VERSION 5.8 ;
BUSBITCHARS "[]" ;
DIVIDERCHAR "/" ;
UNITS
    DATABASE MICRONS 1000 ;
END UNITS

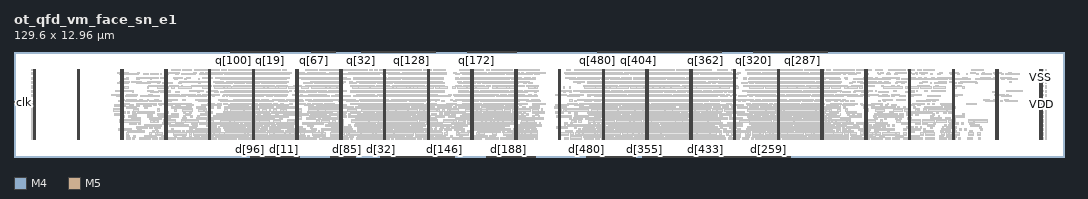
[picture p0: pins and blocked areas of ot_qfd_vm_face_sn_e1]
MACRO ot_qfd_vm_face_sn_e1
  FOREIGN ot_qfd_vm_face_sn_e1 0 0 ;
  CLASS BLOCK ;
  SIZE 129.6 BY 12.96 ;
  PIN clk
    DIRECTION INPUT ;
    USE SIGNAL ;
    PORT
      LAYER M4 ;
        RECT  0 6.672 0.084 6.696 ;
    END
  END clk
  PIN d[0]
    DIRECTION INPUT ;
    USE SIGNAL ;
    PORT
      LAYER M5 ;
        RECT  32.208 0 32.232 0.084 ;
    END
  END d[0]
  PIN d[100]
    DIRECTION INPUT ;
    USE SIGNAL ;
    PORT
      LAYER M5 ;
        RECT  29.52 0 29.544 0.084 ;
    END
  END d[100]
  PIN d[101]
    DIRECTION INPUT ;
    USE SIGNAL ;
    PORT
      LAYER M5 ;
        RECT  29.616 0 29.64 0.084 ;
    END
  END d[101]
  PIN d[102]
    DIRECTION INPUT ;
    USE SIGNAL ;
    PORT
      LAYER M5 ;
        RECT  29.712 0 29.736 0.084 ;
    END
  END d[102]
  PIN d[103]
    DIRECTION INPUT ;
    USE SIGNAL ;
    PORT
      LAYER M5 ;
        RECT  29.808 0 29.832 0.084 ;
    END
  END d[103]
  PIN d[104]
    DIRECTION INPUT ;
    USE SIGNAL ;
    PORT
      LAYER M5 ;
        RECT  29.904 0 29.928 0.084 ;
    END
  END d[104]
  PIN d[105]
    DIRECTION INPUT ;
    USE SIGNAL ;
    PORT
      LAYER M5 ;
        RECT  30 0 30.024 0.084 ;
    END
  END d[105]
  PIN d[106]
    DIRECTION INPUT ;
    USE SIGNAL ;
    PORT
      LAYER M5 ;
        RECT  30.096 0 30.12 0.084 ;
    END
  END d[106]
  PIN d[107]
    DIRECTION INPUT ;
    USE SIGNAL ;
    PORT
      LAYER M5 ;
        RECT  30.192 0 30.216 0.084 ;
    END
  END d[107]
  PIN d[108]
    DIRECTION INPUT ;
    USE SIGNAL ;
    PORT
      LAYER M5 ;
        RECT  30.288 0 30.312 0.084 ;
    END
  END d[108]
  PIN d[109]
    DIRECTION INPUT ;
    USE SIGNAL ;
    PORT
      LAYER M5 ;
        RECT  30.384 0 30.408 0.084 ;
    END
  END d[109]
  PIN d[10]
    DIRECTION INPUT ;
    USE SIGNAL ;
    PORT
      LAYER M5 ;
        RECT  33.168 0 33.192 0.084 ;
    END
  END d[10]
  PIN d[110]
    DIRECTION INPUT ;
    USE SIGNAL ;
    PORT
      LAYER M5 ;
        RECT  30.48 0 30.504 0.084 ;
    END
  END d[110]
  PIN d[111]
    DIRECTION INPUT ;
    USE SIGNAL ;
    PORT
      LAYER M5 ;
        RECT  30.576 0 30.6 0.084 ;
    END
  END d[111]
  PIN d[112]
    DIRECTION INPUT ;
    USE SIGNAL ;
    PORT
      LAYER M5 ;
        RECT  30.672 0 30.696 0.084 ;
    END
  END d[112]
  PIN d[113]
    DIRECTION INPUT ;
    USE SIGNAL ;
    PORT
      LAYER M5 ;
        RECT  30.768 0 30.792 0.084 ;
    END
  END d[113]
  PIN d[114]
    DIRECTION INPUT ;
    USE SIGNAL ;
    PORT
      LAYER M5 ;
        RECT  30.864 0 30.888 0.084 ;
    END
  END d[114]
  PIN d[115]
    DIRECTION INPUT ;
    USE SIGNAL ;
    PORT
      LAYER M5 ;
        RECT  30.96 0 30.984 0.084 ;
    END
  END d[115]
  PIN d[116]
    DIRECTION INPUT ;
    USE SIGNAL ;
    PORT
      LAYER M5 ;
        RECT  31.056 0 31.08 0.084 ;
    END
  END d[116]
  PIN d[117]
    DIRECTION INPUT ;
    USE SIGNAL ;
    PORT
      LAYER M5 ;
        RECT  31.152 0 31.176 0.084 ;
    END
  END d[117]
  PIN d[118]
    DIRECTION INPUT ;
    USE SIGNAL ;
    PORT
      LAYER M5 ;
        RECT  31.248 0 31.272 0.084 ;
    END
  END d[118]
  PIN d[119]
    DIRECTION INPUT ;
    USE SIGNAL ;
    PORT
      LAYER M5 ;
        RECT  31.344 0 31.368 0.084 ;
    END
  END d[119]
  PIN d[11]
    DIRECTION INPUT ;
    USE SIGNAL ;
    PORT
      LAYER M5 ;
        RECT  33.264 0 33.288 0.084 ;
    END
  END d[11]
  PIN d[120]
    DIRECTION INPUT ;
    USE SIGNAL ;
    PORT
      LAYER M5 ;
        RECT  31.44 0 31.464 0.084 ;
    END
  END d[120]
  PIN d[121]
    DIRECTION INPUT ;
    USE SIGNAL ;
    PORT
      LAYER M5 ;
        RECT  31.536 0 31.56 0.084 ;
    END
  END d[121]
  PIN d[122]
    DIRECTION INPUT ;
    USE SIGNAL ;
    PORT
      LAYER M5 ;
        RECT  31.632 0 31.656 0.084 ;
    END
  END d[122]
  PIN d[123]
    DIRECTION INPUT ;
    USE SIGNAL ;
    PORT
      LAYER M5 ;
        RECT  31.728 0 31.752 0.084 ;
    END
  END d[123]
  PIN d[124]
    DIRECTION INPUT ;
    USE SIGNAL ;
    PORT
      LAYER M5 ;
        RECT  31.824 0 31.848 0.084 ;
    END
  END d[124]
  PIN d[125]
    DIRECTION INPUT ;
    USE SIGNAL ;
    PORT
      LAYER M5 ;
        RECT  31.92 0 31.944 0.084 ;
    END
  END d[125]
  PIN d[126]
    DIRECTION INPUT ;
    USE SIGNAL ;
    PORT
      LAYER M5 ;
        RECT  32.016 0 32.04 0.084 ;
    END
  END d[126]
  PIN d[127]
    DIRECTION INPUT ;
    USE SIGNAL ;
    PORT
      LAYER M5 ;
        RECT  32.112 0 32.136 0.084 ;
    END
  END d[127]
  PIN d[128]
    DIRECTION INPUT ;
    USE SIGNAL ;
    PORT
      LAYER M5 ;
        RECT  51.408 0 51.432 0.084 ;
    END
  END d[128]
  PIN d[129]
    DIRECTION INPUT ;
    USE SIGNAL ;
    PORT
      LAYER M5 ;
        RECT  51.504 0 51.528 0.084 ;
    END
  END d[129]
  PIN d[12]
    DIRECTION INPUT ;
    USE SIGNAL ;
    PORT
      LAYER M5 ;
        RECT  33.36 0 33.384 0.084 ;
    END
  END d[12]
  PIN d[130]
    DIRECTION INPUT ;
    USE SIGNAL ;
    PORT
      LAYER M5 ;
        RECT  51.6 0 51.624 0.084 ;
    END
  END d[130]
  PIN d[131]
    DIRECTION INPUT ;
    USE SIGNAL ;
    PORT
      LAYER M5 ;
        RECT  51.696 0 51.72 0.084 ;
    END
  END d[131]
  PIN d[132]
    DIRECTION INPUT ;
    USE SIGNAL ;
    PORT
      LAYER M5 ;
        RECT  51.792 0 51.816 0.084 ;
    END
  END d[132]
  PIN d[133]
    DIRECTION INPUT ;
    USE SIGNAL ;
    PORT
      LAYER M5 ;
        RECT  51.888 0 51.912 0.084 ;
    END
  END d[133]
  PIN d[134]
    DIRECTION INPUT ;
    USE SIGNAL ;
    PORT
      LAYER M5 ;
        RECT  51.984 0 52.008 0.084 ;
    END
  END d[134]
  PIN d[135]
    DIRECTION INPUT ;
    USE SIGNAL ;
    PORT
      LAYER M5 ;
        RECT  52.08 0 52.104 0.084 ;
    END
  END d[135]
  PIN d[136]
    DIRECTION INPUT ;
    USE SIGNAL ;
    PORT
      LAYER M5 ;
        RECT  52.176 0 52.2 0.084 ;
    END
  END d[136]
  PIN d[137]
    DIRECTION INPUT ;
    USE SIGNAL ;
    PORT
      LAYER M5 ;
        RECT  52.272 0 52.296 0.084 ;
    END
  END d[137]
  PIN d[138]
    DIRECTION INPUT ;
    USE SIGNAL ;
    PORT
      LAYER M5 ;
        RECT  52.368 0 52.392 0.084 ;
    END
  END d[138]
  PIN d[139]
    DIRECTION INPUT ;
    USE SIGNAL ;
    PORT
      LAYER M5 ;
        RECT  52.464 0 52.488 0.084 ;
    END
  END d[139]
  PIN d[13]
    DIRECTION INPUT ;
    USE SIGNAL ;
    PORT
      LAYER M5 ;
        RECT  33.456 0 33.48 0.084 ;
    END
  END d[13]
  PIN d[140]
    DIRECTION INPUT ;
    USE SIGNAL ;
    PORT
      LAYER M5 ;
        RECT  52.56 0 52.584 0.084 ;
    END
  END d[140]
  PIN d[141]
    DIRECTION INPUT ;
    USE SIGNAL ;
    PORT
      LAYER M5 ;
        RECT  52.656 0 52.68 0.084 ;
    END
  END d[141]
  PIN d[142]
    DIRECTION INPUT ;
    USE SIGNAL ;
    PORT
      LAYER M5 ;
        RECT  52.752 0 52.776 0.084 ;
    END
  END d[142]
  PIN d[143]
    DIRECTION INPUT ;
    USE SIGNAL ;
    PORT
      LAYER M5 ;
        RECT  52.848 0 52.872 0.084 ;
    END
  END d[143]
  PIN d[144]
    DIRECTION INPUT ;
    USE SIGNAL ;
    PORT
      LAYER M5 ;
        RECT  52.944 0 52.968 0.084 ;
    END
  END d[144]
  PIN d[145]
    DIRECTION INPUT ;
    USE SIGNAL ;
    PORT
      LAYER M5 ;
        RECT  53.04 0 53.064 0.084 ;
    END
  END d[145]
  PIN d[146]
    DIRECTION INPUT ;
    USE SIGNAL ;
    PORT
      LAYER M5 ;
        RECT  53.136 0 53.16 0.084 ;
    END
  END d[146]
  PIN d[147]
    DIRECTION INPUT ;
    USE SIGNAL ;
    PORT
      LAYER M5 ;
        RECT  53.232 0 53.256 0.084 ;
    END
  END d[147]
  PIN d[148]
    DIRECTION INPUT ;
    USE SIGNAL ;
    PORT
      LAYER M5 ;
        RECT  53.328 0 53.352 0.084 ;
    END
  END d[148]
  PIN d[149]
    DIRECTION INPUT ;
    USE SIGNAL ;
    PORT
      LAYER M5 ;
        RECT  53.424 0 53.448 0.084 ;
    END
  END d[149]
  PIN d[14]
    DIRECTION INPUT ;
    USE SIGNAL ;
    PORT
      LAYER M5 ;
        RECT  33.552 0 33.576 0.084 ;
    END
  END d[14]
  PIN d[150]
    DIRECTION INPUT ;
    USE SIGNAL ;
    PORT
      LAYER M5 ;
        RECT  53.52 0 53.544 0.084 ;
    END
  END d[150]
  PIN d[151]
    DIRECTION INPUT ;
    USE SIGNAL ;
    PORT
      LAYER M5 ;
        RECT  53.616 0 53.64 0.084 ;
    END
  END d[151]
  PIN d[152]
    DIRECTION INPUT ;
    USE SIGNAL ;
    PORT
      LAYER M5 ;
        RECT  53.712 0 53.736 0.084 ;
    END
  END d[152]
  PIN d[153]
    DIRECTION INPUT ;
    USE SIGNAL ;
    PORT
      LAYER M5 ;
        RECT  53.808 0 53.832 0.084 ;
    END
  END d[153]
  PIN d[154]
    DIRECTION INPUT ;
    USE SIGNAL ;
    PORT
      LAYER M5 ;
        RECT  53.904 0 53.928 0.084 ;
    END
  END d[154]
  PIN d[155]
    DIRECTION INPUT ;
    USE SIGNAL ;
    PORT
      LAYER M5 ;
        RECT  54 0 54.024 0.084 ;
    END
  END d[155]
  PIN d[156]
    DIRECTION INPUT ;
    USE SIGNAL ;
    PORT
      LAYER M5 ;
        RECT  54.096 0 54.12 0.084 ;
    END
  END d[156]
  PIN d[157]
    DIRECTION INPUT ;
    USE SIGNAL ;
    PORT
      LAYER M5 ;
        RECT  54.192 0 54.216 0.084 ;
    END
  END d[157]
  PIN d[158]
    DIRECTION INPUT ;
    USE SIGNAL ;
    PORT
      LAYER M5 ;
        RECT  54.288 0 54.312 0.084 ;
    END
  END d[158]
  PIN d[159]
    DIRECTION INPUT ;
    USE SIGNAL ;
    PORT
      LAYER M5 ;
        RECT  54.384 0 54.408 0.084 ;
    END
  END d[159]
  PIN d[15]
    DIRECTION INPUT ;
    USE SIGNAL ;
    PORT
      LAYER M5 ;
        RECT  33.648 0 33.672 0.084 ;
    END
  END d[15]
  PIN d[160]
    DIRECTION INPUT ;
    USE SIGNAL ;
    PORT
      LAYER M5 ;
        RECT  58.32 0 58.344 0.084 ;
    END
  END d[160]
  PIN d[161]
    DIRECTION INPUT ;
    USE SIGNAL ;
    PORT
      LAYER M5 ;
        RECT  58.416 0 58.44 0.084 ;
    END
  END d[161]
  PIN d[162]
    DIRECTION INPUT ;
    USE SIGNAL ;
    PORT
      LAYER M5 ;
        RECT  58.512 0 58.536 0.084 ;
    END
  END d[162]
  PIN d[163]
    DIRECTION INPUT ;
    USE SIGNAL ;
    PORT
      LAYER M5 ;
        RECT  58.608 0 58.632 0.084 ;
    END
  END d[163]
  PIN d[164]
    DIRECTION INPUT ;
    USE SIGNAL ;
    PORT
      LAYER M5 ;
        RECT  58.704 0 58.728 0.084 ;
    END
  END d[164]
  PIN d[165]
    DIRECTION INPUT ;
    USE SIGNAL ;
    PORT
      LAYER M5 ;
        RECT  58.8 0 58.824 0.084 ;
    END
  END d[165]
  PIN d[166]
    DIRECTION INPUT ;
    USE SIGNAL ;
    PORT
      LAYER M5 ;
        RECT  58.896 0 58.92 0.084 ;
    END
  END d[166]
  PIN d[167]
    DIRECTION INPUT ;
    USE SIGNAL ;
    PORT
      LAYER M5 ;
        RECT  58.992 0 59.016 0.084 ;
    END
  END d[167]
  PIN d[168]
    DIRECTION INPUT ;
    USE SIGNAL ;
    PORT
      LAYER M5 ;
        RECT  59.088 0 59.112 0.084 ;
    END
  END d[168]
  PIN d[169]
    DIRECTION INPUT ;
    USE SIGNAL ;
    PORT
      LAYER M5 ;
        RECT  59.184 0 59.208 0.084 ;
    END
  END d[169]
  PIN d[16]
    DIRECTION INPUT ;
    USE SIGNAL ;
    PORT
      LAYER M5 ;
        RECT  33.744 0 33.768 0.084 ;
    END
  END d[16]
  PIN d[170]
    DIRECTION INPUT ;
    USE SIGNAL ;
    PORT
      LAYER M5 ;
        RECT  59.28 0 59.304 0.084 ;
    END
  END d[170]
  PIN d[171]
    DIRECTION INPUT ;
    USE SIGNAL ;
    PORT
      LAYER M5 ;
        RECT  59.376 0 59.4 0.084 ;
    END
  END d[171]
  PIN d[172]
    DIRECTION INPUT ;
    USE SIGNAL ;
    PORT
      LAYER M5 ;
        RECT  59.472 0 59.496 0.084 ;
    END
  END d[172]
  PIN d[173]
    DIRECTION INPUT ;
    USE SIGNAL ;
    PORT
      LAYER M5 ;
        RECT  59.568 0 59.592 0.084 ;
    END
  END d[173]
  PIN d[174]
    DIRECTION INPUT ;
    USE SIGNAL ;
    PORT
      LAYER M5 ;
        RECT  59.664 0 59.688 0.084 ;
    END
  END d[174]
  PIN d[175]
    DIRECTION INPUT ;
    USE SIGNAL ;
    PORT
      LAYER M5 ;
        RECT  59.76 0 59.784 0.084 ;
    END
  END d[175]
  PIN d[176]
    DIRECTION INPUT ;
    USE SIGNAL ;
    PORT
      LAYER M5 ;
        RECT  59.856 0 59.88 0.084 ;
    END
  END d[176]
  PIN d[177]
    DIRECTION INPUT ;
    USE SIGNAL ;
    PORT
      LAYER M5 ;
        RECT  59.952 0 59.976 0.084 ;
    END
  END d[177]
  PIN d[178]
    DIRECTION INPUT ;
    USE SIGNAL ;
    PORT
      LAYER M5 ;
        RECT  60.048 0 60.072 0.084 ;
    END
  END d[178]
  PIN d[179]
    DIRECTION INPUT ;
    USE SIGNAL ;
    PORT
      LAYER M5 ;
        RECT  60.144 0 60.168 0.084 ;
    END
  END d[179]
  PIN d[17]
    DIRECTION INPUT ;
    USE SIGNAL ;
    PORT
      LAYER M5 ;
        RECT  33.84 0 33.864 0.084 ;
    END
  END d[17]
  PIN d[180]
    DIRECTION INPUT ;
    USE SIGNAL ;
    PORT
      LAYER M5 ;
        RECT  60.24 0 60.264 0.084 ;
    END
  END d[180]
  PIN d[181]
    DIRECTION INPUT ;
    USE SIGNAL ;
    PORT
      LAYER M5 ;
        RECT  60.336 0 60.36 0.084 ;
    END
  END d[181]
  PIN d[182]
    DIRECTION INPUT ;
    USE SIGNAL ;
    PORT
      LAYER M5 ;
        RECT  60.432 0 60.456 0.084 ;
    END
  END d[182]
  PIN d[183]
    DIRECTION INPUT ;
    USE SIGNAL ;
    PORT
      LAYER M5 ;
        RECT  60.528 0 60.552 0.084 ;
    END
  END d[183]
  PIN d[184]
    DIRECTION INPUT ;
    USE SIGNAL ;
    PORT
      LAYER M5 ;
        RECT  60.624 0 60.648 0.084 ;
    END
  END d[184]
  PIN d[185]
    DIRECTION INPUT ;
    USE SIGNAL ;
    PORT
      LAYER M5 ;
        RECT  60.72 0 60.744 0.084 ;
    END
  END d[185]
  PIN d[186]
    DIRECTION INPUT ;
    USE SIGNAL ;
    PORT
      LAYER M5 ;
        RECT  60.816 0 60.84 0.084 ;
    END
  END d[186]
  PIN d[187]
    DIRECTION INPUT ;
    USE SIGNAL ;
    PORT
      LAYER M5 ;
        RECT  60.912 0 60.936 0.084 ;
    END
  END d[187]
  PIN d[188]
    DIRECTION INPUT ;
    USE SIGNAL ;
    PORT
      LAYER M5 ;
        RECT  61.008 0 61.032 0.084 ;
    END
  END d[188]
  PIN d[189]
    DIRECTION INPUT ;
    USE SIGNAL ;
    PORT
      LAYER M5 ;
        RECT  61.104 0 61.128 0.084 ;
    END
  END d[189]
  PIN d[18]
    DIRECTION INPUT ;
    USE SIGNAL ;
    PORT
      LAYER M5 ;
        RECT  33.936 0 33.96 0.084 ;
    END
  END d[18]
  PIN d[190]
    DIRECTION INPUT ;
    USE SIGNAL ;
    PORT
      LAYER M5 ;
        RECT  61.2 0 61.224 0.084 ;
    END
  END d[190]
  PIN d[191]
    DIRECTION INPUT ;
    USE SIGNAL ;
    PORT
      LAYER M5 ;
        RECT  61.296 0 61.32 0.084 ;
    END
  END d[191]
  PIN d[192]
    DIRECTION INPUT ;
    USE SIGNAL ;
    PORT
      LAYER M5 ;
        RECT  61.392 0 61.416 0.084 ;
    END
  END d[192]
  PIN d[193]
    DIRECTION INPUT ;
    USE SIGNAL ;
    PORT
      LAYER M5 ;
        RECT  61.488 0 61.512 0.084 ;
    END
  END d[193]
  PIN d[194]
    DIRECTION INPUT ;
    USE SIGNAL ;
    PORT
      LAYER M5 ;
        RECT  61.584 0 61.608 0.084 ;
    END
  END d[194]
  PIN d[195]
    DIRECTION INPUT ;
    USE SIGNAL ;
    PORT
      LAYER M5 ;
        RECT  61.68 0 61.704 0.084 ;
    END
  END d[195]
  PIN d[196]
    DIRECTION INPUT ;
    USE SIGNAL ;
    PORT
      LAYER M5 ;
        RECT  61.776 0 61.8 0.084 ;
    END
  END d[196]
  PIN d[197]
    DIRECTION INPUT ;
    USE SIGNAL ;
    PORT
      LAYER M5 ;
        RECT  61.872 0 61.896 0.084 ;
    END
  END d[197]
  PIN d[198]
    DIRECTION INPUT ;
    USE SIGNAL ;
    PORT
      LAYER M5 ;
        RECT  61.968 0 61.992 0.084 ;
    END
  END d[198]
  PIN d[199]
    DIRECTION INPUT ;
    USE SIGNAL ;
    PORT
      LAYER M5 ;
        RECT  62.064 0 62.088 0.084 ;
    END
  END d[199]
  PIN d[19]
    DIRECTION INPUT ;
    USE SIGNAL ;
    PORT
      LAYER M5 ;
        RECT  34.032 0 34.056 0.084 ;
    END
  END d[19]
  PIN d[1]
    DIRECTION INPUT ;
    USE SIGNAL ;
    PORT
      LAYER M5 ;
        RECT  32.304 0 32.328 0.084 ;
    END
  END d[1]
  PIN d[200]
    DIRECTION INPUT ;
    USE SIGNAL ;
    PORT
      LAYER M5 ;
        RECT  62.16 0 62.184 0.084 ;
    END
  END d[200]
  PIN d[201]
    DIRECTION INPUT ;
    USE SIGNAL ;
    PORT
      LAYER M5 ;
        RECT  62.256 0 62.28 0.084 ;
    END
  END d[201]
  PIN d[202]
    DIRECTION INPUT ;
    USE SIGNAL ;
    PORT
      LAYER M5 ;
        RECT  62.352 0 62.376 0.084 ;
    END
  END d[202]
  PIN d[203]
    DIRECTION INPUT ;
    USE SIGNAL ;
    PORT
      LAYER M5 ;
        RECT  62.448 0 62.472 0.084 ;
    END
  END d[203]
  PIN d[204]
    DIRECTION INPUT ;
    USE SIGNAL ;
    PORT
      LAYER M5 ;
        RECT  62.544 0 62.568 0.084 ;
    END
  END d[204]
  PIN d[205]
    DIRECTION INPUT ;
    USE SIGNAL ;
    PORT
      LAYER M5 ;
        RECT  62.64 0 62.664 0.084 ;
    END
  END d[205]
  PIN d[206]
    DIRECTION INPUT ;
    USE SIGNAL ;
    PORT
      LAYER M5 ;
        RECT  62.736 0 62.76 0.084 ;
    END
  END d[206]
  PIN d[207]
    DIRECTION INPUT ;
    USE SIGNAL ;
    PORT
      LAYER M5 ;
        RECT  62.832 0 62.856 0.084 ;
    END
  END d[207]
  PIN d[208]
    DIRECTION INPUT ;
    USE SIGNAL ;
    PORT
      LAYER M5 ;
        RECT  62.928 0 62.952 0.084 ;
    END
  END d[208]
  PIN d[209]
    DIRECTION INPUT ;
    USE SIGNAL ;
    PORT
      LAYER M5 ;
        RECT  63.024 0 63.048 0.084 ;
    END
  END d[209]
  PIN d[20]
    DIRECTION INPUT ;
    USE SIGNAL ;
    PORT
      LAYER M5 ;
        RECT  34.128 0 34.152 0.084 ;
    END
  END d[20]
  PIN d[210]
    DIRECTION INPUT ;
    USE SIGNAL ;
    PORT
      LAYER M5 ;
        RECT  63.12 0 63.144 0.084 ;
    END
  END d[210]
  PIN d[211]
    DIRECTION INPUT ;
    USE SIGNAL ;
    PORT
      LAYER M5 ;
        RECT  63.216 0 63.24 0.084 ;
    END
  END d[211]
  PIN d[212]
    DIRECTION INPUT ;
    USE SIGNAL ;
    PORT
      LAYER M5 ;
        RECT  63.312 0 63.336 0.084 ;
    END
  END d[212]
  PIN d[213]
    DIRECTION INPUT ;
    USE SIGNAL ;
    PORT
      LAYER M5 ;
        RECT  63.408 0 63.432 0.084 ;
    END
  END d[213]
  PIN d[214]
    DIRECTION INPUT ;
    USE SIGNAL ;
    PORT
      LAYER M5 ;
        RECT  63.504 0 63.528 0.084 ;
    END
  END d[214]
  PIN d[215]
    DIRECTION INPUT ;
    USE SIGNAL ;
    PORT
      LAYER M5 ;
        RECT  63.6 0 63.624 0.084 ;
    END
  END d[215]
  PIN d[216]
    DIRECTION INPUT ;
    USE SIGNAL ;
    PORT
      LAYER M5 ;
        RECT  63.696 0 63.72 0.084 ;
    END
  END d[216]
  PIN d[217]
    DIRECTION INPUT ;
    USE SIGNAL ;
    PORT
      LAYER M5 ;
        RECT  63.792 0 63.816 0.084 ;
    END
  END d[217]
  PIN d[218]
    DIRECTION INPUT ;
    USE SIGNAL ;
    PORT
      LAYER M5 ;
        RECT  63.888 0 63.912 0.084 ;
    END
  END d[218]
  PIN d[219]
    DIRECTION INPUT ;
    USE SIGNAL ;
    PORT
      LAYER M5 ;
        RECT  63.984 0 64.008 0.084 ;
    END
  END d[219]
  PIN d[21]
    DIRECTION INPUT ;
    USE SIGNAL ;
    PORT
      LAYER M5 ;
        RECT  34.224 0 34.248 0.084 ;
    END
  END d[21]
  PIN d[220]
    DIRECTION INPUT ;
    USE SIGNAL ;
    PORT
      LAYER M5 ;
        RECT  64.08 0 64.104 0.084 ;
    END
  END d[220]
  PIN d[221]
    DIRECTION INPUT ;
    USE SIGNAL ;
    PORT
      LAYER M5 ;
        RECT  64.176 0 64.2 0.084 ;
    END
  END d[221]
  PIN d[222]
    DIRECTION INPUT ;
    USE SIGNAL ;
    PORT
      LAYER M5 ;
        RECT  64.272 0 64.296 0.084 ;
    END
  END d[222]
  PIN d[223]
    DIRECTION INPUT ;
    USE SIGNAL ;
    PORT
      LAYER M5 ;
        RECT  64.368 0 64.392 0.084 ;
    END
  END d[223]
  PIN d[224]
    DIRECTION INPUT ;
    USE SIGNAL ;
    PORT
      LAYER M5 ;
        RECT  48.336 0 48.36 0.084 ;
    END
  END d[224]
  PIN d[225]
    DIRECTION INPUT ;
    USE SIGNAL ;
    PORT
      LAYER M5 ;
        RECT  48.432 0 48.456 0.084 ;
    END
  END d[225]
  PIN d[226]
    DIRECTION INPUT ;
    USE SIGNAL ;
    PORT
      LAYER M5 ;
        RECT  48.528 0 48.552 0.084 ;
    END
  END d[226]
  PIN d[227]
    DIRECTION INPUT ;
    USE SIGNAL ;
    PORT
      LAYER M5 ;
        RECT  48.624 0 48.648 0.084 ;
    END
  END d[227]
  PIN d[228]
    DIRECTION INPUT ;
    USE SIGNAL ;
    PORT
      LAYER M5 ;
        RECT  48.72 0 48.744 0.084 ;
    END
  END d[228]
  PIN d[229]
    DIRECTION INPUT ;
    USE SIGNAL ;
    PORT
      LAYER M5 ;
        RECT  48.816 0 48.84 0.084 ;
    END
  END d[229]
  PIN d[22]
    DIRECTION INPUT ;
    USE SIGNAL ;
    PORT
      LAYER M5 ;
        RECT  34.32 0 34.344 0.084 ;
    END
  END d[22]
  PIN d[230]
    DIRECTION INPUT ;
    USE SIGNAL ;
    PORT
      LAYER M5 ;
        RECT  48.912 0 48.936 0.084 ;
    END
  END d[230]
  PIN d[231]
    DIRECTION INPUT ;
    USE SIGNAL ;
    PORT
      LAYER M5 ;
        RECT  49.008 0 49.032 0.084 ;
    END
  END d[231]
  PIN d[232]
    DIRECTION INPUT ;
    USE SIGNAL ;
    PORT
      LAYER M5 ;
        RECT  49.104 0 49.128 0.084 ;
    END
  END d[232]
  PIN d[233]
    DIRECTION INPUT ;
    USE SIGNAL ;
    PORT
      LAYER M5 ;
        RECT  49.2 0 49.224 0.084 ;
    END
  END d[233]
  PIN d[234]
    DIRECTION INPUT ;
    USE SIGNAL ;
    PORT
      LAYER M5 ;
        RECT  49.296 0 49.32 0.084 ;
    END
  END d[234]
  PIN d[235]
    DIRECTION INPUT ;
    USE SIGNAL ;
    PORT
      LAYER M5 ;
        RECT  49.392 0 49.416 0.084 ;
    END
  END d[235]
  PIN d[236]
    DIRECTION INPUT ;
    USE SIGNAL ;
    PORT
      LAYER M5 ;
        RECT  49.488 0 49.512 0.084 ;
    END
  END d[236]
  PIN d[237]
    DIRECTION INPUT ;
    USE SIGNAL ;
    PORT
      LAYER M5 ;
        RECT  49.584 0 49.608 0.084 ;
    END
  END d[237]
  PIN d[238]
    DIRECTION INPUT ;
    USE SIGNAL ;
    PORT
      LAYER M5 ;
        RECT  49.68 0 49.704 0.084 ;
    END
  END d[238]
  PIN d[239]
    DIRECTION INPUT ;
    USE SIGNAL ;
    PORT
      LAYER M5 ;
        RECT  49.776 0 49.8 0.084 ;
    END
  END d[239]
  PIN d[23]
    DIRECTION INPUT ;
    USE SIGNAL ;
    PORT
      LAYER M5 ;
        RECT  34.416 0 34.44 0.084 ;
    END
  END d[23]
  PIN d[240]
    DIRECTION INPUT ;
    USE SIGNAL ;
    PORT
      LAYER M5 ;
        RECT  49.872 0 49.896 0.084 ;
    END
  END d[240]
  PIN d[241]
    DIRECTION INPUT ;
    USE SIGNAL ;
    PORT
      LAYER M5 ;
        RECT  49.968 0 49.992 0.084 ;
    END
  END d[241]
  PIN d[242]
    DIRECTION INPUT ;
    USE SIGNAL ;
    PORT
      LAYER M5 ;
        RECT  50.064 0 50.088 0.084 ;
    END
  END d[242]
  PIN d[243]
    DIRECTION INPUT ;
    USE SIGNAL ;
    PORT
      LAYER M5 ;
        RECT  50.16 0 50.184 0.084 ;
    END
  END d[243]
  PIN d[244]
    DIRECTION INPUT ;
    USE SIGNAL ;
    PORT
      LAYER M5 ;
        RECT  50.256 0 50.28 0.084 ;
    END
  END d[244]
  PIN d[245]
    DIRECTION INPUT ;
    USE SIGNAL ;
    PORT
      LAYER M5 ;
        RECT  50.352 0 50.376 0.084 ;
    END
  END d[245]
  PIN d[246]
    DIRECTION INPUT ;
    USE SIGNAL ;
    PORT
      LAYER M5 ;
        RECT  50.448 0 50.472 0.084 ;
    END
  END d[246]
  PIN d[247]
    DIRECTION INPUT ;
    USE SIGNAL ;
    PORT
      LAYER M5 ;
        RECT  50.544 0 50.568 0.084 ;
    END
  END d[247]
  PIN d[248]
    DIRECTION INPUT ;
    USE SIGNAL ;
    PORT
      LAYER M5 ;
        RECT  50.64 0 50.664 0.084 ;
    END
  END d[248]
  PIN d[249]
    DIRECTION INPUT ;
    USE SIGNAL ;
    PORT
      LAYER M5 ;
        RECT  50.736 0 50.76 0.084 ;
    END
  END d[249]
  PIN d[24]
    DIRECTION INPUT ;
    USE SIGNAL ;
    PORT
      LAYER M5 ;
        RECT  34.512 0 34.536 0.084 ;
    END
  END d[24]
  PIN d[250]
    DIRECTION INPUT ;
    USE SIGNAL ;
    PORT
      LAYER M5 ;
        RECT  50.832 0 50.856 0.084 ;
    END
  END d[250]
  PIN d[251]
    DIRECTION INPUT ;
    USE SIGNAL ;
    PORT
      LAYER M5 ;
        RECT  50.928 0 50.952 0.084 ;
    END
  END d[251]
  PIN d[252]
    DIRECTION INPUT ;
    USE SIGNAL ;
    PORT
      LAYER M5 ;
        RECT  51.024 0 51.048 0.084 ;
    END
  END d[252]
  PIN d[253]
    DIRECTION INPUT ;
    USE SIGNAL ;
    PORT
      LAYER M5 ;
        RECT  51.12 0 51.144 0.084 ;
    END
  END d[253]
  PIN d[254]
    DIRECTION INPUT ;
    USE SIGNAL ;
    PORT
      LAYER M5 ;
        RECT  51.216 0 51.24 0.084 ;
    END
  END d[254]
  PIN d[255]
    DIRECTION INPUT ;
    USE SIGNAL ;
    PORT
      LAYER M5 ;
        RECT  51.312 0 51.336 0.084 ;
    END
  END d[255]
  PIN d[256]
    DIRECTION INPUT ;
    USE SIGNAL ;
    PORT
      LAYER M5 ;
        RECT  92.88 0 92.904 0.084 ;
    END
  END d[256]
  PIN d[257]
    DIRECTION INPUT ;
    USE SIGNAL ;
    PORT
      LAYER M5 ;
        RECT  92.976 0 93 0.084 ;
    END
  END d[257]
  PIN d[258]
    DIRECTION INPUT ;
    USE SIGNAL ;
    PORT
      LAYER M5 ;
        RECT  93.072 0 93.096 0.084 ;
    END
  END d[258]
  PIN d[259]
    DIRECTION INPUT ;
    USE SIGNAL ;
    PORT
      LAYER M5 ;
        RECT  93.168 0 93.192 0.084 ;
    END
  END d[259]
  PIN d[25]
    DIRECTION INPUT ;
    USE SIGNAL ;
    PORT
      LAYER M5 ;
        RECT  34.608 0 34.632 0.084 ;
    END
  END d[25]
  PIN d[260]
    DIRECTION INPUT ;
    USE SIGNAL ;
    PORT
      LAYER M5 ;
        RECT  93.264 0 93.288 0.084 ;
    END
  END d[260]
  PIN d[261]
    DIRECTION INPUT ;
    USE SIGNAL ;
    PORT
      LAYER M5 ;
        RECT  93.36 0 93.384 0.084 ;
    END
  END d[261]
  PIN d[262]
    DIRECTION INPUT ;
    USE SIGNAL ;
    PORT
      LAYER M5 ;
        RECT  93.456 0 93.48 0.084 ;
    END
  END d[262]
  PIN d[263]
    DIRECTION INPUT ;
    USE SIGNAL ;
    PORT
      LAYER M5 ;
        RECT  93.552 0 93.576 0.084 ;
    END
  END d[263]
  PIN d[264]
    DIRECTION INPUT ;
    USE SIGNAL ;
    PORT
      LAYER M5 ;
        RECT  93.648 0 93.672 0.084 ;
    END
  END d[264]
  PIN d[265]
    DIRECTION INPUT ;
    USE SIGNAL ;
    PORT
      LAYER M5 ;
        RECT  93.744 0 93.768 0.084 ;
    END
  END d[265]
  PIN d[266]
    DIRECTION INPUT ;
    USE SIGNAL ;
    PORT
      LAYER M5 ;
        RECT  93.84 0 93.864 0.084 ;
    END
  END d[266]
  PIN d[267]
    DIRECTION INPUT ;
    USE SIGNAL ;
    PORT
      LAYER M5 ;
        RECT  93.936 0 93.96 0.084 ;
    END
  END d[267]
  PIN d[268]
    DIRECTION INPUT ;
    USE SIGNAL ;
    PORT
      LAYER M5 ;
        RECT  94.032 0 94.056 0.084 ;
    END
  END d[268]
  PIN d[269]
    DIRECTION INPUT ;
    USE SIGNAL ;
    PORT
      LAYER M5 ;
        RECT  94.128 0 94.152 0.084 ;
    END
  END d[269]
  PIN d[26]
    DIRECTION INPUT ;
    USE SIGNAL ;
    PORT
      LAYER M5 ;
        RECT  34.704 0 34.728 0.084 ;
    END
  END d[26]
  PIN d[270]
    DIRECTION INPUT ;
    USE SIGNAL ;
    PORT
      LAYER M5 ;
        RECT  94.224 0 94.248 0.084 ;
    END
  END d[270]
  PIN d[271]
    DIRECTION INPUT ;
    USE SIGNAL ;
    PORT
      LAYER M5 ;
        RECT  94.32 0 94.344 0.084 ;
    END
  END d[271]
  PIN d[272]
    DIRECTION INPUT ;
    USE SIGNAL ;
    PORT
      LAYER M5 ;
        RECT  94.416 0 94.44 0.084 ;
    END
  END d[272]
  PIN d[273]
    DIRECTION INPUT ;
    USE SIGNAL ;
    PORT
      LAYER M5 ;
        RECT  94.512 0 94.536 0.084 ;
    END
  END d[273]
  PIN d[274]
    DIRECTION INPUT ;
    USE SIGNAL ;
    PORT
      LAYER M5 ;
        RECT  94.608 0 94.632 0.084 ;
    END
  END d[274]
  PIN d[275]
    DIRECTION INPUT ;
    USE SIGNAL ;
    PORT
      LAYER M5 ;
        RECT  94.704 0 94.728 0.084 ;
    END
  END d[275]
  PIN d[276]
    DIRECTION INPUT ;
    USE SIGNAL ;
    PORT
      LAYER M5 ;
        RECT  94.8 0 94.824 0.084 ;
    END
  END d[276]
  PIN d[277]
    DIRECTION INPUT ;
    USE SIGNAL ;
    PORT
      LAYER M5 ;
        RECT  94.896 0 94.92 0.084 ;
    END
  END d[277]
  PIN d[278]
    DIRECTION INPUT ;
    USE SIGNAL ;
    PORT
      LAYER M5 ;
        RECT  94.992 0 95.016 0.084 ;
    END
  END d[278]
  PIN d[279]
    DIRECTION INPUT ;
    USE SIGNAL ;
    PORT
      LAYER M5 ;
        RECT  95.088 0 95.112 0.084 ;
    END
  END d[279]
  PIN d[27]
    DIRECTION INPUT ;
    USE SIGNAL ;
    PORT
      LAYER M5 ;
        RECT  34.8 0 34.824 0.084 ;
    END
  END d[27]
  PIN d[280]
    DIRECTION INPUT ;
    USE SIGNAL ;
    PORT
      LAYER M5 ;
        RECT  95.184 0 95.208 0.084 ;
    END
  END d[280]
  PIN d[281]
    DIRECTION INPUT ;
    USE SIGNAL ;
    PORT
      LAYER M5 ;
        RECT  95.28 0 95.304 0.084 ;
    END
  END d[281]
  PIN d[282]
    DIRECTION INPUT ;
    USE SIGNAL ;
    PORT
      LAYER M5 ;
        RECT  95.376 0 95.4 0.084 ;
    END
  END d[282]
  PIN d[283]
    DIRECTION INPUT ;
    USE SIGNAL ;
    PORT
      LAYER M5 ;
        RECT  95.472 0 95.496 0.084 ;
    END
  END d[283]
  PIN d[284]
    DIRECTION INPUT ;
    USE SIGNAL ;
    PORT
      LAYER M5 ;
        RECT  95.568 0 95.592 0.084 ;
    END
  END d[284]
  PIN d[285]
    DIRECTION INPUT ;
    USE SIGNAL ;
    PORT
      LAYER M5 ;
        RECT  95.664 0 95.688 0.084 ;
    END
  END d[285]
  PIN d[286]
    DIRECTION INPUT ;
    USE SIGNAL ;
    PORT
      LAYER M5 ;
        RECT  95.76 0 95.784 0.084 ;
    END
  END d[286]
  PIN d[287]
    DIRECTION INPUT ;
    USE SIGNAL ;
    PORT
      LAYER M5 ;
        RECT  95.856 0 95.88 0.084 ;
    END
  END d[287]
  PIN d[288]
    DIRECTION INPUT ;
    USE SIGNAL ;
    PORT
      LAYER M5 ;
        RECT  89.808 0 89.832 0.084 ;
    END
  END d[288]
  PIN d[289]
    DIRECTION INPUT ;
    USE SIGNAL ;
    PORT
      LAYER M5 ;
        RECT  89.904 0 89.928 0.084 ;
    END
  END d[289]
  PIN d[28]
    DIRECTION INPUT ;
    USE SIGNAL ;
    PORT
      LAYER M5 ;
        RECT  34.896 0 34.92 0.084 ;
    END
  END d[28]
  PIN d[290]
    DIRECTION INPUT ;
    USE SIGNAL ;
    PORT
      LAYER M5 ;
        RECT  90 0 90.024 0.084 ;
    END
  END d[290]
  PIN d[291]
    DIRECTION INPUT ;
    USE SIGNAL ;
    PORT
      LAYER M5 ;
        RECT  90.096 0 90.12 0.084 ;
    END
  END d[291]
  PIN d[292]
    DIRECTION INPUT ;
    USE SIGNAL ;
    PORT
      LAYER M5 ;
        RECT  90.192 0 90.216 0.084 ;
    END
  END d[292]
  PIN d[293]
    DIRECTION INPUT ;
    USE SIGNAL ;
    PORT
      LAYER M5 ;
        RECT  90.288 0 90.312 0.084 ;
    END
  END d[293]
  PIN d[294]
    DIRECTION INPUT ;
    USE SIGNAL ;
    PORT
      LAYER M5 ;
        RECT  90.384 0 90.408 0.084 ;
    END
  END d[294]
  PIN d[295]
    DIRECTION INPUT ;
    USE SIGNAL ;
    PORT
      LAYER M5 ;
        RECT  90.48 0 90.504 0.084 ;
    END
  END d[295]
  PIN d[296]
    DIRECTION INPUT ;
    USE SIGNAL ;
    PORT
      LAYER M5 ;
        RECT  90.576 0 90.6 0.084 ;
    END
  END d[296]
  PIN d[297]
    DIRECTION INPUT ;
    USE SIGNAL ;
    PORT
      LAYER M5 ;
        RECT  90.672 0 90.696 0.084 ;
    END
  END d[297]
  PIN d[298]
    DIRECTION INPUT ;
    USE SIGNAL ;
    PORT
      LAYER M5 ;
        RECT  90.768 0 90.792 0.084 ;
    END
  END d[298]
  PIN d[299]
    DIRECTION INPUT ;
    USE SIGNAL ;
    PORT
      LAYER M5 ;
        RECT  90.864 0 90.888 0.084 ;
    END
  END d[299]
  PIN d[29]
    DIRECTION INPUT ;
    USE SIGNAL ;
    PORT
      LAYER M5 ;
        RECT  34.992 0 35.016 0.084 ;
    END
  END d[29]
  PIN d[2]
    DIRECTION INPUT ;
    USE SIGNAL ;
    PORT
      LAYER M5 ;
        RECT  32.4 0 32.424 0.084 ;
    END
  END d[2]
  PIN d[300]
    DIRECTION INPUT ;
    USE SIGNAL ;
    PORT
      LAYER M5 ;
        RECT  90.96 0 90.984 0.084 ;
    END
  END d[300]
  PIN d[301]
    DIRECTION INPUT ;
    USE SIGNAL ;
    PORT
      LAYER M5 ;
        RECT  91.056 0 91.08 0.084 ;
    END
  END d[301]
  PIN d[302]
    DIRECTION INPUT ;
    USE SIGNAL ;
    PORT
      LAYER M5 ;
        RECT  91.152 0 91.176 0.084 ;
    END
  END d[302]
  PIN d[303]
    DIRECTION INPUT ;
    USE SIGNAL ;
    PORT
      LAYER M5 ;
        RECT  91.248 0 91.272 0.084 ;
    END
  END d[303]
  PIN d[304]
    DIRECTION INPUT ;
    USE SIGNAL ;
    PORT
      LAYER M5 ;
        RECT  91.344 0 91.368 0.084 ;
    END
  END d[304]
  PIN d[305]
    DIRECTION INPUT ;
    USE SIGNAL ;
    PORT
      LAYER M5 ;
        RECT  91.44 0 91.464 0.084 ;
    END
  END d[305]
  PIN d[306]
    DIRECTION INPUT ;
    USE SIGNAL ;
    PORT
      LAYER M5 ;
        RECT  91.536 0 91.56 0.084 ;
    END
  END d[306]
  PIN d[307]
    DIRECTION INPUT ;
    USE SIGNAL ;
    PORT
      LAYER M5 ;
        RECT  91.632 0 91.656 0.084 ;
    END
  END d[307]
  PIN d[308]
    DIRECTION INPUT ;
    USE SIGNAL ;
    PORT
      LAYER M5 ;
        RECT  91.728 0 91.752 0.084 ;
    END
  END d[308]
  PIN d[309]
    DIRECTION INPUT ;
    USE SIGNAL ;
    PORT
      LAYER M5 ;
        RECT  91.824 0 91.848 0.084 ;
    END
  END d[309]
  PIN d[30]
    DIRECTION INPUT ;
    USE SIGNAL ;
    PORT
      LAYER M5 ;
        RECT  35.088 0 35.112 0.084 ;
    END
  END d[30]
  PIN d[310]
    DIRECTION INPUT ;
    USE SIGNAL ;
    PORT
      LAYER M5 ;
        RECT  91.92 0 91.944 0.084 ;
    END
  END d[310]
  PIN d[311]
    DIRECTION INPUT ;
    USE SIGNAL ;
    PORT
      LAYER M5 ;
        RECT  92.016 0 92.04 0.084 ;
    END
  END d[311]
  PIN d[312]
    DIRECTION INPUT ;
    USE SIGNAL ;
    PORT
      LAYER M5 ;
        RECT  92.112 0 92.136 0.084 ;
    END
  END d[312]
  PIN d[313]
    DIRECTION INPUT ;
    USE SIGNAL ;
    PORT
      LAYER M5 ;
        RECT  92.208 0 92.232 0.084 ;
    END
  END d[313]
  PIN d[314]
    DIRECTION INPUT ;
    USE SIGNAL ;
    PORT
      LAYER M5 ;
        RECT  92.304 0 92.328 0.084 ;
    END
  END d[314]
  PIN d[315]
    DIRECTION INPUT ;
    USE SIGNAL ;
    PORT
      LAYER M5 ;
        RECT  92.4 0 92.424 0.084 ;
    END
  END d[315]
  PIN d[316]
    DIRECTION INPUT ;
    USE SIGNAL ;
    PORT
      LAYER M5 ;
        RECT  92.496 0 92.52 0.084 ;
    END
  END d[316]
  PIN d[317]
    DIRECTION INPUT ;
    USE SIGNAL ;
    PORT
      LAYER M5 ;
        RECT  92.592 0 92.616 0.084 ;
    END
  END d[317]
  PIN d[318]
    DIRECTION INPUT ;
    USE SIGNAL ;
    PORT
      LAYER M5 ;
        RECT  92.688 0 92.712 0.084 ;
    END
  END d[318]
  PIN d[319]
    DIRECTION INPUT ;
    USE SIGNAL ;
    PORT
      LAYER M5 ;
        RECT  92.784 0 92.808 0.084 ;
    END
  END d[319]
  PIN d[31]
    DIRECTION INPUT ;
    USE SIGNAL ;
    PORT
      LAYER M5 ;
        RECT  35.184 0 35.208 0.084 ;
    END
  END d[31]
  PIN d[320]
    DIRECTION INPUT ;
    USE SIGNAL ;
    PORT
      LAYER M5 ;
        RECT  86.736 0 86.76 0.084 ;
    END
  END d[320]
  PIN d[321]
    DIRECTION INPUT ;
    USE SIGNAL ;
    PORT
      LAYER M5 ;
        RECT  86.832 0 86.856 0.084 ;
    END
  END d[321]
  PIN d[322]
    DIRECTION INPUT ;
    USE SIGNAL ;
    PORT
      LAYER M5 ;
        RECT  86.928 0 86.952 0.084 ;
    END
  END d[322]
  PIN d[323]
    DIRECTION INPUT ;
    USE SIGNAL ;
    PORT
      LAYER M5 ;
        RECT  87.024 0 87.048 0.084 ;
    END
  END d[323]
  PIN d[324]
    DIRECTION INPUT ;
    USE SIGNAL ;
    PORT
      LAYER M5 ;
        RECT  87.12 0 87.144 0.084 ;
    END
  END d[324]
  PIN d[325]
    DIRECTION INPUT ;
    USE SIGNAL ;
    PORT
      LAYER M5 ;
        RECT  87.216 0 87.24 0.084 ;
    END
  END d[325]
  PIN d[326]
    DIRECTION INPUT ;
    USE SIGNAL ;
    PORT
      LAYER M5 ;
        RECT  87.312 0 87.336 0.084 ;
    END
  END d[326]
  PIN d[327]
    DIRECTION INPUT ;
    USE SIGNAL ;
    PORT
      LAYER M5 ;
        RECT  87.408 0 87.432 0.084 ;
    END
  END d[327]
  PIN d[328]
    DIRECTION INPUT ;
    USE SIGNAL ;
    PORT
      LAYER M5 ;
        RECT  87.504 0 87.528 0.084 ;
    END
  END d[328]
  PIN d[329]
    DIRECTION INPUT ;
    USE SIGNAL ;
    PORT
      LAYER M5 ;
        RECT  87.6 0 87.624 0.084 ;
    END
  END d[329]
  PIN d[32]
    DIRECTION INPUT ;
    USE SIGNAL ;
    PORT
      LAYER M5 ;
        RECT  45.264 0 45.288 0.084 ;
    END
  END d[32]
  PIN d[330]
    DIRECTION INPUT ;
    USE SIGNAL ;
    PORT
      LAYER M5 ;
        RECT  87.696 0 87.72 0.084 ;
    END
  END d[330]
  PIN d[331]
    DIRECTION INPUT ;
    USE SIGNAL ;
    PORT
      LAYER M5 ;
        RECT  87.792 0 87.816 0.084 ;
    END
  END d[331]
  PIN d[332]
    DIRECTION INPUT ;
    USE SIGNAL ;
    PORT
      LAYER M5 ;
        RECT  87.888 0 87.912 0.084 ;
    END
  END d[332]
  PIN d[333]
    DIRECTION INPUT ;
    USE SIGNAL ;
    PORT
      LAYER M5 ;
        RECT  87.984 0 88.008 0.084 ;
    END
  END d[333]
  PIN d[334]
    DIRECTION INPUT ;
    USE SIGNAL ;
    PORT
      LAYER M5 ;
        RECT  88.08 0 88.104 0.084 ;
    END
  END d[334]
  PIN d[335]
    DIRECTION INPUT ;
    USE SIGNAL ;
    PORT
      LAYER M5 ;
        RECT  88.176 0 88.2 0.084 ;
    END
  END d[335]
  PIN d[336]
    DIRECTION INPUT ;
    USE SIGNAL ;
    PORT
      LAYER M5 ;
        RECT  88.272 0 88.296 0.084 ;
    END
  END d[336]
  PIN d[337]
    DIRECTION INPUT ;
    USE SIGNAL ;
    PORT
      LAYER M5 ;
        RECT  88.368 0 88.392 0.084 ;
    END
  END d[337]
  PIN d[338]
    DIRECTION INPUT ;
    USE SIGNAL ;
    PORT
      LAYER M5 ;
        RECT  88.464 0 88.488 0.084 ;
    END
  END d[338]
  PIN d[339]
    DIRECTION INPUT ;
    USE SIGNAL ;
    PORT
      LAYER M5 ;
        RECT  88.56 0 88.584 0.084 ;
    END
  END d[339]
  PIN d[33]
    DIRECTION INPUT ;
    USE SIGNAL ;
    PORT
      LAYER M5 ;
        RECT  45.36 0 45.384 0.084 ;
    END
  END d[33]
  PIN d[340]
    DIRECTION INPUT ;
    USE SIGNAL ;
    PORT
      LAYER M5 ;
        RECT  88.656 0 88.68 0.084 ;
    END
  END d[340]
  PIN d[341]
    DIRECTION INPUT ;
    USE SIGNAL ;
    PORT
      LAYER M5 ;
        RECT  88.752 0 88.776 0.084 ;
    END
  END d[341]
  PIN d[342]
    DIRECTION INPUT ;
    USE SIGNAL ;
    PORT
      LAYER M5 ;
        RECT  88.848 0 88.872 0.084 ;
    END
  END d[342]
  PIN d[343]
    DIRECTION INPUT ;
    USE SIGNAL ;
    PORT
      LAYER M5 ;
        RECT  88.944 0 88.968 0.084 ;
    END
  END d[343]
  PIN d[344]
    DIRECTION INPUT ;
    USE SIGNAL ;
    PORT
      LAYER M5 ;
        RECT  89.04 0 89.064 0.084 ;
    END
  END d[344]
  PIN d[345]
    DIRECTION INPUT ;
    USE SIGNAL ;
    PORT
      LAYER M5 ;
        RECT  89.136 0 89.16 0.084 ;
    END
  END d[345]
  PIN d[346]
    DIRECTION INPUT ;
    USE SIGNAL ;
    PORT
      LAYER M5 ;
        RECT  89.232 0 89.256 0.084 ;
    END
  END d[346]
  PIN d[347]
    DIRECTION INPUT ;
    USE SIGNAL ;
    PORT
      LAYER M5 ;
        RECT  89.328 0 89.352 0.084 ;
    END
  END d[347]
  PIN d[348]
    DIRECTION INPUT ;
    USE SIGNAL ;
    PORT
      LAYER M5 ;
        RECT  89.424 0 89.448 0.084 ;
    END
  END d[348]
  PIN d[349]
    DIRECTION INPUT ;
    USE SIGNAL ;
    PORT
      LAYER M5 ;
        RECT  89.52 0 89.544 0.084 ;
    END
  END d[349]
  PIN d[34]
    DIRECTION INPUT ;
    USE SIGNAL ;
    PORT
      LAYER M5 ;
        RECT  45.456 0 45.48 0.084 ;
    END
  END d[34]
  PIN d[350]
    DIRECTION INPUT ;
    USE SIGNAL ;
    PORT
      LAYER M5 ;
        RECT  89.616 0 89.64 0.084 ;
    END
  END d[350]
  PIN d[351]
    DIRECTION INPUT ;
    USE SIGNAL ;
    PORT
      LAYER M5 ;
        RECT  89.712 0 89.736 0.084 ;
    END
  END d[351]
  PIN d[352]
    DIRECTION INPUT ;
    USE SIGNAL ;
    PORT
      LAYER M5 ;
        RECT  77.52 0 77.544 0.084 ;
    END
  END d[352]
  PIN d[353]
    DIRECTION INPUT ;
    USE SIGNAL ;
    PORT
      LAYER M5 ;
        RECT  77.616 0 77.64 0.084 ;
    END
  END d[353]
  PIN d[354]
    DIRECTION INPUT ;
    USE SIGNAL ;
    PORT
      LAYER M5 ;
        RECT  77.712 0 77.736 0.084 ;
    END
  END d[354]
  PIN d[355]
    DIRECTION INPUT ;
    USE SIGNAL ;
    PORT
      LAYER M5 ;
        RECT  77.808 0 77.832 0.084 ;
    END
  END d[355]
  PIN d[356]
    DIRECTION INPUT ;
    USE SIGNAL ;
    PORT
      LAYER M5 ;
        RECT  77.904 0 77.928 0.084 ;
    END
  END d[356]
  PIN d[357]
    DIRECTION INPUT ;
    USE SIGNAL ;
    PORT
      LAYER M5 ;
        RECT  78 0 78.024 0.084 ;
    END
  END d[357]
  PIN d[358]
    DIRECTION INPUT ;
    USE SIGNAL ;
    PORT
      LAYER M5 ;
        RECT  78.096 0 78.12 0.084 ;
    END
  END d[358]
  PIN d[359]
    DIRECTION INPUT ;
    USE SIGNAL ;
    PORT
      LAYER M5 ;
        RECT  78.192 0 78.216 0.084 ;
    END
  END d[359]
  PIN d[35]
    DIRECTION INPUT ;
    USE SIGNAL ;
    PORT
      LAYER M5 ;
        RECT  45.552 0 45.576 0.084 ;
    END
  END d[35]
  PIN d[360]
    DIRECTION INPUT ;
    USE SIGNAL ;
    PORT
      LAYER M5 ;
        RECT  78.288 0 78.312 0.084 ;
    END
  END d[360]
  PIN d[361]
    DIRECTION INPUT ;
    USE SIGNAL ;
    PORT
      LAYER M5 ;
        RECT  78.384 0 78.408 0.084 ;
    END
  END d[361]
  PIN d[362]
    DIRECTION INPUT ;
    USE SIGNAL ;
    PORT
      LAYER M5 ;
        RECT  78.48 0 78.504 0.084 ;
    END
  END d[362]
  PIN d[363]
    DIRECTION INPUT ;
    USE SIGNAL ;
    PORT
      LAYER M5 ;
        RECT  78.576 0 78.6 0.084 ;
    END
  END d[363]
  PIN d[364]
    DIRECTION INPUT ;
    USE SIGNAL ;
    PORT
      LAYER M5 ;
        RECT  78.672 0 78.696 0.084 ;
    END
  END d[364]
  PIN d[365]
    DIRECTION INPUT ;
    USE SIGNAL ;
    PORT
      LAYER M5 ;
        RECT  78.768 0 78.792 0.084 ;
    END
  END d[365]
  PIN d[366]
    DIRECTION INPUT ;
    USE SIGNAL ;
    PORT
      LAYER M5 ;
        RECT  78.864 0 78.888 0.084 ;
    END
  END d[366]
  PIN d[367]
    DIRECTION INPUT ;
    USE SIGNAL ;
    PORT
      LAYER M5 ;
        RECT  78.96 0 78.984 0.084 ;
    END
  END d[367]
  PIN d[368]
    DIRECTION INPUT ;
    USE SIGNAL ;
    PORT
      LAYER M5 ;
        RECT  79.056 0 79.08 0.084 ;
    END
  END d[368]
  PIN d[369]
    DIRECTION INPUT ;
    USE SIGNAL ;
    PORT
      LAYER M5 ;
        RECT  79.152 0 79.176 0.084 ;
    END
  END d[369]
  PIN d[36]
    DIRECTION INPUT ;
    USE SIGNAL ;
    PORT
      LAYER M5 ;
        RECT  45.648 0 45.672 0.084 ;
    END
  END d[36]
  PIN d[370]
    DIRECTION INPUT ;
    USE SIGNAL ;
    PORT
      LAYER M5 ;
        RECT  79.248 0 79.272 0.084 ;
    END
  END d[370]
  PIN d[371]
    DIRECTION INPUT ;
    USE SIGNAL ;
    PORT
      LAYER M5 ;
        RECT  79.344 0 79.368 0.084 ;
    END
  END d[371]
  PIN d[372]
    DIRECTION INPUT ;
    USE SIGNAL ;
    PORT
      LAYER M5 ;
        RECT  79.44 0 79.464 0.084 ;
    END
  END d[372]
  PIN d[373]
    DIRECTION INPUT ;
    USE SIGNAL ;
    PORT
      LAYER M5 ;
        RECT  79.536 0 79.56 0.084 ;
    END
  END d[373]
  PIN d[374]
    DIRECTION INPUT ;
    USE SIGNAL ;
    PORT
      LAYER M5 ;
        RECT  79.632 0 79.656 0.084 ;
    END
  END d[374]
  PIN d[375]
    DIRECTION INPUT ;
    USE SIGNAL ;
    PORT
      LAYER M5 ;
        RECT  79.728 0 79.752 0.084 ;
    END
  END d[375]
  PIN d[376]
    DIRECTION INPUT ;
    USE SIGNAL ;
    PORT
      LAYER M5 ;
        RECT  79.824 0 79.848 0.084 ;
    END
  END d[376]
  PIN d[377]
    DIRECTION INPUT ;
    USE SIGNAL ;
    PORT
      LAYER M5 ;
        RECT  79.92 0 79.944 0.084 ;
    END
  END d[377]
  PIN d[378]
    DIRECTION INPUT ;
    USE SIGNAL ;
    PORT
      LAYER M5 ;
        RECT  80.016 0 80.04 0.084 ;
    END
  END d[378]
  PIN d[379]
    DIRECTION INPUT ;
    USE SIGNAL ;
    PORT
      LAYER M5 ;
        RECT  80.112 0 80.136 0.084 ;
    END
  END d[379]
  PIN d[37]
    DIRECTION INPUT ;
    USE SIGNAL ;
    PORT
      LAYER M5 ;
        RECT  45.744 0 45.768 0.084 ;
    END
  END d[37]
  PIN d[380]
    DIRECTION INPUT ;
    USE SIGNAL ;
    PORT
      LAYER M5 ;
        RECT  80.208 0 80.232 0.084 ;
    END
  END d[380]
  PIN d[381]
    DIRECTION INPUT ;
    USE SIGNAL ;
    PORT
      LAYER M5 ;
        RECT  80.304 0 80.328 0.084 ;
    END
  END d[381]
  PIN d[382]
    DIRECTION INPUT ;
    USE SIGNAL ;
    PORT
      LAYER M5 ;
        RECT  80.4 0 80.424 0.084 ;
    END
  END d[382]
  PIN d[383]
    DIRECTION INPUT ;
    USE SIGNAL ;
    PORT
      LAYER M5 ;
        RECT  80.496 0 80.52 0.084 ;
    END
  END d[383]
  PIN d[384]
    DIRECTION INPUT ;
    USE SIGNAL ;
    PORT
      LAYER M5 ;
        RECT  73.68 0 73.704 0.084 ;
    END
  END d[384]
  PIN d[385]
    DIRECTION INPUT ;
    USE SIGNAL ;
    PORT
      LAYER M5 ;
        RECT  73.776 0 73.8 0.084 ;
    END
  END d[385]
  PIN d[386]
    DIRECTION INPUT ;
    USE SIGNAL ;
    PORT
      LAYER M5 ;
        RECT  73.872 0 73.896 0.084 ;
    END
  END d[386]
  PIN d[387]
    DIRECTION INPUT ;
    USE SIGNAL ;
    PORT
      LAYER M5 ;
        RECT  73.968 0 73.992 0.084 ;
    END
  END d[387]
  PIN d[388]
    DIRECTION INPUT ;
    USE SIGNAL ;
    PORT
      LAYER M5 ;
        RECT  74.064 0 74.088 0.084 ;
    END
  END d[388]
  PIN d[389]
    DIRECTION INPUT ;
    USE SIGNAL ;
    PORT
      LAYER M5 ;
        RECT  74.16 0 74.184 0.084 ;
    END
  END d[389]
  PIN d[38]
    DIRECTION INPUT ;
    USE SIGNAL ;
    PORT
      LAYER M5 ;
        RECT  45.84 0 45.864 0.084 ;
    END
  END d[38]
  PIN d[390]
    DIRECTION INPUT ;
    USE SIGNAL ;
    PORT
      LAYER M5 ;
        RECT  74.256 0 74.28 0.084 ;
    END
  END d[390]
  PIN d[391]
    DIRECTION INPUT ;
    USE SIGNAL ;
    PORT
      LAYER M5 ;
        RECT  74.352 0 74.376 0.084 ;
    END
  END d[391]
  PIN d[392]
    DIRECTION INPUT ;
    USE SIGNAL ;
    PORT
      LAYER M5 ;
        RECT  74.448 0 74.472 0.084 ;
    END
  END d[392]
  PIN d[393]
    DIRECTION INPUT ;
    USE SIGNAL ;
    PORT
      LAYER M5 ;
        RECT  74.544 0 74.568 0.084 ;
    END
  END d[393]
  PIN d[394]
    DIRECTION INPUT ;
    USE SIGNAL ;
    PORT
      LAYER M5 ;
        RECT  74.64 0 74.664 0.084 ;
    END
  END d[394]
  PIN d[395]
    DIRECTION INPUT ;
    USE SIGNAL ;
    PORT
      LAYER M5 ;
        RECT  74.736 0 74.76 0.084 ;
    END
  END d[395]
  PIN d[396]
    DIRECTION INPUT ;
    USE SIGNAL ;
    PORT
      LAYER M5 ;
        RECT  74.832 0 74.856 0.084 ;
    END
  END d[396]
  PIN d[397]
    DIRECTION INPUT ;
    USE SIGNAL ;
    PORT
      LAYER M5 ;
        RECT  74.928 0 74.952 0.084 ;
    END
  END d[397]
  PIN d[398]
    DIRECTION INPUT ;
    USE SIGNAL ;
    PORT
      LAYER M5 ;
        RECT  75.024 0 75.048 0.084 ;
    END
  END d[398]
  PIN d[399]
    DIRECTION INPUT ;
    USE SIGNAL ;
    PORT
      LAYER M5 ;
        RECT  75.12 0 75.144 0.084 ;
    END
  END d[399]
  PIN d[39]
    DIRECTION INPUT ;
    USE SIGNAL ;
    PORT
      LAYER M5 ;
        RECT  45.936 0 45.96 0.084 ;
    END
  END d[39]
  PIN d[3]
    DIRECTION INPUT ;
    USE SIGNAL ;
    PORT
      LAYER M5 ;
        RECT  32.496 0 32.52 0.084 ;
    END
  END d[3]
  PIN d[400]
    DIRECTION INPUT ;
    USE SIGNAL ;
    PORT
      LAYER M5 ;
        RECT  75.216 0 75.24 0.084 ;
    END
  END d[400]
  PIN d[401]
    DIRECTION INPUT ;
    USE SIGNAL ;
    PORT
      LAYER M5 ;
        RECT  75.312 0 75.336 0.084 ;
    END
  END d[401]
  PIN d[402]
    DIRECTION INPUT ;
    USE SIGNAL ;
    PORT
      LAYER M5 ;
        RECT  75.408 0 75.432 0.084 ;
    END
  END d[402]
  PIN d[403]
    DIRECTION INPUT ;
    USE SIGNAL ;
    PORT
      LAYER M5 ;
        RECT  75.504 0 75.528 0.084 ;
    END
  END d[403]
  PIN d[404]
    DIRECTION INPUT ;
    USE SIGNAL ;
    PORT
      LAYER M5 ;
        RECT  75.6 0 75.624 0.084 ;
    END
  END d[404]
  PIN d[405]
    DIRECTION INPUT ;
    USE SIGNAL ;
    PORT
      LAYER M5 ;
        RECT  75.696 0 75.72 0.084 ;
    END
  END d[405]
  PIN d[406]
    DIRECTION INPUT ;
    USE SIGNAL ;
    PORT
      LAYER M5 ;
        RECT  75.792 0 75.816 0.084 ;
    END
  END d[406]
  PIN d[407]
    DIRECTION INPUT ;
    USE SIGNAL ;
    PORT
      LAYER M5 ;
        RECT  75.888 0 75.912 0.084 ;
    END
  END d[407]
  PIN d[408]
    DIRECTION INPUT ;
    USE SIGNAL ;
    PORT
      LAYER M5 ;
        RECT  75.984 0 76.008 0.084 ;
    END
  END d[408]
  PIN d[409]
    DIRECTION INPUT ;
    USE SIGNAL ;
    PORT
      LAYER M5 ;
        RECT  76.08 0 76.104 0.084 ;
    END
  END d[409]
  PIN d[40]
    DIRECTION INPUT ;
    USE SIGNAL ;
    PORT
      LAYER M5 ;
        RECT  46.032 0 46.056 0.084 ;
    END
  END d[40]
  PIN d[410]
    DIRECTION INPUT ;
    USE SIGNAL ;
    PORT
      LAYER M5 ;
        RECT  76.176 0 76.2 0.084 ;
    END
  END d[410]
  PIN d[411]
    DIRECTION INPUT ;
    USE SIGNAL ;
    PORT
      LAYER M5 ;
        RECT  76.272 0 76.296 0.084 ;
    END
  END d[411]
  PIN d[412]
    DIRECTION INPUT ;
    USE SIGNAL ;
    PORT
      LAYER M5 ;
        RECT  76.368 0 76.392 0.084 ;
    END
  END d[412]
  PIN d[413]
    DIRECTION INPUT ;
    USE SIGNAL ;
    PORT
      LAYER M5 ;
        RECT  76.464 0 76.488 0.084 ;
    END
  END d[413]
  PIN d[414]
    DIRECTION INPUT ;
    USE SIGNAL ;
    PORT
      LAYER M5 ;
        RECT  76.56 0 76.584 0.084 ;
    END
  END d[414]
  PIN d[415]
    DIRECTION INPUT ;
    USE SIGNAL ;
    PORT
      LAYER M5 ;
        RECT  76.656 0 76.68 0.084 ;
    END
  END d[415]
  PIN d[416]
    DIRECTION INPUT ;
    USE SIGNAL ;
    PORT
      LAYER M5 ;
        RECT  83.664 0 83.688 0.084 ;
    END
  END d[416]
  PIN d[417]
    DIRECTION INPUT ;
    USE SIGNAL ;
    PORT
      LAYER M5 ;
        RECT  83.76 0 83.784 0.084 ;
    END
  END d[417]
  PIN d[418]
    DIRECTION INPUT ;
    USE SIGNAL ;
    PORT
      LAYER M5 ;
        RECT  83.856 0 83.88 0.084 ;
    END
  END d[418]
  PIN d[419]
    DIRECTION INPUT ;
    USE SIGNAL ;
    PORT
      LAYER M5 ;
        RECT  83.952 0 83.976 0.084 ;
    END
  END d[419]
  PIN d[41]
    DIRECTION INPUT ;
    USE SIGNAL ;
    PORT
      LAYER M5 ;
        RECT  46.128 0 46.152 0.084 ;
    END
  END d[41]
  PIN d[420]
    DIRECTION INPUT ;
    USE SIGNAL ;
    PORT
      LAYER M5 ;
        RECT  84.048 0 84.072 0.084 ;
    END
  END d[420]
  PIN d[421]
    DIRECTION INPUT ;
    USE SIGNAL ;
    PORT
      LAYER M5 ;
        RECT  84.144 0 84.168 0.084 ;
    END
  END d[421]
  PIN d[422]
    DIRECTION INPUT ;
    USE SIGNAL ;
    PORT
      LAYER M5 ;
        RECT  84.24 0 84.264 0.084 ;
    END
  END d[422]
  PIN d[423]
    DIRECTION INPUT ;
    USE SIGNAL ;
    PORT
      LAYER M5 ;
        RECT  84.336 0 84.36 0.084 ;
    END
  END d[423]
  PIN d[424]
    DIRECTION INPUT ;
    USE SIGNAL ;
    PORT
      LAYER M5 ;
        RECT  84.432 0 84.456 0.084 ;
    END
  END d[424]
  PIN d[425]
    DIRECTION INPUT ;
    USE SIGNAL ;
    PORT
      LAYER M5 ;
        RECT  84.528 0 84.552 0.084 ;
    END
  END d[425]
  PIN d[426]
    DIRECTION INPUT ;
    USE SIGNAL ;
    PORT
      LAYER M5 ;
        RECT  84.624 0 84.648 0.084 ;
    END
  END d[426]
  PIN d[427]
    DIRECTION INPUT ;
    USE SIGNAL ;
    PORT
      LAYER M5 ;
        RECT  84.72 0 84.744 0.084 ;
    END
  END d[427]
  PIN d[428]
    DIRECTION INPUT ;
    USE SIGNAL ;
    PORT
      LAYER M5 ;
        RECT  84.816 0 84.84 0.084 ;
    END
  END d[428]
  PIN d[429]
    DIRECTION INPUT ;
    USE SIGNAL ;
    PORT
      LAYER M5 ;
        RECT  84.912 0 84.936 0.084 ;
    END
  END d[429]
  PIN d[42]
    DIRECTION INPUT ;
    USE SIGNAL ;
    PORT
      LAYER M5 ;
        RECT  46.224 0 46.248 0.084 ;
    END
  END d[42]
  PIN d[430]
    DIRECTION INPUT ;
    USE SIGNAL ;
    PORT
      LAYER M5 ;
        RECT  85.008 0 85.032 0.084 ;
    END
  END d[430]
  PIN d[431]
    DIRECTION INPUT ;
    USE SIGNAL ;
    PORT
      LAYER M5 ;
        RECT  85.104 0 85.128 0.084 ;
    END
  END d[431]
  PIN d[432]
    DIRECTION INPUT ;
    USE SIGNAL ;
    PORT
      LAYER M5 ;
        RECT  85.2 0 85.224 0.084 ;
    END
  END d[432]
  PIN d[433]
    DIRECTION INPUT ;
    USE SIGNAL ;
    PORT
      LAYER M5 ;
        RECT  85.296 0 85.32 0.084 ;
    END
  END d[433]
  PIN d[434]
    DIRECTION INPUT ;
    USE SIGNAL ;
    PORT
      LAYER M5 ;
        RECT  85.392 0 85.416 0.084 ;
    END
  END d[434]
  PIN d[435]
    DIRECTION INPUT ;
    USE SIGNAL ;
    PORT
      LAYER M5 ;
        RECT  85.488 0 85.512 0.084 ;
    END
  END d[435]
  PIN d[436]
    DIRECTION INPUT ;
    USE SIGNAL ;
    PORT
      LAYER M5 ;
        RECT  85.584 0 85.608 0.084 ;
    END
  END d[436]
  PIN d[437]
    DIRECTION INPUT ;
    USE SIGNAL ;
    PORT
      LAYER M5 ;
        RECT  85.68 0 85.704 0.084 ;
    END
  END d[437]
  PIN d[438]
    DIRECTION INPUT ;
    USE SIGNAL ;
    PORT
      LAYER M5 ;
        RECT  85.776 0 85.8 0.084 ;
    END
  END d[438]
  PIN d[439]
    DIRECTION INPUT ;
    USE SIGNAL ;
    PORT
      LAYER M5 ;
        RECT  85.872 0 85.896 0.084 ;
    END
  END d[439]
  PIN d[43]
    DIRECTION INPUT ;
    USE SIGNAL ;
    PORT
      LAYER M5 ;
        RECT  46.32 0 46.344 0.084 ;
    END
  END d[43]
  PIN d[440]
    DIRECTION INPUT ;
    USE SIGNAL ;
    PORT
      LAYER M5 ;
        RECT  85.968 0 85.992 0.084 ;
    END
  END d[440]
  PIN d[441]
    DIRECTION INPUT ;
    USE SIGNAL ;
    PORT
      LAYER M5 ;
        RECT  86.064 0 86.088 0.084 ;
    END
  END d[441]
  PIN d[442]
    DIRECTION INPUT ;
    USE SIGNAL ;
    PORT
      LAYER M5 ;
        RECT  86.16 0 86.184 0.084 ;
    END
  END d[442]
  PIN d[443]
    DIRECTION INPUT ;
    USE SIGNAL ;
    PORT
      LAYER M5 ;
        RECT  86.256 0 86.28 0.084 ;
    END
  END d[443]
  PIN d[444]
    DIRECTION INPUT ;
    USE SIGNAL ;
    PORT
      LAYER M5 ;
        RECT  86.352 0 86.376 0.084 ;
    END
  END d[444]
  PIN d[445]
    DIRECTION INPUT ;
    USE SIGNAL ;
    PORT
      LAYER M5 ;
        RECT  86.448 0 86.472 0.084 ;
    END
  END d[445]
  PIN d[446]
    DIRECTION INPUT ;
    USE SIGNAL ;
    PORT
      LAYER M5 ;
        RECT  86.544 0 86.568 0.084 ;
    END
  END d[446]
  PIN d[447]
    DIRECTION INPUT ;
    USE SIGNAL ;
    PORT
      LAYER M5 ;
        RECT  86.64 0 86.664 0.084 ;
    END
  END d[447]
  PIN d[448]
    DIRECTION INPUT ;
    USE SIGNAL ;
    PORT
      LAYER M5 ;
        RECT  80.592 0 80.616 0.084 ;
    END
  END d[448]
  PIN d[449]
    DIRECTION INPUT ;
    USE SIGNAL ;
    PORT
      LAYER M5 ;
        RECT  80.688 0 80.712 0.084 ;
    END
  END d[449]
  PIN d[44]
    DIRECTION INPUT ;
    USE SIGNAL ;
    PORT
      LAYER M5 ;
        RECT  46.416 0 46.44 0.084 ;
    END
  END d[44]
  PIN d[450]
    DIRECTION INPUT ;
    USE SIGNAL ;
    PORT
      LAYER M5 ;
        RECT  80.784 0 80.808 0.084 ;
    END
  END d[450]
  PIN d[451]
    DIRECTION INPUT ;
    USE SIGNAL ;
    PORT
      LAYER M5 ;
        RECT  80.88 0 80.904 0.084 ;
    END
  END d[451]
  PIN d[452]
    DIRECTION INPUT ;
    USE SIGNAL ;
    PORT
      LAYER M5 ;
        RECT  80.976 0 81 0.084 ;
    END
  END d[452]
  PIN d[453]
    DIRECTION INPUT ;
    USE SIGNAL ;
    PORT
      LAYER M5 ;
        RECT  81.072 0 81.096 0.084 ;
    END
  END d[453]
  PIN d[454]
    DIRECTION INPUT ;
    USE SIGNAL ;
    PORT
      LAYER M5 ;
        RECT  81.168 0 81.192 0.084 ;
    END
  END d[454]
  PIN d[455]
    DIRECTION INPUT ;
    USE SIGNAL ;
    PORT
      LAYER M5 ;
        RECT  81.264 0 81.288 0.084 ;
    END
  END d[455]
  PIN d[456]
    DIRECTION INPUT ;
    USE SIGNAL ;
    PORT
      LAYER M5 ;
        RECT  81.36 0 81.384 0.084 ;
    END
  END d[456]
  PIN d[457]
    DIRECTION INPUT ;
    USE SIGNAL ;
    PORT
      LAYER M5 ;
        RECT  81.456 0 81.48 0.084 ;
    END
  END d[457]
  PIN d[458]
    DIRECTION INPUT ;
    USE SIGNAL ;
    PORT
      LAYER M5 ;
        RECT  81.552 0 81.576 0.084 ;
    END
  END d[458]
  PIN d[459]
    DIRECTION INPUT ;
    USE SIGNAL ;
    PORT
      LAYER M5 ;
        RECT  81.648 0 81.672 0.084 ;
    END
  END d[459]
  PIN d[45]
    DIRECTION INPUT ;
    USE SIGNAL ;
    PORT
      LAYER M5 ;
        RECT  46.512 0 46.536 0.084 ;
    END
  END d[45]
  PIN d[460]
    DIRECTION INPUT ;
    USE SIGNAL ;
    PORT
      LAYER M5 ;
        RECT  81.744 0 81.768 0.084 ;
    END
  END d[460]
  PIN d[461]
    DIRECTION INPUT ;
    USE SIGNAL ;
    PORT
      LAYER M5 ;
        RECT  81.84 0 81.864 0.084 ;
    END
  END d[461]
  PIN d[462]
    DIRECTION INPUT ;
    USE SIGNAL ;
    PORT
      LAYER M5 ;
        RECT  81.936 0 81.96 0.084 ;
    END
  END d[462]
  PIN d[463]
    DIRECTION INPUT ;
    USE SIGNAL ;
    PORT
      LAYER M5 ;
        RECT  82.032 0 82.056 0.084 ;
    END
  END d[463]
  PIN d[464]
    DIRECTION INPUT ;
    USE SIGNAL ;
    PORT
      LAYER M5 ;
        RECT  82.128 0 82.152 0.084 ;
    END
  END d[464]
  PIN d[465]
    DIRECTION INPUT ;
    USE SIGNAL ;
    PORT
      LAYER M5 ;
        RECT  82.224 0 82.248 0.084 ;
    END
  END d[465]
  PIN d[466]
    DIRECTION INPUT ;
    USE SIGNAL ;
    PORT
      LAYER M5 ;
        RECT  82.32 0 82.344 0.084 ;
    END
  END d[466]
  PIN d[467]
    DIRECTION INPUT ;
    USE SIGNAL ;
    PORT
      LAYER M5 ;
        RECT  82.416 0 82.44 0.084 ;
    END
  END d[467]
  PIN d[468]
    DIRECTION INPUT ;
    USE SIGNAL ;
    PORT
      LAYER M5 ;
        RECT  82.512 0 82.536 0.084 ;
    END
  END d[468]
  PIN d[469]
    DIRECTION INPUT ;
    USE SIGNAL ;
    PORT
      LAYER M5 ;
        RECT  82.608 0 82.632 0.084 ;
    END
  END d[469]
  PIN d[46]
    DIRECTION INPUT ;
    USE SIGNAL ;
    PORT
      LAYER M5 ;
        RECT  46.608 0 46.632 0.084 ;
    END
  END d[46]
  PIN d[470]
    DIRECTION INPUT ;
    USE SIGNAL ;
    PORT
      LAYER M5 ;
        RECT  82.704 0 82.728 0.084 ;
    END
  END d[470]
  PIN d[471]
    DIRECTION INPUT ;
    USE SIGNAL ;
    PORT
      LAYER M5 ;
        RECT  82.8 0 82.824 0.084 ;
    END
  END d[471]
  PIN d[472]
    DIRECTION INPUT ;
    USE SIGNAL ;
    PORT
      LAYER M5 ;
        RECT  82.896 0 82.92 0.084 ;
    END
  END d[472]
  PIN d[473]
    DIRECTION INPUT ;
    USE SIGNAL ;
    PORT
      LAYER M5 ;
        RECT  82.992 0 83.016 0.084 ;
    END
  END d[473]
  PIN d[474]
    DIRECTION INPUT ;
    USE SIGNAL ;
    PORT
      LAYER M5 ;
        RECT  83.088 0 83.112 0.084 ;
    END
  END d[474]
  PIN d[475]
    DIRECTION INPUT ;
    USE SIGNAL ;
    PORT
      LAYER M5 ;
        RECT  83.184 0 83.208 0.084 ;
    END
  END d[475]
  PIN d[476]
    DIRECTION INPUT ;
    USE SIGNAL ;
    PORT
      LAYER M5 ;
        RECT  83.28 0 83.304 0.084 ;
    END
  END d[476]
  PIN d[477]
    DIRECTION INPUT ;
    USE SIGNAL ;
    PORT
      LAYER M5 ;
        RECT  83.376 0 83.4 0.084 ;
    END
  END d[477]
  PIN d[478]
    DIRECTION INPUT ;
    USE SIGNAL ;
    PORT
      LAYER M5 ;
        RECT  83.472 0 83.496 0.084 ;
    END
  END d[478]
  PIN d[479]
    DIRECTION INPUT ;
    USE SIGNAL ;
    PORT
      LAYER M5 ;
        RECT  83.568 0 83.592 0.084 ;
    END
  END d[479]
  PIN d[47]
    DIRECTION INPUT ;
    USE SIGNAL ;
    PORT
      LAYER M5 ;
        RECT  46.704 0 46.728 0.084 ;
    END
  END d[47]
  PIN d[480]
    DIRECTION INPUT ;
    USE SIGNAL ;
    PORT
      LAYER M5 ;
        RECT  70.608 0 70.632 0.084 ;
    END
  END d[480]
  PIN d[481]
    DIRECTION INPUT ;
    USE SIGNAL ;
    PORT
      LAYER M5 ;
        RECT  70.704 0 70.728 0.084 ;
    END
  END d[481]
  PIN d[482]
    DIRECTION INPUT ;
    USE SIGNAL ;
    PORT
      LAYER M5 ;
        RECT  70.8 0 70.824 0.084 ;
    END
  END d[482]
  PIN d[483]
    DIRECTION INPUT ;
    USE SIGNAL ;
    PORT
      LAYER M5 ;
        RECT  70.896 0 70.92 0.084 ;
    END
  END d[483]
  PIN d[484]
    DIRECTION INPUT ;
    USE SIGNAL ;
    PORT
      LAYER M5 ;
        RECT  70.992 0 71.016 0.084 ;
    END
  END d[484]
  PIN d[485]
    DIRECTION INPUT ;
    USE SIGNAL ;
    PORT
      LAYER M5 ;
        RECT  71.088 0 71.112 0.084 ;
    END
  END d[485]
  PIN d[486]
    DIRECTION INPUT ;
    USE SIGNAL ;
    PORT
      LAYER M5 ;
        RECT  71.184 0 71.208 0.084 ;
    END
  END d[486]
  PIN d[487]
    DIRECTION INPUT ;
    USE SIGNAL ;
    PORT
      LAYER M5 ;
        RECT  71.28 0 71.304 0.084 ;
    END
  END d[487]
  PIN d[488]
    DIRECTION INPUT ;
    USE SIGNAL ;
    PORT
      LAYER M5 ;
        RECT  71.376 0 71.4 0.084 ;
    END
  END d[488]
  PIN d[489]
    DIRECTION INPUT ;
    USE SIGNAL ;
    PORT
      LAYER M5 ;
        RECT  71.472 0 71.496 0.084 ;
    END
  END d[489]
  PIN d[48]
    DIRECTION INPUT ;
    USE SIGNAL ;
    PORT
      LAYER M5 ;
        RECT  46.8 0 46.824 0.084 ;
    END
  END d[48]
  PIN d[490]
    DIRECTION INPUT ;
    USE SIGNAL ;
    PORT
      LAYER M5 ;
        RECT  71.568 0 71.592 0.084 ;
    END
  END d[490]
  PIN d[491]
    DIRECTION INPUT ;
    USE SIGNAL ;
    PORT
      LAYER M5 ;
        RECT  71.664 0 71.688 0.084 ;
    END
  END d[491]
  PIN d[492]
    DIRECTION INPUT ;
    USE SIGNAL ;
    PORT
      LAYER M5 ;
        RECT  71.76 0 71.784 0.084 ;
    END
  END d[492]
  PIN d[493]
    DIRECTION INPUT ;
    USE SIGNAL ;
    PORT
      LAYER M5 ;
        RECT  71.856 0 71.88 0.084 ;
    END
  END d[493]
  PIN d[494]
    DIRECTION INPUT ;
    USE SIGNAL ;
    PORT
      LAYER M5 ;
        RECT  71.952 0 71.976 0.084 ;
    END
  END d[494]
  PIN d[495]
    DIRECTION INPUT ;
    USE SIGNAL ;
    PORT
      LAYER M5 ;
        RECT  72.048 0 72.072 0.084 ;
    END
  END d[495]
  PIN d[496]
    DIRECTION INPUT ;
    USE SIGNAL ;
    PORT
      LAYER M5 ;
        RECT  72.144 0 72.168 0.084 ;
    END
  END d[496]
  PIN d[497]
    DIRECTION INPUT ;
    USE SIGNAL ;
    PORT
      LAYER M5 ;
        RECT  72.24 0 72.264 0.084 ;
    END
  END d[497]
  PIN d[498]
    DIRECTION INPUT ;
    USE SIGNAL ;
    PORT
      LAYER M5 ;
        RECT  72.336 0 72.36 0.084 ;
    END
  END d[498]
  PIN d[499]
    DIRECTION INPUT ;
    USE SIGNAL ;
    PORT
      LAYER M5 ;
        RECT  72.432 0 72.456 0.084 ;
    END
  END d[499]
  PIN d[49]
    DIRECTION INPUT ;
    USE SIGNAL ;
    PORT
      LAYER M5 ;
        RECT  46.896 0 46.92 0.084 ;
    END
  END d[49]
  PIN d[4]
    DIRECTION INPUT ;
    USE SIGNAL ;
    PORT
      LAYER M5 ;
        RECT  32.592 0 32.616 0.084 ;
    END
  END d[4]
  PIN d[500]
    DIRECTION INPUT ;
    USE SIGNAL ;
    PORT
      LAYER M5 ;
        RECT  72.528 0 72.552 0.084 ;
    END
  END d[500]
  PIN d[501]
    DIRECTION INPUT ;
    USE SIGNAL ;
    PORT
      LAYER M5 ;
        RECT  72.624 0 72.648 0.084 ;
    END
  END d[501]
  PIN d[502]
    DIRECTION INPUT ;
    USE SIGNAL ;
    PORT
      LAYER M5 ;
        RECT  72.72 0 72.744 0.084 ;
    END
  END d[502]
  PIN d[503]
    DIRECTION INPUT ;
    USE SIGNAL ;
    PORT
      LAYER M5 ;
        RECT  72.816 0 72.84 0.084 ;
    END
  END d[503]
  PIN d[504]
    DIRECTION INPUT ;
    USE SIGNAL ;
    PORT
      LAYER M5 ;
        RECT  72.912 0 72.936 0.084 ;
    END
  END d[504]
  PIN d[505]
    DIRECTION INPUT ;
    USE SIGNAL ;
    PORT
      LAYER M5 ;
        RECT  73.008 0 73.032 0.084 ;
    END
  END d[505]
  PIN d[506]
    DIRECTION INPUT ;
    USE SIGNAL ;
    PORT
      LAYER M5 ;
        RECT  73.104 0 73.128 0.084 ;
    END
  END d[506]
  PIN d[507]
    DIRECTION INPUT ;
    USE SIGNAL ;
    PORT
      LAYER M5 ;
        RECT  73.2 0 73.224 0.084 ;
    END
  END d[507]
  PIN d[508]
    DIRECTION INPUT ;
    USE SIGNAL ;
    PORT
      LAYER M5 ;
        RECT  73.296 0 73.32 0.084 ;
    END
  END d[508]
  PIN d[509]
    DIRECTION INPUT ;
    USE SIGNAL ;
    PORT
      LAYER M5 ;
        RECT  73.392 0 73.416 0.084 ;
    END
  END d[509]
  PIN d[50]
    DIRECTION INPUT ;
    USE SIGNAL ;
    PORT
      LAYER M5 ;
        RECT  46.992 0 47.016 0.084 ;
    END
  END d[50]
  PIN d[510]
    DIRECTION INPUT ;
    USE SIGNAL ;
    PORT
      LAYER M5 ;
        RECT  73.488 0 73.512 0.084 ;
    END
  END d[510]
  PIN d[511]
    DIRECTION INPUT ;
    USE SIGNAL ;
    PORT
      LAYER M5 ;
        RECT  73.584 0 73.608 0.084 ;
    END
  END d[511]
  PIN d[51]
    DIRECTION INPUT ;
    USE SIGNAL ;
    PORT
      LAYER M5 ;
        RECT  47.088 0 47.112 0.084 ;
    END
  END d[51]
  PIN d[52]
    DIRECTION INPUT ;
    USE SIGNAL ;
    PORT
      LAYER M5 ;
        RECT  47.184 0 47.208 0.084 ;
    END
  END d[52]
  PIN d[53]
    DIRECTION INPUT ;
    USE SIGNAL ;
    PORT
      LAYER M5 ;
        RECT  47.28 0 47.304 0.084 ;
    END
  END d[53]
  PIN d[54]
    DIRECTION INPUT ;
    USE SIGNAL ;
    PORT
      LAYER M5 ;
        RECT  47.376 0 47.4 0.084 ;
    END
  END d[54]
  PIN d[55]
    DIRECTION INPUT ;
    USE SIGNAL ;
    PORT
      LAYER M5 ;
        RECT  47.472 0 47.496 0.084 ;
    END
  END d[55]
  PIN d[56]
    DIRECTION INPUT ;
    USE SIGNAL ;
    PORT
      LAYER M5 ;
        RECT  47.568 0 47.592 0.084 ;
    END
  END d[56]
  PIN d[57]
    DIRECTION INPUT ;
    USE SIGNAL ;
    PORT
      LAYER M5 ;
        RECT  47.664 0 47.688 0.084 ;
    END
  END d[57]
  PIN d[58]
    DIRECTION INPUT ;
    USE SIGNAL ;
    PORT
      LAYER M5 ;
        RECT  47.76 0 47.784 0.084 ;
    END
  END d[58]
  PIN d[59]
    DIRECTION INPUT ;
    USE SIGNAL ;
    PORT
      LAYER M5 ;
        RECT  47.856 0 47.88 0.084 ;
    END
  END d[59]
  PIN d[5]
    DIRECTION INPUT ;
    USE SIGNAL ;
    PORT
      LAYER M5 ;
        RECT  32.688 0 32.712 0.084 ;
    END
  END d[5]
  PIN d[60]
    DIRECTION INPUT ;
    USE SIGNAL ;
    PORT
      LAYER M5 ;
        RECT  47.952 0 47.976 0.084 ;
    END
  END d[60]
  PIN d[61]
    DIRECTION INPUT ;
    USE SIGNAL ;
    PORT
      LAYER M5 ;
        RECT  48.048 0 48.072 0.084 ;
    END
  END d[61]
  PIN d[62]
    DIRECTION INPUT ;
    USE SIGNAL ;
    PORT
      LAYER M5 ;
        RECT  48.144 0 48.168 0.084 ;
    END
  END d[62]
  PIN d[63]
    DIRECTION INPUT ;
    USE SIGNAL ;
    PORT
      LAYER M5 ;
        RECT  48.24 0 48.264 0.084 ;
    END
  END d[63]
  PIN d[64]
    DIRECTION INPUT ;
    USE SIGNAL ;
    PORT
      LAYER M5 ;
        RECT  39.12 0 39.144 0.084 ;
    END
  END d[64]
  PIN d[65]
    DIRECTION INPUT ;
    USE SIGNAL ;
    PORT
      LAYER M5 ;
        RECT  39.216 0 39.24 0.084 ;
    END
  END d[65]
  PIN d[66]
    DIRECTION INPUT ;
    USE SIGNAL ;
    PORT
      LAYER M5 ;
        RECT  39.312 0 39.336 0.084 ;
    END
  END d[66]
  PIN d[67]
    DIRECTION INPUT ;
    USE SIGNAL ;
    PORT
      LAYER M5 ;
        RECT  39.408 0 39.432 0.084 ;
    END
  END d[67]
  PIN d[68]
    DIRECTION INPUT ;
    USE SIGNAL ;
    PORT
      LAYER M5 ;
        RECT  39.504 0 39.528 0.084 ;
    END
  END d[68]
  PIN d[69]
    DIRECTION INPUT ;
    USE SIGNAL ;
    PORT
      LAYER M5 ;
        RECT  39.6 0 39.624 0.084 ;
    END
  END d[69]
  PIN d[6]
    DIRECTION INPUT ;
    USE SIGNAL ;
    PORT
      LAYER M5 ;
        RECT  32.784 0 32.808 0.084 ;
    END
  END d[6]
  PIN d[70]
    DIRECTION INPUT ;
    USE SIGNAL ;
    PORT
      LAYER M5 ;
        RECT  39.696 0 39.72 0.084 ;
    END
  END d[70]
  PIN d[71]
    DIRECTION INPUT ;
    USE SIGNAL ;
    PORT
      LAYER M5 ;
        RECT  39.792 0 39.816 0.084 ;
    END
  END d[71]
  PIN d[72]
    DIRECTION INPUT ;
    USE SIGNAL ;
    PORT
      LAYER M5 ;
        RECT  39.888 0 39.912 0.084 ;
    END
  END d[72]
  PIN d[73]
    DIRECTION INPUT ;
    USE SIGNAL ;
    PORT
      LAYER M5 ;
        RECT  39.984 0 40.008 0.084 ;
    END
  END d[73]
  PIN d[74]
    DIRECTION INPUT ;
    USE SIGNAL ;
    PORT
      LAYER M5 ;
        RECT  40.08 0 40.104 0.084 ;
    END
  END d[74]
  PIN d[75]
    DIRECTION INPUT ;
    USE SIGNAL ;
    PORT
      LAYER M5 ;
        RECT  40.176 0 40.2 0.084 ;
    END
  END d[75]
  PIN d[76]
    DIRECTION INPUT ;
    USE SIGNAL ;
    PORT
      LAYER M5 ;
        RECT  40.272 0 40.296 0.084 ;
    END
  END d[76]
  PIN d[77]
    DIRECTION INPUT ;
    USE SIGNAL ;
    PORT
      LAYER M5 ;
        RECT  40.368 0 40.392 0.084 ;
    END
  END d[77]
  PIN d[78]
    DIRECTION INPUT ;
    USE SIGNAL ;
    PORT
      LAYER M5 ;
        RECT  40.464 0 40.488 0.084 ;
    END
  END d[78]
  PIN d[79]
    DIRECTION INPUT ;
    USE SIGNAL ;
    PORT
      LAYER M5 ;
        RECT  40.56 0 40.584 0.084 ;
    END
  END d[79]
  PIN d[7]
    DIRECTION INPUT ;
    USE SIGNAL ;
    PORT
      LAYER M5 ;
        RECT  32.88 0 32.904 0.084 ;
    END
  END d[7]
  PIN d[80]
    DIRECTION INPUT ;
    USE SIGNAL ;
    PORT
      LAYER M5 ;
        RECT  40.656 0 40.68 0.084 ;
    END
  END d[80]
  PIN d[81]
    DIRECTION INPUT ;
    USE SIGNAL ;
    PORT
      LAYER M5 ;
        RECT  40.752 0 40.776 0.084 ;
    END
  END d[81]
  PIN d[82]
    DIRECTION INPUT ;
    USE SIGNAL ;
    PORT
      LAYER M5 ;
        RECT  40.848 0 40.872 0.084 ;
    END
  END d[82]
  PIN d[83]
    DIRECTION INPUT ;
    USE SIGNAL ;
    PORT
      LAYER M5 ;
        RECT  40.944 0 40.968 0.084 ;
    END
  END d[83]
  PIN d[84]
    DIRECTION INPUT ;
    USE SIGNAL ;
    PORT
      LAYER M5 ;
        RECT  41.04 0 41.064 0.084 ;
    END
  END d[84]
  PIN d[85]
    DIRECTION INPUT ;
    USE SIGNAL ;
    PORT
      LAYER M5 ;
        RECT  41.136 0 41.16 0.084 ;
    END
  END d[85]
  PIN d[86]
    DIRECTION INPUT ;
    USE SIGNAL ;
    PORT
      LAYER M5 ;
        RECT  41.232 0 41.256 0.084 ;
    END
  END d[86]
  PIN d[87]
    DIRECTION INPUT ;
    USE SIGNAL ;
    PORT
      LAYER M5 ;
        RECT  41.328 0 41.352 0.084 ;
    END
  END d[87]
  PIN d[88]
    DIRECTION INPUT ;
    USE SIGNAL ;
    PORT
      LAYER M5 ;
        RECT  41.424 0 41.448 0.084 ;
    END
  END d[88]
  PIN d[89]
    DIRECTION INPUT ;
    USE SIGNAL ;
    PORT
      LAYER M5 ;
        RECT  41.52 0 41.544 0.084 ;
    END
  END d[89]
  PIN d[8]
    DIRECTION INPUT ;
    USE SIGNAL ;
    PORT
      LAYER M5 ;
        RECT  32.976 0 33 0.084 ;
    END
  END d[8]
  PIN d[90]
    DIRECTION INPUT ;
    USE SIGNAL ;
    PORT
      LAYER M5 ;
        RECT  41.616 0 41.64 0.084 ;
    END
  END d[90]
  PIN d[91]
    DIRECTION INPUT ;
    USE SIGNAL ;
    PORT
      LAYER M5 ;
        RECT  41.712 0 41.736 0.084 ;
    END
  END d[91]
  PIN d[92]
    DIRECTION INPUT ;
    USE SIGNAL ;
    PORT
      LAYER M5 ;
        RECT  41.808 0 41.832 0.084 ;
    END
  END d[92]
  PIN d[93]
    DIRECTION INPUT ;
    USE SIGNAL ;
    PORT
      LAYER M5 ;
        RECT  41.904 0 41.928 0.084 ;
    END
  END d[93]
  PIN d[94]
    DIRECTION INPUT ;
    USE SIGNAL ;
    PORT
      LAYER M5 ;
        RECT  42 0 42.024 0.084 ;
    END
  END d[94]
  PIN d[95]
    DIRECTION INPUT ;
    USE SIGNAL ;
    PORT
      LAYER M5 ;
        RECT  42.096 0 42.12 0.084 ;
    END
  END d[95]
  PIN d[96]
    DIRECTION INPUT ;
    USE SIGNAL ;
    PORT
      LAYER M5 ;
        RECT  29.136 0 29.16 0.084 ;
    END
  END d[96]
  PIN d[97]
    DIRECTION INPUT ;
    USE SIGNAL ;
    PORT
      LAYER M5 ;
        RECT  29.232 0 29.256 0.084 ;
    END
  END d[97]
  PIN d[98]
    DIRECTION INPUT ;
    USE SIGNAL ;
    PORT
      LAYER M5 ;
        RECT  29.328 0 29.352 0.084 ;
    END
  END d[98]
  PIN d[99]
    DIRECTION INPUT ;
    USE SIGNAL ;
    PORT
      LAYER M5 ;
        RECT  29.424 0 29.448 0.084 ;
    END
  END d[99]
  PIN d[9]
    DIRECTION INPUT ;
    USE SIGNAL ;
    PORT
      LAYER M5 ;
        RECT  33.072 0 33.096 0.084 ;
    END
  END d[9]
  PIN me_e
    DIRECTION INPUT ;
    USE SIGNAL ;
    PORT
      LAYER M4 ;
        RECT  0 6.768 0.084 6.792 ;
    END
  END me_e
  PIN q[0]
    DIRECTION OUTPUT ;
    USE SIGNAL ;
    PORT
      LAYER M5 ;
        RECT  29.808 12.876 29.832 12.96 ;
    END
  END q[0]
  PIN q[100]
    DIRECTION OUTPUT ;
    USE SIGNAL ;
    PORT
      LAYER M5 ;
        RECT  27.12 12.876 27.144 12.96 ;
    END
  END q[100]
  PIN q[101]
    DIRECTION OUTPUT ;
    USE SIGNAL ;
    PORT
      LAYER M5 ;
        RECT  27.216 12.876 27.24 12.96 ;
    END
  END q[101]
  PIN q[102]
    DIRECTION OUTPUT ;
    USE SIGNAL ;
    PORT
      LAYER M5 ;
        RECT  27.312 12.876 27.336 12.96 ;
    END
  END q[102]
  PIN q[103]
    DIRECTION OUTPUT ;
    USE SIGNAL ;
    PORT
      LAYER M5 ;
        RECT  27.408 12.876 27.432 12.96 ;
    END
  END q[103]
  PIN q[104]
    DIRECTION OUTPUT ;
    USE SIGNAL ;
    PORT
      LAYER M5 ;
        RECT  27.504 12.876 27.528 12.96 ;
    END
  END q[104]
  PIN q[105]
    DIRECTION OUTPUT ;
    USE SIGNAL ;
    PORT
      LAYER M5 ;
        RECT  27.6 12.876 27.624 12.96 ;
    END
  END q[105]
  PIN q[106]
    DIRECTION OUTPUT ;
    USE SIGNAL ;
    PORT
      LAYER M5 ;
        RECT  27.696 12.876 27.72 12.96 ;
    END
  END q[106]
  PIN q[107]
    DIRECTION OUTPUT ;
    USE SIGNAL ;
    PORT
      LAYER M5 ;
        RECT  27.792 12.876 27.816 12.96 ;
    END
  END q[107]
  PIN q[108]
    DIRECTION OUTPUT ;
    USE SIGNAL ;
    PORT
      LAYER M5 ;
        RECT  27.888 12.876 27.912 12.96 ;
    END
  END q[108]
  PIN q[109]
    DIRECTION OUTPUT ;
    USE SIGNAL ;
    PORT
      LAYER M5 ;
        RECT  27.984 12.876 28.008 12.96 ;
    END
  END q[109]
  PIN q[10]
    DIRECTION OUTPUT ;
    USE SIGNAL ;
    PORT
      LAYER M5 ;
        RECT  30.768 12.876 30.792 12.96 ;
    END
  END q[10]
  PIN q[110]
    DIRECTION OUTPUT ;
    USE SIGNAL ;
    PORT
      LAYER M5 ;
        RECT  28.08 12.876 28.104 12.96 ;
    END
  END q[110]
  PIN q[111]
    DIRECTION OUTPUT ;
    USE SIGNAL ;
    PORT
      LAYER M5 ;
        RECT  28.176 12.876 28.2 12.96 ;
    END
  END q[111]
  PIN q[112]
    DIRECTION OUTPUT ;
    USE SIGNAL ;
    PORT
      LAYER M5 ;
        RECT  28.272 12.876 28.296 12.96 ;
    END
  END q[112]
  PIN q[113]
    DIRECTION OUTPUT ;
    USE SIGNAL ;
    PORT
      LAYER M5 ;
        RECT  28.368 12.876 28.392 12.96 ;
    END
  END q[113]
  PIN q[114]
    DIRECTION OUTPUT ;
    USE SIGNAL ;
    PORT
      LAYER M5 ;
        RECT  28.464 12.876 28.488 12.96 ;
    END
  END q[114]
  PIN q[115]
    DIRECTION OUTPUT ;
    USE SIGNAL ;
    PORT
      LAYER M5 ;
        RECT  28.56 12.876 28.584 12.96 ;
    END
  END q[115]
  PIN q[116]
    DIRECTION OUTPUT ;
    USE SIGNAL ;
    PORT
      LAYER M5 ;
        RECT  28.656 12.876 28.68 12.96 ;
    END
  END q[116]
  PIN q[117]
    DIRECTION OUTPUT ;
    USE SIGNAL ;
    PORT
      LAYER M5 ;
        RECT  28.752 12.876 28.776 12.96 ;
    END
  END q[117]
  PIN q[118]
    DIRECTION OUTPUT ;
    USE SIGNAL ;
    PORT
      LAYER M5 ;
        RECT  28.848 12.876 28.872 12.96 ;
    END
  END q[118]
  PIN q[119]
    DIRECTION OUTPUT ;
    USE SIGNAL ;
    PORT
      LAYER M5 ;
        RECT  28.944 12.876 28.968 12.96 ;
    END
  END q[119]
  PIN q[11]
    DIRECTION OUTPUT ;
    USE SIGNAL ;
    PORT
      LAYER M5 ;
        RECT  30.864 12.876 30.888 12.96 ;
    END
  END q[11]
  PIN q[120]
    DIRECTION OUTPUT ;
    USE SIGNAL ;
    PORT
      LAYER M5 ;
        RECT  29.04 12.876 29.064 12.96 ;
    END
  END q[120]
  PIN q[121]
    DIRECTION OUTPUT ;
    USE SIGNAL ;
    PORT
      LAYER M5 ;
        RECT  29.136 12.876 29.16 12.96 ;
    END
  END q[121]
  PIN q[122]
    DIRECTION OUTPUT ;
    USE SIGNAL ;
    PORT
      LAYER M5 ;
        RECT  29.232 12.876 29.256 12.96 ;
    END
  END q[122]
  PIN q[123]
    DIRECTION OUTPUT ;
    USE SIGNAL ;
    PORT
      LAYER M5 ;
        RECT  29.328 12.876 29.352 12.96 ;
    END
  END q[123]
  PIN q[124]
    DIRECTION OUTPUT ;
    USE SIGNAL ;
    PORT
      LAYER M5 ;
        RECT  29.424 12.876 29.448 12.96 ;
    END
  END q[124]
  PIN q[125]
    DIRECTION OUTPUT ;
    USE SIGNAL ;
    PORT
      LAYER M5 ;
        RECT  29.52 12.876 29.544 12.96 ;
    END
  END q[125]
  PIN q[126]
    DIRECTION OUTPUT ;
    USE SIGNAL ;
    PORT
      LAYER M5 ;
        RECT  29.616 12.876 29.64 12.96 ;
    END
  END q[126]
  PIN q[127]
    DIRECTION OUTPUT ;
    USE SIGNAL ;
    PORT
      LAYER M5 ;
        RECT  29.712 12.876 29.736 12.96 ;
    END
  END q[127]
  PIN q[128]
    DIRECTION OUTPUT ;
    USE SIGNAL ;
    PORT
      LAYER M5 ;
        RECT  49.008 12.876 49.032 12.96 ;
    END
  END q[128]
  PIN q[129]
    DIRECTION OUTPUT ;
    USE SIGNAL ;
    PORT
      LAYER M5 ;
        RECT  49.104 12.876 49.128 12.96 ;
    END
  END q[129]
  PIN q[12]
    DIRECTION OUTPUT ;
    USE SIGNAL ;
    PORT
      LAYER M5 ;
        RECT  30.96 12.876 30.984 12.96 ;
    END
  END q[12]
  PIN q[130]
    DIRECTION OUTPUT ;
    USE SIGNAL ;
    PORT
      LAYER M5 ;
        RECT  49.2 12.876 49.224 12.96 ;
    END
  END q[130]
  PIN q[131]
    DIRECTION OUTPUT ;
    USE SIGNAL ;
    PORT
      LAYER M5 ;
        RECT  49.296 12.876 49.32 12.96 ;
    END
  END q[131]
  PIN q[132]
    DIRECTION OUTPUT ;
    USE SIGNAL ;
    PORT
      LAYER M5 ;
        RECT  49.392 12.876 49.416 12.96 ;
    END
  END q[132]
  PIN q[133]
    DIRECTION OUTPUT ;
    USE SIGNAL ;
    PORT
      LAYER M5 ;
        RECT  49.488 12.876 49.512 12.96 ;
    END
  END q[133]
  PIN q[134]
    DIRECTION OUTPUT ;
    USE SIGNAL ;
    PORT
      LAYER M5 ;
        RECT  49.584 12.876 49.608 12.96 ;
    END
  END q[134]
  PIN q[135]
    DIRECTION OUTPUT ;
    USE SIGNAL ;
    PORT
      LAYER M5 ;
        RECT  49.68 12.876 49.704 12.96 ;
    END
  END q[135]
  PIN q[136]
    DIRECTION OUTPUT ;
    USE SIGNAL ;
    PORT
      LAYER M5 ;
        RECT  49.776 12.876 49.8 12.96 ;
    END
  END q[136]
  PIN q[137]
    DIRECTION OUTPUT ;
    USE SIGNAL ;
    PORT
      LAYER M5 ;
        RECT  49.872 12.876 49.896 12.96 ;
    END
  END q[137]
  PIN q[138]
    DIRECTION OUTPUT ;
    USE SIGNAL ;
    PORT
      LAYER M5 ;
        RECT  49.968 12.876 49.992 12.96 ;
    END
  END q[138]
  PIN q[139]
    DIRECTION OUTPUT ;
    USE SIGNAL ;
    PORT
      LAYER M5 ;
        RECT  50.064 12.876 50.088 12.96 ;
    END
  END q[139]
  PIN q[13]
    DIRECTION OUTPUT ;
    USE SIGNAL ;
    PORT
      LAYER M5 ;
        RECT  31.056 12.876 31.08 12.96 ;
    END
  END q[13]
  PIN q[140]
    DIRECTION OUTPUT ;
    USE SIGNAL ;
    PORT
      LAYER M5 ;
        RECT  50.16 12.876 50.184 12.96 ;
    END
  END q[140]
  PIN q[141]
    DIRECTION OUTPUT ;
    USE SIGNAL ;
    PORT
      LAYER M5 ;
        RECT  50.256 12.876 50.28 12.96 ;
    END
  END q[141]
  PIN q[142]
    DIRECTION OUTPUT ;
    USE SIGNAL ;
    PORT
      LAYER M5 ;
        RECT  50.352 12.876 50.376 12.96 ;
    END
  END q[142]
  PIN q[143]
    DIRECTION OUTPUT ;
    USE SIGNAL ;
    PORT
      LAYER M5 ;
        RECT  50.448 12.876 50.472 12.96 ;
    END
  END q[143]
  PIN q[144]
    DIRECTION OUTPUT ;
    USE SIGNAL ;
    PORT
      LAYER M5 ;
        RECT  50.544 12.876 50.568 12.96 ;
    END
  END q[144]
  PIN q[145]
    DIRECTION OUTPUT ;
    USE SIGNAL ;
    PORT
      LAYER M5 ;
        RECT  50.64 12.876 50.664 12.96 ;
    END
  END q[145]
  PIN q[146]
    DIRECTION OUTPUT ;
    USE SIGNAL ;
    PORT
      LAYER M5 ;
        RECT  50.736 12.876 50.76 12.96 ;
    END
  END q[146]
  PIN q[147]
    DIRECTION OUTPUT ;
    USE SIGNAL ;
    PORT
      LAYER M5 ;
        RECT  50.832 12.876 50.856 12.96 ;
    END
  END q[147]
  PIN q[148]
    DIRECTION OUTPUT ;
    USE SIGNAL ;
    PORT
      LAYER M5 ;
        RECT  50.928 12.876 50.952 12.96 ;
    END
  END q[148]
  PIN q[149]
    DIRECTION OUTPUT ;
    USE SIGNAL ;
    PORT
      LAYER M5 ;
        RECT  51.024 12.876 51.048 12.96 ;
    END
  END q[149]
  PIN q[14]
    DIRECTION OUTPUT ;
    USE SIGNAL ;
    PORT
      LAYER M5 ;
        RECT  31.152 12.876 31.176 12.96 ;
    END
  END q[14]
  PIN q[150]
    DIRECTION OUTPUT ;
    USE SIGNAL ;
    PORT
      LAYER M5 ;
        RECT  51.12 12.876 51.144 12.96 ;
    END
  END q[150]
  PIN q[151]
    DIRECTION OUTPUT ;
    USE SIGNAL ;
    PORT
      LAYER M5 ;
        RECT  51.216 12.876 51.24 12.96 ;
    END
  END q[151]
  PIN q[152]
    DIRECTION OUTPUT ;
    USE SIGNAL ;
    PORT
      LAYER M5 ;
        RECT  51.312 12.876 51.336 12.96 ;
    END
  END q[152]
  PIN q[153]
    DIRECTION OUTPUT ;
    USE SIGNAL ;
    PORT
      LAYER M5 ;
        RECT  51.408 12.876 51.432 12.96 ;
    END
  END q[153]
  PIN q[154]
    DIRECTION OUTPUT ;
    USE SIGNAL ;
    PORT
      LAYER M5 ;
        RECT  51.504 12.876 51.528 12.96 ;
    END
  END q[154]
  PIN q[155]
    DIRECTION OUTPUT ;
    USE SIGNAL ;
    PORT
      LAYER M5 ;
        RECT  51.6 12.876 51.624 12.96 ;
    END
  END q[155]
  PIN q[156]
    DIRECTION OUTPUT ;
    USE SIGNAL ;
    PORT
      LAYER M5 ;
        RECT  51.696 12.876 51.72 12.96 ;
    END
  END q[156]
  PIN q[157]
    DIRECTION OUTPUT ;
    USE SIGNAL ;
    PORT
      LAYER M5 ;
        RECT  51.792 12.876 51.816 12.96 ;
    END
  END q[157]
  PIN q[158]
    DIRECTION OUTPUT ;
    USE SIGNAL ;
    PORT
      LAYER M5 ;
        RECT  51.888 12.876 51.912 12.96 ;
    END
  END q[158]
  PIN q[159]
    DIRECTION OUTPUT ;
    USE SIGNAL ;
    PORT
      LAYER M5 ;
        RECT  51.984 12.876 52.008 12.96 ;
    END
  END q[159]
  PIN q[15]
    DIRECTION OUTPUT ;
    USE SIGNAL ;
    PORT
      LAYER M5 ;
        RECT  31.248 12.876 31.272 12.96 ;
    END
  END q[15]
  PIN q[160]
    DIRECTION OUTPUT ;
    USE SIGNAL ;
    PORT
      LAYER M5 ;
        RECT  55.92 12.876 55.944 12.96 ;
    END
  END q[160]
  PIN q[161]
    DIRECTION OUTPUT ;
    USE SIGNAL ;
    PORT
      LAYER M5 ;
        RECT  56.016 12.876 56.04 12.96 ;
    END
  END q[161]
  PIN q[162]
    DIRECTION OUTPUT ;
    USE SIGNAL ;
    PORT
      LAYER M5 ;
        RECT  56.112 12.876 56.136 12.96 ;
    END
  END q[162]
  PIN q[163]
    DIRECTION OUTPUT ;
    USE SIGNAL ;
    PORT
      LAYER M5 ;
        RECT  56.208 12.876 56.232 12.96 ;
    END
  END q[163]
  PIN q[164]
    DIRECTION OUTPUT ;
    USE SIGNAL ;
    PORT
      LAYER M5 ;
        RECT  56.304 12.876 56.328 12.96 ;
    END
  END q[164]
  PIN q[165]
    DIRECTION OUTPUT ;
    USE SIGNAL ;
    PORT
      LAYER M5 ;
        RECT  56.4 12.876 56.424 12.96 ;
    END
  END q[165]
  PIN q[166]
    DIRECTION OUTPUT ;
    USE SIGNAL ;
    PORT
      LAYER M5 ;
        RECT  56.496 12.876 56.52 12.96 ;
    END
  END q[166]
  PIN q[167]
    DIRECTION OUTPUT ;
    USE SIGNAL ;
    PORT
      LAYER M5 ;
        RECT  56.592 12.876 56.616 12.96 ;
    END
  END q[167]
  PIN q[168]
    DIRECTION OUTPUT ;
    USE SIGNAL ;
    PORT
      LAYER M5 ;
        RECT  56.688 12.876 56.712 12.96 ;
    END
  END q[168]
  PIN q[169]
    DIRECTION OUTPUT ;
    USE SIGNAL ;
    PORT
      LAYER M5 ;
        RECT  56.784 12.876 56.808 12.96 ;
    END
  END q[169]
  PIN q[16]
    DIRECTION OUTPUT ;
    USE SIGNAL ;
    PORT
      LAYER M5 ;
        RECT  31.344 12.876 31.368 12.96 ;
    END
  END q[16]
  PIN q[170]
    DIRECTION OUTPUT ;
    USE SIGNAL ;
    PORT
      LAYER M5 ;
        RECT  56.88 12.876 56.904 12.96 ;
    END
  END q[170]
  PIN q[171]
    DIRECTION OUTPUT ;
    USE SIGNAL ;
    PORT
      LAYER M5 ;
        RECT  56.976 12.876 57 12.96 ;
    END
  END q[171]
  PIN q[172]
    DIRECTION OUTPUT ;
    USE SIGNAL ;
    PORT
      LAYER M5 ;
        RECT  57.072 12.876 57.096 12.96 ;
    END
  END q[172]
  PIN q[173]
    DIRECTION OUTPUT ;
    USE SIGNAL ;
    PORT
      LAYER M5 ;
        RECT  57.168 12.876 57.192 12.96 ;
    END
  END q[173]
  PIN q[174]
    DIRECTION OUTPUT ;
    USE SIGNAL ;
    PORT
      LAYER M5 ;
        RECT  57.264 12.876 57.288 12.96 ;
    END
  END q[174]
  PIN q[175]
    DIRECTION OUTPUT ;
    USE SIGNAL ;
    PORT
      LAYER M5 ;
        RECT  57.36 12.876 57.384 12.96 ;
    END
  END q[175]
  PIN q[176]
    DIRECTION OUTPUT ;
    USE SIGNAL ;
    PORT
      LAYER M5 ;
        RECT  57.456 12.876 57.48 12.96 ;
    END
  END q[176]
  PIN q[177]
    DIRECTION OUTPUT ;
    USE SIGNAL ;
    PORT
      LAYER M5 ;
        RECT  57.552 12.876 57.576 12.96 ;
    END
  END q[177]
  PIN q[178]
    DIRECTION OUTPUT ;
    USE SIGNAL ;
    PORT
      LAYER M5 ;
        RECT  57.648 12.876 57.672 12.96 ;
    END
  END q[178]
  PIN q[179]
    DIRECTION OUTPUT ;
    USE SIGNAL ;
    PORT
      LAYER M5 ;
        RECT  57.744 12.876 57.768 12.96 ;
    END
  END q[179]
  PIN q[17]
    DIRECTION OUTPUT ;
    USE SIGNAL ;
    PORT
      LAYER M5 ;
        RECT  31.44 12.876 31.464 12.96 ;
    END
  END q[17]
  PIN q[180]
    DIRECTION OUTPUT ;
    USE SIGNAL ;
    PORT
      LAYER M5 ;
        RECT  57.84 12.876 57.864 12.96 ;
    END
  END q[180]
  PIN q[181]
    DIRECTION OUTPUT ;
    USE SIGNAL ;
    PORT
      LAYER M5 ;
        RECT  57.936 12.876 57.96 12.96 ;
    END
  END q[181]
  PIN q[182]
    DIRECTION OUTPUT ;
    USE SIGNAL ;
    PORT
      LAYER M5 ;
        RECT  58.032 12.876 58.056 12.96 ;
    END
  END q[182]
  PIN q[183]
    DIRECTION OUTPUT ;
    USE SIGNAL ;
    PORT
      LAYER M5 ;
        RECT  58.128 12.876 58.152 12.96 ;
    END
  END q[183]
  PIN q[184]
    DIRECTION OUTPUT ;
    USE SIGNAL ;
    PORT
      LAYER M5 ;
        RECT  58.224 12.876 58.248 12.96 ;
    END
  END q[184]
  PIN q[185]
    DIRECTION OUTPUT ;
    USE SIGNAL ;
    PORT
      LAYER M5 ;
        RECT  58.32 12.876 58.344 12.96 ;
    END
  END q[185]
  PIN q[186]
    DIRECTION OUTPUT ;
    USE SIGNAL ;
    PORT
      LAYER M5 ;
        RECT  58.416 12.876 58.44 12.96 ;
    END
  END q[186]
  PIN q[187]
    DIRECTION OUTPUT ;
    USE SIGNAL ;
    PORT
      LAYER M5 ;
        RECT  58.512 12.876 58.536 12.96 ;
    END
  END q[187]
  PIN q[188]
    DIRECTION OUTPUT ;
    USE SIGNAL ;
    PORT
      LAYER M5 ;
        RECT  58.608 12.876 58.632 12.96 ;
    END
  END q[188]
  PIN q[189]
    DIRECTION OUTPUT ;
    USE SIGNAL ;
    PORT
      LAYER M5 ;
        RECT  58.704 12.876 58.728 12.96 ;
    END
  END q[189]
  PIN q[18]
    DIRECTION OUTPUT ;
    USE SIGNAL ;
    PORT
      LAYER M5 ;
        RECT  31.536 12.876 31.56 12.96 ;
    END
  END q[18]
  PIN q[190]
    DIRECTION OUTPUT ;
    USE SIGNAL ;
    PORT
      LAYER M5 ;
        RECT  58.8 12.876 58.824 12.96 ;
    END
  END q[190]
  PIN q[191]
    DIRECTION OUTPUT ;
    USE SIGNAL ;
    PORT
      LAYER M5 ;
        RECT  58.896 12.876 58.92 12.96 ;
    END
  END q[191]
  PIN q[192]
    DIRECTION OUTPUT ;
    USE SIGNAL ;
    PORT
      LAYER M5 ;
        RECT  58.992 12.876 59.016 12.96 ;
    END
  END q[192]
  PIN q[193]
    DIRECTION OUTPUT ;
    USE SIGNAL ;
    PORT
      LAYER M5 ;
        RECT  59.088 12.876 59.112 12.96 ;
    END
  END q[193]
  PIN q[194]
    DIRECTION OUTPUT ;
    USE SIGNAL ;
    PORT
      LAYER M5 ;
        RECT  59.184 12.876 59.208 12.96 ;
    END
  END q[194]
  PIN q[195]
    DIRECTION OUTPUT ;
    USE SIGNAL ;
    PORT
      LAYER M5 ;
        RECT  59.28 12.876 59.304 12.96 ;
    END
  END q[195]
  PIN q[196]
    DIRECTION OUTPUT ;
    USE SIGNAL ;
    PORT
      LAYER M5 ;
        RECT  59.376 12.876 59.4 12.96 ;
    END
  END q[196]
  PIN q[197]
    DIRECTION OUTPUT ;
    USE SIGNAL ;
    PORT
      LAYER M5 ;
        RECT  59.472 12.876 59.496 12.96 ;
    END
  END q[197]
  PIN q[198]
    DIRECTION OUTPUT ;
    USE SIGNAL ;
    PORT
      LAYER M5 ;
        RECT  59.568 12.876 59.592 12.96 ;
    END
  END q[198]
  PIN q[199]
    DIRECTION OUTPUT ;
    USE SIGNAL ;
    PORT
      LAYER M5 ;
        RECT  59.664 12.876 59.688 12.96 ;
    END
  END q[199]
  PIN q[19]
    DIRECTION OUTPUT ;
    USE SIGNAL ;
    PORT
      LAYER M5 ;
        RECT  31.632 12.876 31.656 12.96 ;
    END
  END q[19]
  PIN q[1]
    DIRECTION OUTPUT ;
    USE SIGNAL ;
    PORT
      LAYER M5 ;
        RECT  29.904 12.876 29.928 12.96 ;
    END
  END q[1]
  PIN q[200]
    DIRECTION OUTPUT ;
    USE SIGNAL ;
    PORT
      LAYER M5 ;
        RECT  59.76 12.876 59.784 12.96 ;
    END
  END q[200]
  PIN q[201]
    DIRECTION OUTPUT ;
    USE SIGNAL ;
    PORT
      LAYER M5 ;
        RECT  59.856 12.876 59.88 12.96 ;
    END
  END q[201]
  PIN q[202]
    DIRECTION OUTPUT ;
    USE SIGNAL ;
    PORT
      LAYER M5 ;
        RECT  59.952 12.876 59.976 12.96 ;
    END
  END q[202]
  PIN q[203]
    DIRECTION OUTPUT ;
    USE SIGNAL ;
    PORT
      LAYER M5 ;
        RECT  60.048 12.876 60.072 12.96 ;
    END
  END q[203]
  PIN q[204]
    DIRECTION OUTPUT ;
    USE SIGNAL ;
    PORT
      LAYER M5 ;
        RECT  60.144 12.876 60.168 12.96 ;
    END
  END q[204]
  PIN q[205]
    DIRECTION OUTPUT ;
    USE SIGNAL ;
    PORT
      LAYER M5 ;
        RECT  60.24 12.876 60.264 12.96 ;
    END
  END q[205]
  PIN q[206]
    DIRECTION OUTPUT ;
    USE SIGNAL ;
    PORT
      LAYER M5 ;
        RECT  60.336 12.876 60.36 12.96 ;
    END
  END q[206]
  PIN q[207]
    DIRECTION OUTPUT ;
    USE SIGNAL ;
    PORT
      LAYER M5 ;
        RECT  60.432 12.876 60.456 12.96 ;
    END
  END q[207]
  PIN q[208]
    DIRECTION OUTPUT ;
    USE SIGNAL ;
    PORT
      LAYER M5 ;
        RECT  60.528 12.876 60.552 12.96 ;
    END
  END q[208]
  PIN q[209]
    DIRECTION OUTPUT ;
    USE SIGNAL ;
    PORT
      LAYER M5 ;
        RECT  60.624 12.876 60.648 12.96 ;
    END
  END q[209]
  PIN q[20]
    DIRECTION OUTPUT ;
    USE SIGNAL ;
    PORT
      LAYER M5 ;
        RECT  31.728 12.876 31.752 12.96 ;
    END
  END q[20]
  PIN q[210]
    DIRECTION OUTPUT ;
    USE SIGNAL ;
    PORT
      LAYER M5 ;
        RECT  60.72 12.876 60.744 12.96 ;
    END
  END q[210]
  PIN q[211]
    DIRECTION OUTPUT ;
    USE SIGNAL ;
    PORT
      LAYER M5 ;
        RECT  60.816 12.876 60.84 12.96 ;
    END
  END q[211]
  PIN q[212]
    DIRECTION OUTPUT ;
    USE SIGNAL ;
    PORT
      LAYER M5 ;
        RECT  60.912 12.876 60.936 12.96 ;
    END
  END q[212]
  PIN q[213]
    DIRECTION OUTPUT ;
    USE SIGNAL ;
    PORT
      LAYER M5 ;
        RECT  61.008 12.876 61.032 12.96 ;
    END
  END q[213]
  PIN q[214]
    DIRECTION OUTPUT ;
    USE SIGNAL ;
    PORT
      LAYER M5 ;
        RECT  61.104 12.876 61.128 12.96 ;
    END
  END q[214]
  PIN q[215]
    DIRECTION OUTPUT ;
    USE SIGNAL ;
    PORT
      LAYER M5 ;
        RECT  61.2 12.876 61.224 12.96 ;
    END
  END q[215]
  PIN q[216]
    DIRECTION OUTPUT ;
    USE SIGNAL ;
    PORT
      LAYER M5 ;
        RECT  61.296 12.876 61.32 12.96 ;
    END
  END q[216]
  PIN q[217]
    DIRECTION OUTPUT ;
    USE SIGNAL ;
    PORT
      LAYER M5 ;
        RECT  61.392 12.876 61.416 12.96 ;
    END
  END q[217]
  PIN q[218]
    DIRECTION OUTPUT ;
    USE SIGNAL ;
    PORT
      LAYER M5 ;
        RECT  61.488 12.876 61.512 12.96 ;
    END
  END q[218]
  PIN q[219]
    DIRECTION OUTPUT ;
    USE SIGNAL ;
    PORT
      LAYER M5 ;
        RECT  61.584 12.876 61.608 12.96 ;
    END
  END q[219]
  PIN q[21]
    DIRECTION OUTPUT ;
    USE SIGNAL ;
    PORT
      LAYER M5 ;
        RECT  31.824 12.876 31.848 12.96 ;
    END
  END q[21]
  PIN q[220]
    DIRECTION OUTPUT ;
    USE SIGNAL ;
    PORT
      LAYER M5 ;
        RECT  61.68 12.876 61.704 12.96 ;
    END
  END q[220]
  PIN q[221]
    DIRECTION OUTPUT ;
    USE SIGNAL ;
    PORT
      LAYER M5 ;
        RECT  61.776 12.876 61.8 12.96 ;
    END
  END q[221]
  PIN q[222]
    DIRECTION OUTPUT ;
    USE SIGNAL ;
    PORT
      LAYER M5 ;
        RECT  61.872 12.876 61.896 12.96 ;
    END
  END q[222]
  PIN q[223]
    DIRECTION OUTPUT ;
    USE SIGNAL ;
    PORT
      LAYER M5 ;
        RECT  61.968 12.876 61.992 12.96 ;
    END
  END q[223]
  PIN q[224]
    DIRECTION OUTPUT ;
    USE SIGNAL ;
    PORT
      LAYER M5 ;
        RECT  45.936 12.876 45.96 12.96 ;
    END
  END q[224]
  PIN q[225]
    DIRECTION OUTPUT ;
    USE SIGNAL ;
    PORT
      LAYER M5 ;
        RECT  46.032 12.876 46.056 12.96 ;
    END
  END q[225]
  PIN q[226]
    DIRECTION OUTPUT ;
    USE SIGNAL ;
    PORT
      LAYER M5 ;
        RECT  46.128 12.876 46.152 12.96 ;
    END
  END q[226]
  PIN q[227]
    DIRECTION OUTPUT ;
    USE SIGNAL ;
    PORT
      LAYER M5 ;
        RECT  46.224 12.876 46.248 12.96 ;
    END
  END q[227]
  PIN q[228]
    DIRECTION OUTPUT ;
    USE SIGNAL ;
    PORT
      LAYER M5 ;
        RECT  46.32 12.876 46.344 12.96 ;
    END
  END q[228]
  PIN q[229]
    DIRECTION OUTPUT ;
    USE SIGNAL ;
    PORT
      LAYER M5 ;
        RECT  46.416 12.876 46.44 12.96 ;
    END
  END q[229]
  PIN q[22]
    DIRECTION OUTPUT ;
    USE SIGNAL ;
    PORT
      LAYER M5 ;
        RECT  31.92 12.876 31.944 12.96 ;
    END
  END q[22]
  PIN q[230]
    DIRECTION OUTPUT ;
    USE SIGNAL ;
    PORT
      LAYER M5 ;
        RECT  46.512 12.876 46.536 12.96 ;
    END
  END q[230]
  PIN q[231]
    DIRECTION OUTPUT ;
    USE SIGNAL ;
    PORT
      LAYER M5 ;
        RECT  46.608 12.876 46.632 12.96 ;
    END
  END q[231]
  PIN q[232]
    DIRECTION OUTPUT ;
    USE SIGNAL ;
    PORT
      LAYER M5 ;
        RECT  46.704 12.876 46.728 12.96 ;
    END
  END q[232]
  PIN q[233]
    DIRECTION OUTPUT ;
    USE SIGNAL ;
    PORT
      LAYER M5 ;
        RECT  46.8 12.876 46.824 12.96 ;
    END
  END q[233]
  PIN q[234]
    DIRECTION OUTPUT ;
    USE SIGNAL ;
    PORT
      LAYER M5 ;
        RECT  46.896 12.876 46.92 12.96 ;
    END
  END q[234]
  PIN q[235]
    DIRECTION OUTPUT ;
    USE SIGNAL ;
    PORT
      LAYER M5 ;
        RECT  46.992 12.876 47.016 12.96 ;
    END
  END q[235]
  PIN q[236]
    DIRECTION OUTPUT ;
    USE SIGNAL ;
    PORT
      LAYER M5 ;
        RECT  47.088 12.876 47.112 12.96 ;
    END
  END q[236]
  PIN q[237]
    DIRECTION OUTPUT ;
    USE SIGNAL ;
    PORT
      LAYER M5 ;
        RECT  47.184 12.876 47.208 12.96 ;
    END
  END q[237]
  PIN q[238]
    DIRECTION OUTPUT ;
    USE SIGNAL ;
    PORT
      LAYER M5 ;
        RECT  47.28 12.876 47.304 12.96 ;
    END
  END q[238]
  PIN q[239]
    DIRECTION OUTPUT ;
    USE SIGNAL ;
    PORT
      LAYER M5 ;
        RECT  47.376 12.876 47.4 12.96 ;
    END
  END q[239]
  PIN q[23]
    DIRECTION OUTPUT ;
    USE SIGNAL ;
    PORT
      LAYER M5 ;
        RECT  32.016 12.876 32.04 12.96 ;
    END
  END q[23]
  PIN q[240]
    DIRECTION OUTPUT ;
    USE SIGNAL ;
    PORT
      LAYER M5 ;
        RECT  47.472 12.876 47.496 12.96 ;
    END
  END q[240]
  PIN q[241]
    DIRECTION OUTPUT ;
    USE SIGNAL ;
    PORT
      LAYER M5 ;
        RECT  47.568 12.876 47.592 12.96 ;
    END
  END q[241]
  PIN q[242]
    DIRECTION OUTPUT ;
    USE SIGNAL ;
    PORT
      LAYER M5 ;
        RECT  47.664 12.876 47.688 12.96 ;
    END
  END q[242]
  PIN q[243]
    DIRECTION OUTPUT ;
    USE SIGNAL ;
    PORT
      LAYER M5 ;
        RECT  47.76 12.876 47.784 12.96 ;
    END
  END q[243]
  PIN q[244]
    DIRECTION OUTPUT ;
    USE SIGNAL ;
    PORT
      LAYER M5 ;
        RECT  47.856 12.876 47.88 12.96 ;
    END
  END q[244]
  PIN q[245]
    DIRECTION OUTPUT ;
    USE SIGNAL ;
    PORT
      LAYER M5 ;
        RECT  47.952 12.876 47.976 12.96 ;
    END
  END q[245]
  PIN q[246]
    DIRECTION OUTPUT ;
    USE SIGNAL ;
    PORT
      LAYER M5 ;
        RECT  48.048 12.876 48.072 12.96 ;
    END
  END q[246]
  PIN q[247]
    DIRECTION OUTPUT ;
    USE SIGNAL ;
    PORT
      LAYER M5 ;
        RECT  48.144 12.876 48.168 12.96 ;
    END
  END q[247]
  PIN q[248]
    DIRECTION OUTPUT ;
    USE SIGNAL ;
    PORT
      LAYER M5 ;
        RECT  48.24 12.876 48.264 12.96 ;
    END
  END q[248]
  PIN q[249]
    DIRECTION OUTPUT ;
    USE SIGNAL ;
    PORT
      LAYER M5 ;
        RECT  48.336 12.876 48.36 12.96 ;
    END
  END q[249]
  PIN q[24]
    DIRECTION OUTPUT ;
    USE SIGNAL ;
    PORT
      LAYER M5 ;
        RECT  32.112 12.876 32.136 12.96 ;
    END
  END q[24]
  PIN q[250]
    DIRECTION OUTPUT ;
    USE SIGNAL ;
    PORT
      LAYER M5 ;
        RECT  48.432 12.876 48.456 12.96 ;
    END
  END q[250]
  PIN q[251]
    DIRECTION OUTPUT ;
    USE SIGNAL ;
    PORT
      LAYER M5 ;
        RECT  48.528 12.876 48.552 12.96 ;
    END
  END q[251]
  PIN q[252]
    DIRECTION OUTPUT ;
    USE SIGNAL ;
    PORT
      LAYER M5 ;
        RECT  48.624 12.876 48.648 12.96 ;
    END
  END q[252]
  PIN q[253]
    DIRECTION OUTPUT ;
    USE SIGNAL ;
    PORT
      LAYER M5 ;
        RECT  48.72 12.876 48.744 12.96 ;
    END
  END q[253]
  PIN q[254]
    DIRECTION OUTPUT ;
    USE SIGNAL ;
    PORT
      LAYER M5 ;
        RECT  48.816 12.876 48.84 12.96 ;
    END
  END q[254]
  PIN q[255]
    DIRECTION OUTPUT ;
    USE SIGNAL ;
    PORT
      LAYER M5 ;
        RECT  48.912 12.876 48.936 12.96 ;
    END
  END q[255]
  PIN q[256]
    DIRECTION OUTPUT ;
    USE SIGNAL ;
    PORT
      LAYER M5 ;
        RECT  94.32 12.876 94.344 12.96 ;
    END
  END q[256]
  PIN q[257]
    DIRECTION OUTPUT ;
    USE SIGNAL ;
    PORT
      LAYER M5 ;
        RECT  94.416 12.876 94.44 12.96 ;
    END
  END q[257]
  PIN q[258]
    DIRECTION OUTPUT ;
    USE SIGNAL ;
    PORT
      LAYER M5 ;
        RECT  94.512 12.876 94.536 12.96 ;
    END
  END q[258]
  PIN q[259]
    DIRECTION OUTPUT ;
    USE SIGNAL ;
    PORT
      LAYER M5 ;
        RECT  94.608 12.876 94.632 12.96 ;
    END
  END q[259]
  PIN q[25]
    DIRECTION OUTPUT ;
    USE SIGNAL ;
    PORT
      LAYER M5 ;
        RECT  32.208 12.876 32.232 12.96 ;
    END
  END q[25]
  PIN q[260]
    DIRECTION OUTPUT ;
    USE SIGNAL ;
    PORT
      LAYER M5 ;
        RECT  94.704 12.876 94.728 12.96 ;
    END
  END q[260]
  PIN q[261]
    DIRECTION OUTPUT ;
    USE SIGNAL ;
    PORT
      LAYER M5 ;
        RECT  94.8 12.876 94.824 12.96 ;
    END
  END q[261]
  PIN q[262]
    DIRECTION OUTPUT ;
    USE SIGNAL ;
    PORT
      LAYER M5 ;
        RECT  94.896 12.876 94.92 12.96 ;
    END
  END q[262]
  PIN q[263]
    DIRECTION OUTPUT ;
    USE SIGNAL ;
    PORT
      LAYER M5 ;
        RECT  94.992 12.876 95.016 12.96 ;
    END
  END q[263]
  PIN q[264]
    DIRECTION OUTPUT ;
    USE SIGNAL ;
    PORT
      LAYER M5 ;
        RECT  95.088 12.876 95.112 12.96 ;
    END
  END q[264]
  PIN q[265]
    DIRECTION OUTPUT ;
    USE SIGNAL ;
    PORT
      LAYER M5 ;
        RECT  95.184 12.876 95.208 12.96 ;
    END
  END q[265]
  PIN q[266]
    DIRECTION OUTPUT ;
    USE SIGNAL ;
    PORT
      LAYER M5 ;
        RECT  95.28 12.876 95.304 12.96 ;
    END
  END q[266]
  PIN q[267]
    DIRECTION OUTPUT ;
    USE SIGNAL ;
    PORT
      LAYER M5 ;
        RECT  95.376 12.876 95.4 12.96 ;
    END
  END q[267]
  PIN q[268]
    DIRECTION OUTPUT ;
    USE SIGNAL ;
    PORT
      LAYER M5 ;
        RECT  95.472 12.876 95.496 12.96 ;
    END
  END q[268]
  PIN q[269]
    DIRECTION OUTPUT ;
    USE SIGNAL ;
    PORT
      LAYER M5 ;
        RECT  95.568 12.876 95.592 12.96 ;
    END
  END q[269]
  PIN q[26]
    DIRECTION OUTPUT ;
    USE SIGNAL ;
    PORT
      LAYER M5 ;
        RECT  32.304 12.876 32.328 12.96 ;
    END
  END q[26]
  PIN q[270]
    DIRECTION OUTPUT ;
    USE SIGNAL ;
    PORT
      LAYER M5 ;
        RECT  95.664 12.876 95.688 12.96 ;
    END
  END q[270]
  PIN q[271]
    DIRECTION OUTPUT ;
    USE SIGNAL ;
    PORT
      LAYER M5 ;
        RECT  95.76 12.876 95.784 12.96 ;
    END
  END q[271]
  PIN q[272]
    DIRECTION OUTPUT ;
    USE SIGNAL ;
    PORT
      LAYER M5 ;
        RECT  95.856 12.876 95.88 12.96 ;
    END
  END q[272]
  PIN q[273]
    DIRECTION OUTPUT ;
    USE SIGNAL ;
    PORT
      LAYER M5 ;
        RECT  95.952 12.876 95.976 12.96 ;
    END
  END q[273]
  PIN q[274]
    DIRECTION OUTPUT ;
    USE SIGNAL ;
    PORT
      LAYER M5 ;
        RECT  96.048 12.876 96.072 12.96 ;
    END
  END q[274]
  PIN q[275]
    DIRECTION OUTPUT ;
    USE SIGNAL ;
    PORT
      LAYER M5 ;
        RECT  96.144 12.876 96.168 12.96 ;
    END
  END q[275]
  PIN q[276]
    DIRECTION OUTPUT ;
    USE SIGNAL ;
    PORT
      LAYER M5 ;
        RECT  96.24 12.876 96.264 12.96 ;
    END
  END q[276]
  PIN q[277]
    DIRECTION OUTPUT ;
    USE SIGNAL ;
    PORT
      LAYER M5 ;
        RECT  96.336 12.876 96.36 12.96 ;
    END
  END q[277]
  PIN q[278]
    DIRECTION OUTPUT ;
    USE SIGNAL ;
    PORT
      LAYER M5 ;
        RECT  96.432 12.876 96.456 12.96 ;
    END
  END q[278]
  PIN q[279]
    DIRECTION OUTPUT ;
    USE SIGNAL ;
    PORT
      LAYER M5 ;
        RECT  96.528 12.876 96.552 12.96 ;
    END
  END q[279]
  PIN q[27]
    DIRECTION OUTPUT ;
    USE SIGNAL ;
    PORT
      LAYER M5 ;
        RECT  32.4 12.876 32.424 12.96 ;
    END
  END q[27]
  PIN q[280]
    DIRECTION OUTPUT ;
    USE SIGNAL ;
    PORT
      LAYER M5 ;
        RECT  96.624 12.876 96.648 12.96 ;
    END
  END q[280]
  PIN q[281]
    DIRECTION OUTPUT ;
    USE SIGNAL ;
    PORT
      LAYER M5 ;
        RECT  96.72 12.876 96.744 12.96 ;
    END
  END q[281]
  PIN q[282]
    DIRECTION OUTPUT ;
    USE SIGNAL ;
    PORT
      LAYER M5 ;
        RECT  96.816 12.876 96.84 12.96 ;
    END
  END q[282]
  PIN q[283]
    DIRECTION OUTPUT ;
    USE SIGNAL ;
    PORT
      LAYER M5 ;
        RECT  96.912 12.876 96.936 12.96 ;
    END
  END q[283]
  PIN q[284]
    DIRECTION OUTPUT ;
    USE SIGNAL ;
    PORT
      LAYER M5 ;
        RECT  97.008 12.876 97.032 12.96 ;
    END
  END q[284]
  PIN q[285]
    DIRECTION OUTPUT ;
    USE SIGNAL ;
    PORT
      LAYER M5 ;
        RECT  97.104 12.876 97.128 12.96 ;
    END
  END q[285]
  PIN q[286]
    DIRECTION OUTPUT ;
    USE SIGNAL ;
    PORT
      LAYER M5 ;
        RECT  97.2 12.876 97.224 12.96 ;
    END
  END q[286]
  PIN q[287]
    DIRECTION OUTPUT ;
    USE SIGNAL ;
    PORT
      LAYER M5 ;
        RECT  97.296 12.876 97.32 12.96 ;
    END
  END q[287]
  PIN q[288]
    DIRECTION OUTPUT ;
    USE SIGNAL ;
    PORT
      LAYER M5 ;
        RECT  97.392 12.876 97.416 12.96 ;
    END
  END q[288]
  PIN q[289]
    DIRECTION OUTPUT ;
    USE SIGNAL ;
    PORT
      LAYER M5 ;
        RECT  97.488 12.876 97.512 12.96 ;
    END
  END q[289]
  PIN q[28]
    DIRECTION OUTPUT ;
    USE SIGNAL ;
    PORT
      LAYER M5 ;
        RECT  32.496 12.876 32.52 12.96 ;
    END
  END q[28]
  PIN q[290]
    DIRECTION OUTPUT ;
    USE SIGNAL ;
    PORT
      LAYER M5 ;
        RECT  97.584 12.876 97.608 12.96 ;
    END
  END q[290]
  PIN q[291]
    DIRECTION OUTPUT ;
    USE SIGNAL ;
    PORT
      LAYER M5 ;
        RECT  97.68 12.876 97.704 12.96 ;
    END
  END q[291]
  PIN q[292]
    DIRECTION OUTPUT ;
    USE SIGNAL ;
    PORT
      LAYER M5 ;
        RECT  97.776 12.876 97.8 12.96 ;
    END
  END q[292]
  PIN q[293]
    DIRECTION OUTPUT ;
    USE SIGNAL ;
    PORT
      LAYER M5 ;
        RECT  97.872 12.876 97.896 12.96 ;
    END
  END q[293]
  PIN q[294]
    DIRECTION OUTPUT ;
    USE SIGNAL ;
    PORT
      LAYER M5 ;
        RECT  97.968 12.876 97.992 12.96 ;
    END
  END q[294]
  PIN q[295]
    DIRECTION OUTPUT ;
    USE SIGNAL ;
    PORT
      LAYER M5 ;
        RECT  98.064 12.876 98.088 12.96 ;
    END
  END q[295]
  PIN q[296]
    DIRECTION OUTPUT ;
    USE SIGNAL ;
    PORT
      LAYER M5 ;
        RECT  98.16 12.876 98.184 12.96 ;
    END
  END q[296]
  PIN q[297]
    DIRECTION OUTPUT ;
    USE SIGNAL ;
    PORT
      LAYER M5 ;
        RECT  98.256 12.876 98.28 12.96 ;
    END
  END q[297]
  PIN q[298]
    DIRECTION OUTPUT ;
    USE SIGNAL ;
    PORT
      LAYER M5 ;
        RECT  98.352 12.876 98.376 12.96 ;
    END
  END q[298]
  PIN q[299]
    DIRECTION OUTPUT ;
    USE SIGNAL ;
    PORT
      LAYER M5 ;
        RECT  98.448 12.876 98.472 12.96 ;
    END
  END q[299]
  PIN q[29]
    DIRECTION OUTPUT ;
    USE SIGNAL ;
    PORT
      LAYER M5 ;
        RECT  32.592 12.876 32.616 12.96 ;
    END
  END q[29]
  PIN q[2]
    DIRECTION OUTPUT ;
    USE SIGNAL ;
    PORT
      LAYER M5 ;
        RECT  30 12.876 30.024 12.96 ;
    END
  END q[2]
  PIN q[300]
    DIRECTION OUTPUT ;
    USE SIGNAL ;
    PORT
      LAYER M5 ;
        RECT  98.544 12.876 98.568 12.96 ;
    END
  END q[300]
  PIN q[301]
    DIRECTION OUTPUT ;
    USE SIGNAL ;
    PORT
      LAYER M5 ;
        RECT  98.64 12.876 98.664 12.96 ;
    END
  END q[301]
  PIN q[302]
    DIRECTION OUTPUT ;
    USE SIGNAL ;
    PORT
      LAYER M5 ;
        RECT  98.736 12.876 98.76 12.96 ;
    END
  END q[302]
  PIN q[303]
    DIRECTION OUTPUT ;
    USE SIGNAL ;
    PORT
      LAYER M5 ;
        RECT  98.832 12.876 98.856 12.96 ;
    END
  END q[303]
  PIN q[304]
    DIRECTION OUTPUT ;
    USE SIGNAL ;
    PORT
      LAYER M5 ;
        RECT  98.928 12.876 98.952 12.96 ;
    END
  END q[304]
  PIN q[305]
    DIRECTION OUTPUT ;
    USE SIGNAL ;
    PORT
      LAYER M5 ;
        RECT  99.024 12.876 99.048 12.96 ;
    END
  END q[305]
  PIN q[306]
    DIRECTION OUTPUT ;
    USE SIGNAL ;
    PORT
      LAYER M5 ;
        RECT  99.12 12.876 99.144 12.96 ;
    END
  END q[306]
  PIN q[307]
    DIRECTION OUTPUT ;
    USE SIGNAL ;
    PORT
      LAYER M5 ;
        RECT  99.216 12.876 99.24 12.96 ;
    END
  END q[307]
  PIN q[308]
    DIRECTION OUTPUT ;
    USE SIGNAL ;
    PORT
      LAYER M5 ;
        RECT  99.312 12.876 99.336 12.96 ;
    END
  END q[308]
  PIN q[309]
    DIRECTION OUTPUT ;
    USE SIGNAL ;
    PORT
      LAYER M5 ;
        RECT  99.408 12.876 99.432 12.96 ;
    END
  END q[309]
  PIN q[30]
    DIRECTION OUTPUT ;
    USE SIGNAL ;
    PORT
      LAYER M5 ;
        RECT  32.688 12.876 32.712 12.96 ;
    END
  END q[30]
  PIN q[310]
    DIRECTION OUTPUT ;
    USE SIGNAL ;
    PORT
      LAYER M5 ;
        RECT  99.504 12.876 99.528 12.96 ;
    END
  END q[310]
  PIN q[311]
    DIRECTION OUTPUT ;
    USE SIGNAL ;
    PORT
      LAYER M5 ;
        RECT  99.6 12.876 99.624 12.96 ;
    END
  END q[311]
  PIN q[312]
    DIRECTION OUTPUT ;
    USE SIGNAL ;
    PORT
      LAYER M5 ;
        RECT  99.696 12.876 99.72 12.96 ;
    END
  END q[312]
  PIN q[313]
    DIRECTION OUTPUT ;
    USE SIGNAL ;
    PORT
      LAYER M5 ;
        RECT  99.792 12.876 99.816 12.96 ;
    END
  END q[313]
  PIN q[314]
    DIRECTION OUTPUT ;
    USE SIGNAL ;
    PORT
      LAYER M5 ;
        RECT  99.888 12.876 99.912 12.96 ;
    END
  END q[314]
  PIN q[315]
    DIRECTION OUTPUT ;
    USE SIGNAL ;
    PORT
      LAYER M5 ;
        RECT  99.984 12.876 100.008 12.96 ;
    END
  END q[315]
  PIN q[316]
    DIRECTION OUTPUT ;
    USE SIGNAL ;
    PORT
      LAYER M5 ;
        RECT  100.08 12.876 100.104 12.96 ;
    END
  END q[316]
  PIN q[317]
    DIRECTION OUTPUT ;
    USE SIGNAL ;
    PORT
      LAYER M5 ;
        RECT  100.176 12.876 100.2 12.96 ;
    END
  END q[317]
  PIN q[318]
    DIRECTION OUTPUT ;
    USE SIGNAL ;
    PORT
      LAYER M5 ;
        RECT  100.272 12.876 100.296 12.96 ;
    END
  END q[318]
  PIN q[319]
    DIRECTION OUTPUT ;
    USE SIGNAL ;
    PORT
      LAYER M5 ;
        RECT  100.368 12.876 100.392 12.96 ;
    END
  END q[319]
  PIN q[31]
    DIRECTION OUTPUT ;
    USE SIGNAL ;
    PORT
      LAYER M5 ;
        RECT  32.784 12.876 32.808 12.96 ;
    END
  END q[31]
  PIN q[320]
    DIRECTION OUTPUT ;
    USE SIGNAL ;
    PORT
      LAYER M5 ;
        RECT  91.248 12.876 91.272 12.96 ;
    END
  END q[320]
  PIN q[321]
    DIRECTION OUTPUT ;
    USE SIGNAL ;
    PORT
      LAYER M5 ;
        RECT  91.344 12.876 91.368 12.96 ;
    END
  END q[321]
  PIN q[322]
    DIRECTION OUTPUT ;
    USE SIGNAL ;
    PORT
      LAYER M5 ;
        RECT  91.44 12.876 91.464 12.96 ;
    END
  END q[322]
  PIN q[323]
    DIRECTION OUTPUT ;
    USE SIGNAL ;
    PORT
      LAYER M5 ;
        RECT  91.536 12.876 91.56 12.96 ;
    END
  END q[323]
  PIN q[324]
    DIRECTION OUTPUT ;
    USE SIGNAL ;
    PORT
      LAYER M5 ;
        RECT  91.632 12.876 91.656 12.96 ;
    END
  END q[324]
  PIN q[325]
    DIRECTION OUTPUT ;
    USE SIGNAL ;
    PORT
      LAYER M5 ;
        RECT  91.728 12.876 91.752 12.96 ;
    END
  END q[325]
  PIN q[326]
    DIRECTION OUTPUT ;
    USE SIGNAL ;
    PORT
      LAYER M5 ;
        RECT  91.824 12.876 91.848 12.96 ;
    END
  END q[326]
  PIN q[327]
    DIRECTION OUTPUT ;
    USE SIGNAL ;
    PORT
      LAYER M5 ;
        RECT  91.92 12.876 91.944 12.96 ;
    END
  END q[327]
  PIN q[328]
    DIRECTION OUTPUT ;
    USE SIGNAL ;
    PORT
      LAYER M5 ;
        RECT  92.016 12.876 92.04 12.96 ;
    END
  END q[328]
  PIN q[329]
    DIRECTION OUTPUT ;
    USE SIGNAL ;
    PORT
      LAYER M5 ;
        RECT  92.112 12.876 92.136 12.96 ;
    END
  END q[329]
  PIN q[32]
    DIRECTION OUTPUT ;
    USE SIGNAL ;
    PORT
      LAYER M5 ;
        RECT  42.864 12.876 42.888 12.96 ;
    END
  END q[32]
  PIN q[330]
    DIRECTION OUTPUT ;
    USE SIGNAL ;
    PORT
      LAYER M5 ;
        RECT  92.208 12.876 92.232 12.96 ;
    END
  END q[330]
  PIN q[331]
    DIRECTION OUTPUT ;
    USE SIGNAL ;
    PORT
      LAYER M5 ;
        RECT  92.304 12.876 92.328 12.96 ;
    END
  END q[331]
  PIN q[332]
    DIRECTION OUTPUT ;
    USE SIGNAL ;
    PORT
      LAYER M5 ;
        RECT  92.4 12.876 92.424 12.96 ;
    END
  END q[332]
  PIN q[333]
    DIRECTION OUTPUT ;
    USE SIGNAL ;
    PORT
      LAYER M5 ;
        RECT  92.496 12.876 92.52 12.96 ;
    END
  END q[333]
  PIN q[334]
    DIRECTION OUTPUT ;
    USE SIGNAL ;
    PORT
      LAYER M5 ;
        RECT  92.592 12.876 92.616 12.96 ;
    END
  END q[334]
  PIN q[335]
    DIRECTION OUTPUT ;
    USE SIGNAL ;
    PORT
      LAYER M5 ;
        RECT  92.688 12.876 92.712 12.96 ;
    END
  END q[335]
  PIN q[336]
    DIRECTION OUTPUT ;
    USE SIGNAL ;
    PORT
      LAYER M5 ;
        RECT  92.784 12.876 92.808 12.96 ;
    END
  END q[336]
  PIN q[337]
    DIRECTION OUTPUT ;
    USE SIGNAL ;
    PORT
      LAYER M5 ;
        RECT  92.88 12.876 92.904 12.96 ;
    END
  END q[337]
  PIN q[338]
    DIRECTION OUTPUT ;
    USE SIGNAL ;
    PORT
      LAYER M5 ;
        RECT  92.976 12.876 93 12.96 ;
    END
  END q[338]
  PIN q[339]
    DIRECTION OUTPUT ;
    USE SIGNAL ;
    PORT
      LAYER M5 ;
        RECT  93.072 12.876 93.096 12.96 ;
    END
  END q[339]
  PIN q[33]
    DIRECTION OUTPUT ;
    USE SIGNAL ;
    PORT
      LAYER M5 ;
        RECT  42.96 12.876 42.984 12.96 ;
    END
  END q[33]
  PIN q[340]
    DIRECTION OUTPUT ;
    USE SIGNAL ;
    PORT
      LAYER M5 ;
        RECT  93.168 12.876 93.192 12.96 ;
    END
  END q[340]
  PIN q[341]
    DIRECTION OUTPUT ;
    USE SIGNAL ;
    PORT
      LAYER M5 ;
        RECT  93.264 12.876 93.288 12.96 ;
    END
  END q[341]
  PIN q[342]
    DIRECTION OUTPUT ;
    USE SIGNAL ;
    PORT
      LAYER M5 ;
        RECT  93.36 12.876 93.384 12.96 ;
    END
  END q[342]
  PIN q[343]
    DIRECTION OUTPUT ;
    USE SIGNAL ;
    PORT
      LAYER M5 ;
        RECT  93.456 12.876 93.48 12.96 ;
    END
  END q[343]
  PIN q[344]
    DIRECTION OUTPUT ;
    USE SIGNAL ;
    PORT
      LAYER M5 ;
        RECT  93.552 12.876 93.576 12.96 ;
    END
  END q[344]
  PIN q[345]
    DIRECTION OUTPUT ;
    USE SIGNAL ;
    PORT
      LAYER M5 ;
        RECT  93.648 12.876 93.672 12.96 ;
    END
  END q[345]
  PIN q[346]
    DIRECTION OUTPUT ;
    USE SIGNAL ;
    PORT
      LAYER M5 ;
        RECT  93.744 12.876 93.768 12.96 ;
    END
  END q[346]
  PIN q[347]
    DIRECTION OUTPUT ;
    USE SIGNAL ;
    PORT
      LAYER M5 ;
        RECT  93.84 12.876 93.864 12.96 ;
    END
  END q[347]
  PIN q[348]
    DIRECTION OUTPUT ;
    USE SIGNAL ;
    PORT
      LAYER M5 ;
        RECT  93.936 12.876 93.96 12.96 ;
    END
  END q[348]
  PIN q[349]
    DIRECTION OUTPUT ;
    USE SIGNAL ;
    PORT
      LAYER M5 ;
        RECT  94.032 12.876 94.056 12.96 ;
    END
  END q[349]
  PIN q[34]
    DIRECTION OUTPUT ;
    USE SIGNAL ;
    PORT
      LAYER M5 ;
        RECT  43.056 12.876 43.08 12.96 ;
    END
  END q[34]
  PIN q[350]
    DIRECTION OUTPUT ;
    USE SIGNAL ;
    PORT
      LAYER M5 ;
        RECT  94.128 12.876 94.152 12.96 ;
    END
  END q[350]
  PIN q[351]
    DIRECTION OUTPUT ;
    USE SIGNAL ;
    PORT
      LAYER M5 ;
        RECT  94.224 12.876 94.248 12.96 ;
    END
  END q[351]
  PIN q[352]
    DIRECTION OUTPUT ;
    USE SIGNAL ;
    PORT
      LAYER M5 ;
        RECT  84.336 12.876 84.36 12.96 ;
    END
  END q[352]
  PIN q[353]
    DIRECTION OUTPUT ;
    USE SIGNAL ;
    PORT
      LAYER M5 ;
        RECT  84.432 12.876 84.456 12.96 ;
    END
  END q[353]
  PIN q[354]
    DIRECTION OUTPUT ;
    USE SIGNAL ;
    PORT
      LAYER M5 ;
        RECT  84.528 12.876 84.552 12.96 ;
    END
  END q[354]
  PIN q[355]
    DIRECTION OUTPUT ;
    USE SIGNAL ;
    PORT
      LAYER M5 ;
        RECT  84.624 12.876 84.648 12.96 ;
    END
  END q[355]
  PIN q[356]
    DIRECTION OUTPUT ;
    USE SIGNAL ;
    PORT
      LAYER M5 ;
        RECT  84.72 12.876 84.744 12.96 ;
    END
  END q[356]
  PIN q[357]
    DIRECTION OUTPUT ;
    USE SIGNAL ;
    PORT
      LAYER M5 ;
        RECT  84.816 12.876 84.84 12.96 ;
    END
  END q[357]
  PIN q[358]
    DIRECTION OUTPUT ;
    USE SIGNAL ;
    PORT
      LAYER M5 ;
        RECT  84.912 12.876 84.936 12.96 ;
    END
  END q[358]
  PIN q[359]
    DIRECTION OUTPUT ;
    USE SIGNAL ;
    PORT
      LAYER M5 ;
        RECT  85.008 12.876 85.032 12.96 ;
    END
  END q[359]
  PIN q[35]
    DIRECTION OUTPUT ;
    USE SIGNAL ;
    PORT
      LAYER M5 ;
        RECT  43.152 12.876 43.176 12.96 ;
    END
  END q[35]
  PIN q[360]
    DIRECTION OUTPUT ;
    USE SIGNAL ;
    PORT
      LAYER M5 ;
        RECT  85.104 12.876 85.128 12.96 ;
    END
  END q[360]
  PIN q[361]
    DIRECTION OUTPUT ;
    USE SIGNAL ;
    PORT
      LAYER M5 ;
        RECT  85.2 12.876 85.224 12.96 ;
    END
  END q[361]
  PIN q[362]
    DIRECTION OUTPUT ;
    USE SIGNAL ;
    PORT
      LAYER M5 ;
        RECT  85.296 12.876 85.32 12.96 ;
    END
  END q[362]
  PIN q[363]
    DIRECTION OUTPUT ;
    USE SIGNAL ;
    PORT
      LAYER M5 ;
        RECT  85.392 12.876 85.416 12.96 ;
    END
  END q[363]
  PIN q[364]
    DIRECTION OUTPUT ;
    USE SIGNAL ;
    PORT
      LAYER M5 ;
        RECT  85.488 12.876 85.512 12.96 ;
    END
  END q[364]
  PIN q[365]
    DIRECTION OUTPUT ;
    USE SIGNAL ;
    PORT
      LAYER M5 ;
        RECT  85.584 12.876 85.608 12.96 ;
    END
  END q[365]
  PIN q[366]
    DIRECTION OUTPUT ;
    USE SIGNAL ;
    PORT
      LAYER M5 ;
        RECT  85.68 12.876 85.704 12.96 ;
    END
  END q[366]
  PIN q[367]
    DIRECTION OUTPUT ;
    USE SIGNAL ;
    PORT
      LAYER M5 ;
        RECT  85.776 12.876 85.8 12.96 ;
    END
  END q[367]
  PIN q[368]
    DIRECTION OUTPUT ;
    USE SIGNAL ;
    PORT
      LAYER M5 ;
        RECT  85.872 12.876 85.896 12.96 ;
    END
  END q[368]
  PIN q[369]
    DIRECTION OUTPUT ;
    USE SIGNAL ;
    PORT
      LAYER M5 ;
        RECT  85.968 12.876 85.992 12.96 ;
    END
  END q[369]
  PIN q[36]
    DIRECTION OUTPUT ;
    USE SIGNAL ;
    PORT
      LAYER M5 ;
        RECT  43.248 12.876 43.272 12.96 ;
    END
  END q[36]
  PIN q[370]
    DIRECTION OUTPUT ;
    USE SIGNAL ;
    PORT
      LAYER M5 ;
        RECT  86.064 12.876 86.088 12.96 ;
    END
  END q[370]
  PIN q[371]
    DIRECTION OUTPUT ;
    USE SIGNAL ;
    PORT
      LAYER M5 ;
        RECT  86.16 12.876 86.184 12.96 ;
    END
  END q[371]
  PIN q[372]
    DIRECTION OUTPUT ;
    USE SIGNAL ;
    PORT
      LAYER M5 ;
        RECT  86.256 12.876 86.28 12.96 ;
    END
  END q[372]
  PIN q[373]
    DIRECTION OUTPUT ;
    USE SIGNAL ;
    PORT
      LAYER M5 ;
        RECT  86.352 12.876 86.376 12.96 ;
    END
  END q[373]
  PIN q[374]
    DIRECTION OUTPUT ;
    USE SIGNAL ;
    PORT
      LAYER M5 ;
        RECT  86.448 12.876 86.472 12.96 ;
    END
  END q[374]
  PIN q[375]
    DIRECTION OUTPUT ;
    USE SIGNAL ;
    PORT
      LAYER M5 ;
        RECT  86.544 12.876 86.568 12.96 ;
    END
  END q[375]
  PIN q[376]
    DIRECTION OUTPUT ;
    USE SIGNAL ;
    PORT
      LAYER M5 ;
        RECT  86.64 12.876 86.664 12.96 ;
    END
  END q[376]
  PIN q[377]
    DIRECTION OUTPUT ;
    USE SIGNAL ;
    PORT
      LAYER M5 ;
        RECT  86.736 12.876 86.76 12.96 ;
    END
  END q[377]
  PIN q[378]
    DIRECTION OUTPUT ;
    USE SIGNAL ;
    PORT
      LAYER M5 ;
        RECT  86.832 12.876 86.856 12.96 ;
    END
  END q[378]
  PIN q[379]
    DIRECTION OUTPUT ;
    USE SIGNAL ;
    PORT
      LAYER M5 ;
        RECT  86.928 12.876 86.952 12.96 ;
    END
  END q[379]
  PIN q[37]
    DIRECTION OUTPUT ;
    USE SIGNAL ;
    PORT
      LAYER M5 ;
        RECT  43.344 12.876 43.368 12.96 ;
    END
  END q[37]
  PIN q[380]
    DIRECTION OUTPUT ;
    USE SIGNAL ;
    PORT
      LAYER M5 ;
        RECT  87.024 12.876 87.048 12.96 ;
    END
  END q[380]
  PIN q[381]
    DIRECTION OUTPUT ;
    USE SIGNAL ;
    PORT
      LAYER M5 ;
        RECT  87.12 12.876 87.144 12.96 ;
    END
  END q[381]
  PIN q[382]
    DIRECTION OUTPUT ;
    USE SIGNAL ;
    PORT
      LAYER M5 ;
        RECT  87.216 12.876 87.24 12.96 ;
    END
  END q[382]
  PIN q[383]
    DIRECTION OUTPUT ;
    USE SIGNAL ;
    PORT
      LAYER M5 ;
        RECT  87.312 12.876 87.336 12.96 ;
    END
  END q[383]
  PIN q[384]
    DIRECTION OUTPUT ;
    USE SIGNAL ;
    PORT
      LAYER M5 ;
        RECT  75.12 12.876 75.144 12.96 ;
    END
  END q[384]
  PIN q[385]
    DIRECTION OUTPUT ;
    USE SIGNAL ;
    PORT
      LAYER M5 ;
        RECT  75.216 12.876 75.24 12.96 ;
    END
  END q[385]
  PIN q[386]
    DIRECTION OUTPUT ;
    USE SIGNAL ;
    PORT
      LAYER M5 ;
        RECT  75.312 12.876 75.336 12.96 ;
    END
  END q[386]
  PIN q[387]
    DIRECTION OUTPUT ;
    USE SIGNAL ;
    PORT
      LAYER M5 ;
        RECT  75.408 12.876 75.432 12.96 ;
    END
  END q[387]
  PIN q[388]
    DIRECTION OUTPUT ;
    USE SIGNAL ;
    PORT
      LAYER M5 ;
        RECT  75.504 12.876 75.528 12.96 ;
    END
  END q[388]
  PIN q[389]
    DIRECTION OUTPUT ;
    USE SIGNAL ;
    PORT
      LAYER M5 ;
        RECT  75.6 12.876 75.624 12.96 ;
    END
  END q[389]
  PIN q[38]
    DIRECTION OUTPUT ;
    USE SIGNAL ;
    PORT
      LAYER M5 ;
        RECT  43.44 12.876 43.464 12.96 ;
    END
  END q[38]
  PIN q[390]
    DIRECTION OUTPUT ;
    USE SIGNAL ;
    PORT
      LAYER M5 ;
        RECT  75.696 12.876 75.72 12.96 ;
    END
  END q[390]
  PIN q[391]
    DIRECTION OUTPUT ;
    USE SIGNAL ;
    PORT
      LAYER M5 ;
        RECT  75.792 12.876 75.816 12.96 ;
    END
  END q[391]
  PIN q[392]
    DIRECTION OUTPUT ;
    USE SIGNAL ;
    PORT
      LAYER M5 ;
        RECT  75.888 12.876 75.912 12.96 ;
    END
  END q[392]
  PIN q[393]
    DIRECTION OUTPUT ;
    USE SIGNAL ;
    PORT
      LAYER M5 ;
        RECT  75.984 12.876 76.008 12.96 ;
    END
  END q[393]
  PIN q[394]
    DIRECTION OUTPUT ;
    USE SIGNAL ;
    PORT
      LAYER M5 ;
        RECT  76.08 12.876 76.104 12.96 ;
    END
  END q[394]
  PIN q[395]
    DIRECTION OUTPUT ;
    USE SIGNAL ;
    PORT
      LAYER M5 ;
        RECT  76.176 12.876 76.2 12.96 ;
    END
  END q[395]
  PIN q[396]
    DIRECTION OUTPUT ;
    USE SIGNAL ;
    PORT
      LAYER M5 ;
        RECT  76.272 12.876 76.296 12.96 ;
    END
  END q[396]
  PIN q[397]
    DIRECTION OUTPUT ;
    USE SIGNAL ;
    PORT
      LAYER M5 ;
        RECT  76.368 12.876 76.392 12.96 ;
    END
  END q[397]
  PIN q[398]
    DIRECTION OUTPUT ;
    USE SIGNAL ;
    PORT
      LAYER M5 ;
        RECT  76.464 12.876 76.488 12.96 ;
    END
  END q[398]
  PIN q[399]
    DIRECTION OUTPUT ;
    USE SIGNAL ;
    PORT
      LAYER M5 ;
        RECT  76.56 12.876 76.584 12.96 ;
    END
  END q[399]
  PIN q[39]
    DIRECTION OUTPUT ;
    USE SIGNAL ;
    PORT
      LAYER M5 ;
        RECT  43.536 12.876 43.56 12.96 ;
    END
  END q[39]
  PIN q[3]
    DIRECTION OUTPUT ;
    USE SIGNAL ;
    PORT
      LAYER M5 ;
        RECT  30.096 12.876 30.12 12.96 ;
    END
  END q[3]
  PIN q[400]
    DIRECTION OUTPUT ;
    USE SIGNAL ;
    PORT
      LAYER M5 ;
        RECT  76.656 12.876 76.68 12.96 ;
    END
  END q[400]
  PIN q[401]
    DIRECTION OUTPUT ;
    USE SIGNAL ;
    PORT
      LAYER M5 ;
        RECT  76.752 12.876 76.776 12.96 ;
    END
  END q[401]
  PIN q[402]
    DIRECTION OUTPUT ;
    USE SIGNAL ;
    PORT
      LAYER M5 ;
        RECT  76.848 12.876 76.872 12.96 ;
    END
  END q[402]
  PIN q[403]
    DIRECTION OUTPUT ;
    USE SIGNAL ;
    PORT
      LAYER M5 ;
        RECT  76.944 12.876 76.968 12.96 ;
    END
  END q[403]
  PIN q[404]
    DIRECTION OUTPUT ;
    USE SIGNAL ;
    PORT
      LAYER M5 ;
        RECT  77.04 12.876 77.064 12.96 ;
    END
  END q[404]
  PIN q[405]
    DIRECTION OUTPUT ;
    USE SIGNAL ;
    PORT
      LAYER M5 ;
        RECT  77.136 12.876 77.16 12.96 ;
    END
  END q[405]
  PIN q[406]
    DIRECTION OUTPUT ;
    USE SIGNAL ;
    PORT
      LAYER M5 ;
        RECT  77.232 12.876 77.256 12.96 ;
    END
  END q[406]
  PIN q[407]
    DIRECTION OUTPUT ;
    USE SIGNAL ;
    PORT
      LAYER M5 ;
        RECT  77.328 12.876 77.352 12.96 ;
    END
  END q[407]
  PIN q[408]
    DIRECTION OUTPUT ;
    USE SIGNAL ;
    PORT
      LAYER M5 ;
        RECT  77.424 12.876 77.448 12.96 ;
    END
  END q[408]
  PIN q[409]
    DIRECTION OUTPUT ;
    USE SIGNAL ;
    PORT
      LAYER M5 ;
        RECT  77.52 12.876 77.544 12.96 ;
    END
  END q[409]
  PIN q[40]
    DIRECTION OUTPUT ;
    USE SIGNAL ;
    PORT
      LAYER M5 ;
        RECT  43.632 12.876 43.656 12.96 ;
    END
  END q[40]
  PIN q[410]
    DIRECTION OUTPUT ;
    USE SIGNAL ;
    PORT
      LAYER M5 ;
        RECT  77.616 12.876 77.64 12.96 ;
    END
  END q[410]
  PIN q[411]
    DIRECTION OUTPUT ;
    USE SIGNAL ;
    PORT
      LAYER M5 ;
        RECT  77.712 12.876 77.736 12.96 ;
    END
  END q[411]
  PIN q[412]
    DIRECTION OUTPUT ;
    USE SIGNAL ;
    PORT
      LAYER M5 ;
        RECT  77.808 12.876 77.832 12.96 ;
    END
  END q[412]
  PIN q[413]
    DIRECTION OUTPUT ;
    USE SIGNAL ;
    PORT
      LAYER M5 ;
        RECT  77.904 12.876 77.928 12.96 ;
    END
  END q[413]
  PIN q[414]
    DIRECTION OUTPUT ;
    USE SIGNAL ;
    PORT
      LAYER M5 ;
        RECT  78 12.876 78.024 12.96 ;
    END
  END q[414]
  PIN q[415]
    DIRECTION OUTPUT ;
    USE SIGNAL ;
    PORT
      LAYER M5 ;
        RECT  78.096 12.876 78.12 12.96 ;
    END
  END q[415]
  PIN q[416]
    DIRECTION OUTPUT ;
    USE SIGNAL ;
    PORT
      LAYER M5 ;
        RECT  81.264 12.876 81.288 12.96 ;
    END
  END q[416]
  PIN q[417]
    DIRECTION OUTPUT ;
    USE SIGNAL ;
    PORT
      LAYER M5 ;
        RECT  81.36 12.876 81.384 12.96 ;
    END
  END q[417]
  PIN q[418]
    DIRECTION OUTPUT ;
    USE SIGNAL ;
    PORT
      LAYER M5 ;
        RECT  81.456 12.876 81.48 12.96 ;
    END
  END q[418]
  PIN q[419]
    DIRECTION OUTPUT ;
    USE SIGNAL ;
    PORT
      LAYER M5 ;
        RECT  81.552 12.876 81.576 12.96 ;
    END
  END q[419]
  PIN q[41]
    DIRECTION OUTPUT ;
    USE SIGNAL ;
    PORT
      LAYER M5 ;
        RECT  43.728 12.876 43.752 12.96 ;
    END
  END q[41]
  PIN q[420]
    DIRECTION OUTPUT ;
    USE SIGNAL ;
    PORT
      LAYER M5 ;
        RECT  81.648 12.876 81.672 12.96 ;
    END
  END q[420]
  PIN q[421]
    DIRECTION OUTPUT ;
    USE SIGNAL ;
    PORT
      LAYER M5 ;
        RECT  81.744 12.876 81.768 12.96 ;
    END
  END q[421]
  PIN q[422]
    DIRECTION OUTPUT ;
    USE SIGNAL ;
    PORT
      LAYER M5 ;
        RECT  81.84 12.876 81.864 12.96 ;
    END
  END q[422]
  PIN q[423]
    DIRECTION OUTPUT ;
    USE SIGNAL ;
    PORT
      LAYER M5 ;
        RECT  81.936 12.876 81.96 12.96 ;
    END
  END q[423]
  PIN q[424]
    DIRECTION OUTPUT ;
    USE SIGNAL ;
    PORT
      LAYER M5 ;
        RECT  82.032 12.876 82.056 12.96 ;
    END
  END q[424]
  PIN q[425]
    DIRECTION OUTPUT ;
    USE SIGNAL ;
    PORT
      LAYER M5 ;
        RECT  82.128 12.876 82.152 12.96 ;
    END
  END q[425]
  PIN q[426]
    DIRECTION OUTPUT ;
    USE SIGNAL ;
    PORT
      LAYER M5 ;
        RECT  82.224 12.876 82.248 12.96 ;
    END
  END q[426]
  PIN q[427]
    DIRECTION OUTPUT ;
    USE SIGNAL ;
    PORT
      LAYER M5 ;
        RECT  82.32 12.876 82.344 12.96 ;
    END
  END q[427]
  PIN q[428]
    DIRECTION OUTPUT ;
    USE SIGNAL ;
    PORT
      LAYER M5 ;
        RECT  82.416 12.876 82.44 12.96 ;
    END
  END q[428]
  PIN q[429]
    DIRECTION OUTPUT ;
    USE SIGNAL ;
    PORT
      LAYER M5 ;
        RECT  82.512 12.876 82.536 12.96 ;
    END
  END q[429]
  PIN q[42]
    DIRECTION OUTPUT ;
    USE SIGNAL ;
    PORT
      LAYER M5 ;
        RECT  43.824 12.876 43.848 12.96 ;
    END
  END q[42]
  PIN q[430]
    DIRECTION OUTPUT ;
    USE SIGNAL ;
    PORT
      LAYER M5 ;
        RECT  82.608 12.876 82.632 12.96 ;
    END
  END q[430]
  PIN q[431]
    DIRECTION OUTPUT ;
    USE SIGNAL ;
    PORT
      LAYER M5 ;
        RECT  82.704 12.876 82.728 12.96 ;
    END
  END q[431]
  PIN q[432]
    DIRECTION OUTPUT ;
    USE SIGNAL ;
    PORT
      LAYER M5 ;
        RECT  82.8 12.876 82.824 12.96 ;
    END
  END q[432]
  PIN q[433]
    DIRECTION OUTPUT ;
    USE SIGNAL ;
    PORT
      LAYER M5 ;
        RECT  82.896 12.876 82.92 12.96 ;
    END
  END q[433]
  PIN q[434]
    DIRECTION OUTPUT ;
    USE SIGNAL ;
    PORT
      LAYER M5 ;
        RECT  82.992 12.876 83.016 12.96 ;
    END
  END q[434]
  PIN q[435]
    DIRECTION OUTPUT ;
    USE SIGNAL ;
    PORT
      LAYER M5 ;
        RECT  83.088 12.876 83.112 12.96 ;
    END
  END q[435]
  PIN q[436]
    DIRECTION OUTPUT ;
    USE SIGNAL ;
    PORT
      LAYER M5 ;
        RECT  83.184 12.876 83.208 12.96 ;
    END
  END q[436]
  PIN q[437]
    DIRECTION OUTPUT ;
    USE SIGNAL ;
    PORT
      LAYER M5 ;
        RECT  83.28 12.876 83.304 12.96 ;
    END
  END q[437]
  PIN q[438]
    DIRECTION OUTPUT ;
    USE SIGNAL ;
    PORT
      LAYER M5 ;
        RECT  83.376 12.876 83.4 12.96 ;
    END
  END q[438]
  PIN q[439]
    DIRECTION OUTPUT ;
    USE SIGNAL ;
    PORT
      LAYER M5 ;
        RECT  83.472 12.876 83.496 12.96 ;
    END
  END q[439]
  PIN q[43]
    DIRECTION OUTPUT ;
    USE SIGNAL ;
    PORT
      LAYER M5 ;
        RECT  43.92 12.876 43.944 12.96 ;
    END
  END q[43]
  PIN q[440]
    DIRECTION OUTPUT ;
    USE SIGNAL ;
    PORT
      LAYER M5 ;
        RECT  83.568 12.876 83.592 12.96 ;
    END
  END q[440]
  PIN q[441]
    DIRECTION OUTPUT ;
    USE SIGNAL ;
    PORT
      LAYER M5 ;
        RECT  83.664 12.876 83.688 12.96 ;
    END
  END q[441]
  PIN q[442]
    DIRECTION OUTPUT ;
    USE SIGNAL ;
    PORT
      LAYER M5 ;
        RECT  83.76 12.876 83.784 12.96 ;
    END
  END q[442]
  PIN q[443]
    DIRECTION OUTPUT ;
    USE SIGNAL ;
    PORT
      LAYER M5 ;
        RECT  83.856 12.876 83.88 12.96 ;
    END
  END q[443]
  PIN q[444]
    DIRECTION OUTPUT ;
    USE SIGNAL ;
    PORT
      LAYER M5 ;
        RECT  83.952 12.876 83.976 12.96 ;
    END
  END q[444]
  PIN q[445]
    DIRECTION OUTPUT ;
    USE SIGNAL ;
    PORT
      LAYER M5 ;
        RECT  84.048 12.876 84.072 12.96 ;
    END
  END q[445]
  PIN q[446]
    DIRECTION OUTPUT ;
    USE SIGNAL ;
    PORT
      LAYER M5 ;
        RECT  84.144 12.876 84.168 12.96 ;
    END
  END q[446]
  PIN q[447]
    DIRECTION OUTPUT ;
    USE SIGNAL ;
    PORT
      LAYER M5 ;
        RECT  84.24 12.876 84.264 12.96 ;
    END
  END q[447]
  PIN q[448]
    DIRECTION OUTPUT ;
    USE SIGNAL ;
    PORT
      LAYER M5 ;
        RECT  78.192 12.876 78.216 12.96 ;
    END
  END q[448]
  PIN q[449]
    DIRECTION OUTPUT ;
    USE SIGNAL ;
    PORT
      LAYER M5 ;
        RECT  78.288 12.876 78.312 12.96 ;
    END
  END q[449]
  PIN q[44]
    DIRECTION OUTPUT ;
    USE SIGNAL ;
    PORT
      LAYER M5 ;
        RECT  44.016 12.876 44.04 12.96 ;
    END
  END q[44]
  PIN q[450]
    DIRECTION OUTPUT ;
    USE SIGNAL ;
    PORT
      LAYER M5 ;
        RECT  78.384 12.876 78.408 12.96 ;
    END
  END q[450]
  PIN q[451]
    DIRECTION OUTPUT ;
    USE SIGNAL ;
    PORT
      LAYER M5 ;
        RECT  78.48 12.876 78.504 12.96 ;
    END
  END q[451]
  PIN q[452]
    DIRECTION OUTPUT ;
    USE SIGNAL ;
    PORT
      LAYER M5 ;
        RECT  78.576 12.876 78.6 12.96 ;
    END
  END q[452]
  PIN q[453]
    DIRECTION OUTPUT ;
    USE SIGNAL ;
    PORT
      LAYER M5 ;
        RECT  78.672 12.876 78.696 12.96 ;
    END
  END q[453]
  PIN q[454]
    DIRECTION OUTPUT ;
    USE SIGNAL ;
    PORT
      LAYER M5 ;
        RECT  78.768 12.876 78.792 12.96 ;
    END
  END q[454]
  PIN q[455]
    DIRECTION OUTPUT ;
    USE SIGNAL ;
    PORT
      LAYER M5 ;
        RECT  78.864 12.876 78.888 12.96 ;
    END
  END q[455]
  PIN q[456]
    DIRECTION OUTPUT ;
    USE SIGNAL ;
    PORT
      LAYER M5 ;
        RECT  78.96 12.876 78.984 12.96 ;
    END
  END q[456]
  PIN q[457]
    DIRECTION OUTPUT ;
    USE SIGNAL ;
    PORT
      LAYER M5 ;
        RECT  79.056 12.876 79.08 12.96 ;
    END
  END q[457]
  PIN q[458]
    DIRECTION OUTPUT ;
    USE SIGNAL ;
    PORT
      LAYER M5 ;
        RECT  79.152 12.876 79.176 12.96 ;
    END
  END q[458]
  PIN q[459]
    DIRECTION OUTPUT ;
    USE SIGNAL ;
    PORT
      LAYER M5 ;
        RECT  79.248 12.876 79.272 12.96 ;
    END
  END q[459]
  PIN q[45]
    DIRECTION OUTPUT ;
    USE SIGNAL ;
    PORT
      LAYER M5 ;
        RECT  44.112 12.876 44.136 12.96 ;
    END
  END q[45]
  PIN q[460]
    DIRECTION OUTPUT ;
    USE SIGNAL ;
    PORT
      LAYER M5 ;
        RECT  79.344 12.876 79.368 12.96 ;
    END
  END q[460]
  PIN q[461]
    DIRECTION OUTPUT ;
    USE SIGNAL ;
    PORT
      LAYER M5 ;
        RECT  79.44 12.876 79.464 12.96 ;
    END
  END q[461]
  PIN q[462]
    DIRECTION OUTPUT ;
    USE SIGNAL ;
    PORT
      LAYER M5 ;
        RECT  79.536 12.876 79.56 12.96 ;
    END
  END q[462]
  PIN q[463]
    DIRECTION OUTPUT ;
    USE SIGNAL ;
    PORT
      LAYER M5 ;
        RECT  79.632 12.876 79.656 12.96 ;
    END
  END q[463]
  PIN q[464]
    DIRECTION OUTPUT ;
    USE SIGNAL ;
    PORT
      LAYER M5 ;
        RECT  79.728 12.876 79.752 12.96 ;
    END
  END q[464]
  PIN q[465]
    DIRECTION OUTPUT ;
    USE SIGNAL ;
    PORT
      LAYER M5 ;
        RECT  79.824 12.876 79.848 12.96 ;
    END
  END q[465]
  PIN q[466]
    DIRECTION OUTPUT ;
    USE SIGNAL ;
    PORT
      LAYER M5 ;
        RECT  79.92 12.876 79.944 12.96 ;
    END
  END q[466]
  PIN q[467]
    DIRECTION OUTPUT ;
    USE SIGNAL ;
    PORT
      LAYER M5 ;
        RECT  80.016 12.876 80.04 12.96 ;
    END
  END q[467]
  PIN q[468]
    DIRECTION OUTPUT ;
    USE SIGNAL ;
    PORT
      LAYER M5 ;
        RECT  80.112 12.876 80.136 12.96 ;
    END
  END q[468]
  PIN q[469]
    DIRECTION OUTPUT ;
    USE SIGNAL ;
    PORT
      LAYER M5 ;
        RECT  80.208 12.876 80.232 12.96 ;
    END
  END q[469]
  PIN q[46]
    DIRECTION OUTPUT ;
    USE SIGNAL ;
    PORT
      LAYER M5 ;
        RECT  44.208 12.876 44.232 12.96 ;
    END
  END q[46]
  PIN q[470]
    DIRECTION OUTPUT ;
    USE SIGNAL ;
    PORT
      LAYER M5 ;
        RECT  80.304 12.876 80.328 12.96 ;
    END
  END q[470]
  PIN q[471]
    DIRECTION OUTPUT ;
    USE SIGNAL ;
    PORT
      LAYER M5 ;
        RECT  80.4 12.876 80.424 12.96 ;
    END
  END q[471]
  PIN q[472]
    DIRECTION OUTPUT ;
    USE SIGNAL ;
    PORT
      LAYER M5 ;
        RECT  80.496 12.876 80.52 12.96 ;
    END
  END q[472]
  PIN q[473]
    DIRECTION OUTPUT ;
    USE SIGNAL ;
    PORT
      LAYER M5 ;
        RECT  80.592 12.876 80.616 12.96 ;
    END
  END q[473]
  PIN q[474]
    DIRECTION OUTPUT ;
    USE SIGNAL ;
    PORT
      LAYER M5 ;
        RECT  80.688 12.876 80.712 12.96 ;
    END
  END q[474]
  PIN q[475]
    DIRECTION OUTPUT ;
    USE SIGNAL ;
    PORT
      LAYER M5 ;
        RECT  80.784 12.876 80.808 12.96 ;
    END
  END q[475]
  PIN q[476]
    DIRECTION OUTPUT ;
    USE SIGNAL ;
    PORT
      LAYER M5 ;
        RECT  80.88 12.876 80.904 12.96 ;
    END
  END q[476]
  PIN q[477]
    DIRECTION OUTPUT ;
    USE SIGNAL ;
    PORT
      LAYER M5 ;
        RECT  80.976 12.876 81 12.96 ;
    END
  END q[477]
  PIN q[478]
    DIRECTION OUTPUT ;
    USE SIGNAL ;
    PORT
      LAYER M5 ;
        RECT  81.072 12.876 81.096 12.96 ;
    END
  END q[478]
  PIN q[479]
    DIRECTION OUTPUT ;
    USE SIGNAL ;
    PORT
      LAYER M5 ;
        RECT  81.168 12.876 81.192 12.96 ;
    END
  END q[479]
  PIN q[47]
    DIRECTION OUTPUT ;
    USE SIGNAL ;
    PORT
      LAYER M5 ;
        RECT  44.304 12.876 44.328 12.96 ;
    END
  END q[47]
  PIN q[480]
    DIRECTION OUTPUT ;
    USE SIGNAL ;
    PORT
      LAYER M5 ;
        RECT  72.048 12.876 72.072 12.96 ;
    END
  END q[480]
  PIN q[481]
    DIRECTION OUTPUT ;
    USE SIGNAL ;
    PORT
      LAYER M5 ;
        RECT  72.144 12.876 72.168 12.96 ;
    END
  END q[481]
  PIN q[482]
    DIRECTION OUTPUT ;
    USE SIGNAL ;
    PORT
      LAYER M5 ;
        RECT  72.24 12.876 72.264 12.96 ;
    END
  END q[482]
  PIN q[483]
    DIRECTION OUTPUT ;
    USE SIGNAL ;
    PORT
      LAYER M5 ;
        RECT  72.336 12.876 72.36 12.96 ;
    END
  END q[483]
  PIN q[484]
    DIRECTION OUTPUT ;
    USE SIGNAL ;
    PORT
      LAYER M5 ;
        RECT  72.432 12.876 72.456 12.96 ;
    END
  END q[484]
  PIN q[485]
    DIRECTION OUTPUT ;
    USE SIGNAL ;
    PORT
      LAYER M5 ;
        RECT  72.528 12.876 72.552 12.96 ;
    END
  END q[485]
  PIN q[486]
    DIRECTION OUTPUT ;
    USE SIGNAL ;
    PORT
      LAYER M5 ;
        RECT  72.624 12.876 72.648 12.96 ;
    END
  END q[486]
  PIN q[487]
    DIRECTION OUTPUT ;
    USE SIGNAL ;
    PORT
      LAYER M5 ;
        RECT  72.72 12.876 72.744 12.96 ;
    END
  END q[487]
  PIN q[488]
    DIRECTION OUTPUT ;
    USE SIGNAL ;
    PORT
      LAYER M5 ;
        RECT  72.816 12.876 72.84 12.96 ;
    END
  END q[488]
  PIN q[489]
    DIRECTION OUTPUT ;
    USE SIGNAL ;
    PORT
      LAYER M5 ;
        RECT  72.912 12.876 72.936 12.96 ;
    END
  END q[489]
  PIN q[48]
    DIRECTION OUTPUT ;
    USE SIGNAL ;
    PORT
      LAYER M5 ;
        RECT  44.4 12.876 44.424 12.96 ;
    END
  END q[48]
  PIN q[490]
    DIRECTION OUTPUT ;
    USE SIGNAL ;
    PORT
      LAYER M5 ;
        RECT  73.008 12.876 73.032 12.96 ;
    END
  END q[490]
  PIN q[491]
    DIRECTION OUTPUT ;
    USE SIGNAL ;
    PORT
      LAYER M5 ;
        RECT  73.104 12.876 73.128 12.96 ;
    END
  END q[491]
  PIN q[492]
    DIRECTION OUTPUT ;
    USE SIGNAL ;
    PORT
      LAYER M5 ;
        RECT  73.2 12.876 73.224 12.96 ;
    END
  END q[492]
  PIN q[493]
    DIRECTION OUTPUT ;
    USE SIGNAL ;
    PORT
      LAYER M5 ;
        RECT  73.296 12.876 73.32 12.96 ;
    END
  END q[493]
  PIN q[494]
    DIRECTION OUTPUT ;
    USE SIGNAL ;
    PORT
      LAYER M5 ;
        RECT  73.392 12.876 73.416 12.96 ;
    END
  END q[494]
  PIN q[495]
    DIRECTION OUTPUT ;
    USE SIGNAL ;
    PORT
      LAYER M5 ;
        RECT  73.488 12.876 73.512 12.96 ;
    END
  END q[495]
  PIN q[496]
    DIRECTION OUTPUT ;
    USE SIGNAL ;
    PORT
      LAYER M5 ;
        RECT  73.584 12.876 73.608 12.96 ;
    END
  END q[496]
  PIN q[497]
    DIRECTION OUTPUT ;
    USE SIGNAL ;
    PORT
      LAYER M5 ;
        RECT  73.68 12.876 73.704 12.96 ;
    END
  END q[497]
  PIN q[498]
    DIRECTION OUTPUT ;
    USE SIGNAL ;
    PORT
      LAYER M5 ;
        RECT  73.776 12.876 73.8 12.96 ;
    END
  END q[498]
  PIN q[499]
    DIRECTION OUTPUT ;
    USE SIGNAL ;
    PORT
      LAYER M5 ;
        RECT  73.872 12.876 73.896 12.96 ;
    END
  END q[499]
  PIN q[49]
    DIRECTION OUTPUT ;
    USE SIGNAL ;
    PORT
      LAYER M5 ;
        RECT  44.496 12.876 44.52 12.96 ;
    END
  END q[49]
  PIN q[4]
    DIRECTION OUTPUT ;
    USE SIGNAL ;
    PORT
      LAYER M5 ;
        RECT  30.192 12.876 30.216 12.96 ;
    END
  END q[4]
  PIN q[500]
    DIRECTION OUTPUT ;
    USE SIGNAL ;
    PORT
      LAYER M5 ;
        RECT  73.968 12.876 73.992 12.96 ;
    END
  END q[500]
  PIN q[501]
    DIRECTION OUTPUT ;
    USE SIGNAL ;
    PORT
      LAYER M5 ;
        RECT  74.064 12.876 74.088 12.96 ;
    END
  END q[501]
  PIN q[502]
    DIRECTION OUTPUT ;
    USE SIGNAL ;
    PORT
      LAYER M5 ;
        RECT  74.16 12.876 74.184 12.96 ;
    END
  END q[502]
  PIN q[503]
    DIRECTION OUTPUT ;
    USE SIGNAL ;
    PORT
      LAYER M5 ;
        RECT  74.256 12.876 74.28 12.96 ;
    END
  END q[503]
  PIN q[504]
    DIRECTION OUTPUT ;
    USE SIGNAL ;
    PORT
      LAYER M5 ;
        RECT  74.352 12.876 74.376 12.96 ;
    END
  END q[504]
  PIN q[505]
    DIRECTION OUTPUT ;
    USE SIGNAL ;
    PORT
      LAYER M5 ;
        RECT  74.448 12.876 74.472 12.96 ;
    END
  END q[505]
  PIN q[506]
    DIRECTION OUTPUT ;
    USE SIGNAL ;
    PORT
      LAYER M5 ;
        RECT  74.544 12.876 74.568 12.96 ;
    END
  END q[506]
  PIN q[507]
    DIRECTION OUTPUT ;
    USE SIGNAL ;
    PORT
      LAYER M5 ;
        RECT  74.64 12.876 74.664 12.96 ;
    END
  END q[507]
  PIN q[508]
    DIRECTION OUTPUT ;
    USE SIGNAL ;
    PORT
      LAYER M5 ;
        RECT  74.736 12.876 74.76 12.96 ;
    END
  END q[508]
  PIN q[509]
    DIRECTION OUTPUT ;
    USE SIGNAL ;
    PORT
      LAYER M5 ;
        RECT  74.832 12.876 74.856 12.96 ;
    END
  END q[509]
  PIN q[50]
    DIRECTION OUTPUT ;
    USE SIGNAL ;
    PORT
      LAYER M5 ;
        RECT  44.592 12.876 44.616 12.96 ;
    END
  END q[50]
  PIN q[510]
    DIRECTION OUTPUT ;
    USE SIGNAL ;
    PORT
      LAYER M5 ;
        RECT  74.928 12.876 74.952 12.96 ;
    END
  END q[510]
  PIN q[511]
    DIRECTION OUTPUT ;
    USE SIGNAL ;
    PORT
      LAYER M5 ;
        RECT  75.024 12.876 75.048 12.96 ;
    END
  END q[511]
  PIN q[51]
    DIRECTION OUTPUT ;
    USE SIGNAL ;
    PORT
      LAYER M5 ;
        RECT  44.688 12.876 44.712 12.96 ;
    END
  END q[51]
  PIN q[52]
    DIRECTION OUTPUT ;
    USE SIGNAL ;
    PORT
      LAYER M5 ;
        RECT  44.784 12.876 44.808 12.96 ;
    END
  END q[52]
  PIN q[53]
    DIRECTION OUTPUT ;
    USE SIGNAL ;
    PORT
      LAYER M5 ;
        RECT  44.88 12.876 44.904 12.96 ;
    END
  END q[53]
  PIN q[54]
    DIRECTION OUTPUT ;
    USE SIGNAL ;
    PORT
      LAYER M5 ;
        RECT  44.976 12.876 45 12.96 ;
    END
  END q[54]
  PIN q[55]
    DIRECTION OUTPUT ;
    USE SIGNAL ;
    PORT
      LAYER M5 ;
        RECT  45.072 12.876 45.096 12.96 ;
    END
  END q[55]
  PIN q[56]
    DIRECTION OUTPUT ;
    USE SIGNAL ;
    PORT
      LAYER M5 ;
        RECT  45.168 12.876 45.192 12.96 ;
    END
  END q[56]
  PIN q[57]
    DIRECTION OUTPUT ;
    USE SIGNAL ;
    PORT
      LAYER M5 ;
        RECT  45.264 12.876 45.288 12.96 ;
    END
  END q[57]
  PIN q[58]
    DIRECTION OUTPUT ;
    USE SIGNAL ;
    PORT
      LAYER M5 ;
        RECT  45.36 12.876 45.384 12.96 ;
    END
  END q[58]
  PIN q[59]
    DIRECTION OUTPUT ;
    USE SIGNAL ;
    PORT
      LAYER M5 ;
        RECT  45.456 12.876 45.48 12.96 ;
    END
  END q[59]
  PIN q[5]
    DIRECTION OUTPUT ;
    USE SIGNAL ;
    PORT
      LAYER M5 ;
        RECT  30.288 12.876 30.312 12.96 ;
    END
  END q[5]
  PIN q[60]
    DIRECTION OUTPUT ;
    USE SIGNAL ;
    PORT
      LAYER M5 ;
        RECT  45.552 12.876 45.576 12.96 ;
    END
  END q[60]
  PIN q[61]
    DIRECTION OUTPUT ;
    USE SIGNAL ;
    PORT
      LAYER M5 ;
        RECT  45.648 12.876 45.672 12.96 ;
    END
  END q[61]
  PIN q[62]
    DIRECTION OUTPUT ;
    USE SIGNAL ;
    PORT
      LAYER M5 ;
        RECT  45.744 12.876 45.768 12.96 ;
    END
  END q[62]
  PIN q[63]
    DIRECTION OUTPUT ;
    USE SIGNAL ;
    PORT
      LAYER M5 ;
        RECT  45.84 12.876 45.864 12.96 ;
    END
  END q[63]
  PIN q[64]
    DIRECTION OUTPUT ;
    USE SIGNAL ;
    PORT
      LAYER M5 ;
        RECT  36.72 12.876 36.744 12.96 ;
    END
  END q[64]
  PIN q[65]
    DIRECTION OUTPUT ;
    USE SIGNAL ;
    PORT
      LAYER M5 ;
        RECT  36.816 12.876 36.84 12.96 ;
    END
  END q[65]
  PIN q[66]
    DIRECTION OUTPUT ;
    USE SIGNAL ;
    PORT
      LAYER M5 ;
        RECT  36.912 12.876 36.936 12.96 ;
    END
  END q[66]
  PIN q[67]
    DIRECTION OUTPUT ;
    USE SIGNAL ;
    PORT
      LAYER M5 ;
        RECT  37.008 12.876 37.032 12.96 ;
    END
  END q[67]
  PIN q[68]
    DIRECTION OUTPUT ;
    USE SIGNAL ;
    PORT
      LAYER M5 ;
        RECT  37.104 12.876 37.128 12.96 ;
    END
  END q[68]
  PIN q[69]
    DIRECTION OUTPUT ;
    USE SIGNAL ;
    PORT
      LAYER M5 ;
        RECT  37.2 12.876 37.224 12.96 ;
    END
  END q[69]
  PIN q[6]
    DIRECTION OUTPUT ;
    USE SIGNAL ;
    PORT
      LAYER M5 ;
        RECT  30.384 12.876 30.408 12.96 ;
    END
  END q[6]
  PIN q[70]
    DIRECTION OUTPUT ;
    USE SIGNAL ;
    PORT
      LAYER M5 ;
        RECT  37.296 12.876 37.32 12.96 ;
    END
  END q[70]
  PIN q[71]
    DIRECTION OUTPUT ;
    USE SIGNAL ;
    PORT
      LAYER M5 ;
        RECT  37.392 12.876 37.416 12.96 ;
    END
  END q[71]
  PIN q[72]
    DIRECTION OUTPUT ;
    USE SIGNAL ;
    PORT
      LAYER M5 ;
        RECT  37.488 12.876 37.512 12.96 ;
    END
  END q[72]
  PIN q[73]
    DIRECTION OUTPUT ;
    USE SIGNAL ;
    PORT
      LAYER M5 ;
        RECT  37.584 12.876 37.608 12.96 ;
    END
  END q[73]
  PIN q[74]
    DIRECTION OUTPUT ;
    USE SIGNAL ;
    PORT
      LAYER M5 ;
        RECT  37.68 12.876 37.704 12.96 ;
    END
  END q[74]
  PIN q[75]
    DIRECTION OUTPUT ;
    USE SIGNAL ;
    PORT
      LAYER M5 ;
        RECT  37.776 12.876 37.8 12.96 ;
    END
  END q[75]
  PIN q[76]
    DIRECTION OUTPUT ;
    USE SIGNAL ;
    PORT
      LAYER M5 ;
        RECT  37.872 12.876 37.896 12.96 ;
    END
  END q[76]
  PIN q[77]
    DIRECTION OUTPUT ;
    USE SIGNAL ;
    PORT
      LAYER M5 ;
        RECT  37.968 12.876 37.992 12.96 ;
    END
  END q[77]
  PIN q[78]
    DIRECTION OUTPUT ;
    USE SIGNAL ;
    PORT
      LAYER M5 ;
        RECT  38.064 12.876 38.088 12.96 ;
    END
  END q[78]
  PIN q[79]
    DIRECTION OUTPUT ;
    USE SIGNAL ;
    PORT
      LAYER M5 ;
        RECT  38.16 12.876 38.184 12.96 ;
    END
  END q[79]
  PIN q[7]
    DIRECTION OUTPUT ;
    USE SIGNAL ;
    PORT
      LAYER M5 ;
        RECT  30.48 12.876 30.504 12.96 ;
    END
  END q[7]
  PIN q[80]
    DIRECTION OUTPUT ;
    USE SIGNAL ;
    PORT
      LAYER M5 ;
        RECT  38.256 12.876 38.28 12.96 ;
    END
  END q[80]
  PIN q[81]
    DIRECTION OUTPUT ;
    USE SIGNAL ;
    PORT
      LAYER M5 ;
        RECT  38.352 12.876 38.376 12.96 ;
    END
  END q[81]
  PIN q[82]
    DIRECTION OUTPUT ;
    USE SIGNAL ;
    PORT
      LAYER M5 ;
        RECT  38.448 12.876 38.472 12.96 ;
    END
  END q[82]
  PIN q[83]
    DIRECTION OUTPUT ;
    USE SIGNAL ;
    PORT
      LAYER M5 ;
        RECT  38.544 12.876 38.568 12.96 ;
    END
  END q[83]
  PIN q[84]
    DIRECTION OUTPUT ;
    USE SIGNAL ;
    PORT
      LAYER M5 ;
        RECT  38.64 12.876 38.664 12.96 ;
    END
  END q[84]
  PIN q[85]
    DIRECTION OUTPUT ;
    USE SIGNAL ;
    PORT
      LAYER M5 ;
        RECT  38.736 12.876 38.76 12.96 ;
    END
  END q[85]
  PIN q[86]
    DIRECTION OUTPUT ;
    USE SIGNAL ;
    PORT
      LAYER M5 ;
        RECT  38.832 12.876 38.856 12.96 ;
    END
  END q[86]
  PIN q[87]
    DIRECTION OUTPUT ;
    USE SIGNAL ;
    PORT
      LAYER M5 ;
        RECT  38.928 12.876 38.952 12.96 ;
    END
  END q[87]
  PIN q[88]
    DIRECTION OUTPUT ;
    USE SIGNAL ;
    PORT
      LAYER M5 ;
        RECT  39.024 12.876 39.048 12.96 ;
    END
  END q[88]
  PIN q[89]
    DIRECTION OUTPUT ;
    USE SIGNAL ;
    PORT
      LAYER M5 ;
        RECT  39.12 12.876 39.144 12.96 ;
    END
  END q[89]
  PIN q[8]
    DIRECTION OUTPUT ;
    USE SIGNAL ;
    PORT
      LAYER M5 ;
        RECT  30.576 12.876 30.6 12.96 ;
    END
  END q[8]
  PIN q[90]
    DIRECTION OUTPUT ;
    USE SIGNAL ;
    PORT
      LAYER M5 ;
        RECT  39.216 12.876 39.24 12.96 ;
    END
  END q[90]
  PIN q[91]
    DIRECTION OUTPUT ;
    USE SIGNAL ;
    PORT
      LAYER M5 ;
        RECT  39.312 12.876 39.336 12.96 ;
    END
  END q[91]
  PIN q[92]
    DIRECTION OUTPUT ;
    USE SIGNAL ;
    PORT
      LAYER M5 ;
        RECT  39.408 12.876 39.432 12.96 ;
    END
  END q[92]
  PIN q[93]
    DIRECTION OUTPUT ;
    USE SIGNAL ;
    PORT
      LAYER M5 ;
        RECT  39.504 12.876 39.528 12.96 ;
    END
  END q[93]
  PIN q[94]
    DIRECTION OUTPUT ;
    USE SIGNAL ;
    PORT
      LAYER M5 ;
        RECT  39.6 12.876 39.624 12.96 ;
    END
  END q[94]
  PIN q[95]
    DIRECTION OUTPUT ;
    USE SIGNAL ;
    PORT
      LAYER M5 ;
        RECT  39.696 12.876 39.72 12.96 ;
    END
  END q[95]
  PIN q[96]
    DIRECTION OUTPUT ;
    USE SIGNAL ;
    PORT
      LAYER M5 ;
        RECT  26.736 12.876 26.76 12.96 ;
    END
  END q[96]
  PIN q[97]
    DIRECTION OUTPUT ;
    USE SIGNAL ;
    PORT
      LAYER M5 ;
        RECT  26.832 12.876 26.856 12.96 ;
    END
  END q[97]
  PIN q[98]
    DIRECTION OUTPUT ;
    USE SIGNAL ;
    PORT
      LAYER M5 ;
        RECT  26.928 12.876 26.952 12.96 ;
    END
  END q[98]
  PIN q[99]
    DIRECTION OUTPUT ;
    USE SIGNAL ;
    PORT
      LAYER M5 ;
        RECT  27.024 12.876 27.048 12.96 ;
    END
  END q[99]
  PIN q[9]
    DIRECTION OUTPUT ;
    USE SIGNAL ;
    PORT
      LAYER M5 ;
        RECT  30.672 12.876 30.696 12.96 ;
    END
  END q[9]
  PIN VDD
    DIRECTION INOUT ;
    USE POWER ;
    PORT
      LAYER M5 ;
        RECT  126.792 2.151 126.912 10.809 ;
        RECT  121.392 2.151 121.512 10.809 ;
        RECT  115.992 2.151 116.112 10.809 ;
        RECT  110.592 2.151 110.712 10.809 ;
        RECT  105.192 2.151 105.312 10.809 ;
        RECT  99.792 2.151 99.912 10.809 ;
        RECT  94.392 2.151 94.512 10.809 ;
        RECT  88.992 2.151 89.112 10.809 ;
        RECT  83.592 2.151 83.712 10.809 ;
        RECT  78.192 2.151 78.312 10.809 ;
        RECT  72.792 2.151 72.912 10.809 ;
        RECT  67.392 2.151 67.512 10.809 ;
        RECT  61.992 2.151 62.112 10.809 ;
        RECT  56.592 2.151 56.712 10.809 ;
        RECT  51.192 2.151 51.312 10.809 ;
        RECT  45.792 2.151 45.912 10.809 ;
        RECT  40.392 2.151 40.512 10.809 ;
        RECT  34.992 2.151 35.112 10.809 ;
        RECT  29.592 2.151 29.712 10.809 ;
        RECT  24.192 2.151 24.312 10.809 ;
        RECT  18.792 2.151 18.912 10.809 ;
        RECT  13.392 2.151 13.512 10.809 ;
        RECT  7.992 2.151 8.112 10.809 ;
        RECT  2.592 2.151 2.712 10.809 ;
    END
  END VDD
  PIN VSS
    DIRECTION INOUT ;
    USE GROUND ;
    PORT
      LAYER M5 ;
        RECT  126.6 2.137 126.72 10.823 ;
        RECT  121.2 2.137 121.32 10.823 ;
        RECT  115.8 2.137 115.92 10.823 ;
        RECT  110.4 2.137 110.52 10.823 ;
        RECT  105 2.137 105.12 10.823 ;
        RECT  99.6 2.137 99.72 10.823 ;
        RECT  94.2 2.137 94.32 10.823 ;
        RECT  88.8 2.137 88.92 10.823 ;
        RECT  83.4 2.137 83.52 10.823 ;
        RECT  78 2.137 78.12 10.823 ;
        RECT  72.6 2.137 72.72 10.823 ;
        RECT  67.2 2.137 67.32 10.823 ;
        RECT  61.8 2.137 61.92 10.823 ;
        RECT  56.4 2.137 56.52 10.823 ;
        RECT  51 2.137 51.12 10.823 ;
        RECT  45.6 2.137 45.72 10.823 ;
        RECT  40.2 2.137 40.32 10.823 ;
        RECT  34.8 2.137 34.92 10.823 ;
        RECT  29.4 2.137 29.52 10.823 ;
        RECT  24 2.137 24.12 10.823 ;
        RECT  18.6 2.137 18.72 10.823 ;
        RECT  13.2 2.137 13.32 10.823 ;
        RECT  7.8 2.137 7.92 10.823 ;
        RECT  2.4 2.137 2.52 10.823 ;
    END
  END VSS
  OBS
    LAYER RVTN ;
     RECT  2.16 2.16 2.268 2.295 ;
     RECT  13.824 2.16 14.364 2.295 ;
     RECT  14.634 2.16 14.904 2.295 ;
     RECT  15.444 2.16 15.714 2.295 ;
     RECT  15.768 2.16 16.848 2.295 ;
     RECT  17.118 2.16 17.658 2.295 ;
     RECT  17.982 2.16 18.252 2.295 ;
     RECT  18.36 2.16 18.63 2.295 ;
     RECT  18.846 2.16 19.926 2.295 ;
     RECT  20.196 2.16 20.736 2.295 ;
     RECT  20.79 2.16 21.6 2.295 ;
     RECT  21.654 2.16 21.924 2.295 ;
     RECT  21.978 2.16 22.248 2.295 ;
     RECT  22.356 2.16 22.626 2.295 ;
     RECT  22.68 2.16 23.49 2.295 ;
     RECT  23.598 2.16 24.408 2.295 ;
     RECT  24.462 2.16 25.002 2.295 ;
     RECT  25.218 2.16 25.488 2.295 ;
     RECT  25.65 2.16 26.46 2.295 ;
     RECT  26.514 2.16 26.784 2.295 ;
     RECT  26.838 2.16 27.486 2.295 ;
     RECT  27.648 2.16 28.458 2.295 ;
     RECT  28.512 2.16 29.052 2.295 ;
     RECT  29.16 2.16 29.808 2.295 ;
     RECT  29.97 2.16 30.78 2.295 ;
     RECT  30.834 2.16 31.104 2.295 ;
     RECT  31.212 2.16 32.562 2.295 ;
     RECT  32.616 2.16 32.886 2.295 ;
     RECT  33.048 2.16 33.318 2.295 ;
     RECT  33.372 2.16 35.802 2.295 ;
     RECT  36.018 2.16 37.368 2.295 ;
     RECT  37.746 2.16 38.016 2.295 ;
     RECT  38.124 2.16 38.664 2.295 ;
     RECT  38.826 2.16 40.446 2.295 ;
     RECT  40.5 2.16 41.31 2.295 ;
     RECT  41.526 2.16 41.796 2.295 ;
     RECT  42.228 2.16 42.498 2.295 ;
     RECT  42.606 2.16 42.876 2.295 ;
     RECT  43.038 2.16 43.848 2.295 ;
     RECT  43.902 2.16 44.172 2.295 ;
     RECT  44.28 2.16 45.63 2.295 ;
     RECT  45.684 2.16 45.954 2.295 ;
     RECT  46.062 2.16 46.332 2.295 ;
     RECT  46.548 2.16 46.818 2.295 ;
     RECT  47.034 2.16 48.384 2.295 ;
     RECT  48.438 2.16 49.248 2.295 ;
     RECT  49.302 2.16 49.572 2.295 ;
     RECT  49.788 2.16 50.328 2.295 ;
     RECT  50.544 2.16 51.084 2.295 ;
     RECT  51.192 2.16 51.732 2.295 ;
     RECT  51.786 2.16 52.434 2.295 ;
     RECT  52.488 2.16 52.758 2.295 ;
     RECT  52.92 2.16 53.73 2.295 ;
     RECT  54.162 2.16 54.972 2.295 ;
     RECT  55.026 2.16 57.726 2.295 ;
     RECT  58.158 2.16 59.778 2.295 ;
     RECT  60.048 2.16 61.398 2.295 ;
     RECT  61.56 2.16 61.83 2.295 ;
     RECT  61.938 2.16 62.748 2.295 ;
     RECT  62.802 2.16 63.072 2.295 ;
     RECT  63.126 2.16 63.396 2.295 ;
     RECT  63.45 2.16 63.72 2.295 ;
     RECT  63.882 2.16 64.152 2.295 ;
     RECT  64.314 2.16 64.584 2.295 ;
     RECT  67.932 2.16 68.472 2.295 ;
     RECT  68.742 2.16 70.092 2.295 ;
     RECT  70.362 2.16 70.902 2.295 ;
     RECT  71.01 2.16 71.55 2.295 ;
     RECT  71.766 2.16 72.306 2.295 ;
     RECT  72.522 2.16 72.792 2.295 ;
     RECT  73.008 2.16 74.898 2.295 ;
     RECT  74.952 2.16 75.762 2.295 ;
     RECT  75.816 2.16 76.086 2.295 ;
     RECT  76.194 2.16 78.624 2.295 ;
     RECT  78.732 2.16 80.352 2.295 ;
     RECT  80.46 2.16 82.08 2.295 ;
     RECT  82.296 2.16 82.836 2.295 ;
     RECT  82.89 2.16 83.43 2.295 ;
     RECT  83.484 2.16 84.294 2.295 ;
     RECT  84.348 2.16 85.158 2.295 ;
     RECT  85.266 2.16 86.616 2.295 ;
     RECT  86.67 2.16 86.94 2.295 ;
     RECT  86.994 2.16 87.534 2.295 ;
     RECT  87.588 2.16 87.858 2.295 ;
     RECT  88.236 2.16 89.586 2.295 ;
     RECT  89.856 2.16 90.666 2.295 ;
     RECT  91.044 2.16 91.314 2.295 ;
     RECT  91.476 2.16 92.34 2.295 ;
     RECT  92.556 2.16 93.366 2.295 ;
     RECT  93.42 2.16 93.69 2.295 ;
     RECT  93.798 2.16 94.068 2.295 ;
     RECT  94.122 2.16 94.662 2.295 ;
     RECT  94.824 2.16 95.364 2.295 ;
     RECT  95.418 2.16 95.958 2.295 ;
     RECT  96.066 2.16 96.876 2.295 ;
     RECT  96.93 2.16 99.36 2.295 ;
     RECT  99.468 2.16 99.738 2.295 ;
     RECT  99.846 2.16 100.116 2.295 ;
     RECT  100.17 2.16 100.98 2.295 ;
     RECT  101.034 2.16 101.304 2.295 ;
     RECT  101.358 2.16 101.898 2.295 ;
     RECT  101.952 2.16 102.33 2.295 ;
     RECT  102.438 2.16 102.708 2.295 ;
     RECT  102.762 2.16 103.032 2.295 ;
     RECT  103.248 2.16 103.518 2.295 ;
     RECT  103.626 2.16 104.976 2.295 ;
     RECT  105.084 2.16 105.624 2.295 ;
     RECT  105.786 2.16 106.056 2.295 ;
     RECT  106.164 2.16 106.704 2.295 ;
     RECT  106.866 2.16 107.136 2.295 ;
     RECT  107.622 2.16 108.162 2.295 ;
     RECT  108.486 2.16 109.35 2.295 ;
     RECT  109.836 2.16 110.106 2.295 ;
     RECT  110.214 2.16 110.484 2.295 ;
     RECT  110.646 2.16 111.24 2.295 ;
     RECT  111.348 2.16 112.158 2.295 ;
     RECT  112.482 2.16 113.562 2.295 ;
     RECT  114.264 2.16 115.074 2.295 ;
     RECT  115.398 2.16 116.208 2.295 ;
     RECT  116.586 2.16 116.856 2.295 ;
     RECT  117.72 2.16 118.26 2.295 ;
     RECT  119.07 2.16 119.34 2.295 ;
     RECT  126.9 2.16 127.008 2.295 ;
     RECT  127.332 2.16 127.44 2.295 ;
     RECT  13.932 2.565 14.202 2.7 ;
     RECT  14.688 2.565 14.958 2.7 ;
     RECT  16.146 2.565 17.604 2.7 ;
     RECT  18.198 2.565 18.468 2.7 ;
     RECT  19.818 2.565 20.088 2.7 ;
     RECT  20.79 2.565 21.168 2.7 ;
     RECT  22.302 2.565 22.842 2.7 ;
     RECT  23.112 2.565 23.652 2.7 ;
     RECT  23.814 2.565 24.624 2.7 ;
     RECT  24.84 2.565 26.19 2.7 ;
     RECT  26.298 2.565 27.918 2.7 ;
     RECT  28.134 2.565 28.404 2.7 ;
     RECT  28.458 2.565 28.998 2.7 ;
     RECT  29.214 2.565 30.888 2.7 ;
     RECT  30.942 2.565 32.4 2.7 ;
     RECT  32.562 2.565 33.102 2.7 ;
     RECT  33.21 2.565 34.83 2.7 ;
     RECT  35.154 2.565 35.964 2.7 ;
     RECT  36.18 2.565 36.45 2.7 ;
     RECT  36.99 2.565 37.53 2.7 ;
     RECT  37.746 2.565 38.016 2.7 ;
     RECT  38.178 2.565 38.448 2.7 ;
     RECT  39.042 2.565 39.312 2.7 ;
     RECT  39.42 2.565 39.69 2.7 ;
     RECT  39.798 2.565 40.392 2.7 ;
     RECT  40.932 2.565 41.202 2.7 ;
     RECT  41.418 2.565 41.958 2.7 ;
     RECT  42.444 2.565 44.496 2.7 ;
     RECT  44.604 2.565 47.52 2.7 ;
     RECT  47.574 2.565 48.168 2.7 ;
     RECT  48.384 2.565 49.194 2.7 ;
     RECT  49.572 2.565 49.896 2.7 ;
     RECT  50.058 2.565 51.732 2.7 ;
     RECT  52.056 2.565 52.164 2.7 ;
     RECT  52.218 2.565 53.298 2.7 ;
     RECT  53.892 2.565 54.162 2.7 ;
     RECT  55.026 2.565 55.404 2.7 ;
     RECT  56.538 2.565 58.428 2.7 ;
     RECT  58.644 2.565 59.4 2.7 ;
     RECT  60.75 2.565 61.02 2.7 ;
     RECT  61.128 2.565 61.398 2.7 ;
     RECT  61.56 2.565 62.37 2.7 ;
     RECT  62.532 2.565 62.802 2.7 ;
     RECT  62.856 2.565 63.126 2.7 ;
     RECT  63.234 2.565 64.584 2.7 ;
     RECT  68.742 2.565 70.092 2.7 ;
     RECT  70.254 2.565 71.334 2.7 ;
     RECT  71.388 2.565 71.928 2.7 ;
     RECT  71.982 2.565 72.522 2.7 ;
     RECT  72.576 2.565 72.846 2.7 ;
     RECT  72.954 2.565 74.034 2.7 ;
     RECT  74.196 2.565 76.356 2.7 ;
     RECT  76.572 2.565 77.922 2.7 ;
     RECT  77.976 2.565 78.786 2.7 ;
     RECT  78.84 2.565 79.272 2.7 ;
     RECT  79.38 2.565 80.19 2.7 ;
     RECT  80.352 2.565 80.946 2.7 ;
     RECT  81 2.565 81.594 2.7 ;
     RECT  81.648 2.565 83.268 2.7 ;
     RECT  83.322 2.565 83.592 2.7 ;
     RECT  83.7 2.565 86.886 2.7 ;
     RECT  86.994 2.565 87.264 2.7 ;
     RECT  87.426 2.565 87.696 2.7 ;
     RECT  88.344 2.565 88.614 2.7 ;
     RECT  88.776 2.565 89.64 2.7 ;
     RECT  90.288 2.565 90.828 2.7 ;
     RECT  91.098 2.565 93.96 2.7 ;
     RECT  94.122 2.565 94.662 2.7 ;
     RECT  94.716 2.565 96.336 2.7 ;
     RECT  96.39 2.565 96.93 2.7 ;
     RECT  96.984 2.565 97.848 2.7 ;
     RECT  98.01 2.565 98.28 2.7 ;
     RECT  98.388 2.565 98.658 2.7 ;
     RECT  98.766 2.565 100.17 2.7 ;
     RECT  100.278 2.565 101.358 2.7 ;
     RECT  101.412 2.565 102.654 2.7 ;
     RECT  102.708 2.565 102.978 2.7 ;
     RECT  103.41 2.565 103.95 2.7 ;
     RECT  104.058 2.565 104.598 2.7 ;
     RECT  105.3 2.565 105.84 2.7 ;
     RECT  106.812 2.565 107.082 2.7 ;
     RECT  107.136 2.565 107.46 2.7 ;
     RECT  108.756 2.565 109.836 2.7 ;
     RECT  110.484 2.565 111.726 2.7 ;
     RECT  114.21 2.565 114.75 2.7 ;
     RECT  115.128 2.565 115.776 2.7 ;
     RECT  115.83 2.565 116.37 2.7 ;
     RECT  2.16 2.565 2.268 2.835 ;
     RECT  13.824 2.7 14.094 2.835 ;
     RECT  16.74 2.7 17.01 2.835 ;
     RECT  17.442 2.7 17.712 2.835 ;
     RECT  17.766 2.7 18.306 2.835 ;
     RECT  19.656 2.7 21.276 2.835 ;
     RECT  21.6 2.565 21.87 2.835 ;
     RECT  22.14 2.7 23.76 2.835 ;
     RECT  23.814 2.7 24.354 2.835 ;
     RECT  24.408 2.7 24.678 2.835 ;
     RECT  24.786 2.7 25.326 2.835 ;
     RECT  25.38 2.7 25.92 2.835 ;
     RECT  26.028 2.7 28.404 2.835 ;
     RECT  28.512 2.7 28.782 2.835 ;
     RECT  28.89 2.7 31.32 2.835 ;
     RECT  31.59 2.7 32.022 2.835 ;
     RECT  32.13 2.7 33.372 2.835 ;
     RECT  33.48 2.7 34.02 2.835 ;
     RECT  34.074 2.7 34.614 2.835 ;
     RECT  34.776 2.7 35.046 2.835 ;
     RECT  35.37 2.7 35.91 2.835 ;
     RECT  36.882 2.7 37.962 2.835 ;
     RECT  38.016 2.7 38.394 2.835 ;
     RECT  39.096 2.7 40.338 2.835 ;
     RECT  40.554 2.565 40.824 2.835 ;
     RECT  41.04 2.7 41.31 2.835 ;
     RECT  41.364 2.7 42.768 2.835 ;
     RECT  42.93 2.7 44.28 2.835 ;
     RECT  44.334 2.7 44.604 2.835 ;
     RECT  44.712 2.7 46.872 2.835 ;
     RECT  46.98 2.7 49.302 2.835 ;
     RECT  49.518 2.7 52.866 2.835 ;
     RECT  53.19 2.7 53.46 2.835 ;
     RECT  54.648 2.7 54.918 2.835 ;
     RECT  55.026 2.7 56.106 2.835 ;
     RECT  57.024 2.7 57.294 2.835 ;
     RECT  57.51 2.7 58.05 2.835 ;
     RECT  59.022 2.7 59.562 2.835 ;
     RECT  60.426 2.7 61.506 2.835 ;
     RECT  61.668 2.7 61.938 2.835 ;
     RECT  61.992 2.7 62.316 2.835 ;
     RECT  62.424 2.7 62.694 2.835 ;
     RECT  62.748 2.7 63.018 2.835 ;
     RECT  63.072 2.7 63.774 2.835 ;
     RECT  63.828 2.7 64.638 2.835 ;
     RECT  67.392 2.7 68.472 2.835 ;
     RECT  68.742 2.7 69.066 2.835 ;
     RECT  69.336 2.7 69.66 2.835 ;
     RECT  69.768 2.7 70.2 2.835 ;
     RECT  70.254 2.7 71.604 2.835 ;
     RECT  71.712 2.7 71.982 2.835 ;
     RECT  72.036 2.7 72.36 2.835 ;
     RECT  72.522 2.7 74.844 2.835 ;
     RECT  75.114 2.7 75.708 2.835 ;
     RECT  75.762 2.7 76.356 2.835 ;
     RECT  76.464 2.7 77.112 2.835 ;
     RECT  77.166 2.7 77.49 2.835 ;
     RECT  77.544 2.7 78.192 2.835 ;
     RECT  78.354 2.7 79.758 2.835 ;
     RECT  79.866 2.7 83.268 2.835 ;
     RECT  83.376 2.7 84.24 2.835 ;
     RECT  84.348 2.7 85.86 2.835 ;
     RECT  85.914 2.7 86.724 2.835 ;
     RECT  87.102 2.7 87.372 2.835 ;
     RECT  87.966 2.7 88.236 2.835 ;
     RECT  88.56 2.7 89.64 2.835 ;
     RECT  90.288 2.7 90.558 2.835 ;
     RECT  90.612 2.7 90.936 2.835 ;
     RECT  91.206 2.7 92.07 2.835 ;
     RECT  92.178 2.7 92.502 2.835 ;
     RECT  92.718 2.7 93.258 2.835 ;
     RECT  93.366 2.7 93.636 2.835 ;
     RECT  93.69 2.7 94.554 2.835 ;
     RECT  94.608 2.7 95.472 2.835 ;
     RECT  95.526 2.7 97.416 2.835 ;
     RECT  97.686 2.7 98.388 2.835 ;
     RECT  98.442 2.7 98.712 2.835 ;
     RECT  98.766 2.7 99.576 2.835 ;
     RECT  99.63 2.7 99.954 2.835 ;
     RECT  100.062 2.7 101.142 2.835 ;
     RECT  101.196 2.7 102.276 2.835 ;
     RECT  102.492 2.7 103.032 2.835 ;
     RECT  103.248 2.7 103.95 2.835 ;
     RECT  104.49 2.7 104.814 2.835 ;
     RECT  105.408 2.7 105.948 2.835 ;
     RECT  106.002 2.565 106.272 2.835 ;
     RECT  106.434 2.7 106.974 2.835 ;
     RECT  107.244 2.7 108.81 2.835 ;
     RECT  108.864 2.7 109.35 2.835 ;
     RECT  109.836 2.7 110.106 2.835 ;
     RECT  111.942 2.7 112.212 2.835 ;
     RECT  112.482 2.7 113.562 2.835 ;
     RECT  114.534 2.7 114.858 2.835 ;
     RECT  115.074 2.7 115.398 2.835 ;
     RECT  115.506 2.7 116.748 2.835 ;
     RECT  117.828 2.7 118.368 2.835 ;
     RECT  118.962 2.7 119.232 2.835 ;
     RECT  126.9 2.7 127.008 2.835 ;
     RECT  127.332 2.565 127.44 2.835 ;
     RECT  13.986 3.105 16.092 3.24 ;
     RECT  17.118 3.105 17.28 3.24 ;
     RECT  17.55 3.105 17.874 3.24 ;
     RECT  18.63 3.105 19.872 3.24 ;
     RECT  19.926 3.105 20.52 3.24 ;
     RECT  20.736 3.105 21.06 3.24 ;
     RECT  21.33 3.105 22.788 3.24 ;
     RECT  22.95 3.105 23.22 3.24 ;
     RECT  23.328 3.105 24.786 3.24 ;
     RECT  24.894 3.105 25.434 3.24 ;
     RECT  26.136 3.105 28.296 3.24 ;
     RECT  28.404 3.105 28.944 3.24 ;
     RECT  29.052 3.105 29.646 3.24 ;
     RECT  29.808 3.105 31.05 3.24 ;
     RECT  31.266 3.105 31.536 3.24 ;
     RECT  31.59 3.105 32.184 3.24 ;
     RECT  32.292 3.105 33.264 3.24 ;
     RECT  33.534 3.105 34.236 3.24 ;
     RECT  34.398 3.105 34.83 3.24 ;
     RECT  35.208 3.105 36.828 3.24 ;
     RECT  36.882 3.105 37.26 3.24 ;
     RECT  37.584 3.105 37.746 3.24 ;
     RECT  37.908 3.105 38.232 3.24 ;
     RECT  39.204 3.105 39.852 3.24 ;
     RECT  39.906 3.105 40.5 3.24 ;
     RECT  40.662 3.105 40.932 3.24 ;
     RECT  40.986 3.105 41.256 3.24 ;
     RECT  41.364 3.105 42.174 3.24 ;
     RECT  42.336 3.105 42.66 3.24 ;
     RECT  42.714 3.105 43.254 3.24 ;
     RECT  43.308 3.105 43.902 3.24 ;
     RECT  44.01 3.105 44.28 3.24 ;
     RECT  44.388 3.105 45.792 3.24 ;
     RECT  45.846 3.105 46.926 3.24 ;
     RECT  46.98 3.105 47.304 3.24 ;
     RECT  47.358 3.105 49.41 3.24 ;
     RECT  49.518 3.105 49.68 3.24 ;
     RECT  49.842 3.105 50.274 3.24 ;
     RECT  50.328 3.105 50.598 3.24 ;
     RECT  50.814 3.105 50.976 3.24 ;
     RECT  51.03 3.105 51.84 3.24 ;
     RECT  52.056 3.105 52.164 3.24 ;
     RECT  52.272 3.105 52.812 3.24 ;
     RECT  53.352 3.105 53.514 3.24 ;
     RECT  54.594 3.105 54.864 3.24 ;
     RECT  55.242 3.105 55.566 3.24 ;
     RECT  55.998 3.105 56.16 3.24 ;
     RECT  57.186 3.105 58.05 3.24 ;
     RECT  58.212 3.105 58.86 3.24 ;
     RECT  58.968 3.105 60.102 3.24 ;
     RECT  60.264 3.105 60.534 3.24 ;
     RECT  60.966 3.105 61.29 3.24 ;
     RECT  61.344 3.105 62.208 3.24 ;
     RECT  62.316 3.105 63.666 3.24 ;
     RECT  63.774 3.105 64.584 3.24 ;
     RECT  68.04 3.105 68.31 3.24 ;
     RECT  68.418 3.105 68.58 3.24 ;
     RECT  68.634 3.105 68.958 3.24 ;
     RECT  69.444 3.105 70.038 3.24 ;
     RECT  70.2 3.105 71.712 3.24 ;
     RECT  71.766 3.105 72.09 3.24 ;
     RECT  72.198 3.105 73.44 3.24 ;
     RECT  73.494 3.105 74.196 3.24 ;
     RECT  74.304 3.105 78.192 3.24 ;
     RECT  78.354 3.105 81.378 3.24 ;
     RECT  81.432 3.105 82.512 3.24 ;
     RECT  82.62 3.105 85.374 3.24 ;
     RECT  85.482 3.105 86.076 3.24 ;
     RECT  86.184 3.105 87.264 3.24 ;
     RECT  87.534 3.105 89.424 3.24 ;
     RECT  89.532 3.105 90.936 3.24 ;
     RECT  91.098 3.105 91.368 3.24 ;
     RECT  91.422 3.105 92.07 3.24 ;
     RECT  92.178 3.105 92.772 3.24 ;
     RECT  92.988 3.105 95.904 3.24 ;
     RECT  95.958 3.105 96.228 3.24 ;
     RECT  96.444 3.105 96.714 3.24 ;
     RECT  96.822 3.105 97.092 3.24 ;
     RECT  97.146 3.105 97.686 3.24 ;
     RECT  97.794 3.105 98.874 3.24 ;
     RECT  99.036 3.105 99.306 3.24 ;
     RECT  99.414 3.105 100.062 3.24 ;
     RECT  100.116 3.105 101.25 3.24 ;
     RECT  101.466 3.105 101.736 3.24 ;
     RECT  101.952 3.105 102.06 3.24 ;
     RECT  102.276 3.105 103.626 3.24 ;
     RECT  104.49 3.105 104.814 3.24 ;
     RECT  105.354 3.105 105.624 3.24 ;
     RECT  106.164 3.105 106.758 3.24 ;
     RECT  107.838 3.105 108.108 3.24 ;
     RECT  110.808 3.105 111.132 3.24 ;
     RECT  112.212 3.105 112.86 3.24 ;
     RECT  113.022 3.105 113.454 3.24 ;
     RECT  114.372 3.105 114.696 3.24 ;
     RECT  114.912 3.105 115.236 3.24 ;
     RECT  115.344 3.105 115.614 3.24 ;
     RECT  116.046 3.105 116.316 3.24 ;
     RECT  117.99 3.105 118.26 3.24 ;
     RECT  2.16 3.105 2.268 3.375 ;
     RECT  12.906 3.24 14.472 3.375 ;
     RECT  15.228 3.24 15.714 3.375 ;
     RECT  17.442 3.24 17.712 3.375 ;
     RECT  19.386 3.24 19.656 3.375 ;
     RECT  21.708 3.24 21.978 3.375 ;
     RECT  22.356 3.24 22.518 3.375 ;
     RECT  22.572 3.24 22.842 3.375 ;
     RECT  22.896 3.24 23.166 3.375 ;
     RECT  23.274 3.24 23.544 3.375 ;
     RECT  23.652 3.24 24.57 3.375 ;
     RECT  24.624 3.24 25.434 3.375 ;
     RECT  25.92 3.24 26.568 3.375 ;
     RECT  26.73 3.24 27.216 3.375 ;
     RECT  27.324 3.24 28.296 3.375 ;
     RECT  28.35 3.24 30.132 3.375 ;
     RECT  30.402 3.24 30.726 3.375 ;
     RECT  30.78 3.24 31.266 3.375 ;
     RECT  31.482 3.24 32.886 3.375 ;
     RECT  33.75 3.24 34.02 3.375 ;
     RECT  34.182 3.24 35.64 3.375 ;
     RECT  35.748 3.24 36.018 3.375 ;
     RECT  36.774 3.24 36.936 3.375 ;
     RECT  36.99 3.24 37.314 3.375 ;
     RECT  37.962 3.24 39.798 3.375 ;
     RECT  39.906 3.24 40.176 3.375 ;
     RECT  40.284 3.24 41.796 3.375 ;
     RECT  42.39 3.24 43.632 3.375 ;
     RECT  43.686 3.24 44.118 3.375 ;
     RECT  44.226 3.24 45.252 3.375 ;
     RECT  45.522 3.24 46.008 3.375 ;
     RECT  46.116 3.24 46.71 3.375 ;
     RECT  46.926 3.24 47.358 3.375 ;
     RECT  47.412 3.24 47.736 3.375 ;
     RECT  47.79 3.24 48.114 3.375 ;
     RECT  48.168 3.24 48.492 3.375 ;
     RECT  48.546 3.24 49.896 3.375 ;
     RECT  49.95 3.24 50.274 3.375 ;
     RECT  50.328 3.24 51.678 3.375 ;
     RECT  51.894 3.24 52.164 3.375 ;
     RECT  52.488 3.24 52.866 3.375 ;
     RECT  53.136 3.24 53.298 3.375 ;
     RECT  53.352 3.24 53.676 3.375 ;
     RECT  53.73 3.24 54 3.375 ;
     RECT  54.378 3.24 55.08 3.375 ;
     RECT  55.242 3.24 55.62 3.375 ;
     RECT  56.322 3.24 57.294 3.375 ;
     RECT  57.456 3.24 57.618 3.375 ;
     RECT  57.726 3.24 58.968 3.375 ;
     RECT  59.022 3.24 60.426 3.375 ;
     RECT  60.48 3.24 61.236 3.375 ;
     RECT  61.614 3.24 62.856 3.375 ;
     RECT  63.072 3.24 63.666 3.375 ;
     RECT  63.828 3.24 64.098 3.375 ;
     RECT  64.206 3.24 64.476 3.375 ;
     RECT  69.66 3.24 69.93 3.375 ;
     RECT  70.146 3.24 70.416 3.375 ;
     RECT  70.47 3.24 71.82 3.375 ;
     RECT  72.036 3.24 74.034 3.375 ;
     RECT  74.196 3.24 74.79 3.375 ;
     RECT  74.844 3.24 80.622 3.375 ;
     RECT  80.676 3.24 81 3.375 ;
     RECT  81.108 3.24 81.378 3.375 ;
     RECT  81.432 3.24 82.296 3.375 ;
     RECT  82.404 3.24 83.538 3.375 ;
     RECT  83.7 3.24 87.048 3.375 ;
     RECT  87.588 3.24 87.912 3.375 ;
     RECT  88.56 3.24 88.722 3.375 ;
     RECT  89.316 3.24 89.64 3.375 ;
     RECT  90.45 3.24 90.612 3.375 ;
     RECT  90.72 3.24 91.044 3.375 ;
     RECT  91.152 3.24 93.528 3.375 ;
     RECT  93.582 3.24 94.284 3.375 ;
     RECT  94.392 3.24 95.256 3.375 ;
     RECT  95.31 3.24 95.904 3.375 ;
     RECT  96.066 3.24 96.39 3.375 ;
     RECT  96.498 3.24 97.902 3.375 ;
     RECT  97.956 3.24 100.116 3.375 ;
     RECT  100.17 3.24 101.034 3.375 ;
     RECT  101.52 3.24 102.06 3.375 ;
     RECT  102.222 3.24 102.762 3.375 ;
     RECT  102.978 3.24 103.302 3.375 ;
     RECT  104.22 3.24 105.732 3.375 ;
     RECT  106.218 3.24 108.648 3.375 ;
     RECT  109.836 3.24 110.106 3.375 ;
     RECT  110.538 3.24 111.942 3.375 ;
     RECT  112.212 3.24 112.482 3.375 ;
     RECT  114.534 3.24 115.614 3.375 ;
     RECT  115.884 3.24 116.154 3.375 ;
     RECT  116.64 3.24 116.91 3.375 ;
     RECT  117.288 3.24 117.558 3.375 ;
     RECT  119.232 3.24 119.502 3.375 ;
     RECT  126.9 3.24 127.008 3.375 ;
     RECT  127.332 3.105 127.44 3.375 ;
     RECT  15.12 3.645 16.524 3.78 ;
     RECT  16.686 3.645 17.064 3.78 ;
     RECT  17.28 3.645 17.55 3.78 ;
     RECT  17.604 3.645 18.09 3.78 ;
     RECT  21.6 3.645 22.194 3.78 ;
     RECT  22.248 3.645 22.572 3.78 ;
     RECT  24.084 3.645 24.408 3.78 ;
     RECT  24.516 3.645 25.002 3.78 ;
     RECT  25.218 3.645 25.38 3.78 ;
     RECT  25.812 3.645 28.62 3.78 ;
     RECT  28.782 3.645 30.24 3.78 ;
     RECT  30.51 3.645 30.834 3.78 ;
     RECT  30.942 3.645 31.32 3.78 ;
     RECT  31.482 3.645 32.562 3.78 ;
     RECT  32.616 3.645 32.778 3.78 ;
     RECT  32.94 3.645 33.318 3.78 ;
     RECT  33.426 3.645 34.506 3.78 ;
     RECT  35.154 3.645 35.64 3.78 ;
     RECT  36.558 3.645 36.828 3.78 ;
     RECT  39.204 3.645 40.608 3.78 ;
     RECT  40.662 3.645 40.932 3.78 ;
     RECT  40.986 3.645 41.256 3.78 ;
     RECT  41.364 3.645 41.634 3.78 ;
     RECT  42.444 3.645 43.038 3.78 ;
     RECT  43.146 3.645 45.09 3.78 ;
     RECT  45.252 3.645 45.576 3.78 ;
     RECT  45.63 3.645 45.792 3.78 ;
     RECT  45.954 3.645 47.196 3.78 ;
     RECT  47.25 3.645 48.816 3.78 ;
     RECT  48.87 3.645 50.382 3.78 ;
     RECT  51.246 3.645 51.57 3.78 ;
     RECT  52.056 3.645 52.164 3.78 ;
     RECT  52.65 3.645 52.974 3.78 ;
     RECT  53.352 3.645 53.73 3.78 ;
     RECT  54.054 3.645 55.134 3.78 ;
     RECT  55.188 3.645 55.35 3.78 ;
     RECT  56.538 3.645 57.78 3.78 ;
     RECT  57.834 3.645 60.48 3.78 ;
     RECT  62.1 3.645 62.37 3.78 ;
     RECT  62.478 3.645 63.072 3.78 ;
     RECT  63.234 3.645 63.666 3.78 ;
     RECT  63.72 3.645 64.368 3.78 ;
     RECT  66.96 3.645 68.364 3.78 ;
     RECT  69.12 3.645 69.39 3.78 ;
     RECT  70.254 3.645 71.118 3.78 ;
     RECT  71.28 3.645 71.604 3.78 ;
     RECT  71.874 3.645 72.144 3.78 ;
     RECT  72.252 3.645 72.522 3.78 ;
     RECT  72.576 3.645 73.44 3.78 ;
     RECT  73.494 3.645 75.654 3.78 ;
     RECT  75.708 3.645 79.056 3.78 ;
     RECT  79.11 3.645 81.432 3.78 ;
     RECT  81.486 3.645 81.81 3.78 ;
     RECT  81.864 3.645 84.672 3.78 ;
     RECT  84.726 3.645 86.022 3.78 ;
     RECT  86.13 3.645 86.832 3.78 ;
     RECT  87.156 3.645 87.48 3.78 ;
     RECT  88.344 3.645 88.668 3.78 ;
     RECT  88.884 3.645 89.154 3.78 ;
     RECT  90.558 3.645 99.792 3.78 ;
     RECT  99.846 3.645 100.116 3.78 ;
     RECT  100.224 3.645 101.844 3.78 ;
     RECT  101.952 3.645 102.06 3.78 ;
     RECT  102.222 3.645 102.546 3.78 ;
     RECT  102.762 3.645 104.328 3.78 ;
     RECT  105.354 3.645 106.974 3.78 ;
     RECT  107.19 3.645 107.514 3.78 ;
     RECT  110.106 3.645 110.376 3.78 ;
     RECT  110.646 3.645 110.97 3.78 ;
     RECT  111.294 3.645 111.564 3.78 ;
     RECT  111.888 3.645 112.05 3.78 ;
     RECT  113.076 3.645 113.346 3.78 ;
     RECT  114.588 3.645 114.75 3.78 ;
     RECT  115.074 3.645 116.316 3.78 ;
     RECT  119.178 3.645 119.448 3.78 ;
     RECT  2.16 3.645 2.268 3.915 ;
     RECT  16.146 3.78 16.308 3.915 ;
     RECT  16.362 3.78 17.712 3.915 ;
     RECT  17.766 3.78 18.144 3.915 ;
     RECT  19.17 3.78 19.818 3.915 ;
     RECT  19.98 3.78 21.06 3.915 ;
     RECT  21.222 3.78 21.492 3.915 ;
     RECT  21.978 3.78 22.68 3.915 ;
     RECT  23.814 3.78 24.138 3.915 ;
     RECT  24.192 3.78 25.002 3.915 ;
     RECT  25.488 3.78 27.54 3.915 ;
     RECT  27.756 3.78 28.08 3.915 ;
     RECT  28.188 3.78 29.592 3.915 ;
     RECT  29.646 3.78 30.726 3.915 ;
     RECT  30.942 3.78 31.482 3.915 ;
     RECT  31.752 3.78 31.914 3.915 ;
     RECT  32.022 3.78 32.292 3.915 ;
     RECT  32.508 3.78 34.452 3.915 ;
     RECT  36.234 3.78 36.936 3.915 ;
     RECT  38.502 3.78 39.15 3.915 ;
     RECT  39.204 3.78 39.744 3.915 ;
     RECT  39.906 3.78 40.176 3.915 ;
     RECT  40.284 3.78 40.608 3.915 ;
     RECT  41.31 3.78 41.58 3.915 ;
     RECT  42.066 3.78 42.336 3.915 ;
     RECT  42.39 3.78 45.684 3.915 ;
     RECT  45.792 3.78 46.602 3.915 ;
     RECT  46.764 3.78 47.844 3.915 ;
     RECT  47.952 3.78 48.276 3.915 ;
     RECT  48.33 3.78 48.816 3.915 ;
     RECT  49.032 3.78 50.76 3.915 ;
     RECT  51.084 3.78 53.568 3.915 ;
     RECT  53.676 3.78 53.946 3.915 ;
     RECT  54.324 3.78 55.944 3.915 ;
     RECT  56.322 3.78 56.916 3.915 ;
     RECT  56.97 3.78 58.05 3.915 ;
     RECT  58.104 3.78 58.266 3.915 ;
     RECT  58.32 3.78 58.698 3.915 ;
     RECT  58.752 3.78 59.184 3.915 ;
     RECT  59.238 3.78 60.318 3.915 ;
     RECT  60.372 3.78 61.182 3.915 ;
     RECT  62.154 3.78 63.288 3.915 ;
     RECT  63.342 3.78 65.124 3.915 ;
     RECT  67.932 3.78 68.094 3.915 ;
     RECT  68.31 3.78 69.39 3.915 ;
     RECT  69.444 3.78 70.686 3.915 ;
     RECT  70.74 3.78 71.064 3.915 ;
     RECT  71.118 3.78 72.684 3.915 ;
     RECT  72.738 3.78 73.008 3.915 ;
     RECT  73.332 3.78 75.06 3.915 ;
     RECT  75.222 3.78 75.546 3.915 ;
     RECT  75.654 3.78 77.652 3.915 ;
     RECT  77.814 3.78 79.002 3.915 ;
     RECT  79.056 3.78 79.704 3.915 ;
     RECT  79.866 3.78 82.674 3.915 ;
     RECT  82.728 3.78 85.266 3.915 ;
     RECT  85.374 3.78 86.454 3.915 ;
     RECT  87.102 3.78 88.506 3.915 ;
     RECT  88.668 3.78 88.938 3.915 ;
     RECT  89.208 3.78 89.532 3.915 ;
     RECT  89.64 3.78 89.91 3.915 ;
     RECT  91.044 3.78 93.096 3.915 ;
     RECT  93.15 3.78 96.066 3.915 ;
     RECT  96.282 3.78 98.604 3.915 ;
     RECT  98.658 3.78 99.252 3.915 ;
     RECT  99.468 3.78 100.71 3.915 ;
     RECT  100.818 3.78 101.304 3.915 ;
     RECT  101.466 3.78 101.736 3.915 ;
     RECT  101.79 3.78 102.762 3.915 ;
     RECT  103.626 3.78 104.274 3.915 ;
     RECT  104.868 3.645 105.192 3.915 ;
     RECT  105.462 3.78 105.786 3.915 ;
     RECT  106.056 3.78 106.488 3.915 ;
     RECT  106.542 3.78 106.866 3.915 ;
     RECT  106.92 3.78 107.568 3.915 ;
     RECT  107.838 3.78 108.108 3.915 ;
     RECT  108.378 3.78 108.648 3.915 ;
     RECT  112.752 3.78 113.67 3.915 ;
     RECT  114.804 3.78 115.074 3.915 ;
     RECT  115.344 3.78 115.668 3.915 ;
     RECT  118.098 3.78 119.178 3.915 ;
     RECT  126.9 3.78 127.008 3.915 ;
     RECT  127.332 3.645 127.44 3.915 ;
     RECT  14.31 4.185 14.688 4.32 ;
     RECT  14.796 4.185 15.066 4.32 ;
     RECT  15.336 4.185 15.606 4.32 ;
     RECT  18.36 4.185 18.738 4.32 ;
     RECT  18.846 4.185 19.332 4.32 ;
     RECT  19.872 4.185 20.952 4.32 ;
     RECT  21.924 4.185 22.194 4.32 ;
     RECT  22.302 4.185 22.626 4.32 ;
     RECT  22.842 4.185 25.38 4.32 ;
     RECT  25.488 4.185 25.866 4.32 ;
     RECT  26.028 4.185 26.352 4.32 ;
     RECT  26.406 4.185 27.756 4.32 ;
     RECT  27.918 4.185 28.242 4.32 ;
     RECT  28.458 4.185 30.672 4.32 ;
     RECT  30.78 4.185 32.184 4.32 ;
     RECT  32.454 4.185 33.372 4.32 ;
     RECT  33.534 4.185 33.696 4.32 ;
     RECT  33.858 4.185 34.938 4.32 ;
     RECT  35.586 4.185 36.828 4.32 ;
     RECT  36.882 4.185 38.232 4.32 ;
     RECT  38.772 4.185 39.636 4.32 ;
     RECT  39.744 4.185 40.716 4.32 ;
     RECT  42.12 4.185 42.768 4.32 ;
     RECT  42.93 4.185 43.362 4.32 ;
     RECT  43.416 4.185 44.226 4.32 ;
     RECT  44.28 4.185 44.658 4.32 ;
     RECT  44.82 4.185 47.25 4.32 ;
     RECT  47.304 4.185 49.95 4.32 ;
     RECT  50.058 4.185 50.706 4.32 ;
     RECT  50.922 4.185 51.894 4.32 ;
     RECT  52.056 4.185 52.164 4.32 ;
     RECT  52.218 4.185 52.488 4.32 ;
     RECT  52.542 4.185 52.866 4.32 ;
     RECT  54 4.185 54.594 4.32 ;
     RECT  54.648 4.185 55.728 4.32 ;
     RECT  55.944 4.185 57.51 4.32 ;
     RECT  57.564 4.185 60.75 4.32 ;
     RECT  60.858 4.185 61.722 4.32 ;
     RECT  62.478 4.185 63.018 4.32 ;
     RECT  63.072 4.185 64.152 4.32 ;
     RECT  64.206 4.185 64.53 4.32 ;
     RECT  64.8 4.185 64.962 4.32 ;
     RECT  67.986 4.185 68.31 4.32 ;
     RECT  68.634 4.185 68.958 4.32 ;
     RECT  70.848 4.185 71.118 4.32 ;
     RECT  71.496 4.185 71.766 4.32 ;
     RECT  71.982 4.185 72.306 4.32 ;
     RECT  72.522 4.185 74.574 4.32 ;
     RECT  74.682 4.185 77.382 4.32 ;
     RECT  77.49 4.185 78.57 4.32 ;
     RECT  78.678 4.185 79.596 4.32 ;
     RECT  79.758 4.185 80.568 4.32 ;
     RECT  80.622 4.185 81.81 4.32 ;
     RECT  81.864 4.185 82.404 4.32 ;
     RECT  82.512 4.185 83.916 4.32 ;
     RECT  83.97 4.185 85.374 4.32 ;
     RECT  85.482 4.185 87.102 4.32 ;
     RECT  87.156 4.185 87.48 4.32 ;
     RECT  88.074 4.185 89.478 4.32 ;
     RECT  89.586 4.185 89.91 4.32 ;
     RECT  90.828 4.185 91.152 4.32 ;
     RECT  91.26 4.185 91.584 4.32 ;
     RECT  91.692 4.185 92.286 4.32 ;
     RECT  92.394 4.185 92.88 4.32 ;
     RECT  92.988 4.185 94.338 4.32 ;
     RECT  94.392 4.185 96.39 4.32 ;
     RECT  96.444 4.185 97.632 4.32 ;
     RECT  97.686 4.185 98.334 4.32 ;
     RECT  98.442 4.185 99.09 4.32 ;
     RECT  99.198 4.185 99.738 4.32 ;
     RECT  99.9 4.185 100.818 4.32 ;
     RECT  101.142 4.185 101.466 4.32 ;
     RECT  101.574 4.185 101.898 4.32 ;
     RECT  101.952 4.185 102.06 4.32 ;
     RECT  102.276 4.185 103.626 4.32 ;
     RECT  103.95 4.185 105.192 4.32 ;
     RECT  105.246 4.185 105.516 4.32 ;
     RECT  106.38 4.185 107.622 4.32 ;
     RECT  107.676 4.185 107.838 4.32 ;
     RECT  109.566 4.185 110.646 4.32 ;
     RECT  111.24 4.185 111.51 4.32 ;
     RECT  111.564 4.185 111.834 4.32 ;
     RECT  112.104 4.185 112.752 4.32 ;
     RECT  113.454 4.185 113.724 4.32 ;
     RECT  115.506 4.185 116.586 4.32 ;
     RECT  116.91 4.185 117.18 4.32 ;
     RECT  117.936 4.185 118.26 4.32 ;
     RECT  118.422 4.185 118.584 4.32 ;
     RECT  2.16 4.185 2.268 4.455 ;
     RECT  13.014 4.32 15.606 4.455 ;
     RECT  16.902 4.32 17.172 4.455 ;
     RECT  17.28 4.32 17.658 4.455 ;
     RECT  17.712 4.32 17.874 4.455 ;
     RECT  18.414 4.32 18.738 4.455 ;
     RECT  18.792 4.32 19.872 4.455 ;
     RECT  20.628 4.32 21.114 4.455 ;
     RECT  21.168 4.32 22.788 4.455 ;
     RECT  23.814 4.32 23.976 4.455 ;
     RECT  24.3 4.32 24.57 4.455 ;
     RECT  25.542 4.32 26.622 4.455 ;
     RECT  26.676 4.32 27.216 4.455 ;
     RECT  27.27 4.32 29.268 4.455 ;
     RECT  29.376 4.32 29.7 4.455 ;
     RECT  29.808 4.32 30.294 4.455 ;
     RECT  30.348 4.32 31.59 4.455 ;
     RECT  31.968 4.32 32.886 4.455 ;
     RECT  33.696 4.32 34.668 4.455 ;
     RECT  34.776 4.32 34.938 4.455 ;
     RECT  37.368 4.32 37.746 4.455 ;
     RECT  37.908 4.32 38.988 4.455 ;
     RECT  39.312 4.32 39.636 4.455 ;
     RECT  40.068 4.32 40.608 4.455 ;
     RECT  41.634 4.32 43.794 4.455 ;
     RECT  43.902 4.32 44.982 4.455 ;
     RECT  45.036 4.32 49.788 4.455 ;
     RECT  50.058 4.32 50.922 4.455 ;
     RECT  51.084 4.32 52.326 4.455 ;
     RECT  52.974 4.32 54.216 4.455 ;
     RECT  54.27 4.32 54.594 4.455 ;
     RECT  54.864 4.32 55.512 4.455 ;
     RECT  55.62 4.32 55.782 4.455 ;
     RECT  55.998 4.32 56.376 4.455 ;
     RECT  56.592 4.32 57.672 4.455 ;
     RECT  57.834 4.32 58.158 4.455 ;
     RECT  58.32 4.32 58.86 4.455 ;
     RECT  58.914 4.32 59.238 4.455 ;
     RECT  59.292 4.32 59.724 4.455 ;
     RECT  59.832 4.32 60.318 4.455 ;
     RECT  60.372 4.32 61.452 4.455 ;
     RECT  61.506 4.32 61.83 4.455 ;
     RECT  62.64 4.32 63.234 4.455 ;
     RECT  63.342 4.32 64.26 4.455 ;
     RECT  68.796 4.32 69.12 4.455 ;
     RECT  69.282 4.32 69.444 4.455 ;
     RECT  69.714 4.32 69.984 4.455 ;
     RECT  70.848 4.32 71.496 4.455 ;
     RECT  71.604 4.32 72.684 4.455 ;
     RECT  72.738 4.32 74.088 4.455 ;
     RECT  74.304 4.32 75.978 4.455 ;
     RECT  76.032 4.32 76.518 4.455 ;
     RECT  76.572 4.32 77.436 4.455 ;
     RECT  77.652 4.32 78.624 4.455 ;
     RECT  78.678 4.32 81.594 4.455 ;
     RECT  81.648 4.32 82.458 4.455 ;
     RECT  82.512 4.32 83.376 4.455 ;
     RECT  83.43 4.32 83.592 4.455 ;
     RECT  83.7 4.32 85.644 4.455 ;
     RECT  85.698 4.32 87.21 4.455 ;
     RECT  89.532 4.32 90.774 4.455 ;
     RECT  90.828 4.32 93.528 4.455 ;
     RECT  93.69 4.32 96.228 4.455 ;
     RECT  96.282 4.32 100.17 4.455 ;
     RECT  100.224 4.32 100.548 4.455 ;
     RECT  100.602 4.32 100.926 4.455 ;
     RECT  101.034 4.32 101.358 4.455 ;
     RECT  101.466 4.32 102.708 4.455 ;
     RECT  102.924 4.32 103.086 4.455 ;
     RECT  103.14 4.32 103.302 4.455 ;
     RECT  105.192 4.32 106.272 4.455 ;
     RECT  106.974 4.32 107.244 4.455 ;
     RECT  108.864 4.32 109.404 4.455 ;
     RECT  110.484 4.32 111.888 4.455 ;
     RECT  112.158 4.32 113.67 4.455 ;
     RECT  113.832 4.32 115.074 4.455 ;
     RECT  115.344 4.32 115.668 4.455 ;
     RECT  116.1 4.32 116.262 4.455 ;
     RECT  117.828 4.32 118.476 4.455 ;
     RECT  118.584 4.32 120.15 4.455 ;
     RECT  126.9 4.32 127.008 4.455 ;
     RECT  127.332 4.185 127.44 4.455 ;
     RECT  14.472 4.725 15.66 4.86 ;
     RECT  16.74 4.725 17.82 4.86 ;
     RECT  17.874 4.725 18.198 4.86 ;
     RECT  18.792 4.725 19.332 4.86 ;
     RECT  20.844 4.725 21.33 4.86 ;
     RECT  22.572 4.725 23.814 4.86 ;
     RECT  23.922 4.725 24.57 4.86 ;
     RECT  24.732 4.725 26.082 4.86 ;
     RECT  26.136 4.725 26.514 4.86 ;
     RECT  26.568 4.725 26.946 4.86 ;
     RECT  27.054 4.725 27.324 4.86 ;
     RECT  27.378 4.725 29.754 4.86 ;
     RECT  29.808 4.725 30.186 4.86 ;
     RECT  30.24 4.725 32.184 4.86 ;
     RECT  32.778 4.725 33.156 4.86 ;
     RECT  36.072 4.725 37.152 4.86 ;
     RECT  37.53 4.725 37.854 4.86 ;
     RECT  38.07 4.725 38.556 4.86 ;
     RECT  38.718 4.725 40.284 4.86 ;
     RECT  42.12 4.725 44.388 4.86 ;
     RECT  44.496 4.725 47.736 4.86 ;
     RECT  47.79 4.725 48.654 4.86 ;
     RECT  48.87 4.725 50.976 4.86 ;
     RECT  51.03 4.725 51.354 4.86 ;
     RECT  51.408 4.725 51.732 4.86 ;
     RECT  51.84 4.725 52.002 4.86 ;
     RECT  52.056 4.725 52.164 4.86 ;
     RECT  54.54 4.725 55.782 4.86 ;
     RECT  55.89 4.725 56.97 4.86 ;
     RECT  57.024 4.725 58.644 4.86 ;
     RECT  58.698 4.725 59.022 4.86 ;
     RECT  59.346 4.725 61.776 4.86 ;
     RECT  61.938 4.725 63.666 4.86 ;
     RECT  63.72 4.725 65.394 4.86 ;
     RECT  68.526 4.725 68.796 4.86 ;
     RECT  69.066 4.725 70.146 4.86 ;
     RECT  70.524 4.725 72.414 4.86 ;
     RECT  72.576 4.725 72.738 4.86 ;
     RECT  73.008 4.725 74.412 4.86 ;
     RECT  74.52 4.725 78.678 4.86 ;
     RECT  78.786 4.725 80.406 4.86 ;
     RECT  80.514 4.725 83.16 4.86 ;
     RECT  83.376 4.725 85.428 4.86 ;
     RECT  85.536 4.725 86.4 4.86 ;
     RECT  86.508 4.725 88.02 4.86 ;
     RECT  88.29 4.725 89.856 4.86 ;
     RECT  90.666 4.725 96.228 4.86 ;
     RECT  96.282 4.725 96.714 4.86 ;
     RECT  96.768 4.725 97.2 4.86 ;
     RECT  97.416 4.725 98.064 4.86 ;
     RECT  98.118 4.725 98.442 4.86 ;
     RECT  98.496 4.725 98.982 4.86 ;
     RECT  99.036 4.725 100.116 4.86 ;
     RECT  100.224 4.725 100.548 4.86 ;
     RECT  100.71 4.725 100.872 4.86 ;
     RECT  101.952 4.725 102.06 4.86 ;
     RECT  102.168 4.725 103.248 4.86 ;
     RECT  106.218 4.725 106.542 4.86 ;
     RECT  107.406 4.725 107.676 4.86 ;
     RECT  108.756 4.725 109.08 4.86 ;
     RECT  109.242 4.725 109.566 4.86 ;
     RECT  110.268 4.725 110.754 4.86 ;
     RECT  113.13 4.725 114.534 4.86 ;
     RECT  114.912 4.725 115.56 4.86 ;
     RECT  115.83 4.725 116.154 4.86 ;
     RECT  2.16 4.725 2.268 4.995 ;
     RECT  13.23 4.86 13.608 4.995 ;
     RECT  14.094 4.86 15.174 4.995 ;
     RECT  16.416 4.86 17.064 4.995 ;
     RECT  17.874 4.86 20.358 4.995 ;
     RECT  20.898 4.86 21.222 4.995 ;
     RECT  21.762 4.86 22.086 4.995 ;
     RECT  22.626 4.86 22.896 4.995 ;
     RECT  23.868 4.86 24.192 4.995 ;
     RECT  24.678 4.86 26.838 4.995 ;
     RECT  26.946 4.86 27.216 4.995 ;
     RECT  27.378 4.86 28.458 4.995 ;
     RECT  28.566 4.86 30.132 4.995 ;
     RECT  30.294 4.86 31.752 4.995 ;
     RECT  31.914 4.86 33.858 4.995 ;
     RECT  35.154 4.725 35.478 4.995 ;
     RECT  36.45 4.86 36.828 4.995 ;
     RECT  36.936 4.86 39.042 4.995 ;
     RECT  39.906 4.86 40.986 4.995 ;
     RECT  41.256 4.86 42.606 4.995 ;
     RECT  42.714 4.86 43.362 4.995 ;
     RECT  43.416 4.86 45.036 4.995 ;
     RECT  45.09 4.86 45.954 4.995 ;
     RECT  46.062 4.86 46.818 4.995 ;
     RECT  46.926 4.86 48.978 4.995 ;
     RECT  49.14 4.86 51.408 4.995 ;
     RECT  52.056 4.86 53.136 4.995 ;
     RECT  53.622 4.86 54 4.995 ;
     RECT  54.108 4.86 54.432 4.995 ;
     RECT  55.08 4.86 55.458 4.995 ;
     RECT  55.566 4.86 56.646 4.995 ;
     RECT  56.7 4.86 57.51 4.995 ;
     RECT  57.618 4.86 57.996 4.995 ;
     RECT  58.05 4.86 59.13 4.995 ;
     RECT  59.346 4.86 61.128 4.995 ;
     RECT  61.182 4.86 61.506 4.995 ;
     RECT  61.668 4.86 62.91 4.995 ;
     RECT  63.018 4.86 63.18 4.995 ;
     RECT  63.936 4.86 64.26 4.995 ;
     RECT  64.746 4.86 64.908 4.995 ;
     RECT  66.96 4.86 68.85 4.995 ;
     RECT  69.228 4.86 70.848 4.995 ;
     RECT  71.604 4.86 71.874 4.995 ;
     RECT  71.928 4.86 72.522 4.995 ;
     RECT  72.576 4.86 73.224 4.995 ;
     RECT  73.278 4.86 73.602 4.995 ;
     RECT  73.656 4.86 73.98 4.995 ;
     RECT  74.034 4.86 75.276 4.995 ;
     RECT  75.384 4.86 77.112 4.995 ;
     RECT  77.166 4.86 78.894 4.995 ;
     RECT  78.948 4.86 79.272 4.995 ;
     RECT  79.326 4.86 86.886 4.995 ;
     RECT  87.102 4.86 87.426 4.995 ;
     RECT  88.29 4.86 88.614 4.995 ;
     RECT  88.776 4.86 89.1 4.995 ;
     RECT  90.558 4.86 92.178 4.995 ;
     RECT  92.34 4.86 96.012 4.995 ;
     RECT  96.174 4.86 99.414 4.995 ;
     RECT  99.522 4.86 99.846 4.995 ;
     RECT  100.008 4.86 100.332 4.995 ;
     RECT  100.494 4.86 101.574 4.995 ;
     RECT  101.682 4.86 101.844 4.995 ;
     RECT  103.14 4.86 104.544 4.995 ;
     RECT  106.11 4.86 106.434 4.995 ;
     RECT  106.704 4.86 106.866 4.995 ;
     RECT  106.92 4.86 108.594 4.995 ;
     RECT  108.648 4.86 109.728 4.995 ;
     RECT  113.13 4.86 113.454 4.995 ;
     RECT  114.048 4.86 114.21 4.995 ;
     RECT  115.776 4.86 117.342 4.995 ;
     RECT  126.9 4.86 127.008 4.995 ;
     RECT  127.332 4.725 127.44 4.995 ;
     RECT  12.42 5.265 13.5 5.4 ;
     RECT  14.58 5.265 15.066 5.4 ;
     RECT  16.524 5.265 17.064 5.4 ;
     RECT  17.766 5.265 18.846 5.4 ;
     RECT  19.494 5.265 20.358 5.4 ;
     RECT  21.114 5.265 21.816 5.4 ;
     RECT  23.004 5.265 24.084 5.4 ;
     RECT  24.948 5.265 29.808 5.4 ;
     RECT  30.024 5.265 30.456 5.4 ;
     RECT  30.834 5.265 31.374 5.4 ;
     RECT  31.536 5.265 31.698 5.4 ;
     RECT  32.292 5.265 32.616 5.4 ;
     RECT  33.318 5.265 34.344 5.4 ;
     RECT  34.506 5.265 34.668 5.4 ;
     RECT  35.046 5.265 36.288 5.4 ;
     RECT  36.612 5.265 36.936 5.4 ;
     RECT  36.99 5.265 37.152 5.4 ;
     RECT  37.26 5.265 38.61 5.4 ;
     RECT  38.934 5.265 40.338 5.4 ;
     RECT  40.608 5.265 40.932 5.4 ;
     RECT  41.256 5.265 41.58 5.4 ;
     RECT  42.444 5.265 45.036 5.4 ;
     RECT  45.09 5.265 49.572 5.4 ;
     RECT  49.842 5.265 51.084 5.4 ;
     RECT  51.516 5.265 52.164 5.4 ;
     RECT  52.542 5.265 52.866 5.4 ;
     RECT  53.136 5.265 53.784 5.4 ;
     RECT  53.946 5.265 54.108 5.4 ;
     RECT  54.27 5.265 54.432 5.4 ;
     RECT  55.296 5.265 56.268 5.4 ;
     RECT  56.322 5.265 57.834 5.4 ;
     RECT  57.888 5.265 59.94 5.4 ;
     RECT  60.102 5.265 62.262 5.4 ;
     RECT  62.586 5.265 62.91 5.4 ;
     RECT  63.234 5.265 63.504 5.4 ;
     RECT  64.368 5.265 64.692 5.4 ;
     RECT  69.174 5.265 69.498 5.4 ;
     RECT  70.902 5.265 71.226 5.4 ;
     RECT  71.442 5.265 72.522 5.4 ;
     RECT  72.576 5.265 73.656 5.4 ;
     RECT  73.71 5.265 73.872 5.4 ;
     RECT  73.926 5.265 74.25 5.4 ;
     RECT  74.304 5.265 74.844 5.4 ;
     RECT  75.114 5.265 75.978 5.4 ;
     RECT  76.194 5.265 78.192 5.4 ;
     RECT  78.246 5.265 79.65 5.4 ;
     RECT  79.758 5.265 82.026 5.4 ;
     RECT  82.188 5.265 83.16 5.4 ;
     RECT  83.214 5.265 84.456 5.4 ;
     RECT  84.564 5.265 86.886 5.4 ;
     RECT  87.102 5.265 88.506 5.4 ;
     RECT  89.316 5.265 91.206 5.4 ;
     RECT  91.422 5.265 92.502 5.4 ;
     RECT  92.61 5.265 93.15 5.4 ;
     RECT  93.312 5.265 93.906 5.4 ;
     RECT  94.122 5.265 96.282 5.4 ;
     RECT  96.444 5.265 97.524 5.4 ;
     RECT  97.632 5.265 99.36 5.4 ;
     RECT  99.468 5.265 100.008 5.4 ;
     RECT  100.278 5.265 101.52 5.4 ;
     RECT  101.952 5.265 102.06 5.4 ;
     RECT  102.816 5.265 103.14 5.4 ;
     RECT  103.464 5.265 103.788 5.4 ;
     RECT  104.058 5.265 104.544 5.4 ;
     RECT  106.218 5.265 108.648 5.4 ;
     RECT  108.702 5.265 109.026 5.4 ;
     RECT  109.296 5.265 109.782 5.4 ;
     RECT  110.106 5.265 110.538 5.4 ;
     RECT  110.7 5.265 110.862 5.4 ;
     RECT  111.294 5.265 111.618 5.4 ;
     RECT  113.346 5.265 113.67 5.4 ;
     RECT  117.018 5.265 117.288 5.4 ;
     RECT  2.16 5.265 2.268 5.535 ;
     RECT  13.284 5.4 13.77 5.535 ;
     RECT  14.04 5.4 14.31 5.535 ;
     RECT  14.634 5.4 14.958 5.535 ;
     RECT  15.282 5.4 15.552 5.535 ;
     RECT  15.714 5.4 16.956 5.535 ;
     RECT  17.01 5.4 17.334 5.535 ;
     RECT  18.954 5.4 19.116 5.535 ;
     RECT  20.898 5.4 21.168 5.535 ;
     RECT  21.6 5.4 21.924 5.535 ;
     RECT  23.598 5.4 24.462 5.535 ;
     RECT  25.866 5.4 27.216 5.535 ;
     RECT  27.27 5.4 28.08 5.535 ;
     RECT  28.134 5.4 28.566 5.535 ;
     RECT  28.62 5.4 29.484 5.535 ;
     RECT  29.538 5.4 31.59 5.535 ;
     RECT  31.752 5.4 35.532 5.535 ;
     RECT  36.234 5.4 37.746 5.535 ;
     RECT  37.854 5.4 38.556 5.535 ;
     RECT  38.718 5.4 39.258 5.535 ;
     RECT  39.96 5.4 40.122 5.535 ;
     RECT  40.23 5.4 41.04 5.535 ;
     RECT  41.526 5.4 42.768 5.535 ;
     RECT  43.092 5.4 43.902 5.535 ;
     RECT  44.01 5.4 44.442 5.535 ;
     RECT  44.712 5.4 45.63 5.535 ;
     RECT  45.792 5.4 46.116 5.535 ;
     RECT  46.17 5.4 49.896 5.535 ;
     RECT  49.95 5.4 50.976 5.535 ;
     RECT  52.542 5.4 52.92 5.535 ;
     RECT  53.082 5.4 54.324 5.535 ;
     RECT  54.54 5.4 55.782 5.535 ;
     RECT  56.484 5.4 57.726 5.535 ;
     RECT  57.888 5.4 59.076 5.535 ;
     RECT  59.13 5.4 60.426 5.535 ;
     RECT  60.48 5.4 61.236 5.535 ;
     RECT  61.506 5.4 61.992 5.535 ;
     RECT  62.316 5.4 62.64 5.535 ;
     RECT  62.856 5.4 63.18 5.535 ;
     RECT  64.044 5.4 64.314 5.535 ;
     RECT  64.368 5.4 65.448 5.535 ;
     RECT  66.798 5.4 67.878 5.535 ;
     RECT  68.418 5.4 68.742 5.535 ;
     RECT  69.228 5.4 69.498 5.535 ;
     RECT  70.74 5.4 71.226 5.535 ;
     RECT  71.28 5.4 73.98 5.535 ;
     RECT  74.034 5.4 75.654 5.535 ;
     RECT  75.708 5.4 76.572 5.535 ;
     RECT  76.626 5.4 79.65 5.535 ;
     RECT  79.704 5.4 80.622 5.535 ;
     RECT  80.676 5.4 81.162 5.535 ;
     RECT  81.324 5.4 82.188 5.535 ;
     RECT  82.404 5.4 83.16 5.535 ;
     RECT  83.376 5.4 84.618 5.535 ;
     RECT  84.834 5.4 87.264 5.535 ;
     RECT  87.966 5.4 89.694 5.535 ;
     RECT  89.802 5.4 90.126 5.535 ;
     RECT  90.774 5.4 91.098 5.535 ;
     RECT  91.314 5.4 93.582 5.535 ;
     RECT  93.636 5.4 97.578 5.535 ;
     RECT  97.632 5.4 99.792 5.535 ;
     RECT  99.954 5.4 100.116 5.535 ;
     RECT  100.71 5.4 101.79 5.535 ;
     RECT  102.762 5.4 104.004 5.535 ;
     RECT  106.542 5.4 107.19 5.535 ;
     RECT  108.054 5.4 108.54 5.535 ;
     RECT  110.106 5.4 112.266 5.535 ;
     RECT  112.32 5.4 112.644 5.535 ;
     RECT  112.752 5.4 113.4 5.535 ;
     RECT  113.886 5.4 114.048 5.535 ;
     RECT  114.75 5.4 115.074 5.535 ;
     RECT  115.344 5.4 115.668 5.535 ;
     RECT  126.9 5.4 127.008 5.535 ;
     RECT  127.332 5.265 127.44 5.535 ;
     RECT  12.312 5.805 13.5 5.94 ;
     RECT  14.688 5.805 15.39 5.94 ;
     RECT  17.712 5.805 17.982 5.94 ;
     RECT  19.818 5.805 20.088 5.94 ;
     RECT  20.736 5.805 21.978 5.94 ;
     RECT  22.734 5.805 23.436 5.94 ;
     RECT  23.544 5.805 23.706 5.94 ;
     RECT  26.028 5.805 26.352 5.94 ;
     RECT  26.676 5.805 28.296 5.94 ;
     RECT  28.404 5.805 30.348 5.94 ;
     RECT  30.672 5.805 31.212 5.94 ;
     RECT  31.536 5.805 31.698 5.94 ;
     RECT  31.968 5.805 32.4 5.94 ;
     RECT  32.886 5.805 33.21 5.94 ;
     RECT  33.264 5.805 33.588 5.94 ;
     RECT  35.046 5.805 35.532 5.94 ;
     RECT  36.396 5.805 37.476 5.94 ;
     RECT  37.53 5.805 38.448 5.94 ;
     RECT  38.502 5.805 40.122 5.94 ;
     RECT  41.148 5.805 42.228 5.94 ;
     RECT  42.876 5.805 46.116 5.94 ;
     RECT  46.224 5.805 47.034 5.94 ;
     RECT  47.196 5.805 48.6 5.94 ;
     RECT  48.708 5.805 49.842 5.94 ;
     RECT  50.004 5.805 50.544 5.94 ;
     RECT  50.652 5.805 52.164 5.94 ;
     RECT  52.218 5.805 52.542 5.94 ;
     RECT  52.866 5.805 53.19 5.94 ;
     RECT  53.46 5.805 53.784 5.94 ;
     RECT  53.838 5.805 54.918 5.94 ;
     RECT  55.728 5.805 56.538 5.94 ;
     RECT  56.646 5.805 57.078 5.94 ;
     RECT  57.24 5.805 57.564 5.94 ;
     RECT  58.428 5.805 59.292 5.94 ;
     RECT  59.4 5.805 60.264 5.94 ;
     RECT  60.534 5.805 61.29 5.94 ;
     RECT  61.56 5.805 63.72 5.94 ;
     RECT  64.044 5.805 64.692 5.94 ;
     RECT  65.07 5.805 65.232 5.94 ;
     RECT  67.446 5.805 67.608 5.94 ;
     RECT  67.77 5.805 68.094 5.94 ;
     RECT  68.202 5.805 70.848 5.94 ;
     RECT  71.334 5.805 71.982 5.94 ;
     RECT  72.036 5.805 74.52 5.94 ;
     RECT  74.574 5.805 76.572 5.94 ;
     RECT  76.68 5.805 77.598 5.94 ;
     RECT  77.652 5.805 80.244 5.94 ;
     RECT  80.352 5.805 81.216 5.94 ;
     RECT  81.324 5.805 83.322 5.94 ;
     RECT  83.484 5.805 84.024 5.94 ;
     RECT  84.078 5.805 85.482 5.94 ;
     RECT  85.536 5.805 85.968 5.94 ;
     RECT  86.184 5.805 86.724 5.94 ;
     RECT  86.778 5.805 87.426 5.94 ;
     RECT  87.642 5.805 89.046 5.94 ;
     RECT  90.504 5.805 92.772 5.94 ;
     RECT  92.934 5.805 94.014 5.94 ;
     RECT  94.122 5.805 94.662 5.94 ;
     RECT  94.716 5.805 94.986 5.94 ;
     RECT  95.04 5.805 98.928 5.94 ;
     RECT  99.036 5.805 99.36 5.94 ;
     RECT  99.414 5.805 100.17 5.94 ;
     RECT  100.278 5.805 100.602 5.94 ;
     RECT  100.71 5.805 100.872 5.94 ;
     RECT  101.682 5.805 102.06 5.94 ;
     RECT  102.654 5.805 102.924 5.94 ;
     RECT  105.192 5.805 105.462 5.94 ;
     RECT  106.326 5.805 107.406 5.94 ;
     RECT  108.54 5.805 109.62 5.94 ;
     RECT  109.944 5.805 110.592 5.94 ;
     RECT  111.24 5.805 111.564 5.94 ;
     RECT  111.618 5.805 111.78 5.94 ;
     RECT  112.266 5.805 112.59 5.94 ;
     RECT  112.86 5.805 115.074 5.94 ;
     RECT  115.236 5.805 115.83 5.94 ;
     RECT  2.16 5.805 2.268 6.075 ;
     RECT  13.932 5.94 15.174 6.075 ;
     RECT  16.146 5.94 16.416 6.075 ;
     RECT  19.494 5.94 21.924 6.075 ;
     RECT  22.572 5.94 23.652 6.075 ;
     RECT  23.976 5.94 24.624 6.075 ;
     RECT  25.11 5.94 25.434 6.075 ;
     RECT  26.028 5.94 29.106 6.075 ;
     RECT  29.16 5.94 29.484 6.075 ;
     RECT  29.592 5.94 30.024 6.075 ;
     RECT  30.24 5.94 31.428 6.075 ;
     RECT  31.59 5.94 32.022 6.075 ;
     RECT  32.4 5.94 33.102 6.075 ;
     RECT  33.264 5.94 33.426 6.075 ;
     RECT  33.534 5.94 34.614 6.075 ;
     RECT  36.342 5.94 36.72 6.075 ;
     RECT  36.774 5.94 37.206 6.075 ;
     RECT  37.26 5.94 38.07 6.075 ;
     RECT  38.232 5.94 39.852 6.075 ;
     RECT  39.96 5.94 41.04 6.075 ;
     RECT  41.202 5.94 41.58 6.075 ;
     RECT  41.634 5.94 41.958 6.075 ;
     RECT  42.12 5.94 42.282 6.075 ;
     RECT  42.444 5.94 42.768 6.075 ;
     RECT  42.822 5.94 43.686 6.075 ;
     RECT  43.74 5.94 43.902 6.075 ;
     RECT  43.956 5.94 44.28 6.075 ;
     RECT  44.334 5.94 44.874 6.075 ;
     RECT  44.928 5.94 46.008 6.075 ;
     RECT  46.062 5.94 46.926 6.075 ;
     RECT  46.98 5.94 47.304 6.075 ;
     RECT  47.412 5.94 47.952 6.075 ;
     RECT  48.006 5.94 48.87 6.075 ;
     RECT  49.032 5.94 50.004 6.075 ;
     RECT  50.112 5.94 51.408 6.075 ;
     RECT  51.516 5.94 51.948 6.075 ;
     RECT  52.272 5.94 52.596 6.075 ;
     RECT  52.65 5.94 54.054 6.075 ;
     RECT  54.27 5.94 54.648 6.075 ;
     RECT  54.918 5.94 57.51 6.075 ;
     RECT  57.726 5.805 58.266 6.075 ;
     RECT  58.32 5.94 61.992 6.075 ;
     RECT  62.1 5.94 62.262 6.075 ;
     RECT  62.748 5.94 63.072 6.075 ;
     RECT  63.612 5.94 63.774 6.075 ;
     RECT  63.828 5.94 64.908 6.075 ;
     RECT  66.744 5.94 68.148 6.075 ;
     RECT  69.822 5.94 70.146 6.075 ;
     RECT  70.254 5.94 71.874 6.075 ;
     RECT  71.982 5.94 72.306 6.075 ;
     RECT  72.36 5.94 72.522 6.075 ;
     RECT  72.576 5.94 74.034 6.075 ;
     RECT  74.088 5.94 74.52 6.075 ;
     RECT  74.682 5.94 75.222 6.075 ;
     RECT  75.384 5.94 75.924 6.075 ;
     RECT  75.978 5.94 76.95 6.075 ;
     RECT  77.004 5.94 80.406 6.075 ;
     RECT  80.514 5.94 81.702 6.075 ;
     RECT  82.08 5.94 83.484 6.075 ;
     RECT  83.538 5.94 84.402 6.075 ;
     RECT  84.456 5.94 84.834 6.075 ;
     RECT  84.996 5.94 85.32 6.075 ;
     RECT  85.374 5.94 86.13 6.075 ;
     RECT  86.292 5.94 87.156 6.075 ;
     RECT  87.48 5.94 87.642 6.075 ;
     RECT  87.858 5.94 88.182 6.075 ;
     RECT  88.614 5.94 89.1 6.075 ;
     RECT  89.262 5.94 90.504 6.075 ;
     RECT  90.72 5.94 91.044 6.075 ;
     RECT  91.098 5.94 91.854 6.075 ;
     RECT  92.124 5.94 93.582 6.075 ;
     RECT  93.636 5.94 95.796 6.075 ;
     RECT  95.904 5.94 97.47 6.075 ;
     RECT  97.524 5.94 99.576 6.075 ;
     RECT  99.63 5.94 99.792 6.075 ;
     RECT  99.846 5.94 100.602 6.075 ;
     RECT  100.71 5.94 101.358 6.075 ;
     RECT  101.52 5.94 101.952 6.075 ;
     RECT  102.33 5.94 102.654 6.075 ;
     RECT  104.814 5.94 105.138 6.075 ;
     RECT  105.894 5.94 106.218 6.075 ;
     RECT  106.38 5.94 108.81 6.075 ;
     RECT  109.08 5.94 109.242 6.075 ;
     RECT  109.782 5.94 110.052 6.075 ;
     RECT  110.97 5.94 111.294 6.075 ;
     RECT  112.32 5.94 114.642 6.075 ;
     RECT  114.804 5.94 116.208 6.075 ;
     RECT  126.9 5.94 127.008 6.075 ;
     RECT  127.332 5.805 127.44 6.075 ;
     RECT  12.366 6.345 13.77 6.48 ;
     RECT  14.202 6.345 14.796 6.48 ;
     RECT  15.12 6.345 15.498 6.48 ;
     RECT  15.93 6.345 17.01 6.48 ;
     RECT  17.226 6.345 17.604 6.48 ;
     RECT  17.928 6.345 18.198 6.48 ;
     RECT  19.116 6.345 19.602 6.48 ;
     RECT  19.926 6.345 20.25 6.48 ;
     RECT  20.358 6.345 20.52 6.48 ;
     RECT  21.276 6.345 22.14 6.48 ;
     RECT  23.166 6.345 24.408 6.48 ;
     RECT  24.516 6.345 25.596 6.48 ;
     RECT  26.46 6.345 27.54 6.48 ;
     RECT  27.594 6.345 28.998 6.48 ;
     RECT  29.268 6.345 29.646 6.48 ;
     RECT  29.754 6.345 30.078 6.48 ;
     RECT  30.186 6.345 30.51 6.48 ;
     RECT  30.618 6.345 31.428 6.48 ;
     RECT  31.536 6.345 32.076 6.48 ;
     RECT  32.184 6.345 33.858 6.48 ;
     RECT  35.91 6.345 36.99 6.48 ;
     RECT  37.314 6.345 38.718 6.48 ;
     RECT  38.826 6.345 39.582 6.48 ;
     RECT  39.636 6.345 40.824 6.48 ;
     RECT  40.932 6.345 41.094 6.48 ;
     RECT  42.498 6.345 42.822 6.48 ;
     RECT  42.876 6.345 45.576 6.48 ;
     RECT  45.738 6.345 46.602 6.48 ;
     RECT  46.71 6.345 47.25 6.48 ;
     RECT  47.304 6.345 49.464 6.48 ;
     RECT  49.518 6.345 50.382 6.48 ;
     RECT  50.436 6.345 50.868 6.48 ;
     RECT  50.922 6.345 51.354 6.48 ;
     RECT  51.408 6.345 51.84 6.48 ;
     RECT  52.056 6.345 52.164 6.48 ;
     RECT  52.272 6.345 54.162 6.48 ;
     RECT  54.432 6.345 54.756 6.48 ;
     RECT  54.81 6.345 55.35 6.48 ;
     RECT  55.404 6.345 55.728 6.48 ;
     RECT  55.782 6.345 55.944 6.48 ;
     RECT  55.998 6.345 56.862 6.48 ;
     RECT  56.916 6.345 57.348 6.48 ;
     RECT  57.402 6.345 58.158 6.48 ;
     RECT  58.212 6.345 59.292 6.48 ;
     RECT  59.346 6.345 60.426 6.48 ;
     RECT  60.696 6.345 61.884 6.48 ;
     RECT  62.37 6.345 62.694 6.48 ;
     RECT  64.044 6.345 64.368 6.48 ;
     RECT  64.422 6.345 64.908 6.48 ;
     RECT  66.798 6.345 68.418 6.48 ;
     RECT  69.174 6.345 70.308 6.48 ;
     RECT  71.01 6.345 74.898 6.48 ;
     RECT  75.114 6.345 75.546 6.48 ;
     RECT  75.6 6.345 77.598 6.48 ;
     RECT  77.706 6.345 79.326 6.48 ;
     RECT  79.434 6.345 80.298 6.48 ;
     RECT  80.352 6.345 81.27 6.48 ;
     RECT  81.432 6.345 84.672 6.48 ;
     RECT  84.726 6.345 85.482 6.48 ;
     RECT  85.536 6.345 85.86 6.48 ;
     RECT  85.968 6.345 86.508 6.48 ;
     RECT  86.562 6.345 88.182 6.48 ;
     RECT  88.452 6.345 90.018 6.48 ;
     RECT  90.504 6.345 90.828 6.48 ;
     RECT  90.936 6.345 91.098 6.48 ;
     RECT  91.206 6.345 93.474 6.48 ;
     RECT  93.744 6.345 94.284 6.48 ;
     RECT  94.338 6.345 94.662 6.48 ;
     RECT  94.716 6.345 95.904 6.48 ;
     RECT  95.958 6.345 96.822 6.48 ;
     RECT  96.93 6.345 97.794 6.48 ;
     RECT  97.848 6.345 98.712 6.48 ;
     RECT  98.766 6.345 99.954 6.48 ;
     RECT  100.224 6.345 101.466 6.48 ;
     RECT  101.52 6.345 101.79 6.48 ;
     RECT  101.952 6.345 102.06 6.48 ;
     RECT  102.222 6.345 102.546 6.48 ;
     RECT  102.6 6.345 103.68 6.48 ;
     RECT  104.652 6.345 106.218 6.48 ;
     RECT  106.92 6.345 107.244 6.48 ;
     RECT  107.514 6.345 107.784 6.48 ;
     RECT  108.324 6.345 108.972 6.48 ;
     RECT  110.808 6.345 111.132 6.48 ;
     RECT  111.51 6.345 111.834 6.48 ;
     RECT  114.534 6.345 114.858 6.48 ;
     RECT  115.02 6.345 116.1 6.48 ;
     RECT  2.16 6.345 2.268 6.615 ;
     RECT  2.376 6.48 2.646 6.615 ;
     RECT  13.284 6.48 13.446 6.615 ;
     RECT  13.5 6.48 14.202 6.615 ;
     RECT  15.12 6.48 15.822 6.615 ;
     RECT  15.984 6.48 17.55 6.615 ;
     RECT  17.82 6.48 18.144 6.615 ;
     RECT  18.306 6.48 19.386 6.615 ;
     RECT  19.44 6.48 20.52 6.615 ;
     RECT  20.628 6.48 21.87 6.615 ;
     RECT  23.868 6.48 24.192 6.615 ;
     RECT  24.408 6.48 24.732 6.615 ;
     RECT  25.164 6.48 25.65 6.615 ;
     RECT  25.866 6.48 26.298 6.615 ;
     RECT  26.676 6.48 27 6.615 ;
     RECT  27.108 6.48 27.216 6.615 ;
     RECT  27.324 6.48 28.026 6.615 ;
     RECT  28.08 6.48 28.674 6.615 ;
     RECT  28.728 6.48 30.024 6.615 ;
     RECT  30.24 6.48 31.752 6.615 ;
     RECT  31.968 6.48 32.508 6.615 ;
     RECT  32.94 6.48 33.264 6.615 ;
     RECT  34.02 6.48 34.398 6.615 ;
     RECT  35.262 6.48 35.964 6.615 ;
     RECT  36.234 6.48 36.612 6.615 ;
     RECT  36.828 6.48 38.016 6.615 ;
     RECT  38.286 6.48 39.582 6.615 ;
     RECT  41.58 6.48 44.928 6.615 ;
     RECT  45.09 6.48 46.656 6.615 ;
     RECT  46.818 6.48 47.358 6.615 ;
     RECT  47.466 6.48 49.302 6.615 ;
     RECT  49.464 6.48 50.004 6.615 ;
     RECT  50.112 6.48 50.544 6.615 ;
     RECT  50.868 6.48 51.948 6.615 ;
     RECT  52.002 6.48 52.164 6.615 ;
     RECT  53.352 6.48 54.594 6.615 ;
     RECT  55.296 6.48 55.674 6.615 ;
     RECT  55.836 6.48 56.268 6.615 ;
     RECT  56.484 6.48 57.024 6.615 ;
     RECT  57.24 6.48 57.672 6.615 ;
     RECT  57.888 6.48 58.698 6.615 ;
     RECT  58.752 6.48 59.616 6.615 ;
     RECT  59.724 6.48 63.396 6.615 ;
     RECT  63.936 6.48 65.556 6.615 ;
     RECT  68.31 6.48 69.552 6.615 ;
     RECT  69.768 6.48 71.388 6.615 ;
     RECT  71.442 6.48 71.766 6.615 ;
     RECT  71.82 6.48 72.252 6.615 ;
     RECT  72.306 6.48 72.63 6.615 ;
     RECT  72.684 6.48 73.116 6.615 ;
     RECT  73.17 6.48 74.034 6.615 ;
     RECT  74.142 6.48 74.304 6.615 ;
     RECT  74.412 6.48 76.896 6.615 ;
     RECT  77.004 6.48 77.652 6.615 ;
     RECT  77.76 6.48 78.462 6.615 ;
     RECT  78.732 6.48 82.458 6.615 ;
     RECT  82.512 6.48 84.51 6.615 ;
     RECT  84.618 6.48 84.996 6.615 ;
     RECT  85.212 6.48 85.644 6.615 ;
     RECT  85.698 6.48 86.13 6.615 ;
     RECT  86.184 6.48 87.048 6.615 ;
     RECT  87.912 6.48 88.56 6.615 ;
     RECT  90.45 6.48 90.882 6.615 ;
     RECT  91.098 6.48 93.042 6.615 ;
     RECT  93.204 6.48 93.636 6.615 ;
     RECT  93.852 6.48 96.336 6.615 ;
     RECT  96.39 6.48 96.984 6.615 ;
     RECT  97.2 6.48 98.928 6.615 ;
     RECT  98.982 6.48 100.062 6.615 ;
     RECT  100.764 6.48 102.114 6.615 ;
     RECT  102.33 6.48 104.058 6.615 ;
     RECT  104.436 6.48 104.76 6.615 ;
     RECT  105.894 6.48 107.136 6.615 ;
     RECT  107.784 6.48 107.946 6.615 ;
     RECT  110.916 6.48 112.158 6.615 ;
     RECT  112.266 6.48 112.428 6.615 ;
     RECT  112.698 6.48 113.022 6.615 ;
     RECT  113.4 6.48 113.67 6.615 ;
     RECT  114.372 6.48 115.938 6.615 ;
     RECT  117.558 6.48 118.746 6.615 ;
     RECT  126.9 6.48 127.008 6.615 ;
     RECT  127.332 6.345 127.44 6.615 ;
     RECT  12.852 6.885 13.122 7.02 ;
     RECT  13.77 6.885 14.094 7.02 ;
     RECT  14.202 6.885 16.524 7.02 ;
     RECT  16.686 6.885 17.766 7.02 ;
     RECT  17.874 6.885 18.198 7.02 ;
     RECT  18.576 6.885 19.386 7.02 ;
     RECT  22.788 6.885 24.03 7.02 ;
     RECT  25.542 6.885 26.73 7.02 ;
     RECT  26.838 6.885 27.27 7.02 ;
     RECT  27.324 6.885 27.81 7.02 ;
     RECT  27.864 6.885 28.836 7.02 ;
     RECT  28.944 6.885 29.268 7.02 ;
     RECT  29.484 6.885 31.428 7.02 ;
     RECT  31.59 6.885 32.022 7.02 ;
     RECT  32.616 6.885 33.102 7.02 ;
     RECT  33.264 6.885 33.696 7.02 ;
     RECT  34.02 6.885 34.344 7.02 ;
     RECT  34.452 6.885 35.694 7.02 ;
     RECT  36.396 6.885 37.206 7.02 ;
     RECT  37.26 6.885 37.854 7.02 ;
     RECT  37.908 6.885 38.448 7.02 ;
     RECT  38.556 6.885 38.934 7.02 ;
     RECT  38.988 6.885 39.366 7.02 ;
     RECT  40.068 6.885 40.5 7.02 ;
     RECT  40.986 6.885 42.066 7.02 ;
     RECT  42.12 6.885 42.552 7.02 ;
     RECT  42.768 6.885 43.848 7.02 ;
     RECT  43.956 6.885 44.82 7.02 ;
     RECT  44.874 6.885 48.384 7.02 ;
     RECT  48.762 6.885 50.814 7.02 ;
     RECT  50.976 6.885 51.408 7.02 ;
     RECT  52.056 6.885 52.164 7.02 ;
     RECT  52.704 6.885 53.136 7.02 ;
     RECT  54.27 6.885 54.648 7.02 ;
     RECT  55.296 6.885 57.294 7.02 ;
     RECT  57.564 6.885 58.104 7.02 ;
     RECT  58.158 6.885 58.86 7.02 ;
     RECT  58.914 6.885 59.346 7.02 ;
     RECT  59.4 6.885 59.562 7.02 ;
     RECT  59.616 6.885 60.966 7.02 ;
     RECT  61.02 6.885 62.424 7.02 ;
     RECT  63.234 6.885 63.936 7.02 ;
     RECT  64.098 6.885 64.422 7.02 ;
     RECT  64.476 6.885 64.962 7.02 ;
     RECT  69.174 6.885 69.444 7.02 ;
     RECT  70.416 6.885 71.064 7.02 ;
     RECT  71.118 6.885 71.28 7.02 ;
     RECT  71.604 6.885 72.414 7.02 ;
     RECT  72.684 6.885 73.386 7.02 ;
     RECT  73.44 6.885 80.73 7.02 ;
     RECT  80.784 6.885 83.106 7.02 ;
     RECT  83.16 6.885 83.862 7.02 ;
     RECT  83.97 6.885 84.834 7.02 ;
     RECT  84.996 6.885 85.698 7.02 ;
     RECT  85.914 6.885 86.076 7.02 ;
     RECT  86.13 6.885 87.102 7.02 ;
     RECT  87.264 6.885 87.804 7.02 ;
     RECT  87.966 6.885 88.776 7.02 ;
     RECT  89.37 6.885 89.694 7.02 ;
     RECT  89.964 6.885 90.288 7.02 ;
     RECT  90.936 6.885 92.34 7.02 ;
     RECT  92.448 6.885 94.824 7.02 ;
     RECT  94.932 6.885 95.472 7.02 ;
     RECT  95.526 6.885 96.606 7.02 ;
     RECT  96.66 6.885 97.092 7.02 ;
     RECT  97.308 6.885 98.604 7.02 ;
     RECT  98.82 6.885 99.252 7.02 ;
     RECT  100.332 6.885 100.764 7.02 ;
     RECT  101.25 6.885 101.682 7.02 ;
     RECT  101.952 6.885 102.06 7.02 ;
     RECT  102.114 6.885 102.438 7.02 ;
     RECT  102.654 6.885 102.978 7.02 ;
     RECT  103.194 6.885 103.356 7.02 ;
     RECT  103.518 6.885 103.68 7.02 ;
     RECT  106.704 6.885 106.974 7.02 ;
     RECT  107.298 6.885 107.622 7.02 ;
     RECT  111.402 6.885 113.13 7.02 ;
     RECT  113.4 6.885 113.724 7.02 ;
     RECT  119.88 6.885 120.96 7.02 ;
     RECT  121.716 6.885 122.04 7.02 ;
     RECT  122.418 6.885 123.822 7.02 ;
     RECT  2.16 6.885 2.268 7.155 ;
     RECT  13.338 7.02 13.662 7.155 ;
     RECT  13.932 7.02 15.174 7.155 ;
     RECT  15.498 7.02 15.822 7.155 ;
     RECT  16.47 7.02 16.632 7.155 ;
     RECT  17.388 7.02 17.874 7.155 ;
     RECT  19.116 7.02 20.196 7.155 ;
     RECT  20.844 7.02 21.168 7.155 ;
     RECT  22.356 7.02 23.976 7.155 ;
     RECT  25.272 7.02 26.352 7.155 ;
     RECT  27.108 7.02 30.348 7.155 ;
     RECT  30.564 7.02 31.428 7.155 ;
     RECT  31.914 7.02 32.886 7.155 ;
     RECT  33.048 7.02 33.426 7.155 ;
     RECT  33.642 7.02 34.884 7.155 ;
     RECT  35.208 7.02 35.586 7.155 ;
     RECT  35.964 7.02 36.774 7.155 ;
     RECT  36.936 7.02 37.746 7.155 ;
     RECT  37.8 7.02 38.664 7.155 ;
     RECT  38.718 7.02 39.042 7.155 ;
     RECT  39.096 7.02 40.014 7.155 ;
     RECT  40.392 7.02 41.04 7.155 ;
     RECT  41.202 7.02 41.85 7.155 ;
     RECT  41.958 7.02 42.12 7.155 ;
     RECT  42.606 7.02 43.254 7.155 ;
     RECT  43.362 7.02 43.956 7.155 ;
     RECT  44.064 7.02 44.82 7.155 ;
     RECT  44.874 7.02 45.252 7.155 ;
     RECT  45.36 7.02 45.792 7.155 ;
     RECT  45.846 7.02 46.224 7.155 ;
     RECT  46.602 7.02 47.142 7.155 ;
     RECT  47.196 7.02 47.52 7.155 ;
     RECT  47.682 7.02 48.114 7.155 ;
     RECT  48.168 7.02 48.492 7.155 ;
     RECT  48.546 7.02 49.41 7.155 ;
     RECT  49.464 7.02 50.652 7.155 ;
     RECT  50.814 7.02 51.192 7.155 ;
     RECT  51.246 7.02 51.624 7.155 ;
     RECT  51.678 7.02 52.002 7.155 ;
     RECT  52.11 7.02 52.488 7.155 ;
     RECT  53.838 7.02 54.162 7.155 ;
     RECT  54.486 7.02 55.35 7.155 ;
     RECT  55.404 7.02 56.268 7.155 ;
     RECT  56.322 7.02 56.7 7.155 ;
     RECT  56.754 7.02 57.078 7.155 ;
     RECT  57.132 7.02 58.266 7.155 ;
     RECT  58.32 7.02 59.778 7.155 ;
     RECT  59.832 7.02 60.21 7.155 ;
     RECT  60.264 7.02 60.642 7.155 ;
     RECT  60.696 7.02 60.858 7.155 ;
     RECT  60.912 7.02 61.992 7.155 ;
     RECT  62.046 7.02 63.126 7.155 ;
     RECT  63.18 7.02 63.504 7.155 ;
     RECT  63.828 7.02 64.908 7.155 ;
     RECT  68.58 6.885 68.904 7.155 ;
     RECT  69.498 7.02 69.984 7.155 ;
     RECT  70.2 7.02 71.712 7.155 ;
     RECT  71.766 7.02 72.846 7.155 ;
     RECT  72.9 7.02 75.978 7.155 ;
     RECT  76.032 7.02 78.192 7.155 ;
     RECT  78.246 7.02 79.65 7.155 ;
     RECT  79.704 7.02 82.998 7.155 ;
     RECT  83.052 7.02 84.402 7.155 ;
     RECT  84.51 7.02 86.562 7.155 ;
     RECT  86.67 7.02 86.994 7.155 ;
     RECT  87.048 7.02 88.128 7.155 ;
     RECT  88.182 7.02 89.262 7.155 ;
     RECT  89.37 7.02 91.26 7.155 ;
     RECT  91.476 7.02 92.124 7.155 ;
     RECT  92.34 7.02 93.312 7.155 ;
     RECT  93.42 7.02 94.392 7.155 ;
     RECT  94.608 7.02 95.364 7.155 ;
     RECT  95.688 7.02 97.146 7.155 ;
     RECT  97.2 7.02 98.01 7.155 ;
     RECT  98.064 7.02 98.712 7.155 ;
     RECT  98.928 7.02 99.306 7.155 ;
     RECT  99.36 6.885 99.792 7.155 ;
     RECT  100.17 7.02 100.98 7.155 ;
     RECT  101.196 7.02 101.628 7.155 ;
     RECT  101.736 7.02 102.06 7.155 ;
     RECT  102.276 7.02 102.6 7.155 ;
     RECT  107.19 7.02 108.432 7.155 ;
     RECT  108.972 7.02 110.052 7.155 ;
     RECT  112.59 7.02 114.156 7.155 ;
     RECT  119.718 7.02 120.366 7.155 ;
     RECT  120.852 7.02 121.014 7.155 ;
     RECT  122.31 7.02 122.796 7.155 ;
     RECT  126.9 7.02 127.008 7.155 ;
     RECT  127.332 6.885 127.44 7.155 ;
     RECT  12.69 7.425 13.014 7.56 ;
     RECT  13.122 7.425 13.446 7.56 ;
     RECT  13.716 7.425 15.174 7.56 ;
     RECT  15.66 7.425 17.712 7.56 ;
     RECT  17.766 7.425 17.928 7.56 ;
     RECT  18.954 7.425 19.278 7.56 ;
     RECT  19.332 7.425 21.114 7.56 ;
     RECT  21.546 7.425 23.706 7.56 ;
     RECT  23.976 7.425 24.3 7.56 ;
     RECT  24.462 7.425 24.786 7.56 ;
     RECT  25.704 7.425 26.028 7.56 ;
     RECT  26.19 7.425 26.352 7.56 ;
     RECT  26.568 7.425 28.836 7.56 ;
     RECT  28.89 7.425 29.7 7.56 ;
     RECT  29.754 7.425 30.294 7.56 ;
     RECT  30.402 7.425 30.834 7.56 ;
     RECT  31.104 7.425 31.428 7.56 ;
     RECT  31.482 7.425 31.914 7.56 ;
     RECT  32.184 7.425 33.264 7.56 ;
     RECT  33.318 7.425 33.642 7.56 ;
     RECT  34.776 7.425 36.018 7.56 ;
     RECT  36.126 7.425 37.638 7.56 ;
     RECT  37.692 7.425 38.124 7.56 ;
     RECT  38.232 7.425 38.556 7.56 ;
     RECT  38.664 7.425 38.988 7.56 ;
     RECT  39.15 7.425 40.014 7.56 ;
     RECT  40.23 7.425 41.472 7.56 ;
     RECT  41.958 7.425 43.902 7.56 ;
     RECT  44.01 7.425 44.874 7.56 ;
     RECT  45.09 7.425 47.682 7.56 ;
     RECT  47.79 7.425 48.222 7.56 ;
     RECT  48.276 7.425 48.708 7.56 ;
     RECT  48.762 7.425 49.086 7.56 ;
     RECT  49.194 7.425 50.058 7.56 ;
     RECT  50.112 7.425 50.436 7.56 ;
     RECT  50.49 7.425 51.03 7.56 ;
     RECT  51.084 7.425 51.462 7.56 ;
     RECT  51.516 7.425 52.164 7.56 ;
     RECT  52.218 7.425 53.838 7.56 ;
     RECT  54.378 7.425 55.62 7.56 ;
     RECT  55.728 7.425 58.32 7.56 ;
     RECT  58.428 7.425 59.346 7.56 ;
     RECT  59.508 7.425 61.02 7.56 ;
     RECT  61.074 7.425 61.506 7.56 ;
     RECT  61.56 7.425 62.424 7.56 ;
     RECT  62.478 7.425 64.044 7.56 ;
     RECT  64.152 7.425 64.638 7.56 ;
     RECT  68.31 7.425 69.39 7.56 ;
     RECT  69.498 7.425 69.822 7.56 ;
     RECT  70.74 7.425 71.172 7.56 ;
     RECT  71.604 7.425 72.036 7.56 ;
     RECT  72.09 7.425 75.168 7.56 ;
     RECT  75.276 7.425 75.708 7.56 ;
     RECT  75.816 7.425 76.356 7.56 ;
     RECT  76.41 7.425 77.814 7.56 ;
     RECT  77.922 7.425 81.432 7.56 ;
     RECT  81.486 7.425 82.566 7.56 ;
     RECT  82.62 7.425 83.052 7.56 ;
     RECT  83.16 7.425 84.024 7.56 ;
     RECT  84.078 7.425 84.618 7.56 ;
     RECT  84.726 7.425 86.4 7.56 ;
     RECT  86.454 7.425 86.886 7.56 ;
     RECT  87.21 7.425 88.074 7.56 ;
     RECT  88.452 7.425 88.614 7.56 ;
     RECT  89.37 7.425 90.45 7.56 ;
     RECT  90.828 7.425 91.152 7.56 ;
     RECT  91.476 7.425 93.096 7.56 ;
     RECT  93.204 7.425 96.768 7.56 ;
     RECT  96.822 7.425 97.74 7.56 ;
     RECT  97.848 7.425 98.172 7.56 ;
     RECT  98.442 7.425 102.384 7.56 ;
     RECT  102.87 7.425 104.76 7.56 ;
     RECT  105.3 7.425 105.624 7.56 ;
     RECT  106.704 7.425 108.108 7.56 ;
     RECT  108.324 7.425 108.648 7.56 ;
     RECT  109.242 7.425 110.052 7.56 ;
     RECT  110.646 7.425 110.97 7.56 ;
     RECT  112.806 7.425 114.372 7.56 ;
     RECT  115.83 7.425 116.478 7.56 ;
     RECT  121.878 7.425 123.12 7.56 ;
     RECT  2.16 7.425 2.268 7.695 ;
     RECT  12.042 7.56 13.284 7.695 ;
     RECT  13.824 7.56 14.148 7.695 ;
     RECT  14.256 7.56 14.58 7.695 ;
     RECT  14.634 7.56 14.958 7.695 ;
     RECT  15.066 7.56 15.228 7.695 ;
     RECT  16.632 7.56 17.118 7.695 ;
     RECT  19.008 7.56 20.412 7.695 ;
     RECT  20.682 7.56 21.168 7.695 ;
     RECT  21.33 7.56 22.41 7.695 ;
     RECT  22.68 7.56 23.058 7.695 ;
     RECT  23.22 7.56 24.3 7.695 ;
     RECT  24.408 7.56 24.57 7.695 ;
     RECT  24.624 7.56 24.948 7.695 ;
     RECT  25.002 7.56 25.326 7.695 ;
     RECT  25.812 7.56 26.946 7.695 ;
     RECT  27.108 7.56 27.54 7.695 ;
     RECT  27.648 7.56 29.16 7.695 ;
     RECT  29.268 7.56 29.7 7.695 ;
     RECT  29.754 7.56 31.266 7.695 ;
     RECT  31.374 7.56 32.832 7.695 ;
     RECT  32.994 7.56 33.696 7.695 ;
     RECT  34.398 7.56 35.1 7.695 ;
     RECT  35.316 7.56 35.64 7.695 ;
     RECT  36.396 7.56 36.828 7.695 ;
     RECT  36.882 7.56 37.314 7.695 ;
     RECT  37.422 7.56 37.962 7.695 ;
     RECT  38.016 7.56 38.61 7.695 ;
     RECT  39.636 7.56 40.5 7.695 ;
     RECT  42.282 7.56 42.66 7.695 ;
     RECT  42.768 7.56 43.956 7.695 ;
     RECT  44.118 7.56 44.55 7.695 ;
     RECT  44.874 7.56 45.63 7.695 ;
     RECT  45.846 7.56 46.278 7.695 ;
     RECT  46.332 7.56 46.71 7.695 ;
     RECT  46.764 7.56 47.52 7.695 ;
     RECT  47.682 7.56 48.546 7.695 ;
     RECT  48.6 7.56 50.382 7.695 ;
     RECT  50.436 7.56 50.76 7.695 ;
     RECT  50.814 7.56 51.138 7.695 ;
     RECT  51.192 7.56 51.624 7.695 ;
     RECT  51.678 7.56 52.218 7.695 ;
     RECT  53.568 7.56 54.054 7.695 ;
     RECT  54.216 7.56 56.268 7.695 ;
     RECT  56.376 7.56 56.808 7.695 ;
     RECT  56.916 7.56 59.238 7.695 ;
     RECT  59.346 7.56 59.778 7.695 ;
     RECT  59.994 7.56 60.75 7.695 ;
     RECT  61.074 7.56 62.964 7.695 ;
     RECT  63.558 7.56 63.882 7.695 ;
     RECT  64.206 7.56 64.53 7.695 ;
     RECT  66.798 7.56 68.202 7.695 ;
     RECT  68.526 7.56 70.308 7.695 ;
     RECT  70.74 7.56 72.9 7.695 ;
     RECT  73.008 7.56 74.25 7.695 ;
     RECT  74.304 7.56 75.654 7.695 ;
     RECT  75.816 7.56 76.896 7.695 ;
     RECT  77.004 7.56 77.544 7.695 ;
     RECT  77.706 7.56 78.678 7.695 ;
     RECT  78.732 7.56 79.11 7.695 ;
     RECT  79.164 7.56 81.108 7.695 ;
     RECT  81.378 7.56 82.134 7.695 ;
     RECT  82.242 7.56 83.538 7.695 ;
     RECT  83.646 7.56 84.51 7.695 ;
     RECT  84.618 7.56 85.158 7.695 ;
     RECT  85.212 7.56 87.156 7.695 ;
     RECT  87.21 7.56 87.642 7.695 ;
     RECT  87.966 7.56 88.344 7.695 ;
     RECT  88.722 7.56 89.154 7.695 ;
     RECT  90.504 7.56 92.448 7.695 ;
     RECT  92.61 7.56 93.15 7.695 ;
     RECT  93.204 7.56 93.582 7.695 ;
     RECT  93.636 7.56 94.014 7.695 ;
     RECT  94.23 7.56 94.662 7.695 ;
     RECT  94.716 7.56 95.094 7.695 ;
     RECT  95.31 7.56 96.39 7.695 ;
     RECT  96.444 7.56 96.876 7.695 ;
     RECT  96.93 7.56 98.334 7.695 ;
     RECT  98.604 7.56 100.494 7.695 ;
     RECT  100.656 7.56 101.088 7.695 ;
     RECT  101.358 7.56 103.032 7.695 ;
     RECT  103.14 7.56 103.464 7.695 ;
     RECT  103.518 7.56 104.166 7.695 ;
     RECT  104.436 7.56 105.516 7.695 ;
     RECT  105.57 7.56 106.65 7.695 ;
     RECT  107.19 7.56 107.838 7.695 ;
     RECT  108.27 7.56 109.35 7.695 ;
     RECT  110.376 7.56 111.996 7.695 ;
     RECT  115.776 7.56 117.018 7.695 ;
     RECT  121.014 7.56 122.256 7.695 ;
     RECT  122.472 7.56 122.796 7.695 ;
     RECT  126.9 7.56 127.008 7.695 ;
     RECT  127.332 7.425 127.44 7.695 ;
     RECT  14.58 7.965 14.742 8.1 ;
     RECT  16.794 7.965 17.874 8.1 ;
     RECT  18.036 7.965 19.278 8.1 ;
     RECT  19.872 7.965 20.196 8.1 ;
     RECT  20.25 7.965 20.412 8.1 ;
     RECT  22.626 7.965 22.95 8.1 ;
     RECT  23.814 7.965 24.3 8.1 ;
     RECT  24.786 7.965 25.272 8.1 ;
     RECT  25.542 7.965 28.836 8.1 ;
     RECT  28.89 7.965 29.268 8.1 ;
     RECT  29.322 7.965 30.078 8.1 ;
     RECT  30.186 7.965 30.51 8.1 ;
     RECT  30.564 7.965 31.104 8.1 ;
     RECT  31.266 7.965 32.454 8.1 ;
     RECT  32.562 7.965 32.886 8.1 ;
     RECT  32.94 7.965 33.264 8.1 ;
     RECT  33.426 7.965 33.858 8.1 ;
     RECT  34.83 7.965 34.992 8.1 ;
     RECT  35.262 7.965 36.288 8.1 ;
     RECT  36.396 7.965 37.368 8.1 ;
     RECT  37.584 7.965 40.392 8.1 ;
     RECT  41.58 7.965 44.118 8.1 ;
     RECT  44.28 7.965 44.712 8.1 ;
     RECT  44.766 7.965 45.576 8.1 ;
     RECT  45.63 7.965 46.44 8.1 ;
     RECT  46.548 7.965 50.004 8.1 ;
     RECT  50.058 7.965 50.76 8.1 ;
     RECT  50.814 7.965 51.894 8.1 ;
     RECT  52.056 7.965 52.164 8.1 ;
     RECT  52.326 7.965 52.65 8.1 ;
     RECT  52.758 7.965 53.136 8.1 ;
     RECT  54.918 7.965 55.728 8.1 ;
     RECT  55.782 7.965 56.322 8.1 ;
     RECT  56.376 7.965 57.618 8.1 ;
     RECT  57.726 7.965 58.86 8.1 ;
     RECT  58.968 7.965 59.508 8.1 ;
     RECT  59.616 7.965 60.048 8.1 ;
     RECT  60.102 7.965 61.452 8.1 ;
     RECT  61.56 7.965 61.992 8.1 ;
     RECT  62.1 7.965 63.342 8.1 ;
     RECT  64.206 7.965 64.53 8.1 ;
     RECT  67.77 7.965 68.094 8.1 ;
     RECT  68.526 7.965 68.85 8.1 ;
     RECT  69.93 7.965 71.226 8.1 ;
     RECT  71.28 7.965 71.442 8.1 ;
     RECT  71.496 7.965 71.874 8.1 ;
     RECT  71.928 7.965 72.306 8.1 ;
     RECT  72.36 7.965 72.792 8.1 ;
     RECT  72.846 7.965 74.034 8.1 ;
     RECT  74.142 7.965 74.682 8.1 ;
     RECT  74.844 7.965 75.978 8.1 ;
     RECT  76.032 7.965 77.382 8.1 ;
     RECT  77.49 7.965 77.814 8.1 ;
     RECT  77.868 7.965 78.624 8.1 ;
     RECT  78.732 7.965 79.164 8.1 ;
     RECT  79.272 7.965 80.082 8.1 ;
     RECT  80.298 7.965 80.73 8.1 ;
     RECT  80.784 7.965 82.89 8.1 ;
     RECT  83.16 7.965 85.158 8.1 ;
     RECT  85.266 7.965 86.184 8.1 ;
     RECT  86.238 7.965 87.48 8.1 ;
     RECT  87.642 7.965 87.966 8.1 ;
     RECT  88.128 7.965 88.668 8.1 ;
     RECT  90.558 7.965 92.232 8.1 ;
     RECT  92.394 7.965 95.31 8.1 ;
     RECT  95.418 7.965 96.282 8.1 ;
     RECT  96.498 7.965 98.874 8.1 ;
     RECT  99.036 7.965 100.008 8.1 ;
     RECT  100.116 7.965 100.98 8.1 ;
     RECT  101.088 7.965 101.52 8.1 ;
     RECT  101.952 7.965 102.06 8.1 ;
     RECT  102.222 7.965 103.302 8.1 ;
     RECT  103.572 7.965 103.896 8.1 ;
     RECT  104.598 7.965 104.922 8.1 ;
     RECT  105.192 7.965 105.516 8.1 ;
     RECT  106.65 7.965 107.892 8.1 ;
     RECT  110.052 7.965 111.132 8.1 ;
     RECT  120.798 7.965 121.446 8.1 ;
     RECT  2.16 7.965 2.268 8.235 ;
     RECT  12.528 8.1 14.688 8.235 ;
     RECT  16.524 8.1 17.172 8.235 ;
     RECT  17.874 8.1 19.278 8.235 ;
     RECT  21.654 8.1 22.896 8.235 ;
     RECT  23.058 8.1 23.382 8.235 ;
     RECT  24.084 8.1 25.164 8.235 ;
     RECT  26.028 8.1 27.216 8.235 ;
     RECT  27.378 8.1 28.998 8.235 ;
     RECT  29.052 8.1 29.376 8.235 ;
     RECT  29.484 8.1 30.348 8.235 ;
     RECT  30.402 8.1 30.942 8.235 ;
     RECT  31.05 8.1 31.806 8.235 ;
     RECT  31.86 8.1 32.4 8.235 ;
     RECT  32.454 8.1 33.696 8.235 ;
     RECT  33.966 8.1 34.29 8.235 ;
     RECT  34.614 8.1 35.856 8.235 ;
     RECT  36.126 8.1 37.53 8.235 ;
     RECT  37.584 8.1 38.556 8.235 ;
     RECT  38.772 8.1 40.986 8.235 ;
     RECT  41.58 8.1 43.416 8.235 ;
     RECT  43.47 8.1 44.55 8.235 ;
     RECT  44.604 8.1 45.036 8.235 ;
     RECT  45.09 8.1 45.846 8.235 ;
     RECT  45.9 8.1 46.71 8.235 ;
     RECT  46.764 8.1 47.52 8.235 ;
     RECT  47.574 8.1 52.164 8.235 ;
     RECT  52.218 8.1 53.19 8.235 ;
     RECT  54.81 8.1 56.106 8.235 ;
     RECT  56.538 8.1 56.862 8.235 ;
     RECT  56.916 8.1 57.294 8.235 ;
     RECT  57.564 8.1 58.104 8.235 ;
     RECT  58.212 8.1 59.94 8.235 ;
     RECT  60.048 8.1 60.588 8.235 ;
     RECT  60.696 8.1 61.074 8.235 ;
     RECT  61.236 8.1 61.668 8.235 ;
     RECT  61.722 8.1 62.154 8.235 ;
     RECT  62.316 8.1 62.748 8.235 ;
     RECT  63.018 8.1 64.692 8.235 ;
     RECT  67.446 8.1 68.85 8.235 ;
     RECT  69.066 8.1 70.308 8.235 ;
     RECT  70.416 8.1 70.74 8.235 ;
     RECT  70.956 8.1 71.388 8.235 ;
     RECT  71.442 8.1 72.684 8.235 ;
     RECT  72.792 8.1 73.548 8.235 ;
     RECT  73.71 8.1 75.114 8.235 ;
     RECT  75.384 8.1 77.112 8.235 ;
     RECT  77.22 8.1 77.922 8.235 ;
     RECT  78.192 8.1 79.002 8.235 ;
     RECT  79.056 8.1 79.488 8.235 ;
     RECT  79.542 8.1 79.974 8.235 ;
     RECT  80.028 8.1 81.702 8.235 ;
     RECT  81.918 8.1 83.052 8.235 ;
     RECT  83.106 8.1 83.646 8.235 ;
     RECT  83.808 8.1 84.888 8.235 ;
     RECT  85.05 8.1 86.13 8.235 ;
     RECT  86.292 8.1 87.642 8.235 ;
     RECT  87.696 8.1 88.452 8.235 ;
     RECT  88.506 8.1 89.046 8.235 ;
     RECT  89.91 8.1 93.312 8.235 ;
     RECT  93.366 8.1 94.176 8.235 ;
     RECT  94.23 8.1 94.662 8.235 ;
     RECT  94.716 8.1 95.958 8.235 ;
     RECT  96.012 8.1 97.2 8.235 ;
     RECT  97.416 8.1 98.82 8.235 ;
     RECT  98.928 8.1 100.224 8.235 ;
     RECT  100.332 8.1 101.088 8.235 ;
     RECT  101.304 8.1 102.168 8.235 ;
     RECT  103.68 8.1 106.002 8.235 ;
     RECT  106.272 8.1 106.434 8.235 ;
     RECT  108.54 8.1 108.864 8.235 ;
     RECT  110.808 8.1 111.132 8.235 ;
     RECT  111.402 8.1 111.564 8.235 ;
     RECT  112.428 8.1 112.752 8.235 ;
     RECT  113.292 8.1 114.912 8.235 ;
     RECT  122.526 8.1 123.174 8.235 ;
     RECT  123.282 8.1 124.524 8.235 ;
     RECT  126.9 8.1 127.008 8.235 ;
     RECT  127.332 7.965 127.44 8.235 ;
     RECT  13.23 8.505 13.554 8.64 ;
     RECT  13.608 8.505 14.094 8.64 ;
     RECT  16.47 8.505 16.632 8.64 ;
     RECT  17.712 8.505 18.792 8.64 ;
     RECT  18.954 8.505 19.116 8.64 ;
     RECT  19.44 8.505 19.764 8.64 ;
     RECT  20.25 8.505 21.87 8.64 ;
     RECT  23.22 8.505 24.3 8.64 ;
     RECT  24.786 8.505 25.866 8.64 ;
     RECT  25.974 8.505 26.352 8.64 ;
     RECT  26.406 8.505 26.838 8.64 ;
     RECT  26.892 8.505 30.834 8.64 ;
     RECT  30.888 8.505 31.32 8.64 ;
     RECT  31.428 8.505 32.238 8.64 ;
     RECT  32.292 8.505 32.616 8.64 ;
     RECT  32.67 8.505 33.642 8.64 ;
     RECT  33.858 8.505 34.938 8.64 ;
     RECT  35.424 8.505 36.396 8.64 ;
     RECT  36.666 8.505 38.394 8.64 ;
     RECT  38.556 8.505 38.988 8.64 ;
     RECT  39.042 8.505 39.744 8.64 ;
     RECT  39.906 8.505 40.338 8.64 ;
     RECT  41.742 8.505 42.498 8.64 ;
     RECT  42.552 8.505 43.848 8.64 ;
     RECT  43.956 8.505 46.764 8.64 ;
     RECT  46.818 8.505 47.196 8.64 ;
     RECT  47.25 8.505 48.384 8.64 ;
     RECT  48.438 8.505 48.87 8.64 ;
     RECT  48.924 8.505 49.302 8.64 ;
     RECT  49.356 8.505 49.788 8.64 ;
     RECT  49.842 8.505 51.192 8.64 ;
     RECT  51.246 8.505 51.786 8.64 ;
     RECT  52.056 8.505 52.488 8.64 ;
     RECT  52.542 8.505 53.514 8.64 ;
     RECT  54.108 8.505 54.54 8.64 ;
     RECT  54.756 8.505 55.89 8.64 ;
     RECT  55.998 8.505 56.916 8.64 ;
     RECT  57.024 8.505 58.59 8.64 ;
     RECT  59.076 8.505 59.508 8.64 ;
     RECT  59.67 8.505 60.75 8.64 ;
     RECT  60.804 8.505 61.128 8.64 ;
     RECT  61.182 8.505 61.992 8.64 ;
     RECT  63.45 8.505 64.206 8.64 ;
     RECT  64.422 8.505 64.584 8.64 ;
     RECT  67.77 8.505 67.932 8.64 ;
     RECT  68.58 8.505 68.742 8.64 ;
     RECT  70.47 8.505 71.712 8.64 ;
     RECT  71.766 8.505 73.008 8.64 ;
     RECT  73.116 8.505 73.548 8.64 ;
     RECT  73.602 8.505 74.358 8.64 ;
     RECT  74.412 8.505 75.87 8.64 ;
     RECT  76.032 8.505 76.788 8.64 ;
     RECT  76.842 8.505 77.706 8.64 ;
     RECT  77.868 8.505 78.84 8.64 ;
     RECT  78.894 8.505 79.65 8.64 ;
     RECT  79.758 8.505 80.19 8.64 ;
     RECT  80.298 8.505 81.054 8.64 ;
     RECT  81.108 8.505 82.782 8.64 ;
     RECT  82.89 8.505 83.322 8.64 ;
     RECT  83.376 8.505 84.186 8.64 ;
     RECT  84.24 8.505 87.102 8.64 ;
     RECT  87.156 8.505 88.344 8.64 ;
     RECT  88.83 8.505 89.37 8.64 ;
     RECT  90.828 8.505 92.502 8.64 ;
     RECT  92.718 8.505 95.418 8.64 ;
     RECT  95.472 8.505 96.606 8.64 ;
     RECT  96.66 8.505 98.172 8.64 ;
     RECT  98.28 8.505 99.144 8.64 ;
     RECT  99.252 8.505 100.71 8.64 ;
     RECT  100.872 8.505 102.06 8.64 ;
     RECT  102.546 8.505 102.87 8.64 ;
     RECT  102.978 8.505 104.058 8.64 ;
     RECT  104.382 8.505 104.706 8.64 ;
     RECT  107.298 8.505 109.62 8.64 ;
     RECT  109.998 8.505 110.322 8.64 ;
     RECT  110.592 8.505 111.672 8.64 ;
     RECT  111.888 8.505 113.292 8.64 ;
     RECT  113.508 8.505 114.912 8.64 ;
     RECT  115.992 8.505 116.316 8.64 ;
     RECT  117.072 8.505 117.342 8.64 ;
     RECT  2.16 8.505 2.268 8.775 ;
     RECT  16.578 8.64 17.658 8.775 ;
     RECT  17.766 8.64 18.09 8.775 ;
     RECT  18.198 8.64 18.522 8.775 ;
     RECT  18.684 8.64 18.846 8.775 ;
     RECT  19.224 8.64 19.548 8.775 ;
     RECT  19.656 8.64 20.304 8.775 ;
     RECT  20.628 8.64 20.79 8.775 ;
     RECT  21.87 8.64 22.518 8.775 ;
     RECT  22.68 8.64 23.328 8.775 ;
     RECT  23.544 8.64 23.706 8.775 ;
     RECT  23.76 8.64 24.408 8.775 ;
     RECT  24.57 8.64 25.218 8.775 ;
     RECT  25.272 8.64 26.73 8.775 ;
     RECT  27.108 8.64 27.54 8.775 ;
     RECT  27.648 8.64 29.808 8.775 ;
     RECT  29.97 8.64 30.402 8.775 ;
     RECT  30.564 8.64 31.644 8.775 ;
     RECT  31.806 8.64 32.184 8.775 ;
     RECT  32.454 8.64 33.696 8.775 ;
     RECT  34.452 8.64 34.884 8.775 ;
     RECT  35.1 8.64 35.478 8.775 ;
     RECT  35.964 8.64 36.774 8.775 ;
     RECT  36.828 8.64 37.152 8.775 ;
     RECT  37.26 8.64 38.34 8.775 ;
     RECT  38.448 8.64 40.176 8.775 ;
     RECT  41.58 8.64 42.39 8.775 ;
     RECT  42.444 8.64 43.254 8.775 ;
     RECT  43.362 8.64 44.442 8.775 ;
     RECT  44.766 8.64 46.386 8.775 ;
     RECT  46.656 8.64 47.898 8.775 ;
     RECT  48.006 8.64 48.384 8.775 ;
     RECT  48.438 8.64 48.816 8.775 ;
     RECT  48.87 8.64 49.68 8.775 ;
     RECT  49.734 8.64 50.166 8.775 ;
     RECT  50.274 8.64 50.706 8.775 ;
     RECT  50.922 8.64 52.272 8.775 ;
     RECT  52.326 8.64 52.758 8.775 ;
     RECT  52.812 8.64 53.19 8.775 ;
     RECT  54.432 8.64 55.242 8.775 ;
     RECT  55.458 8.64 55.782 8.775 ;
     RECT  55.89 8.64 56.268 8.775 ;
     RECT  56.322 8.64 56.754 8.775 ;
     RECT  56.862 8.64 57.186 8.775 ;
     RECT  57.24 8.64 58.05 8.775 ;
     RECT  58.32 8.64 58.752 8.775 ;
     RECT  59.076 8.64 62.424 8.775 ;
     RECT  62.532 8.64 62.964 8.775 ;
     RECT  63.234 8.64 64.746 8.775 ;
     RECT  70.254 8.64 72.198 8.775 ;
     RECT  72.306 8.64 73.44 8.775 ;
     RECT  73.656 8.64 74.52 8.775 ;
     RECT  74.682 8.64 76.41 8.775 ;
     RECT  76.572 8.64 77.112 8.775 ;
     RECT  77.22 8.64 78.408 8.775 ;
     RECT  78.57 8.64 79.326 8.775 ;
     RECT  79.38 8.64 80.622 8.775 ;
     RECT  80.838 8.64 81.378 8.775 ;
     RECT  81.486 8.64 82.188 8.775 ;
     RECT  82.458 8.64 83.916 8.775 ;
     RECT  83.97 8.64 86.886 8.775 ;
     RECT  86.94 8.64 88.182 8.775 ;
     RECT  88.236 8.64 88.776 8.775 ;
     RECT  88.884 8.64 89.316 8.775 ;
     RECT  90.072 8.64 90.612 8.775 ;
     RECT  90.774 8.64 92.34 8.775 ;
     RECT  92.448 8.64 94.986 8.775 ;
     RECT  95.04 8.64 95.58 8.775 ;
     RECT  95.634 8.64 95.958 8.775 ;
     RECT  96.012 8.64 97.578 8.775 ;
     RECT  97.794 8.64 98.604 8.775 ;
     RECT  98.712 8.64 99.414 8.775 ;
     RECT  99.522 8.64 99.684 8.775 ;
     RECT  99.792 8.64 100.116 8.775 ;
     RECT  100.224 8.64 102.87 8.775 ;
     RECT  103.356 8.64 104.76 8.775 ;
     RECT  105.192 8.64 106.164 8.775 ;
     RECT  107.028 8.64 107.352 8.775 ;
     RECT  108.324 8.64 108.648 8.775 ;
     RECT  109.08 8.64 109.242 8.775 ;
     RECT  111.564 8.64 112.968 8.775 ;
     RECT  113.778 8.64 114.102 8.775 ;
     RECT  115.884 8.64 116.964 8.775 ;
     RECT  126.9 8.64 127.008 8.775 ;
     RECT  127.332 8.505 127.44 8.775 ;
     RECT  12.744 9.045 14.148 9.18 ;
     RECT  15.174 9.045 16.902 9.18 ;
     RECT  17.658 9.045 17.982 9.18 ;
     RECT  18.306 9.045 19.548 9.18 ;
     RECT  20.25 9.045 20.682 9.18 ;
     RECT  22.734 9.045 23.058 9.18 ;
     RECT  24.03 9.045 24.192 9.18 ;
     RECT  24.84 9.045 26.46 9.18 ;
     RECT  26.568 9.045 27 9.18 ;
     RECT  27.162 9.045 28.404 9.18 ;
     RECT  28.728 9.045 29.43 9.18 ;
     RECT  29.484 9.045 30.294 9.18 ;
     RECT  30.564 9.045 31.968 9.18 ;
     RECT  32.022 9.045 33.102 9.18 ;
     RECT  33.21 9.045 33.642 9.18 ;
     RECT  35.694 9.045 36.126 9.18 ;
     RECT  36.18 9.045 36.828 9.18 ;
     RECT  37.098 9.045 37.476 9.18 ;
     RECT  37.584 9.045 38.124 9.18 ;
     RECT  38.178 9.045 38.556 9.18 ;
     RECT  38.61 9.045 40.014 9.18 ;
     RECT  40.068 9.045 40.608 9.18 ;
     RECT  41.364 9.045 42.228 9.18 ;
     RECT  42.606 9.045 44.658 9.18 ;
     RECT  44.874 9.045 45.738 9.18 ;
     RECT  46.008 9.045 46.764 9.18 ;
     RECT  46.98 9.045 47.952 9.18 ;
     RECT  48.006 9.045 48.33 9.18 ;
     RECT  48.384 9.045 51.138 9.18 ;
     RECT  51.246 9.045 51.57 9.18 ;
     RECT  51.624 9.045 52.164 9.18 ;
     RECT  52.272 9.045 52.596 9.18 ;
     RECT  52.704 9.045 53.136 9.18 ;
     RECT  54.81 9.045 56.052 9.18 ;
     RECT  56.16 9.045 56.484 9.18 ;
     RECT  56.538 9.045 56.97 9.18 ;
     RECT  57.186 9.045 57.618 9.18 ;
     RECT  57.78 9.045 58.212 9.18 ;
     RECT  58.266 9.045 59.508 9.18 ;
     RECT  59.616 9.045 61.668 9.18 ;
     RECT  61.776 9.045 62.208 9.18 ;
     RECT  62.856 9.045 63.288 9.18 ;
     RECT  63.558 9.045 63.99 9.18 ;
     RECT  69.606 9.045 69.93 9.18 ;
     RECT  70.794 9.045 71.118 9.18 ;
     RECT  71.226 9.045 72.36 9.18 ;
     RECT  72.414 9.045 73.17 9.18 ;
     RECT  73.278 9.045 74.358 9.18 ;
     RECT  74.412 9.045 75.654 9.18 ;
     RECT  75.762 9.045 77.004 9.18 ;
     RECT  77.058 9.045 77.49 9.18 ;
     RECT  77.598 9.045 78.732 9.18 ;
     RECT  78.786 9.045 80.136 9.18 ;
     RECT  80.19 9.045 82.998 9.18 ;
     RECT  83.106 9.045 83.538 9.18 ;
     RECT  83.646 9.045 86.022 9.18 ;
     RECT  86.184 9.045 86.616 9.18 ;
     RECT  86.94 9.045 87.48 9.18 ;
     RECT  87.588 9.045 88.02 9.18 ;
     RECT  88.182 9.045 89.046 9.18 ;
     RECT  89.802 9.045 90.558 9.18 ;
     RECT  90.774 9.045 91.314 9.18 ;
     RECT  91.476 9.045 96.876 9.18 ;
     RECT  96.93 9.045 97.902 9.18 ;
     RECT  98.064 9.045 99.36 9.18 ;
     RECT  99.414 9.045 99.792 9.18 ;
     RECT  99.846 9.045 100.224 9.18 ;
     RECT  100.278 9.045 100.656 9.18 ;
     RECT  100.71 9.045 101.574 9.18 ;
     RECT  101.628 9.045 102.06 9.18 ;
     RECT  103.14 9.045 103.464 9.18 ;
     RECT  104.436 9.045 104.76 9.18 ;
     RECT  104.814 9.045 108.216 9.18 ;
     RECT  108.756 9.045 109.08 9.18 ;
     RECT  109.566 9.045 109.89 9.18 ;
     RECT  111.78 9.045 112.104 9.18 ;
     RECT  113.076 9.045 113.238 9.18 ;
     RECT  113.562 9.045 115.128 9.18 ;
     RECT  115.992 9.045 116.316 9.18 ;
     RECT  116.532 9.045 116.694 9.18 ;
     RECT  116.802 9.045 117.126 9.18 ;
     RECT  118.638 9.045 118.962 9.18 ;
     RECT  2.16 9.045 2.268 9.315 ;
     RECT  13.068 9.18 13.392 9.315 ;
     RECT  13.662 9.18 13.824 9.315 ;
     RECT  13.986 9.18 14.31 9.315 ;
     RECT  14.472 9.18 15.552 9.315 ;
     RECT  15.606 9.18 15.768 9.315 ;
     RECT  16.416 9.18 17.658 9.315 ;
     RECT  17.712 9.18 18.036 9.315 ;
     RECT  20.412 9.18 21.492 9.315 ;
     RECT  21.654 9.18 23.976 9.315 ;
     RECT  24.57 9.18 25.326 9.315 ;
     RECT  25.434 9.18 25.866 9.315 ;
     RECT  26.244 9.18 27.216 9.315 ;
     RECT  27.27 9.18 27.648 9.315 ;
     RECT  27.702 9.18 29.43 9.315 ;
     RECT  29.484 9.18 30.402 9.315 ;
     RECT  30.456 9.18 31.86 9.315 ;
     RECT  31.914 9.18 32.778 9.315 ;
     RECT  32.832 9.18 33.372 9.315 ;
     RECT  33.426 9.18 33.858 9.315 ;
     RECT  36.612 9.18 37.8 9.315 ;
     RECT  37.908 9.18 38.88 9.315 ;
     RECT  39.042 9.18 39.474 9.315 ;
     RECT  39.528 9.18 40.284 9.315 ;
     RECT  40.338 9.18 40.878 9.315 ;
     RECT  41.364 9.18 41.796 9.315 ;
     RECT  42.282 9.18 43.632 9.315 ;
     RECT  43.686 9.18 44.118 9.315 ;
     RECT  44.172 9.18 44.712 9.315 ;
     RECT  44.766 9.18 45.63 9.315 ;
     RECT  45.738 9.18 47.628 9.315 ;
     RECT  47.682 9.18 48.222 9.315 ;
     RECT  48.33 9.18 48.87 9.315 ;
     RECT  48.924 9.18 49.356 9.315 ;
     RECT  49.41 9.18 49.842 9.315 ;
     RECT  49.896 9.18 50.274 9.315 ;
     RECT  50.328 9.18 50.868 9.315 ;
     RECT  50.922 9.18 51.246 9.315 ;
     RECT  51.354 9.18 51.786 9.315 ;
     RECT  51.894 9.18 52.866 9.315 ;
     RECT  54.756 9.18 55.188 9.315 ;
     RECT  55.512 9.18 59.67 9.315 ;
     RECT  59.724 9.18 61.884 9.315 ;
     RECT  61.992 9.18 62.316 9.315 ;
     RECT  62.37 9.18 63.666 9.315 ;
     RECT  69.066 9.18 70.47 9.315 ;
     RECT  70.74 9.18 72.09 9.315 ;
     RECT  72.198 9.18 76.032 9.315 ;
     RECT  76.14 9.18 77.976 9.315 ;
     RECT  78.246 9.18 83.376 9.315 ;
     RECT  83.538 9.18 83.97 9.315 ;
     RECT  84.078 9.18 85.32 9.315 ;
     RECT  85.752 9.18 86.4 9.315 ;
     RECT  86.508 9.18 86.886 9.315 ;
     RECT  86.94 9.18 88.344 9.315 ;
     RECT  88.398 9.18 88.83 9.315 ;
     RECT  90.612 9.18 90.936 9.315 ;
     RECT  90.99 9.18 91.422 9.315 ;
     RECT  91.476 9.18 92.556 9.315 ;
     RECT  92.61 9.18 93.042 9.315 ;
     RECT  93.096 9.18 94.824 9.315 ;
     RECT  94.878 9.18 95.202 9.315 ;
     RECT  95.364 9.18 96.12 9.315 ;
     RECT  96.174 9.18 96.552 9.315 ;
     RECT  96.66 9.18 96.984 9.315 ;
     RECT  97.092 9.18 98.334 9.315 ;
     RECT  98.388 9.18 98.82 9.315 ;
     RECT  99.09 9.18 99.954 9.315 ;
     RECT  100.008 9.18 100.44 9.315 ;
     RECT  100.494 9.18 102.114 9.315 ;
     RECT  103.518 9.18 103.842 9.315 ;
     RECT  104.058 9.18 104.706 9.315 ;
     RECT  104.976 9.18 105.138 9.315 ;
     RECT  105.246 9.18 106.488 9.315 ;
     RECT  106.704 9.18 107.028 9.315 ;
     RECT  107.46 9.18 107.946 9.315 ;
     RECT  108.972 9.18 110.214 9.315 ;
     RECT  110.484 9.18 110.646 9.315 ;
     RECT  112.158 9.18 112.32 9.315 ;
     RECT  112.428 9.18 112.752 9.315 ;
     RECT  114.156 9.18 114.318 9.315 ;
     RECT  114.372 9.18 114.858 9.315 ;
     RECT  114.912 9.18 115.074 9.315 ;
     RECT  115.452 9.18 115.776 9.315 ;
     RECT  116.802 9.18 118.854 9.315 ;
     RECT  122.85 9.18 123.174 9.315 ;
     RECT  126.9 9.18 127.008 9.315 ;
     RECT  127.332 9.045 127.44 9.315 ;
     RECT  13.608 9.585 14.094 9.72 ;
     RECT  15.12 9.585 15.444 9.72 ;
     RECT  16.794 9.585 16.956 9.72 ;
     RECT  19.818 9.585 20.142 9.72 ;
     RECT  21.006 9.585 21.33 9.72 ;
     RECT  22.734 9.585 22.896 9.72 ;
     RECT  25.542 9.585 27.54 9.72 ;
     RECT  27.594 9.585 27.972 9.72 ;
     RECT  28.08 9.585 28.458 9.72 ;
     RECT  28.512 9.585 29.322 9.72 ;
     RECT  29.376 9.585 30.618 9.72 ;
     RECT  30.78 9.585 31.104 9.72 ;
     RECT  31.158 9.585 31.914 9.72 ;
     RECT  31.968 9.585 33.642 9.72 ;
     RECT  35.532 9.585 40.284 9.72 ;
     RECT  40.338 9.585 41.526 9.72 ;
     RECT  41.904 9.585 44.712 9.72 ;
     RECT  44.766 9.585 46.71 9.72 ;
     RECT  46.818 9.585 47.682 9.72 ;
     RECT  47.952 9.585 48.384 9.72 ;
     RECT  48.492 9.585 51.138 9.72 ;
     RECT  51.192 9.585 52.974 9.72 ;
     RECT  54.432 9.585 56.214 9.72 ;
     RECT  56.268 9.585 56.592 9.72 ;
     RECT  56.646 9.585 58.482 9.72 ;
     RECT  58.59 9.585 59.022 9.72 ;
     RECT  59.13 9.585 61.182 9.72 ;
     RECT  61.344 9.585 61.722 9.72 ;
     RECT  61.776 9.585 62.1 9.72 ;
     RECT  62.154 9.585 62.694 9.72 ;
     RECT  62.748 9.585 64.422 9.72 ;
     RECT  68.526 9.585 68.85 9.72 ;
     RECT  68.904 9.585 69.768 9.72 ;
     RECT  69.876 9.585 70.74 9.72 ;
     RECT  70.794 9.585 71.226 9.72 ;
     RECT  71.334 9.585 72.306 9.72 ;
     RECT  72.468 9.585 73.332 9.72 ;
     RECT  73.656 9.585 74.52 9.72 ;
     RECT  74.574 9.585 75.006 9.72 ;
     RECT  75.06 9.585 76.194 9.72 ;
     RECT  76.41 9.585 76.842 9.72 ;
     RECT  76.95 9.585 78.732 9.72 ;
     RECT  78.84 9.585 80.46 9.72 ;
     RECT  80.676 9.585 81.108 9.72 ;
     RECT  81.162 9.585 81.918 9.72 ;
     RECT  82.026 9.585 83.214 9.72 ;
     RECT  83.268 9.585 83.7 9.72 ;
     RECT  83.808 9.585 85.914 9.72 ;
     RECT  85.968 9.585 86.832 9.72 ;
     RECT  87.048 9.585 87.48 9.72 ;
     RECT  87.588 9.585 87.912 9.72 ;
     RECT  87.966 9.585 88.506 9.72 ;
     RECT  90.072 9.585 90.396 9.72 ;
     RECT  90.612 9.585 92.556 9.72 ;
     RECT  92.664 9.585 94.284 9.72 ;
     RECT  94.392 9.585 96.552 9.72 ;
     RECT  96.66 9.585 97.902 9.72 ;
     RECT  97.956 9.585 98.388 9.72 ;
     RECT  98.442 9.585 99.198 9.72 ;
     RECT  99.252 9.585 100.116 9.72 ;
     RECT  100.656 9.585 102.06 9.72 ;
     RECT  102.654 9.585 102.816 9.72 ;
     RECT  103.572 9.585 103.734 9.72 ;
     RECT  103.788 9.585 104.868 9.72 ;
     RECT  105.246 9.585 105.732 9.72 ;
     RECT  105.786 9.585 106.11 9.72 ;
     RECT  106.218 9.585 106.542 9.72 ;
     RECT  106.65 9.585 106.974 9.72 ;
     RECT  107.082 9.585 108.162 9.72 ;
     RECT  108.972 9.585 109.296 9.72 ;
     RECT  109.512 9.585 111.996 9.72 ;
     RECT  112.104 9.585 113.508 9.72 ;
     RECT  113.67 9.585 113.994 9.72 ;
     RECT  114.102 9.585 115.182 9.72 ;
     RECT  115.506 9.585 116.748 9.72 ;
     RECT  116.856 9.585 118.098 9.72 ;
     RECT  118.692 9.585 119.934 9.72 ;
     RECT  119.988 9.585 121.068 9.72 ;
     RECT  121.932 9.585 122.256 9.72 ;
     RECT  122.58 9.585 123.822 9.72 ;
     RECT  2.16 9.585 2.268 9.855 ;
     RECT  13.824 9.72 14.148 9.855 ;
     RECT  15.066 9.72 16.794 9.855 ;
     RECT  16.848 9.72 17.496 9.855 ;
     RECT  17.55 9.72 17.874 9.855 ;
     RECT  18.09 9.72 18.414 9.855 ;
     RECT  19.656 9.72 20.736 9.855 ;
     RECT  21.276 9.72 21.816 9.855 ;
     RECT  23.22 9.72 23.868 9.855 ;
     RECT  23.976 9.72 24.516 9.855 ;
     RECT  24.894 9.72 26.514 9.855 ;
     RECT  26.568 9.72 27.216 9.855 ;
     RECT  27.27 9.72 27.594 9.855 ;
     RECT  27.756 9.72 28.566 9.855 ;
     RECT  28.674 9.72 29.106 9.855 ;
     RECT  29.16 9.72 29.484 9.855 ;
     RECT  29.646 9.72 30.024 9.855 ;
     RECT  30.078 9.72 31.59 9.855 ;
     RECT  31.644 9.72 33.48 9.855 ;
     RECT  33.588 9.72 34.02 9.855 ;
     RECT  35.154 9.72 35.964 9.855 ;
     RECT  36.018 9.72 36.774 9.855 ;
     RECT  36.828 9.72 37.692 9.855 ;
     RECT  37.8 9.72 38.124 9.855 ;
     RECT  38.232 9.72 39.042 9.855 ;
     RECT  39.15 9.72 40.392 9.855 ;
     RECT  40.608 9.72 41.04 9.855 ;
     RECT  41.958 9.72 42.822 9.855 ;
     RECT  42.876 9.72 43.686 9.855 ;
     RECT  43.74 9.72 44.55 9.855 ;
     RECT  44.658 9.72 45.954 9.855 ;
     RECT  46.17 9.72 46.548 9.855 ;
     RECT  46.71 9.72 52.542 9.855 ;
     RECT  52.596 9.72 53.028 9.855 ;
     RECT  54.486 9.72 54.81 9.855 ;
     RECT  55.134 9.72 55.944 9.855 ;
     RECT  55.998 9.72 61.344 9.855 ;
     RECT  61.398 9.72 62.64 9.855 ;
     RECT  62.964 9.72 63.342 9.855 ;
     RECT  63.396 9.72 63.774 9.855 ;
     RECT  64.044 9.72 64.368 9.855 ;
     RECT  68.04 9.72 68.58 9.855 ;
     RECT  68.688 9.72 69.336 9.855 ;
     RECT  69.498 9.72 70.146 9.855 ;
     RECT  70.2 9.72 70.524 9.855 ;
     RECT  70.578 9.72 71.388 9.855 ;
     RECT  71.442 9.72 74.79 9.855 ;
     RECT  75.006 9.72 75.384 9.855 ;
     RECT  75.438 9.72 76.194 9.855 ;
     RECT  76.464 9.72 80.352 9.855 ;
     RECT  80.46 9.72 81.324 9.855 ;
     RECT  81.378 9.72 82.188 9.855 ;
     RECT  82.296 9.72 82.728 9.855 ;
     RECT  82.944 9.72 84.348 9.855 ;
     RECT  84.456 9.72 85.698 9.855 ;
     RECT  85.806 9.72 88.722 9.855 ;
     RECT  88.938 9.72 89.316 9.855 ;
     RECT  90.018 9.72 90.396 9.855 ;
     RECT  90.828 9.72 93.204 9.855 ;
     RECT  93.366 9.72 93.798 9.855 ;
     RECT  93.852 9.72 95.904 9.855 ;
     RECT  96.12 9.72 100.548 9.855 ;
     RECT  100.656 9.72 101.358 9.855 ;
     RECT  101.52 9.72 101.898 9.855 ;
     RECT  102.546 9.72 102.87 9.855 ;
     RECT  104.868 9.72 105.948 9.855 ;
     RECT  106.272 9.72 106.596 9.855 ;
     RECT  107.136 9.72 107.676 9.855 ;
     RECT  107.784 9.72 108.108 9.855 ;
     RECT  108.216 9.72 108.54 9.855 ;
     RECT  108.648 9.72 108.81 9.855 ;
     RECT  108.918 9.72 109.242 9.855 ;
     RECT  110.592 9.72 111.24 9.855 ;
     RECT  111.672 9.72 111.996 9.855 ;
     RECT  112.32 9.72 112.644 9.855 ;
     RECT  113.292 9.72 113.562 9.855 ;
     RECT  113.994 9.72 116.046 9.855 ;
     RECT  117.018 9.72 117.666 9.855 ;
     RECT  119.34 9.72 120.582 9.855 ;
     RECT  120.852 9.72 121.176 9.855 ;
     RECT  121.716 9.72 122.958 9.855 ;
     RECT  123.012 9.72 123.174 9.855 ;
     RECT  126.9 9.72 127.008 9.855 ;
     RECT  127.332 9.585 127.44 9.855 ;
     RECT  12.96 10.125 14.202 10.26 ;
     RECT  14.31 10.125 15.39 10.26 ;
     RECT  16.038 10.125 16.362 10.26 ;
     RECT  16.47 10.125 16.632 10.26 ;
     RECT  16.794 10.125 17.874 10.26 ;
     RECT  18.036 10.125 18.198 10.26 ;
     RECT  18.738 10.125 19.062 10.26 ;
     RECT  19.98 10.125 20.304 10.26 ;
     RECT  20.682 10.125 21.33 10.26 ;
     RECT  21.384 10.125 21.708 10.26 ;
     RECT  21.816 10.125 22.356 10.26 ;
     RECT  22.842 10.125 23.166 10.26 ;
     RECT  23.22 10.125 23.76 10.26 ;
     RECT  23.922 10.125 25.11 10.26 ;
     RECT  25.164 10.125 25.704 10.26 ;
     RECT  25.974 10.125 27.756 10.26 ;
     RECT  27.81 10.125 29.916 10.26 ;
     RECT  30.078 10.125 30.456 10.26 ;
     RECT  30.51 10.125 31.32 10.26 ;
     RECT  31.374 10.125 31.806 10.26 ;
     RECT  31.86 10.125 32.238 10.26 ;
     RECT  32.292 10.125 32.616 10.26 ;
     RECT  32.724 10.125 33.966 10.26 ;
     RECT  34.938 10.125 35.37 10.26 ;
     RECT  35.424 10.125 36.18 10.26 ;
     RECT  36.288 10.125 38.34 10.26 ;
     RECT  38.448 10.125 39.69 10.26 ;
     RECT  39.798 10.125 40.122 10.26 ;
     RECT  40.23 10.125 40.662 10.26 ;
     RECT  40.824 10.125 41.148 10.26 ;
     RECT  41.202 10.125 43.848 10.26 ;
     RECT  43.956 10.125 45.144 10.26 ;
     RECT  45.522 10.125 45.846 10.26 ;
     RECT  46.17 10.125 47.304 10.26 ;
     RECT  47.358 10.125 49.68 10.26 ;
     RECT  49.734 10.125 50.49 10.26 ;
     RECT  50.544 10.125 50.976 10.26 ;
     RECT  51.084 10.125 51.84 10.26 ;
     RECT  52.056 10.125 53.352 10.26 ;
     RECT  54.54 10.125 54.972 10.26 ;
     RECT  55.296 10.125 56.592 10.26 ;
     RECT  56.646 10.125 57.456 10.26 ;
     RECT  57.51 10.125 57.834 10.26 ;
     RECT  57.942 10.125 58.32 10.26 ;
     RECT  58.374 10.125 58.806 10.26 ;
     RECT  58.968 10.125 59.292 10.26 ;
     RECT  59.346 10.125 59.724 10.26 ;
     RECT  59.778 10.125 60.534 10.26 ;
     RECT  60.75 10.125 61.29 10.26 ;
     RECT  61.398 10.125 62.586 10.26 ;
     RECT  62.64 10.125 64.044 10.26 ;
     RECT  64.26 10.125 64.8 10.26 ;
     RECT  68.094 10.125 71.01 10.26 ;
     RECT  71.118 10.125 71.55 10.26 ;
     RECT  71.658 10.125 72.414 10.26 ;
     RECT  72.468 10.125 73.278 10.26 ;
     RECT  73.332 10.125 73.764 10.26 ;
     RECT  73.926 10.125 75.87 10.26 ;
     RECT  76.086 10.125 77.976 10.26 ;
     RECT  78.03 10.125 80.892 10.26 ;
     RECT  81 10.125 82.134 10.26 ;
     RECT  82.188 10.125 82.62 10.26 ;
     RECT  82.674 10.125 84.51 10.26 ;
     RECT  84.726 10.125 85.104 10.26 ;
     RECT  85.212 10.125 85.59 10.26 ;
     RECT  85.698 10.125 87.642 10.26 ;
     RECT  87.75 10.125 89.37 10.26 ;
     RECT  90.504 10.125 95.148 10.26 ;
     RECT  95.202 10.125 96.822 10.26 ;
     RECT  96.876 10.125 97.308 10.26 ;
     RECT  97.362 10.125 98.118 10.26 ;
     RECT  98.172 10.125 99.306 10.26 ;
     RECT  99.36 10.125 99.684 10.26 ;
     RECT  99.738 10.125 100.872 10.26 ;
     RECT  100.926 10.125 101.358 10.26 ;
     RECT  101.52 10.125 102.06 10.26 ;
     RECT  102.33 10.125 102.654 10.26 ;
     RECT  102.978 10.125 103.302 10.26 ;
     RECT  103.356 10.125 104.004 10.26 ;
     RECT  105.138 10.125 105.462 10.26 ;
     RECT  106.65 10.125 106.974 10.26 ;
     RECT  107.73 10.125 108.216 10.26 ;
     RECT  108.702 10.125 109.026 10.26 ;
     RECT  110.862 10.125 111.186 10.26 ;
     RECT  111.348 10.125 111.51 10.26 ;
     RECT  112.05 10.125 112.374 10.26 ;
     RECT  113.076 10.125 113.4 10.26 ;
     RECT  113.994 10.125 114.318 10.26 ;
     RECT  115.56 10.125 115.884 10.26 ;
     RECT  116.478 10.125 116.64 10.26 ;
     RECT  117.558 10.125 117.72 10.26 ;
     RECT  118.746 10.125 119.07 10.26 ;
     RECT  119.394 10.125 120.042 10.26 ;
     RECT  120.096 10.125 120.42 10.26 ;
     RECT  120.528 10.125 120.69 10.26 ;
     RECT  120.96 10.125 121.446 10.26 ;
     RECT  121.824 10.125 122.148 10.26 ;
     RECT  122.364 10.125 124.092 10.26 ;
     RECT  2.16 10.125 2.268 10.395 ;
     RECT  12.744 10.26 14.148 10.395 ;
     RECT  15.282 10.26 15.444 10.395 ;
     RECT  19.062 10.26 20.466 10.395 ;
     RECT  22.194 10.26 22.518 10.395 ;
     RECT  23.004 10.26 23.328 10.395 ;
     RECT  23.598 10.26 24.462 10.395 ;
     RECT  24.57 10.26 24.894 10.395 ;
     RECT  25.002 10.26 25.434 10.395 ;
     RECT  25.596 10.26 25.974 10.395 ;
     RECT  26.136 10.26 26.946 10.395 ;
     RECT  27.108 10.26 28.512 10.395 ;
     RECT  28.62 10.26 30.078 10.395 ;
     RECT  30.132 10.26 32.886 10.395 ;
     RECT  32.94 10.26 33.264 10.395 ;
     RECT  33.372 10.26 34.236 10.395 ;
     RECT  34.992 10.26 35.802 10.395 ;
     RECT  36.18 10.26 37.422 10.395 ;
     RECT  37.476 10.26 38.502 10.395 ;
     RECT  38.88 10.26 40.014 10.395 ;
     RECT  40.122 10.26 40.5 10.395 ;
     RECT  41.31 10.26 42.876 10.395 ;
     RECT  42.93 10.26 45.306 10.395 ;
     RECT  45.36 10.26 45.738 10.395 ;
     RECT  45.954 10.26 47.52 10.395 ;
     RECT  47.898 10.26 48.276 10.395 ;
     RECT  48.33 10.26 48.654 10.395 ;
     RECT  48.816 10.26 49.572 10.395 ;
     RECT  49.626 10.26 51.3 10.395 ;
     RECT  51.354 10.26 51.786 10.395 ;
     RECT  51.84 10.26 52.542 10.395 ;
     RECT  52.596 10.26 53.352 10.395 ;
     RECT  54.216 10.26 54.648 10.395 ;
     RECT  55.08 10.26 55.944 10.395 ;
     RECT  56.106 10.26 56.538 10.395 ;
     RECT  56.862 10.26 57.186 10.395 ;
     RECT  57.24 10.26 58.374 10.395 ;
     RECT  58.59 10.26 60.21 10.395 ;
     RECT  60.318 10.26 60.75 10.395 ;
     RECT  60.858 10.26 61.236 10.395 ;
     RECT  61.344 10.26 62.424 10.395 ;
     RECT  62.586 10.26 62.91 10.395 ;
     RECT  63.288 10.26 64.584 10.395 ;
     RECT  64.692 10.26 65.556 10.395 ;
     RECT  67.932 10.26 69.012 10.395 ;
     RECT  69.12 10.26 69.984 10.395 ;
     RECT  70.038 10.26 70.362 10.395 ;
     RECT  70.47 10.26 71.334 10.395 ;
     RECT  71.388 10.26 72.144 10.395 ;
     RECT  72.198 10.26 72.738 10.395 ;
     RECT  72.9 10.26 73.44 10.395 ;
     RECT  73.494 10.26 75.114 10.395 ;
     RECT  75.384 10.26 75.762 10.395 ;
     RECT  75.816 10.26 77.436 10.395 ;
     RECT  77.544 10.26 78.948 10.395 ;
     RECT  79.002 10.26 80.19 10.395 ;
     RECT  80.298 10.26 82.566 10.395 ;
     RECT  82.674 10.26 83.97 10.395 ;
     RECT  84.024 10.26 85.158 10.395 ;
     RECT  85.212 10.26 85.968 10.395 ;
     RECT  86.022 10.26 86.67 10.395 ;
     RECT  86.832 10.26 88.614 10.395 ;
     RECT  89.262 10.26 89.694 10.395 ;
     RECT  90.504 10.26 90.882 10.395 ;
     RECT  90.99 10.26 92.178 10.395 ;
     RECT  92.34 10.26 93.798 10.395 ;
     RECT  93.852 10.26 95.85 10.395 ;
     RECT  96.012 10.26 96.768 10.395 ;
     RECT  96.876 10.26 97.2 10.395 ;
     RECT  97.308 10.26 98.118 10.395 ;
     RECT  98.28 10.26 98.712 10.395 ;
     RECT  98.766 10.26 99.198 10.395 ;
     RECT  99.252 10.26 102.06 10.395 ;
     RECT  102.114 10.26 103.734 10.395 ;
     RECT  103.95 10.26 104.49 10.395 ;
     RECT  106.596 10.26 106.758 10.395 ;
     RECT  106.974 10.26 107.298 10.395 ;
     RECT  107.784 10.26 108.108 10.395 ;
     RECT  108.756 10.26 109.08 10.395 ;
     RECT  109.134 10.26 110.214 10.395 ;
     RECT  110.592 10.26 110.754 10.395 ;
     RECT  111.24 10.26 111.564 10.395 ;
     RECT  111.726 10.26 112.806 10.395 ;
     RECT  114.264 10.26 114.588 10.395 ;
     RECT  115.506 10.26 116.586 10.395 ;
     RECT  118.044 10.26 118.692 10.395 ;
     RECT  119.502 10.26 119.826 10.395 ;
     RECT  120.852 10.26 121.932 10.395 ;
     RECT  122.742 10.26 123.066 10.395 ;
     RECT  126.9 10.26 127.008 10.395 ;
     RECT  127.332 10.125 127.44 10.395 ;
     RECT  2.16 10.665 2.268 10.8 ;
     RECT  19.494 10.665 20.574 10.8 ;
     RECT  20.736 10.665 21.276 10.8 ;
     RECT  21.384 10.665 21.924 10.8 ;
     RECT  22.302 10.665 22.842 10.8 ;
     RECT  23.058 10.665 24.138 10.8 ;
     RECT  24.192 10.665 24.732 10.8 ;
     RECT  24.84 10.665 25.38 10.8 ;
     RECT  25.65 10.665 26.19 10.8 ;
     RECT  26.46 10.665 27.918 10.8 ;
     RECT  27.972 10.665 29.052 10.8 ;
     RECT  29.106 10.665 29.916 10.8 ;
     RECT  30.024 10.665 30.402 10.8 ;
     RECT  30.51 10.665 32.022 10.8 ;
     RECT  32.076 10.665 32.832 10.8 ;
     RECT  33.102 10.665 33.642 10.8 ;
     RECT  36.018 10.665 36.99 10.8 ;
     RECT  37.098 10.665 37.476 10.8 ;
     RECT  37.692 10.665 38.07 10.8 ;
     RECT  38.178 10.665 38.988 10.8 ;
     RECT  39.096 10.665 39.528 10.8 ;
     RECT  39.636 10.665 40.014 10.8 ;
     RECT  40.176 10.665 40.986 10.8 ;
     RECT  41.148 10.665 42.174 10.8 ;
     RECT  42.282 10.665 42.822 10.8 ;
     RECT  42.876 10.665 43.578 10.8 ;
     RECT  43.848 10.665 44.28 10.8 ;
     RECT  44.442 10.665 44.82 10.8 ;
     RECT  45.09 10.665 47.412 10.8 ;
     RECT  47.628 10.665 48.06 10.8 ;
     RECT  48.168 10.665 48.546 10.8 ;
     RECT  48.654 10.665 49.032 10.8 ;
     RECT  49.14 10.665 50.274 10.8 ;
     RECT  50.544 10.665 50.922 10.8 ;
     RECT  51.192 10.665 51.57 10.8 ;
     RECT  51.732 10.665 52.704 10.8 ;
     RECT  52.758 10.665 53.298 10.8 ;
     RECT  55.026 10.665 56.376 10.8 ;
     RECT  56.592 10.665 57.402 10.8 ;
     RECT  57.51 10.665 57.888 10.8 ;
     RECT  58.374 10.665 58.698 10.8 ;
     RECT  58.914 10.665 59.292 10.8 ;
     RECT  59.346 10.665 60.642 10.8 ;
     RECT  60.804 10.665 61.56 10.8 ;
     RECT  61.938 10.665 63.018 10.8 ;
     RECT  63.072 10.665 63.396 10.8 ;
     RECT  63.45 10.665 64.854 10.8 ;
     RECT  68.202 10.665 68.742 10.8 ;
     RECT  69.228 10.665 71.658 10.8 ;
     RECT  71.712 10.665 73.17 10.8 ;
     RECT  73.224 10.665 74.034 10.8 ;
     RECT  74.142 10.665 74.466 10.8 ;
     RECT  74.52 10.665 75.708 10.8 ;
     RECT  75.762 10.665 76.896 10.8 ;
     RECT  77.004 10.665 78.516 10.8 ;
     RECT  78.678 10.665 81.54 10.8 ;
     RECT  81.81 10.665 82.242 10.8 ;
     RECT  82.404 10.665 84.24 10.8 ;
     RECT  84.402 10.665 85.212 10.8 ;
     RECT  85.374 10.665 86.13 10.8 ;
     RECT  86.886 10.665 87.588 10.8 ;
     RECT  87.642 10.665 88.02 10.8 ;
     RECT  88.614 10.665 88.992 10.8 ;
     RECT  90.234 10.665 91.098 10.8 ;
     RECT  91.152 10.665 92.88 10.8 ;
     RECT  92.988 10.665 93.744 10.8 ;
     RECT  93.906 10.665 95.904 10.8 ;
     RECT  96.066 10.665 97.362 10.8 ;
     RECT  97.524 10.665 97.956 10.8 ;
     RECT  98.01 10.665 98.442 10.8 ;
     RECT  98.55 10.665 98.982 10.8 ;
     RECT  99.09 10.665 100.008 10.8 ;
     RECT  100.224 10.665 100.764 10.8 ;
     RECT  101.088 10.665 103.68 10.8 ;
     RECT  104.004 10.665 104.868 10.8 ;
     RECT  105.03 10.665 105.894 10.8 ;
     RECT  106.326 10.665 107.19 10.8 ;
     RECT  107.946 10.665 109.026 10.8 ;
     RECT  109.188 10.665 110.052 10.8 ;
     RECT  110.322 10.665 111.186 10.8 ;
     RECT  111.456 10.665 111.996 10.8 ;
     RECT  112.266 10.665 113.67 10.8 ;
     RECT  118.206 10.665 118.368 10.8 ;
     RECT  118.53 10.665 119.61 10.8 ;
     RECT  126.9 10.665 127.008 10.8 ;
     RECT  127.332 10.665 127.44 10.8 ;
    LAYER RVTP ;
     RECT  13.824 2.295 14.364 2.43 ;
     RECT  14.634 2.295 14.904 2.43 ;
     RECT  15.444 2.295 15.714 2.43 ;
     RECT  15.768 2.295 16.848 2.43 ;
     RECT  17.118 2.295 17.658 2.43 ;
     RECT  17.982 2.295 18.252 2.43 ;
     RECT  18.36 2.295 18.63 2.43 ;
     RECT  18.846 2.295 19.926 2.43 ;
     RECT  20.196 2.295 20.736 2.43 ;
     RECT  20.79 2.295 21.6 2.43 ;
     RECT  21.654 2.295 21.924 2.43 ;
     RECT  21.978 2.295 22.248 2.43 ;
     RECT  22.356 2.295 22.626 2.43 ;
     RECT  22.68 2.295 23.49 2.43 ;
     RECT  23.598 2.295 24.408 2.43 ;
     RECT  24.462 2.295 25.002 2.43 ;
     RECT  25.218 2.295 25.488 2.43 ;
     RECT  25.65 2.295 26.46 2.43 ;
     RECT  26.514 2.295 26.784 2.43 ;
     RECT  26.838 2.295 27.486 2.43 ;
     RECT  27.648 2.295 28.458 2.43 ;
     RECT  28.512 2.295 29.052 2.43 ;
     RECT  29.16 2.295 29.808 2.43 ;
     RECT  29.97 2.295 30.78 2.43 ;
     RECT  30.834 2.295 31.104 2.43 ;
     RECT  31.212 2.295 32.562 2.43 ;
     RECT  32.616 2.295 32.886 2.43 ;
     RECT  33.048 2.295 33.318 2.43 ;
     RECT  33.372 2.295 35.802 2.43 ;
     RECT  36.018 2.295 37.368 2.43 ;
     RECT  38.124 2.295 38.664 2.43 ;
     RECT  38.826 2.295 40.446 2.43 ;
     RECT  40.5 2.295 41.31 2.43 ;
     RECT  41.526 2.295 41.796 2.43 ;
     RECT  42.228 2.295 42.498 2.43 ;
     RECT  42.606 2.295 42.876 2.43 ;
     RECT  43.038 2.295 43.848 2.43 ;
     RECT  43.902 2.295 44.172 2.43 ;
     RECT  44.28 2.295 45.63 2.43 ;
     RECT  45.684 2.295 45.954 2.43 ;
     RECT  46.062 2.295 46.332 2.43 ;
     RECT  46.548 2.295 46.818 2.43 ;
     RECT  47.034 2.295 48.384 2.43 ;
     RECT  48.438 2.295 49.248 2.43 ;
     RECT  49.302 2.295 49.572 2.43 ;
     RECT  49.788 2.295 50.328 2.43 ;
     RECT  50.544 2.295 51.084 2.43 ;
     RECT  51.192 2.295 51.732 2.43 ;
     RECT  51.786 2.295 52.434 2.43 ;
     RECT  52.488 2.295 52.758 2.43 ;
     RECT  52.92 2.295 53.73 2.43 ;
     RECT  54.162 2.295 54.972 2.43 ;
     RECT  55.026 2.295 57.726 2.43 ;
     RECT  58.158 2.295 59.778 2.43 ;
     RECT  60.048 2.295 61.398 2.43 ;
     RECT  61.56 2.295 61.83 2.43 ;
     RECT  61.938 2.295 62.748 2.43 ;
     RECT  62.802 2.295 63.072 2.43 ;
     RECT  63.126 2.295 63.396 2.43 ;
     RECT  63.45 2.295 63.72 2.43 ;
     RECT  63.882 2.295 64.152 2.43 ;
     RECT  64.314 2.295 64.584 2.43 ;
     RECT  67.932 2.295 68.472 2.43 ;
     RECT  70.362 2.295 70.902 2.43 ;
     RECT  71.01 2.295 71.55 2.43 ;
     RECT  71.766 2.295 72.306 2.43 ;
     RECT  72.522 2.295 72.792 2.43 ;
     RECT  73.008 2.295 74.898 2.43 ;
     RECT  74.952 2.295 75.762 2.43 ;
     RECT  75.816 2.295 76.086 2.43 ;
     RECT  76.194 2.295 78.624 2.43 ;
     RECT  78.732 2.295 80.352 2.43 ;
     RECT  80.46 2.295 82.08 2.43 ;
     RECT  82.296 2.295 82.836 2.43 ;
     RECT  82.89 2.295 83.43 2.43 ;
     RECT  83.484 2.295 84.294 2.43 ;
     RECT  84.348 2.295 85.158 2.43 ;
     RECT  85.266 2.295 86.616 2.43 ;
     RECT  86.67 2.295 86.94 2.43 ;
     RECT  86.994 2.295 87.534 2.43 ;
     RECT  87.588 2.295 87.858 2.43 ;
     RECT  88.236 2.295 89.586 2.43 ;
     RECT  89.856 2.295 90.666 2.43 ;
     RECT  91.044 2.295 91.314 2.43 ;
     RECT  91.476 2.295 92.34 2.43 ;
     RECT  92.556 2.295 93.366 2.43 ;
     RECT  93.42 2.295 93.69 2.43 ;
     RECT  93.798 2.295 94.068 2.43 ;
     RECT  94.824 2.295 95.364 2.43 ;
     RECT  95.418 2.295 95.958 2.43 ;
     RECT  96.066 2.295 96.876 2.43 ;
     RECT  96.93 2.295 99.36 2.43 ;
     RECT  99.468 2.295 99.738 2.43 ;
     RECT  99.846 2.295 100.116 2.43 ;
     RECT  100.17 2.295 100.98 2.43 ;
     RECT  101.034 2.295 101.304 2.43 ;
     RECT  101.358 2.295 101.898 2.43 ;
     RECT  101.952 2.295 102.33 2.43 ;
     RECT  102.438 2.295 102.708 2.43 ;
     RECT  102.762 2.295 103.032 2.43 ;
     RECT  103.248 2.295 103.518 2.43 ;
     RECT  103.626 2.295 104.976 2.43 ;
     RECT  105.084 2.295 105.624 2.43 ;
     RECT  105.786 2.295 106.056 2.43 ;
     RECT  106.164 2.295 106.704 2.43 ;
     RECT  106.866 2.295 107.136 2.43 ;
     RECT  107.622 2.295 108.162 2.43 ;
     RECT  108.486 2.295 109.35 2.43 ;
     RECT  109.836 2.295 110.106 2.43 ;
     RECT  110.214 2.295 110.484 2.43 ;
     RECT  110.646 2.295 111.24 2.43 ;
     RECT  111.348 2.295 112.158 2.43 ;
     RECT  112.482 2.295 113.562 2.43 ;
     RECT  114.264 2.295 115.074 2.43 ;
     RECT  115.398 2.295 116.208 2.43 ;
     RECT  116.586 2.295 116.856 2.43 ;
     RECT  117.72 2.295 118.26 2.43 ;
     RECT  119.07 2.295 119.34 2.43 ;
     RECT  126.9 2.295 127.008 2.43 ;
     RECT  2.16 2.295 2.268 2.565 ;
     RECT  13.932 2.43 14.202 2.565 ;
     RECT  14.688 2.43 14.958 2.565 ;
     RECT  16.146 2.43 17.604 2.565 ;
     RECT  18.198 2.43 18.468 2.565 ;
     RECT  19.818 2.43 20.088 2.565 ;
     RECT  20.79 2.43 21.168 2.565 ;
     RECT  21.6 2.43 21.87 2.565 ;
     RECT  22.302 2.43 22.842 2.565 ;
     RECT  23.112 2.43 23.652 2.565 ;
     RECT  23.814 2.43 24.624 2.565 ;
     RECT  24.84 2.43 26.19 2.565 ;
     RECT  26.298 2.43 27.918 2.565 ;
     RECT  28.134 2.43 28.404 2.565 ;
     RECT  28.458 2.43 28.998 2.565 ;
     RECT  29.214 2.43 30.888 2.565 ;
     RECT  30.942 2.43 32.4 2.565 ;
     RECT  32.562 2.43 33.102 2.565 ;
     RECT  33.21 2.43 34.83 2.565 ;
     RECT  35.154 2.43 35.964 2.565 ;
     RECT  36.18 2.43 36.45 2.565 ;
     RECT  36.99 2.43 37.53 2.565 ;
     RECT  37.746 2.295 38.016 2.565 ;
     RECT  38.178 2.43 38.448 2.565 ;
     RECT  39.042 2.43 39.312 2.565 ;
     RECT  39.42 2.43 39.69 2.565 ;
     RECT  39.798 2.43 40.392 2.565 ;
     RECT  40.554 2.43 40.824 2.565 ;
     RECT  40.932 2.43 41.202 2.565 ;
     RECT  41.418 2.43 41.958 2.565 ;
     RECT  42.444 2.43 44.496 2.565 ;
     RECT  44.604 2.43 47.52 2.565 ;
     RECT  47.574 2.43 48.168 2.565 ;
     RECT  48.384 2.43 49.194 2.565 ;
     RECT  49.572 2.43 49.896 2.565 ;
     RECT  50.058 2.43 51.732 2.565 ;
     RECT  52.056 2.43 52.164 2.565 ;
     RECT  52.218 2.43 53.298 2.565 ;
     RECT  53.892 2.43 54.162 2.565 ;
     RECT  55.026 2.43 55.404 2.565 ;
     RECT  56.538 2.43 58.428 2.565 ;
     RECT  58.644 2.43 59.4 2.565 ;
     RECT  60.75 2.43 61.02 2.565 ;
     RECT  61.128 2.43 61.398 2.565 ;
     RECT  61.56 2.43 62.37 2.565 ;
     RECT  62.532 2.43 62.802 2.565 ;
     RECT  62.856 2.43 63.126 2.565 ;
     RECT  63.234 2.43 64.584 2.565 ;
     RECT  68.742 2.295 70.092 2.565 ;
     RECT  70.254 2.43 71.334 2.565 ;
     RECT  71.388 2.43 71.928 2.565 ;
     RECT  71.982 2.43 72.522 2.565 ;
     RECT  72.576 2.43 72.846 2.565 ;
     RECT  72.954 2.43 74.034 2.565 ;
     RECT  74.196 2.43 76.356 2.565 ;
     RECT  76.572 2.43 77.922 2.565 ;
     RECT  77.976 2.43 78.786 2.565 ;
     RECT  78.84 2.43 79.272 2.565 ;
     RECT  79.38 2.43 80.19 2.565 ;
     RECT  80.352 2.43 80.946 2.565 ;
     RECT  81 2.43 81.594 2.565 ;
     RECT  81.648 2.43 83.268 2.565 ;
     RECT  83.322 2.43 83.592 2.565 ;
     RECT  83.7 2.43 86.886 2.565 ;
     RECT  86.994 2.43 87.264 2.565 ;
     RECT  87.426 2.43 87.696 2.565 ;
     RECT  88.344 2.43 88.614 2.565 ;
     RECT  88.776 2.43 89.64 2.565 ;
     RECT  90.288 2.43 90.828 2.565 ;
     RECT  91.098 2.43 93.96 2.565 ;
     RECT  94.122 2.295 94.662 2.565 ;
     RECT  94.716 2.43 96.336 2.565 ;
     RECT  96.39 2.43 96.93 2.565 ;
     RECT  96.984 2.43 97.848 2.565 ;
     RECT  98.01 2.43 98.28 2.565 ;
     RECT  98.388 2.43 98.658 2.565 ;
     RECT  98.766 2.43 100.17 2.565 ;
     RECT  100.278 2.43 101.358 2.565 ;
     RECT  101.412 2.43 102.654 2.565 ;
     RECT  102.708 2.43 102.978 2.565 ;
     RECT  103.41 2.43 103.95 2.565 ;
     RECT  104.058 2.43 104.598 2.565 ;
     RECT  105.3 2.43 105.84 2.565 ;
     RECT  106.002 2.43 106.272 2.565 ;
     RECT  106.812 2.43 107.082 2.565 ;
     RECT  107.136 2.43 107.46 2.565 ;
     RECT  108.756 2.43 109.836 2.565 ;
     RECT  110.484 2.43 111.726 2.565 ;
     RECT  114.21 2.43 114.75 2.565 ;
     RECT  115.128 2.43 115.776 2.565 ;
     RECT  115.83 2.43 116.37 2.565 ;
     RECT  127.332 2.295 127.44 2.565 ;
     RECT  13.824 2.835 14.094 2.97 ;
     RECT  16.74 2.835 17.01 2.97 ;
     RECT  17.442 2.835 17.712 2.97 ;
     RECT  17.766 2.835 18.306 2.97 ;
     RECT  19.656 2.835 21.276 2.97 ;
     RECT  21.6 2.835 21.87 2.97 ;
     RECT  22.14 2.835 23.76 2.97 ;
     RECT  23.814 2.835 24.354 2.97 ;
     RECT  24.408 2.835 24.678 2.97 ;
     RECT  24.786 2.835 25.326 2.97 ;
     RECT  25.38 2.835 25.92 2.97 ;
     RECT  26.028 2.835 28.404 2.97 ;
     RECT  28.512 2.835 28.782 2.97 ;
     RECT  28.89 2.835 31.32 2.97 ;
     RECT  31.59 2.835 32.022 2.97 ;
     RECT  32.13 2.835 33.372 2.97 ;
     RECT  33.48 2.835 34.02 2.97 ;
     RECT  34.074 2.835 34.614 2.97 ;
     RECT  34.776 2.835 35.046 2.97 ;
     RECT  35.37 2.835 35.91 2.97 ;
     RECT  36.882 2.835 37.962 2.97 ;
     RECT  38.016 2.835 38.394 2.97 ;
     RECT  39.096 2.835 40.338 2.97 ;
     RECT  40.554 2.835 40.824 2.97 ;
     RECT  41.04 2.835 41.31 2.97 ;
     RECT  41.364 2.835 42.768 2.97 ;
     RECT  42.93 2.835 44.28 2.97 ;
     RECT  44.334 2.835 44.604 2.97 ;
     RECT  44.712 2.835 46.872 2.97 ;
     RECT  46.98 2.835 49.302 2.97 ;
     RECT  49.518 2.835 52.866 2.97 ;
     RECT  53.19 2.835 53.46 2.97 ;
     RECT  54.648 2.835 54.918 2.97 ;
     RECT  55.026 2.835 56.106 2.97 ;
     RECT  57.024 2.835 57.294 2.97 ;
     RECT  57.51 2.835 58.05 2.97 ;
     RECT  59.022 2.835 59.562 2.97 ;
     RECT  60.426 2.835 61.506 2.97 ;
     RECT  61.668 2.835 61.938 2.97 ;
     RECT  61.992 2.835 62.316 2.97 ;
     RECT  62.424 2.835 62.694 2.97 ;
     RECT  62.748 2.835 63.018 2.97 ;
     RECT  63.072 2.835 63.774 2.97 ;
     RECT  63.828 2.835 64.638 2.97 ;
     RECT  67.392 2.835 68.472 2.97 ;
     RECT  68.742 2.835 69.066 2.97 ;
     RECT  69.336 2.835 69.66 2.97 ;
     RECT  69.768 2.835 70.2 2.97 ;
     RECT  70.254 2.835 71.604 2.97 ;
     RECT  71.712 2.835 71.982 2.97 ;
     RECT  72.036 2.835 72.36 2.97 ;
     RECT  72.522 2.835 74.844 2.97 ;
     RECT  75.114 2.835 75.708 2.97 ;
     RECT  75.762 2.835 76.356 2.97 ;
     RECT  76.464 2.835 77.112 2.97 ;
     RECT  77.166 2.835 77.49 2.97 ;
     RECT  77.544 2.835 78.192 2.97 ;
     RECT  78.354 2.835 79.758 2.97 ;
     RECT  79.866 2.835 83.268 2.97 ;
     RECT  83.376 2.835 84.24 2.97 ;
     RECT  84.348 2.835 85.86 2.97 ;
     RECT  85.914 2.835 86.724 2.97 ;
     RECT  87.102 2.835 87.372 2.97 ;
     RECT  87.966 2.835 88.236 2.97 ;
     RECT  88.56 2.835 89.64 2.97 ;
     RECT  90.288 2.835 90.558 2.97 ;
     RECT  90.612 2.835 90.936 2.97 ;
     RECT  91.206 2.835 92.07 2.97 ;
     RECT  92.178 2.835 92.502 2.97 ;
     RECT  92.718 2.835 93.258 2.97 ;
     RECT  93.366 2.835 93.636 2.97 ;
     RECT  93.69 2.835 94.554 2.97 ;
     RECT  94.608 2.835 95.472 2.97 ;
     RECT  95.526 2.835 97.416 2.97 ;
     RECT  97.686 2.835 98.388 2.97 ;
     RECT  98.442 2.835 98.712 2.97 ;
     RECT  98.766 2.835 99.576 2.97 ;
     RECT  99.63 2.835 99.954 2.97 ;
     RECT  100.062 2.835 101.142 2.97 ;
     RECT  101.196 2.835 102.276 2.97 ;
     RECT  102.492 2.835 103.032 2.97 ;
     RECT  103.248 2.835 103.95 2.97 ;
     RECT  105.408 2.835 105.948 2.97 ;
     RECT  106.002 2.835 106.272 2.97 ;
     RECT  106.434 2.835 106.974 2.97 ;
     RECT  107.244 2.835 108.81 2.97 ;
     RECT  108.864 2.835 109.35 2.97 ;
     RECT  109.836 2.835 110.106 2.97 ;
     RECT  111.942 2.835 112.212 2.97 ;
     RECT  112.482 2.835 113.562 2.97 ;
     RECT  114.534 2.835 114.858 2.97 ;
     RECT  115.074 2.835 115.398 2.97 ;
     RECT  115.506 2.835 116.748 2.97 ;
     RECT  117.828 2.835 118.368 2.97 ;
     RECT  118.962 2.835 119.232 2.97 ;
     RECT  126.9 2.835 127.008 2.97 ;
     RECT  2.16 2.835 2.268 3.105 ;
     RECT  13.986 2.97 16.092 3.105 ;
     RECT  17.118 2.97 17.28 3.105 ;
     RECT  17.55 2.97 17.874 3.105 ;
     RECT  18.63 2.97 19.872 3.105 ;
     RECT  19.926 2.97 20.52 3.105 ;
     RECT  20.736 2.97 21.06 3.105 ;
     RECT  21.33 2.97 22.788 3.105 ;
     RECT  22.95 2.97 23.22 3.105 ;
     RECT  23.328 2.97 24.786 3.105 ;
     RECT  24.894 2.97 25.434 3.105 ;
     RECT  26.136 2.97 28.296 3.105 ;
     RECT  28.404 2.97 28.944 3.105 ;
     RECT  29.052 2.97 29.646 3.105 ;
     RECT  29.808 2.97 31.05 3.105 ;
     RECT  31.266 2.97 31.536 3.105 ;
     RECT  31.59 2.97 32.184 3.105 ;
     RECT  32.292 2.97 33.264 3.105 ;
     RECT  33.534 2.97 34.236 3.105 ;
     RECT  34.398 2.97 34.83 3.105 ;
     RECT  35.208 2.97 36.828 3.105 ;
     RECT  36.882 2.97 37.26 3.105 ;
     RECT  37.584 2.97 37.746 3.105 ;
     RECT  37.908 2.97 38.232 3.105 ;
     RECT  39.204 2.97 39.852 3.105 ;
     RECT  39.906 2.97 40.5 3.105 ;
     RECT  40.662 2.97 40.932 3.105 ;
     RECT  40.986 2.97 41.256 3.105 ;
     RECT  41.364 2.97 42.174 3.105 ;
     RECT  42.336 2.97 42.66 3.105 ;
     RECT  42.714 2.97 43.254 3.105 ;
     RECT  43.308 2.97 43.902 3.105 ;
     RECT  44.01 2.97 44.28 3.105 ;
     RECT  44.388 2.97 45.792 3.105 ;
     RECT  45.846 2.97 46.926 3.105 ;
     RECT  46.98 2.97 47.304 3.105 ;
     RECT  47.358 2.97 49.41 3.105 ;
     RECT  49.518 2.97 49.68 3.105 ;
     RECT  49.842 2.97 50.274 3.105 ;
     RECT  50.328 2.97 50.598 3.105 ;
     RECT  50.814 2.97 50.976 3.105 ;
     RECT  51.03 2.97 51.84 3.105 ;
     RECT  52.056 2.97 52.164 3.105 ;
     RECT  52.272 2.97 52.812 3.105 ;
     RECT  53.352 2.97 53.514 3.105 ;
     RECT  54.594 2.97 54.864 3.105 ;
     RECT  55.242 2.97 55.566 3.105 ;
     RECT  55.998 2.97 56.16 3.105 ;
     RECT  57.186 2.97 58.05 3.105 ;
     RECT  58.212 2.97 58.86 3.105 ;
     RECT  58.968 2.97 60.102 3.105 ;
     RECT  60.264 2.97 60.534 3.105 ;
     RECT  60.966 2.97 61.29 3.105 ;
     RECT  61.344 2.97 62.208 3.105 ;
     RECT  62.316 2.97 63.666 3.105 ;
     RECT  63.774 2.97 64.584 3.105 ;
     RECT  68.04 2.97 68.31 3.105 ;
     RECT  68.418 2.97 68.58 3.105 ;
     RECT  68.634 2.97 68.958 3.105 ;
     RECT  69.444 2.97 70.038 3.105 ;
     RECT  70.2 2.97 71.712 3.105 ;
     RECT  71.766 2.97 72.09 3.105 ;
     RECT  72.198 2.97 73.44 3.105 ;
     RECT  73.494 2.97 74.196 3.105 ;
     RECT  74.304 2.97 78.192 3.105 ;
     RECT  78.354 2.97 81.378 3.105 ;
     RECT  81.432 2.97 82.512 3.105 ;
     RECT  82.62 2.97 85.374 3.105 ;
     RECT  85.482 2.97 86.076 3.105 ;
     RECT  86.184 2.97 87.264 3.105 ;
     RECT  87.534 2.97 89.424 3.105 ;
     RECT  89.532 2.97 90.936 3.105 ;
     RECT  91.098 2.97 91.368 3.105 ;
     RECT  91.422 2.97 92.07 3.105 ;
     RECT  92.178 2.97 92.772 3.105 ;
     RECT  92.988 2.97 95.904 3.105 ;
     RECT  95.958 2.97 96.228 3.105 ;
     RECT  96.444 2.97 96.714 3.105 ;
     RECT  96.822 2.97 97.092 3.105 ;
     RECT  97.146 2.97 97.686 3.105 ;
     RECT  97.794 2.97 98.874 3.105 ;
     RECT  99.036 2.97 99.306 3.105 ;
     RECT  99.414 2.97 100.062 3.105 ;
     RECT  100.116 2.97 101.25 3.105 ;
     RECT  101.466 2.97 101.736 3.105 ;
     RECT  101.952 2.97 102.06 3.105 ;
     RECT  102.276 2.97 103.626 3.105 ;
     RECT  104.49 2.835 104.814 3.105 ;
     RECT  105.354 2.97 105.624 3.105 ;
     RECT  106.164 2.97 106.758 3.105 ;
     RECT  107.838 2.97 108.108 3.105 ;
     RECT  110.808 2.97 111.132 3.105 ;
     RECT  112.212 2.97 112.86 3.105 ;
     RECT  113.022 2.97 113.454 3.105 ;
     RECT  114.372 2.97 114.696 3.105 ;
     RECT  114.912 2.97 115.236 3.105 ;
     RECT  115.344 2.97 115.614 3.105 ;
     RECT  116.046 2.97 116.316 3.105 ;
     RECT  117.99 2.97 118.26 3.105 ;
     RECT  127.332 2.835 127.44 3.105 ;
     RECT  12.906 3.375 14.472 3.51 ;
     RECT  15.228 3.375 15.714 3.51 ;
     RECT  17.442 3.375 17.712 3.51 ;
     RECT  19.386 3.375 19.656 3.51 ;
     RECT  21.708 3.375 21.978 3.51 ;
     RECT  22.356 3.375 22.518 3.51 ;
     RECT  22.572 3.375 22.842 3.51 ;
     RECT  22.896 3.375 23.166 3.51 ;
     RECT  23.274 3.375 23.544 3.51 ;
     RECT  23.652 3.375 24.57 3.51 ;
     RECT  24.624 3.375 25.434 3.51 ;
     RECT  25.92 3.375 26.568 3.51 ;
     RECT  26.73 3.375 27.216 3.51 ;
     RECT  27.324 3.375 28.296 3.51 ;
     RECT  28.35 3.375 30.132 3.51 ;
     RECT  30.402 3.375 30.726 3.51 ;
     RECT  30.78 3.375 31.266 3.51 ;
     RECT  31.482 3.375 32.886 3.51 ;
     RECT  33.75 3.375 34.02 3.51 ;
     RECT  34.182 3.375 35.64 3.51 ;
     RECT  35.748 3.375 36.018 3.51 ;
     RECT  36.774 3.375 36.936 3.51 ;
     RECT  36.99 3.375 37.314 3.51 ;
     RECT  37.962 3.375 39.798 3.51 ;
     RECT  39.906 3.375 40.176 3.51 ;
     RECT  40.284 3.375 41.796 3.51 ;
     RECT  42.39 3.375 43.632 3.51 ;
     RECT  43.686 3.375 44.118 3.51 ;
     RECT  44.226 3.375 45.252 3.51 ;
     RECT  45.522 3.375 46.008 3.51 ;
     RECT  46.116 3.375 46.71 3.51 ;
     RECT  46.926 3.375 47.358 3.51 ;
     RECT  47.412 3.375 47.736 3.51 ;
     RECT  47.79 3.375 48.114 3.51 ;
     RECT  48.168 3.375 48.492 3.51 ;
     RECT  48.546 3.375 49.896 3.51 ;
     RECT  49.95 3.375 50.274 3.51 ;
     RECT  50.328 3.375 51.678 3.51 ;
     RECT  51.894 3.375 52.164 3.51 ;
     RECT  52.488 3.375 52.866 3.51 ;
     RECT  53.136 3.375 53.298 3.51 ;
     RECT  53.352 3.375 53.676 3.51 ;
     RECT  53.73 3.375 54 3.51 ;
     RECT  54.378 3.375 55.08 3.51 ;
     RECT  55.242 3.375 55.62 3.51 ;
     RECT  56.322 3.375 57.294 3.51 ;
     RECT  57.456 3.375 57.618 3.51 ;
     RECT  57.726 3.375 58.968 3.51 ;
     RECT  59.022 3.375 60.426 3.51 ;
     RECT  60.48 3.375 61.236 3.51 ;
     RECT  61.614 3.375 62.856 3.51 ;
     RECT  63.072 3.375 63.666 3.51 ;
     RECT  63.828 3.375 64.098 3.51 ;
     RECT  64.206 3.375 64.476 3.51 ;
     RECT  69.66 3.375 69.93 3.51 ;
     RECT  70.146 3.375 70.416 3.51 ;
     RECT  70.47 3.375 71.82 3.51 ;
     RECT  72.036 3.375 74.034 3.51 ;
     RECT  74.196 3.375 74.79 3.51 ;
     RECT  74.844 3.375 80.622 3.51 ;
     RECT  80.676 3.375 81 3.51 ;
     RECT  81.108 3.375 81.378 3.51 ;
     RECT  81.432 3.375 82.296 3.51 ;
     RECT  82.404 3.375 83.538 3.51 ;
     RECT  83.7 3.375 87.048 3.51 ;
     RECT  87.588 3.375 87.912 3.51 ;
     RECT  88.56 3.375 88.722 3.51 ;
     RECT  89.316 3.375 89.64 3.51 ;
     RECT  90.45 3.375 90.612 3.51 ;
     RECT  90.72 3.375 91.044 3.51 ;
     RECT  91.152 3.375 93.528 3.51 ;
     RECT  93.582 3.375 94.284 3.51 ;
     RECT  94.392 3.375 95.256 3.51 ;
     RECT  95.31 3.375 95.904 3.51 ;
     RECT  96.066 3.375 96.39 3.51 ;
     RECT  96.498 3.375 97.902 3.51 ;
     RECT  97.956 3.375 100.116 3.51 ;
     RECT  100.17 3.375 101.034 3.51 ;
     RECT  101.52 3.375 102.06 3.51 ;
     RECT  102.222 3.375 102.762 3.51 ;
     RECT  102.978 3.375 103.302 3.51 ;
     RECT  104.22 3.375 105.732 3.51 ;
     RECT  106.218 3.375 108.648 3.51 ;
     RECT  109.836 3.375 110.106 3.51 ;
     RECT  110.538 3.375 111.942 3.51 ;
     RECT  112.212 3.375 112.482 3.51 ;
     RECT  114.534 3.375 115.614 3.51 ;
     RECT  115.884 3.375 116.154 3.51 ;
     RECT  116.64 3.375 116.91 3.51 ;
     RECT  117.288 3.375 117.558 3.51 ;
     RECT  119.232 3.375 119.502 3.51 ;
     RECT  126.9 3.375 127.008 3.51 ;
     RECT  2.16 3.375 2.268 3.645 ;
     RECT  15.12 3.51 16.524 3.645 ;
     RECT  16.686 3.51 17.064 3.645 ;
     RECT  17.28 3.51 17.55 3.645 ;
     RECT  17.604 3.51 18.09 3.645 ;
     RECT  21.6 3.51 22.194 3.645 ;
     RECT  22.248 3.51 22.572 3.645 ;
     RECT  24.084 3.51 24.408 3.645 ;
     RECT  24.516 3.51 25.002 3.645 ;
     RECT  25.218 3.51 25.38 3.645 ;
     RECT  25.812 3.51 28.62 3.645 ;
     RECT  28.782 3.51 30.24 3.645 ;
     RECT  30.51 3.51 30.834 3.645 ;
     RECT  30.942 3.51 31.32 3.645 ;
     RECT  31.482 3.51 32.562 3.645 ;
     RECT  32.616 3.51 32.778 3.645 ;
     RECT  32.94 3.51 33.318 3.645 ;
     RECT  33.426 3.51 34.506 3.645 ;
     RECT  35.154 3.51 35.64 3.645 ;
     RECT  36.558 3.51 36.828 3.645 ;
     RECT  39.204 3.51 40.608 3.645 ;
     RECT  40.662 3.51 40.932 3.645 ;
     RECT  40.986 3.51 41.256 3.645 ;
     RECT  41.364 3.51 41.634 3.645 ;
     RECT  42.444 3.51 43.038 3.645 ;
     RECT  43.146 3.51 45.09 3.645 ;
     RECT  45.252 3.51 45.576 3.645 ;
     RECT  45.63 3.51 45.792 3.645 ;
     RECT  45.954 3.51 47.196 3.645 ;
     RECT  47.25 3.51 48.816 3.645 ;
     RECT  48.87 3.51 50.382 3.645 ;
     RECT  51.246 3.51 51.57 3.645 ;
     RECT  52.056 3.51 52.164 3.645 ;
     RECT  52.65 3.51 52.974 3.645 ;
     RECT  53.352 3.51 53.73 3.645 ;
     RECT  54.054 3.51 55.134 3.645 ;
     RECT  55.188 3.51 55.35 3.645 ;
     RECT  56.538 3.51 57.78 3.645 ;
     RECT  57.834 3.51 60.48 3.645 ;
     RECT  62.1 3.51 62.37 3.645 ;
     RECT  62.478 3.51 63.072 3.645 ;
     RECT  63.234 3.51 63.666 3.645 ;
     RECT  63.72 3.51 64.368 3.645 ;
     RECT  66.96 3.51 68.364 3.645 ;
     RECT  69.12 3.51 69.39 3.645 ;
     RECT  70.254 3.51 71.118 3.645 ;
     RECT  71.28 3.51 71.604 3.645 ;
     RECT  71.874 3.51 72.144 3.645 ;
     RECT  72.252 3.51 72.522 3.645 ;
     RECT  72.576 3.51 73.44 3.645 ;
     RECT  73.494 3.51 75.654 3.645 ;
     RECT  75.708 3.51 79.056 3.645 ;
     RECT  79.11 3.51 81.432 3.645 ;
     RECT  81.486 3.51 81.81 3.645 ;
     RECT  81.864 3.51 84.672 3.645 ;
     RECT  84.726 3.51 86.022 3.645 ;
     RECT  86.13 3.51 86.832 3.645 ;
     RECT  87.156 3.51 87.48 3.645 ;
     RECT  88.344 3.51 88.668 3.645 ;
     RECT  88.884 3.51 89.154 3.645 ;
     RECT  90.558 3.51 99.792 3.645 ;
     RECT  99.846 3.51 100.116 3.645 ;
     RECT  100.224 3.51 101.844 3.645 ;
     RECT  101.952 3.51 102.06 3.645 ;
     RECT  102.222 3.51 102.546 3.645 ;
     RECT  102.762 3.51 104.328 3.645 ;
     RECT  104.868 3.51 105.192 3.645 ;
     RECT  105.354 3.51 106.974 3.645 ;
     RECT  107.19 3.51 107.514 3.645 ;
     RECT  110.106 3.51 110.376 3.645 ;
     RECT  110.646 3.51 110.97 3.645 ;
     RECT  111.294 3.51 111.564 3.645 ;
     RECT  111.888 3.51 112.05 3.645 ;
     RECT  113.076 3.51 113.346 3.645 ;
     RECT  114.588 3.51 114.75 3.645 ;
     RECT  115.074 3.51 116.316 3.645 ;
     RECT  119.178 3.51 119.448 3.645 ;
     RECT  127.332 3.375 127.44 3.645 ;
     RECT  16.146 3.915 16.308 4.05 ;
     RECT  16.362 3.915 17.712 4.05 ;
     RECT  17.766 3.915 18.144 4.05 ;
     RECT  19.17 3.915 19.818 4.05 ;
     RECT  19.98 3.915 21.06 4.05 ;
     RECT  21.222 3.915 21.492 4.05 ;
     RECT  21.978 3.915 22.68 4.05 ;
     RECT  23.814 3.915 24.138 4.05 ;
     RECT  24.192 3.915 25.002 4.05 ;
     RECT  25.488 3.915 27.54 4.05 ;
     RECT  27.756 3.915 28.08 4.05 ;
     RECT  28.188 3.915 29.592 4.05 ;
     RECT  29.646 3.915 30.726 4.05 ;
     RECT  30.942 3.915 31.482 4.05 ;
     RECT  31.752 3.915 31.914 4.05 ;
     RECT  32.022 3.915 32.292 4.05 ;
     RECT  32.508 3.915 34.452 4.05 ;
     RECT  36.234 3.915 36.936 4.05 ;
     RECT  38.502 3.915 39.15 4.05 ;
     RECT  39.204 3.915 39.744 4.05 ;
     RECT  39.906 3.915 40.176 4.05 ;
     RECT  40.284 3.915 40.608 4.05 ;
     RECT  41.31 3.915 41.58 4.05 ;
     RECT  42.066 3.915 42.336 4.05 ;
     RECT  42.39 3.915 45.684 4.05 ;
     RECT  45.792 3.915 46.602 4.05 ;
     RECT  46.764 3.915 47.844 4.05 ;
     RECT  47.952 3.915 48.276 4.05 ;
     RECT  48.33 3.915 48.816 4.05 ;
     RECT  49.032 3.915 50.76 4.05 ;
     RECT  51.084 3.915 53.568 4.05 ;
     RECT  53.676 3.915 53.946 4.05 ;
     RECT  54.324 3.915 55.944 4.05 ;
     RECT  56.322 3.915 56.916 4.05 ;
     RECT  56.97 3.915 58.05 4.05 ;
     RECT  58.104 3.915 58.266 4.05 ;
     RECT  58.32 3.915 58.698 4.05 ;
     RECT  58.752 3.915 59.184 4.05 ;
     RECT  59.238 3.915 60.318 4.05 ;
     RECT  60.372 3.915 61.182 4.05 ;
     RECT  62.154 3.915 63.288 4.05 ;
     RECT  63.342 3.915 65.124 4.05 ;
     RECT  67.932 3.915 68.094 4.05 ;
     RECT  68.31 3.915 69.39 4.05 ;
     RECT  69.444 3.915 70.686 4.05 ;
     RECT  70.74 3.915 71.064 4.05 ;
     RECT  71.118 3.915 72.684 4.05 ;
     RECT  72.738 3.915 73.008 4.05 ;
     RECT  73.332 3.915 75.06 4.05 ;
     RECT  75.222 3.915 75.546 4.05 ;
     RECT  75.654 3.915 77.652 4.05 ;
     RECT  77.814 3.915 79.002 4.05 ;
     RECT  79.056 3.915 79.704 4.05 ;
     RECT  79.866 3.915 82.674 4.05 ;
     RECT  82.728 3.915 85.266 4.05 ;
     RECT  85.374 3.915 86.454 4.05 ;
     RECT  87.102 3.915 88.506 4.05 ;
     RECT  88.668 3.915 88.938 4.05 ;
     RECT  89.208 3.915 89.532 4.05 ;
     RECT  89.64 3.915 89.91 4.05 ;
     RECT  91.044 3.915 93.096 4.05 ;
     RECT  93.15 3.915 96.066 4.05 ;
     RECT  96.282 3.915 98.604 4.05 ;
     RECT  98.658 3.915 99.252 4.05 ;
     RECT  99.468 3.915 100.71 4.05 ;
     RECT  100.818 3.915 101.304 4.05 ;
     RECT  101.466 3.915 101.736 4.05 ;
     RECT  101.79 3.915 102.762 4.05 ;
     RECT  103.626 3.915 104.274 4.05 ;
     RECT  104.868 3.915 105.192 4.05 ;
     RECT  105.462 3.915 105.786 4.05 ;
     RECT  106.056 3.915 106.488 4.05 ;
     RECT  106.542 3.915 106.866 4.05 ;
     RECT  106.92 3.915 107.568 4.05 ;
     RECT  107.838 3.915 108.108 4.05 ;
     RECT  108.378 3.915 108.648 4.05 ;
     RECT  112.752 3.915 113.67 4.05 ;
     RECT  114.804 3.915 115.074 4.05 ;
     RECT  115.344 3.915 115.668 4.05 ;
     RECT  118.098 3.915 119.178 4.05 ;
     RECT  126.9 3.915 127.008 4.05 ;
     RECT  2.16 3.915 2.268 4.185 ;
     RECT  14.31 4.05 14.688 4.185 ;
     RECT  14.796 4.05 15.066 4.185 ;
     RECT  15.336 4.05 15.606 4.185 ;
     RECT  18.36 4.05 18.738 4.185 ;
     RECT  18.846 4.05 19.332 4.185 ;
     RECT  19.872 4.05 20.952 4.185 ;
     RECT  21.924 4.05 22.194 4.185 ;
     RECT  22.302 4.05 22.626 4.185 ;
     RECT  22.842 4.05 25.38 4.185 ;
     RECT  25.488 4.05 25.866 4.185 ;
     RECT  26.028 4.05 26.352 4.185 ;
     RECT  26.406 4.05 27.756 4.185 ;
     RECT  27.918 4.05 28.242 4.185 ;
     RECT  28.458 4.05 30.672 4.185 ;
     RECT  30.78 4.05 32.184 4.185 ;
     RECT  32.454 4.05 33.372 4.185 ;
     RECT  33.534 4.05 33.696 4.185 ;
     RECT  33.858 4.05 34.938 4.185 ;
     RECT  35.586 4.05 36.828 4.185 ;
     RECT  36.882 4.05 38.232 4.185 ;
     RECT  38.772 4.05 39.636 4.185 ;
     RECT  39.744 4.05 40.716 4.185 ;
     RECT  42.12 4.05 42.768 4.185 ;
     RECT  42.93 4.05 43.362 4.185 ;
     RECT  43.416 4.05 44.226 4.185 ;
     RECT  44.28 4.05 44.658 4.185 ;
     RECT  44.82 4.05 47.25 4.185 ;
     RECT  47.304 4.05 49.95 4.185 ;
     RECT  50.058 4.05 50.706 4.185 ;
     RECT  50.922 4.05 51.894 4.185 ;
     RECT  52.056 4.05 52.164 4.185 ;
     RECT  52.218 4.05 52.488 4.185 ;
     RECT  52.542 4.05 52.866 4.185 ;
     RECT  54 4.05 54.594 4.185 ;
     RECT  54.648 4.05 55.728 4.185 ;
     RECT  55.944 4.05 57.51 4.185 ;
     RECT  57.564 4.05 60.75 4.185 ;
     RECT  60.858 4.05 61.722 4.185 ;
     RECT  62.478 4.05 63.018 4.185 ;
     RECT  63.072 4.05 64.152 4.185 ;
     RECT  64.206 4.05 64.53 4.185 ;
     RECT  64.8 4.05 64.962 4.185 ;
     RECT  67.986 4.05 68.31 4.185 ;
     RECT  68.634 4.05 68.958 4.185 ;
     RECT  70.848 4.05 71.118 4.185 ;
     RECT  71.496 4.05 71.766 4.185 ;
     RECT  71.982 4.05 72.306 4.185 ;
     RECT  72.522 4.05 74.574 4.185 ;
     RECT  74.682 4.05 77.382 4.185 ;
     RECT  77.49 4.05 78.57 4.185 ;
     RECT  78.678 4.05 79.596 4.185 ;
     RECT  79.758 4.05 80.568 4.185 ;
     RECT  80.622 4.05 81.81 4.185 ;
     RECT  81.864 4.05 82.404 4.185 ;
     RECT  82.512 4.05 83.916 4.185 ;
     RECT  83.97 4.05 85.374 4.185 ;
     RECT  85.482 4.05 87.102 4.185 ;
     RECT  87.156 4.05 87.48 4.185 ;
     RECT  88.074 4.05 89.478 4.185 ;
     RECT  89.586 4.05 89.91 4.185 ;
     RECT  90.828 4.05 91.152 4.185 ;
     RECT  91.26 4.05 91.584 4.185 ;
     RECT  91.692 4.05 92.286 4.185 ;
     RECT  92.394 4.05 92.88 4.185 ;
     RECT  92.988 4.05 94.338 4.185 ;
     RECT  94.392 4.05 96.39 4.185 ;
     RECT  96.444 4.05 97.632 4.185 ;
     RECT  97.686 4.05 98.334 4.185 ;
     RECT  98.442 4.05 99.09 4.185 ;
     RECT  99.198 4.05 99.738 4.185 ;
     RECT  99.9 4.05 100.818 4.185 ;
     RECT  101.142 4.05 101.466 4.185 ;
     RECT  101.574 4.05 101.898 4.185 ;
     RECT  101.952 4.05 102.06 4.185 ;
     RECT  102.276 4.05 103.626 4.185 ;
     RECT  103.95 4.05 105.192 4.185 ;
     RECT  105.246 4.05 105.516 4.185 ;
     RECT  106.38 4.05 107.622 4.185 ;
     RECT  107.676 4.05 107.838 4.185 ;
     RECT  109.566 4.05 110.646 4.185 ;
     RECT  111.24 4.05 111.51 4.185 ;
     RECT  111.564 4.05 111.834 4.185 ;
     RECT  112.104 4.05 112.752 4.185 ;
     RECT  113.454 4.05 113.724 4.185 ;
     RECT  115.506 4.05 116.586 4.185 ;
     RECT  116.91 4.05 117.18 4.185 ;
     RECT  117.936 4.05 118.26 4.185 ;
     RECT  118.422 4.05 118.584 4.185 ;
     RECT  127.332 3.915 127.44 4.185 ;
     RECT  13.014 4.455 15.606 4.59 ;
     RECT  16.902 4.455 17.172 4.59 ;
     RECT  17.28 4.455 17.658 4.59 ;
     RECT  17.712 4.455 17.874 4.59 ;
     RECT  18.414 4.455 18.738 4.59 ;
     RECT  18.792 4.455 19.872 4.59 ;
     RECT  20.628 4.455 21.114 4.59 ;
     RECT  21.168 4.455 22.788 4.59 ;
     RECT  23.814 4.455 23.976 4.59 ;
     RECT  24.3 4.455 24.57 4.59 ;
     RECT  25.542 4.455 26.622 4.59 ;
     RECT  26.676 4.455 27.216 4.59 ;
     RECT  27.27 4.455 29.268 4.59 ;
     RECT  29.376 4.455 29.7 4.59 ;
     RECT  29.808 4.455 30.294 4.59 ;
     RECT  30.348 4.455 31.59 4.59 ;
     RECT  31.968 4.455 32.886 4.59 ;
     RECT  33.696 4.455 34.668 4.59 ;
     RECT  34.776 4.455 34.938 4.59 ;
     RECT  37.368 4.455 37.746 4.59 ;
     RECT  37.908 4.455 38.988 4.59 ;
     RECT  39.312 4.455 39.636 4.59 ;
     RECT  40.068 4.455 40.608 4.59 ;
     RECT  41.634 4.455 43.794 4.59 ;
     RECT  43.902 4.455 44.982 4.59 ;
     RECT  45.036 4.455 49.788 4.59 ;
     RECT  50.058 4.455 50.922 4.59 ;
     RECT  51.084 4.455 52.326 4.59 ;
     RECT  52.974 4.455 54.216 4.59 ;
     RECT  54.27 4.455 54.594 4.59 ;
     RECT  54.864 4.455 55.512 4.59 ;
     RECT  55.62 4.455 55.782 4.59 ;
     RECT  55.998 4.455 56.376 4.59 ;
     RECT  56.592 4.455 57.672 4.59 ;
     RECT  57.834 4.455 58.158 4.59 ;
     RECT  58.32 4.455 58.86 4.59 ;
     RECT  58.914 4.455 59.238 4.59 ;
     RECT  59.292 4.455 59.724 4.59 ;
     RECT  59.832 4.455 60.318 4.59 ;
     RECT  60.372 4.455 61.452 4.59 ;
     RECT  61.506 4.455 61.83 4.59 ;
     RECT  62.64 4.455 63.234 4.59 ;
     RECT  63.342 4.455 64.26 4.59 ;
     RECT  68.796 4.455 69.12 4.59 ;
     RECT  69.282 4.455 69.444 4.59 ;
     RECT  69.714 4.455 69.984 4.59 ;
     RECT  70.848 4.455 71.496 4.59 ;
     RECT  71.604 4.455 72.684 4.59 ;
     RECT  72.738 4.455 74.088 4.59 ;
     RECT  74.304 4.455 75.978 4.59 ;
     RECT  76.032 4.455 76.518 4.59 ;
     RECT  76.572 4.455 77.436 4.59 ;
     RECT  77.652 4.455 78.624 4.59 ;
     RECT  78.678 4.455 81.594 4.59 ;
     RECT  81.648 4.455 82.458 4.59 ;
     RECT  82.512 4.455 83.376 4.59 ;
     RECT  83.43 4.455 83.592 4.59 ;
     RECT  83.7 4.455 85.644 4.59 ;
     RECT  85.698 4.455 87.21 4.59 ;
     RECT  89.532 4.455 90.774 4.59 ;
     RECT  90.828 4.455 93.528 4.59 ;
     RECT  93.69 4.455 96.228 4.59 ;
     RECT  96.282 4.455 100.17 4.59 ;
     RECT  100.602 4.455 100.926 4.59 ;
     RECT  101.034 4.455 101.358 4.59 ;
     RECT  101.466 4.455 102.708 4.59 ;
     RECT  102.924 4.455 103.086 4.59 ;
     RECT  103.14 4.455 103.302 4.59 ;
     RECT  105.192 4.455 106.272 4.59 ;
     RECT  106.974 4.455 107.244 4.59 ;
     RECT  108.864 4.455 109.404 4.59 ;
     RECT  110.484 4.455 111.888 4.59 ;
     RECT  112.158 4.455 113.67 4.59 ;
     RECT  113.832 4.455 115.074 4.59 ;
     RECT  115.344 4.455 115.668 4.59 ;
     RECT  116.1 4.455 116.262 4.59 ;
     RECT  117.828 4.455 118.476 4.59 ;
     RECT  118.584 4.455 120.15 4.59 ;
     RECT  126.9 4.455 127.008 4.59 ;
     RECT  2.16 4.455 2.268 4.725 ;
     RECT  14.472 4.59 15.66 4.725 ;
     RECT  16.74 4.59 17.82 4.725 ;
     RECT  17.874 4.59 18.198 4.725 ;
     RECT  18.792 4.59 19.332 4.725 ;
     RECT  20.844 4.59 21.33 4.725 ;
     RECT  22.572 4.59 23.814 4.725 ;
     RECT  23.922 4.59 24.57 4.725 ;
     RECT  24.732 4.59 26.082 4.725 ;
     RECT  26.136 4.59 26.514 4.725 ;
     RECT  26.568 4.59 26.946 4.725 ;
     RECT  27.054 4.59 27.324 4.725 ;
     RECT  27.378 4.59 29.754 4.725 ;
     RECT  29.808 4.59 30.186 4.725 ;
     RECT  30.24 4.59 32.184 4.725 ;
     RECT  32.778 4.59 33.156 4.725 ;
     RECT  35.154 4.59 35.478 4.725 ;
     RECT  36.072 4.59 37.152 4.725 ;
     RECT  37.53 4.59 37.854 4.725 ;
     RECT  38.07 4.59 38.556 4.725 ;
     RECT  38.718 4.59 40.284 4.725 ;
     RECT  42.12 4.59 44.388 4.725 ;
     RECT  44.496 4.59 47.736 4.725 ;
     RECT  47.79 4.59 48.654 4.725 ;
     RECT  48.87 4.59 50.976 4.725 ;
     RECT  51.03 4.59 51.354 4.725 ;
     RECT  51.408 4.59 51.732 4.725 ;
     RECT  51.84 4.59 52.002 4.725 ;
     RECT  52.056 4.59 52.164 4.725 ;
     RECT  54.54 4.59 55.782 4.725 ;
     RECT  55.89 4.59 56.97 4.725 ;
     RECT  57.024 4.59 58.644 4.725 ;
     RECT  58.698 4.59 59.022 4.725 ;
     RECT  59.346 4.59 61.776 4.725 ;
     RECT  61.938 4.59 63.666 4.725 ;
     RECT  63.72 4.59 65.394 4.725 ;
     RECT  68.526 4.59 68.796 4.725 ;
     RECT  69.066 4.59 70.146 4.725 ;
     RECT  70.524 4.59 72.414 4.725 ;
     RECT  72.576 4.59 72.738 4.725 ;
     RECT  73.008 4.59 74.412 4.725 ;
     RECT  74.52 4.59 78.678 4.725 ;
     RECT  78.786 4.59 80.406 4.725 ;
     RECT  80.514 4.59 83.16 4.725 ;
     RECT  83.376 4.59 85.428 4.725 ;
     RECT  85.536 4.59 86.4 4.725 ;
     RECT  86.508 4.59 88.02 4.725 ;
     RECT  88.29 4.59 89.856 4.725 ;
     RECT  90.666 4.59 96.228 4.725 ;
     RECT  96.282 4.59 96.714 4.725 ;
     RECT  96.768 4.59 97.2 4.725 ;
     RECT  97.416 4.59 98.064 4.725 ;
     RECT  98.118 4.59 98.442 4.725 ;
     RECT  98.496 4.59 98.982 4.725 ;
     RECT  99.036 4.59 100.116 4.725 ;
     RECT  100.224 4.455 100.548 4.725 ;
     RECT  100.71 4.59 100.872 4.725 ;
     RECT  101.952 4.59 102.06 4.725 ;
     RECT  102.168 4.59 103.248 4.725 ;
     RECT  106.218 4.59 106.542 4.725 ;
     RECT  107.406 4.59 107.676 4.725 ;
     RECT  108.756 4.59 109.08 4.725 ;
     RECT  109.242 4.59 109.566 4.725 ;
     RECT  110.268 4.59 110.754 4.725 ;
     RECT  113.13 4.59 114.534 4.725 ;
     RECT  114.912 4.59 115.56 4.725 ;
     RECT  115.83 4.59 116.154 4.725 ;
     RECT  127.332 4.455 127.44 4.725 ;
     RECT  13.23 4.995 13.608 5.13 ;
     RECT  14.094 4.995 15.174 5.13 ;
     RECT  16.416 4.995 17.064 5.13 ;
     RECT  17.874 4.995 20.358 5.13 ;
     RECT  20.898 4.995 21.222 5.13 ;
     RECT  21.762 4.995 22.086 5.13 ;
     RECT  22.626 4.995 22.896 5.13 ;
     RECT  23.868 4.995 24.192 5.13 ;
     RECT  24.678 4.995 26.838 5.13 ;
     RECT  26.946 4.995 27.216 5.13 ;
     RECT  27.378 4.995 28.458 5.13 ;
     RECT  28.566 4.995 30.132 5.13 ;
     RECT  30.294 4.995 31.752 5.13 ;
     RECT  31.914 4.995 33.858 5.13 ;
     RECT  35.154 4.995 35.478 5.13 ;
     RECT  36.45 4.995 36.828 5.13 ;
     RECT  36.936 4.995 39.042 5.13 ;
     RECT  39.906 4.995 40.986 5.13 ;
     RECT  41.256 4.995 42.606 5.13 ;
     RECT  42.714 4.995 43.362 5.13 ;
     RECT  43.416 4.995 45.036 5.13 ;
     RECT  45.09 4.995 45.954 5.13 ;
     RECT  46.062 4.995 46.818 5.13 ;
     RECT  46.926 4.995 48.978 5.13 ;
     RECT  49.14 4.995 51.408 5.13 ;
     RECT  52.056 4.995 53.136 5.13 ;
     RECT  53.622 4.995 54 5.13 ;
     RECT  54.108 4.995 54.432 5.13 ;
     RECT  55.08 4.995 55.458 5.13 ;
     RECT  55.566 4.995 56.646 5.13 ;
     RECT  56.7 4.995 57.51 5.13 ;
     RECT  57.618 4.995 57.996 5.13 ;
     RECT  58.05 4.995 59.13 5.13 ;
     RECT  59.346 4.995 61.128 5.13 ;
     RECT  61.182 4.995 61.506 5.13 ;
     RECT  61.668 4.995 62.91 5.13 ;
     RECT  63.018 4.995 63.18 5.13 ;
     RECT  63.936 4.995 64.26 5.13 ;
     RECT  64.746 4.995 64.908 5.13 ;
     RECT  66.96 4.995 68.85 5.13 ;
     RECT  69.228 4.995 70.848 5.13 ;
     RECT  71.604 4.995 71.874 5.13 ;
     RECT  71.928 4.995 72.522 5.13 ;
     RECT  72.576 4.995 73.224 5.13 ;
     RECT  73.278 4.995 73.602 5.13 ;
     RECT  73.656 4.995 73.98 5.13 ;
     RECT  74.034 4.995 75.276 5.13 ;
     RECT  75.384 4.995 77.112 5.13 ;
     RECT  77.166 4.995 78.894 5.13 ;
     RECT  78.948 4.995 79.272 5.13 ;
     RECT  79.326 4.995 86.886 5.13 ;
     RECT  87.102 4.995 87.426 5.13 ;
     RECT  88.29 4.995 88.614 5.13 ;
     RECT  88.776 4.995 89.1 5.13 ;
     RECT  90.558 4.995 92.178 5.13 ;
     RECT  92.34 4.995 96.012 5.13 ;
     RECT  96.174 4.995 99.414 5.13 ;
     RECT  99.522 4.995 99.846 5.13 ;
     RECT  100.008 4.995 100.332 5.13 ;
     RECT  100.494 4.995 101.574 5.13 ;
     RECT  101.682 4.995 101.844 5.13 ;
     RECT  103.14 4.995 104.544 5.13 ;
     RECT  106.11 4.995 106.434 5.13 ;
     RECT  106.704 4.995 106.866 5.13 ;
     RECT  106.92 4.995 108.594 5.13 ;
     RECT  108.648 4.995 109.728 5.13 ;
     RECT  113.13 4.995 113.454 5.13 ;
     RECT  114.048 4.995 114.21 5.13 ;
     RECT  115.776 4.995 117.342 5.13 ;
     RECT  126.9 4.995 127.008 5.13 ;
     RECT  2.16 4.995 2.268 5.265 ;
     RECT  12.42 5.13 13.5 5.265 ;
     RECT  14.58 5.13 15.066 5.265 ;
     RECT  16.524 5.13 17.064 5.265 ;
     RECT  17.766 5.13 18.846 5.265 ;
     RECT  19.494 5.13 20.358 5.265 ;
     RECT  21.114 5.13 21.816 5.265 ;
     RECT  23.004 5.13 24.084 5.265 ;
     RECT  24.948 5.13 29.808 5.265 ;
     RECT  30.024 5.13 30.456 5.265 ;
     RECT  30.834 5.13 31.374 5.265 ;
     RECT  31.536 5.13 31.698 5.265 ;
     RECT  32.292 5.13 32.616 5.265 ;
     RECT  33.318 5.13 34.344 5.265 ;
     RECT  34.506 5.13 34.668 5.265 ;
     RECT  35.046 5.13 36.288 5.265 ;
     RECT  36.612 5.13 36.936 5.265 ;
     RECT  36.99 5.13 37.152 5.265 ;
     RECT  37.26 5.13 38.61 5.265 ;
     RECT  38.934 5.13 40.338 5.265 ;
     RECT  40.608 5.13 40.932 5.265 ;
     RECT  41.256 5.13 41.58 5.265 ;
     RECT  42.444 5.13 45.036 5.265 ;
     RECT  45.09 5.13 49.572 5.265 ;
     RECT  49.842 5.13 51.084 5.265 ;
     RECT  51.516 5.13 52.164 5.265 ;
     RECT  52.542 5.13 52.866 5.265 ;
     RECT  53.136 5.13 53.784 5.265 ;
     RECT  53.946 5.13 54.108 5.265 ;
     RECT  54.27 5.13 54.432 5.265 ;
     RECT  55.296 5.13 56.268 5.265 ;
     RECT  56.322 5.13 57.834 5.265 ;
     RECT  57.888 5.13 59.94 5.265 ;
     RECT  60.102 5.13 62.262 5.265 ;
     RECT  62.586 5.13 62.91 5.265 ;
     RECT  63.234 5.13 63.504 5.265 ;
     RECT  64.368 5.13 64.692 5.265 ;
     RECT  69.174 5.13 69.498 5.265 ;
     RECT  70.902 5.13 71.226 5.265 ;
     RECT  71.442 5.13 72.522 5.265 ;
     RECT  72.576 5.13 73.656 5.265 ;
     RECT  73.71 5.13 73.872 5.265 ;
     RECT  73.926 5.13 74.25 5.265 ;
     RECT  74.304 5.13 74.844 5.265 ;
     RECT  75.114 5.13 75.978 5.265 ;
     RECT  76.194 5.13 78.192 5.265 ;
     RECT  78.246 5.13 79.65 5.265 ;
     RECT  79.758 5.13 82.026 5.265 ;
     RECT  82.188 5.13 83.16 5.265 ;
     RECT  83.214 5.13 84.456 5.265 ;
     RECT  84.564 5.13 86.886 5.265 ;
     RECT  87.102 5.13 88.506 5.265 ;
     RECT  89.316 5.13 91.206 5.265 ;
     RECT  91.422 5.13 92.502 5.265 ;
     RECT  92.61 5.13 93.15 5.265 ;
     RECT  93.312 5.13 93.906 5.265 ;
     RECT  94.122 5.13 96.282 5.265 ;
     RECT  96.444 5.13 97.524 5.265 ;
     RECT  97.632 5.13 99.36 5.265 ;
     RECT  99.468 5.13 100.008 5.265 ;
     RECT  100.278 5.13 101.52 5.265 ;
     RECT  101.952 5.13 102.06 5.265 ;
     RECT  102.816 5.13 103.14 5.265 ;
     RECT  103.464 5.13 103.788 5.265 ;
     RECT  104.058 5.13 104.544 5.265 ;
     RECT  106.218 5.13 108.648 5.265 ;
     RECT  108.702 5.13 109.026 5.265 ;
     RECT  109.296 5.13 109.782 5.265 ;
     RECT  110.106 5.13 110.538 5.265 ;
     RECT  110.7 5.13 110.862 5.265 ;
     RECT  111.294 5.13 111.618 5.265 ;
     RECT  113.346 5.13 113.67 5.265 ;
     RECT  117.018 5.13 117.288 5.265 ;
     RECT  127.332 4.995 127.44 5.265 ;
     RECT  13.284 5.535 13.77 5.67 ;
     RECT  14.04 5.535 14.31 5.67 ;
     RECT  14.634 5.535 14.958 5.67 ;
     RECT  15.282 5.535 15.552 5.67 ;
     RECT  15.714 5.535 16.956 5.67 ;
     RECT  17.01 5.535 17.334 5.67 ;
     RECT  18.954 5.535 19.116 5.67 ;
     RECT  20.898 5.535 21.168 5.67 ;
     RECT  21.6 5.535 21.924 5.67 ;
     RECT  23.598 5.535 24.462 5.67 ;
     RECT  25.866 5.535 27.216 5.67 ;
     RECT  27.27 5.535 28.08 5.67 ;
     RECT  28.134 5.535 28.566 5.67 ;
     RECT  28.62 5.535 29.484 5.67 ;
     RECT  29.538 5.535 31.59 5.67 ;
     RECT  31.752 5.535 35.532 5.67 ;
     RECT  36.234 5.535 37.746 5.67 ;
     RECT  37.854 5.535 38.556 5.67 ;
     RECT  38.718 5.535 39.258 5.67 ;
     RECT  39.96 5.535 40.122 5.67 ;
     RECT  40.23 5.535 41.04 5.67 ;
     RECT  41.526 5.535 42.768 5.67 ;
     RECT  43.092 5.535 43.902 5.67 ;
     RECT  44.01 5.535 44.442 5.67 ;
     RECT  44.712 5.535 45.63 5.67 ;
     RECT  45.792 5.535 46.116 5.67 ;
     RECT  46.17 5.535 49.896 5.67 ;
     RECT  49.95 5.535 50.976 5.67 ;
     RECT  52.542 5.535 52.92 5.67 ;
     RECT  53.082 5.535 54.324 5.67 ;
     RECT  54.54 5.535 55.782 5.67 ;
     RECT  56.484 5.535 57.726 5.67 ;
     RECT  57.888 5.535 59.076 5.67 ;
     RECT  59.13 5.535 60.426 5.67 ;
     RECT  60.48 5.535 61.236 5.67 ;
     RECT  61.506 5.535 61.992 5.67 ;
     RECT  62.316 5.535 62.64 5.67 ;
     RECT  62.856 5.535 63.18 5.67 ;
     RECT  64.044 5.535 64.314 5.67 ;
     RECT  64.368 5.535 65.448 5.67 ;
     RECT  66.798 5.535 67.878 5.67 ;
     RECT  68.418 5.535 68.742 5.67 ;
     RECT  69.228 5.535 69.498 5.67 ;
     RECT  70.74 5.535 71.226 5.67 ;
     RECT  71.28 5.535 73.98 5.67 ;
     RECT  74.034 5.535 75.654 5.67 ;
     RECT  75.708 5.535 76.572 5.67 ;
     RECT  76.626 5.535 79.65 5.67 ;
     RECT  79.704 5.535 80.622 5.67 ;
     RECT  80.676 5.535 81.162 5.67 ;
     RECT  81.324 5.535 82.188 5.67 ;
     RECT  82.404 5.535 83.16 5.67 ;
     RECT  83.376 5.535 84.618 5.67 ;
     RECT  84.834 5.535 87.264 5.67 ;
     RECT  87.966 5.535 89.694 5.67 ;
     RECT  89.802 5.535 90.126 5.67 ;
     RECT  90.774 5.535 91.098 5.67 ;
     RECT  91.314 5.535 93.582 5.67 ;
     RECT  93.636 5.535 97.578 5.67 ;
     RECT  97.632 5.535 99.792 5.67 ;
     RECT  99.954 5.535 100.116 5.67 ;
     RECT  100.71 5.535 101.79 5.67 ;
     RECT  102.762 5.535 104.004 5.67 ;
     RECT  106.542 5.535 107.19 5.67 ;
     RECT  108.054 5.535 108.54 5.67 ;
     RECT  110.106 5.535 112.266 5.67 ;
     RECT  112.32 5.535 112.644 5.67 ;
     RECT  112.752 5.535 113.4 5.67 ;
     RECT  113.886 5.535 114.048 5.67 ;
     RECT  114.75 5.535 115.074 5.67 ;
     RECT  115.344 5.535 115.668 5.67 ;
     RECT  126.9 5.535 127.008 5.67 ;
     RECT  2.16 5.535 2.268 5.805 ;
     RECT  12.312 5.67 13.5 5.805 ;
     RECT  14.688 5.67 15.39 5.805 ;
     RECT  17.712 5.67 17.982 5.805 ;
     RECT  19.818 5.67 20.088 5.805 ;
     RECT  20.736 5.67 21.978 5.805 ;
     RECT  22.734 5.67 23.436 5.805 ;
     RECT  23.544 5.67 23.706 5.805 ;
     RECT  26.028 5.67 26.352 5.805 ;
     RECT  26.676 5.67 28.296 5.805 ;
     RECT  28.404 5.67 30.348 5.805 ;
     RECT  30.672 5.67 31.212 5.805 ;
     RECT  31.536 5.67 31.698 5.805 ;
     RECT  31.968 5.67 32.4 5.805 ;
     RECT  32.886 5.67 33.21 5.805 ;
     RECT  33.264 5.67 33.588 5.805 ;
     RECT  35.046 5.67 35.532 5.805 ;
     RECT  36.396 5.67 37.476 5.805 ;
     RECT  37.53 5.67 38.448 5.805 ;
     RECT  38.502 5.67 40.122 5.805 ;
     RECT  41.148 5.67 42.228 5.805 ;
     RECT  42.876 5.67 46.116 5.805 ;
     RECT  46.224 5.67 47.034 5.805 ;
     RECT  47.196 5.67 48.6 5.805 ;
     RECT  48.708 5.67 49.842 5.805 ;
     RECT  50.004 5.67 50.544 5.805 ;
     RECT  50.652 5.67 52.164 5.805 ;
     RECT  52.218 5.67 52.542 5.805 ;
     RECT  52.866 5.67 53.19 5.805 ;
     RECT  53.46 5.67 53.784 5.805 ;
     RECT  53.838 5.67 54.918 5.805 ;
     RECT  55.728 5.67 56.538 5.805 ;
     RECT  56.646 5.67 57.078 5.805 ;
     RECT  57.24 5.67 57.564 5.805 ;
     RECT  57.726 5.67 58.266 5.805 ;
     RECT  58.428 5.67 59.292 5.805 ;
     RECT  59.4 5.67 60.264 5.805 ;
     RECT  60.534 5.67 61.29 5.805 ;
     RECT  61.56 5.67 63.72 5.805 ;
     RECT  64.044 5.67 64.692 5.805 ;
     RECT  65.07 5.67 65.232 5.805 ;
     RECT  67.446 5.67 67.608 5.805 ;
     RECT  67.77 5.67 68.094 5.805 ;
     RECT  68.202 5.67 70.848 5.805 ;
     RECT  71.334 5.67 71.982 5.805 ;
     RECT  72.036 5.67 74.52 5.805 ;
     RECT  74.574 5.67 76.572 5.805 ;
     RECT  76.68 5.67 77.598 5.805 ;
     RECT  77.652 5.67 80.244 5.805 ;
     RECT  80.352 5.67 81.216 5.805 ;
     RECT  81.324 5.67 83.322 5.805 ;
     RECT  83.484 5.67 84.024 5.805 ;
     RECT  84.078 5.67 85.482 5.805 ;
     RECT  85.536 5.67 85.968 5.805 ;
     RECT  86.184 5.67 86.724 5.805 ;
     RECT  86.778 5.67 87.426 5.805 ;
     RECT  87.642 5.67 89.046 5.805 ;
     RECT  90.504 5.67 92.772 5.805 ;
     RECT  92.934 5.67 94.014 5.805 ;
     RECT  94.122 5.67 94.662 5.805 ;
     RECT  94.716 5.67 94.986 5.805 ;
     RECT  95.04 5.67 98.928 5.805 ;
     RECT  99.036 5.67 99.36 5.805 ;
     RECT  99.414 5.67 100.17 5.805 ;
     RECT  100.278 5.67 100.602 5.805 ;
     RECT  100.71 5.67 100.872 5.805 ;
     RECT  101.682 5.67 102.06 5.805 ;
     RECT  102.654 5.67 102.924 5.805 ;
     RECT  105.192 5.67 105.462 5.805 ;
     RECT  106.326 5.67 107.406 5.805 ;
     RECT  108.54 5.67 109.62 5.805 ;
     RECT  109.944 5.67 110.592 5.805 ;
     RECT  111.24 5.67 111.564 5.805 ;
     RECT  111.618 5.67 111.78 5.805 ;
     RECT  112.266 5.67 112.59 5.805 ;
     RECT  112.86 5.67 115.074 5.805 ;
     RECT  115.236 5.67 115.83 5.805 ;
     RECT  127.332 5.535 127.44 5.805 ;
     RECT  13.932 6.075 15.174 6.21 ;
     RECT  16.146 6.075 16.416 6.21 ;
     RECT  19.494 6.075 21.924 6.21 ;
     RECT  22.572 6.075 23.652 6.21 ;
     RECT  23.976 6.075 24.624 6.21 ;
     RECT  25.11 6.075 25.434 6.21 ;
     RECT  26.028 6.075 29.106 6.21 ;
     RECT  29.16 6.075 29.484 6.21 ;
     RECT  29.592 6.075 30.024 6.21 ;
     RECT  30.24 6.075 31.428 6.21 ;
     RECT  31.59 6.075 32.022 6.21 ;
     RECT  32.4 6.075 33.102 6.21 ;
     RECT  33.264 6.075 33.426 6.21 ;
     RECT  33.534 6.075 34.614 6.21 ;
     RECT  36.342 6.075 36.72 6.21 ;
     RECT  36.774 6.075 37.206 6.21 ;
     RECT  37.26 6.075 38.07 6.21 ;
     RECT  38.232 6.075 39.852 6.21 ;
     RECT  39.96 6.075 41.04 6.21 ;
     RECT  41.202 6.075 41.58 6.21 ;
     RECT  41.634 6.075 41.958 6.21 ;
     RECT  42.12 6.075 42.282 6.21 ;
     RECT  42.444 6.075 42.768 6.21 ;
     RECT  42.822 6.075 43.686 6.21 ;
     RECT  43.74 6.075 43.902 6.21 ;
     RECT  43.956 6.075 44.28 6.21 ;
     RECT  44.334 6.075 44.874 6.21 ;
     RECT  44.928 6.075 46.008 6.21 ;
     RECT  46.062 6.075 46.926 6.21 ;
     RECT  46.98 6.075 47.304 6.21 ;
     RECT  47.412 6.075 47.952 6.21 ;
     RECT  48.006 6.075 48.87 6.21 ;
     RECT  49.032 6.075 50.004 6.21 ;
     RECT  50.112 6.075 51.408 6.21 ;
     RECT  51.516 6.075 51.948 6.21 ;
     RECT  52.272 6.075 52.596 6.21 ;
     RECT  52.65 6.075 54.054 6.21 ;
     RECT  54.27 6.075 54.648 6.21 ;
     RECT  54.918 6.075 57.51 6.21 ;
     RECT  57.726 6.075 58.266 6.21 ;
     RECT  58.32 6.075 61.992 6.21 ;
     RECT  62.1 6.075 62.262 6.21 ;
     RECT  62.748 6.075 63.072 6.21 ;
     RECT  63.612 6.075 63.774 6.21 ;
     RECT  63.828 6.075 64.908 6.21 ;
     RECT  66.744 6.075 68.148 6.21 ;
     RECT  69.822 6.075 70.146 6.21 ;
     RECT  70.254 6.075 71.874 6.21 ;
     RECT  71.982 6.075 72.306 6.21 ;
     RECT  72.36 6.075 72.522 6.21 ;
     RECT  72.576 6.075 74.034 6.21 ;
     RECT  74.088 6.075 74.52 6.21 ;
     RECT  74.682 6.075 75.222 6.21 ;
     RECT  75.384 6.075 75.924 6.21 ;
     RECT  75.978 6.075 76.95 6.21 ;
     RECT  77.004 6.075 80.406 6.21 ;
     RECT  80.514 6.075 81.702 6.21 ;
     RECT  82.08 6.075 83.484 6.21 ;
     RECT  83.538 6.075 84.402 6.21 ;
     RECT  84.456 6.075 84.834 6.21 ;
     RECT  84.996 6.075 85.32 6.21 ;
     RECT  85.374 6.075 86.13 6.21 ;
     RECT  86.292 6.075 87.156 6.21 ;
     RECT  87.48 6.075 87.642 6.21 ;
     RECT  87.858 6.075 88.182 6.21 ;
     RECT  88.614 6.075 89.1 6.21 ;
     RECT  89.262 6.075 90.504 6.21 ;
     RECT  90.72 6.075 91.044 6.21 ;
     RECT  91.098 6.075 91.854 6.21 ;
     RECT  92.124 6.075 93.582 6.21 ;
     RECT  93.636 6.075 95.796 6.21 ;
     RECT  95.904 6.075 97.47 6.21 ;
     RECT  97.524 6.075 99.576 6.21 ;
     RECT  99.63 6.075 99.792 6.21 ;
     RECT  99.846 6.075 100.602 6.21 ;
     RECT  100.71 6.075 101.358 6.21 ;
     RECT  101.52 6.075 101.952 6.21 ;
     RECT  102.33 6.075 102.654 6.21 ;
     RECT  104.814 6.075 105.138 6.21 ;
     RECT  105.894 6.075 106.218 6.21 ;
     RECT  106.38 6.075 108.81 6.21 ;
     RECT  109.08 6.075 109.242 6.21 ;
     RECT  109.782 6.075 110.052 6.21 ;
     RECT  110.97 6.075 111.294 6.21 ;
     RECT  112.32 6.075 114.642 6.21 ;
     RECT  114.804 6.075 116.208 6.21 ;
     RECT  126.9 6.075 127.008 6.21 ;
     RECT  2.16 6.075 2.268 6.345 ;
     RECT  12.366 6.21 13.77 6.345 ;
     RECT  14.202 6.21 14.796 6.345 ;
     RECT  15.12 6.21 15.498 6.345 ;
     RECT  15.93 6.21 17.01 6.345 ;
     RECT  17.226 6.21 17.604 6.345 ;
     RECT  17.928 6.21 18.198 6.345 ;
     RECT  19.116 6.21 19.602 6.345 ;
     RECT  19.926 6.21 20.25 6.345 ;
     RECT  20.358 6.21 20.52 6.345 ;
     RECT  21.276 6.21 22.14 6.345 ;
     RECT  23.166 6.21 24.408 6.345 ;
     RECT  24.516 6.21 25.596 6.345 ;
     RECT  26.46 6.21 27.54 6.345 ;
     RECT  27.594 6.21 28.998 6.345 ;
     RECT  29.268 6.21 29.646 6.345 ;
     RECT  29.754 6.21 30.078 6.345 ;
     RECT  30.186 6.21 30.51 6.345 ;
     RECT  30.618 6.21 31.428 6.345 ;
     RECT  31.536 6.21 32.076 6.345 ;
     RECT  32.184 6.21 33.858 6.345 ;
     RECT  35.91 6.21 36.99 6.345 ;
     RECT  37.314 6.21 38.718 6.345 ;
     RECT  38.826 6.21 39.582 6.345 ;
     RECT  39.636 6.21 40.824 6.345 ;
     RECT  40.932 6.21 41.094 6.345 ;
     RECT  42.498 6.21 42.822 6.345 ;
     RECT  42.876 6.21 45.576 6.345 ;
     RECT  45.738 6.21 46.602 6.345 ;
     RECT  46.71 6.21 47.25 6.345 ;
     RECT  47.304 6.21 49.464 6.345 ;
     RECT  49.518 6.21 50.382 6.345 ;
     RECT  50.436 6.21 50.868 6.345 ;
     RECT  50.922 6.21 51.354 6.345 ;
     RECT  51.408 6.21 51.84 6.345 ;
     RECT  52.056 6.21 52.164 6.345 ;
     RECT  52.272 6.21 54.162 6.345 ;
     RECT  54.432 6.21 54.756 6.345 ;
     RECT  54.81 6.21 55.35 6.345 ;
     RECT  55.404 6.21 55.728 6.345 ;
     RECT  55.782 6.21 55.944 6.345 ;
     RECT  55.998 6.21 56.862 6.345 ;
     RECT  56.916 6.21 57.348 6.345 ;
     RECT  57.402 6.21 58.158 6.345 ;
     RECT  58.212 6.21 59.292 6.345 ;
     RECT  59.346 6.21 60.426 6.345 ;
     RECT  60.696 6.21 61.884 6.345 ;
     RECT  62.37 6.21 62.694 6.345 ;
     RECT  64.044 6.21 64.368 6.345 ;
     RECT  64.422 6.21 64.908 6.345 ;
     RECT  66.798 6.21 68.418 6.345 ;
     RECT  69.174 6.21 70.308 6.345 ;
     RECT  71.01 6.21 74.898 6.345 ;
     RECT  75.114 6.21 75.546 6.345 ;
     RECT  75.6 6.21 77.598 6.345 ;
     RECT  77.706 6.21 79.326 6.345 ;
     RECT  79.434 6.21 80.298 6.345 ;
     RECT  80.352 6.21 81.27 6.345 ;
     RECT  81.432 6.21 84.672 6.345 ;
     RECT  84.726 6.21 85.482 6.345 ;
     RECT  85.536 6.21 85.86 6.345 ;
     RECT  85.968 6.21 86.508 6.345 ;
     RECT  86.562 6.21 88.182 6.345 ;
     RECT  88.452 6.21 90.018 6.345 ;
     RECT  90.504 6.21 90.828 6.345 ;
     RECT  90.936 6.21 91.098 6.345 ;
     RECT  91.206 6.21 93.474 6.345 ;
     RECT  93.744 6.21 94.284 6.345 ;
     RECT  94.338 6.21 94.662 6.345 ;
     RECT  94.716 6.21 95.904 6.345 ;
     RECT  95.958 6.21 96.822 6.345 ;
     RECT  96.93 6.21 97.794 6.345 ;
     RECT  97.848 6.21 98.712 6.345 ;
     RECT  98.766 6.21 99.954 6.345 ;
     RECT  100.224 6.21 101.466 6.345 ;
     RECT  101.52 6.21 101.79 6.345 ;
     RECT  101.952 6.21 102.06 6.345 ;
     RECT  102.222 6.21 102.546 6.345 ;
     RECT  102.6 6.21 103.68 6.345 ;
     RECT  104.652 6.21 106.218 6.345 ;
     RECT  106.92 6.21 107.244 6.345 ;
     RECT  107.514 6.21 107.784 6.345 ;
     RECT  108.324 6.21 108.972 6.345 ;
     RECT  110.808 6.21 111.132 6.345 ;
     RECT  111.51 6.21 111.834 6.345 ;
     RECT  114.534 6.21 114.858 6.345 ;
     RECT  115.02 6.21 116.1 6.345 ;
     RECT  127.332 6.075 127.44 6.345 ;
     RECT  2.376 6.615 2.646 6.75 ;
     RECT  13.284 6.615 13.446 6.75 ;
     RECT  13.5 6.615 14.202 6.75 ;
     RECT  15.12 6.615 15.822 6.75 ;
     RECT  15.984 6.615 17.55 6.75 ;
     RECT  17.82 6.615 18.144 6.75 ;
     RECT  18.306 6.615 19.386 6.75 ;
     RECT  19.44 6.615 20.52 6.75 ;
     RECT  20.628 6.615 21.87 6.75 ;
     RECT  23.868 6.615 24.192 6.75 ;
     RECT  24.408 6.615 24.732 6.75 ;
     RECT  25.164 6.615 25.65 6.75 ;
     RECT  25.866 6.615 26.298 6.75 ;
     RECT  26.676 6.615 27 6.75 ;
     RECT  27.108 6.615 27.216 6.75 ;
     RECT  27.324 6.615 28.026 6.75 ;
     RECT  28.08 6.615 28.674 6.75 ;
     RECT  28.728 6.615 30.024 6.75 ;
     RECT  30.24 6.615 31.752 6.75 ;
     RECT  31.968 6.615 32.508 6.75 ;
     RECT  32.94 6.615 33.264 6.75 ;
     RECT  34.02 6.615 34.398 6.75 ;
     RECT  35.262 6.615 35.964 6.75 ;
     RECT  36.234 6.615 36.612 6.75 ;
     RECT  36.828 6.615 38.016 6.75 ;
     RECT  38.286 6.615 39.582 6.75 ;
     RECT  41.58 6.615 44.928 6.75 ;
     RECT  45.09 6.615 46.656 6.75 ;
     RECT  46.818 6.615 47.358 6.75 ;
     RECT  47.466 6.615 49.302 6.75 ;
     RECT  49.464 6.615 50.004 6.75 ;
     RECT  50.112 6.615 50.544 6.75 ;
     RECT  50.868 6.615 51.948 6.75 ;
     RECT  52.002 6.615 52.164 6.75 ;
     RECT  53.352 6.615 54.594 6.75 ;
     RECT  55.296 6.615 55.674 6.75 ;
     RECT  55.836 6.615 56.268 6.75 ;
     RECT  56.484 6.615 57.024 6.75 ;
     RECT  57.24 6.615 57.672 6.75 ;
     RECT  57.888 6.615 58.698 6.75 ;
     RECT  58.752 6.615 59.616 6.75 ;
     RECT  59.724 6.615 63.396 6.75 ;
     RECT  63.936 6.615 65.556 6.75 ;
     RECT  68.31 6.615 69.552 6.75 ;
     RECT  69.768 6.615 71.388 6.75 ;
     RECT  71.442 6.615 71.766 6.75 ;
     RECT  71.82 6.615 72.252 6.75 ;
     RECT  72.306 6.615 72.63 6.75 ;
     RECT  72.684 6.615 73.116 6.75 ;
     RECT  73.17 6.615 74.034 6.75 ;
     RECT  74.142 6.615 74.304 6.75 ;
     RECT  74.412 6.615 76.896 6.75 ;
     RECT  77.004 6.615 77.652 6.75 ;
     RECT  77.76 6.615 78.462 6.75 ;
     RECT  78.732 6.615 82.458 6.75 ;
     RECT  82.512 6.615 84.51 6.75 ;
     RECT  84.618 6.615 84.996 6.75 ;
     RECT  85.212 6.615 85.644 6.75 ;
     RECT  85.698 6.615 86.13 6.75 ;
     RECT  86.184 6.615 87.048 6.75 ;
     RECT  87.912 6.615 88.56 6.75 ;
     RECT  90.45 6.615 90.882 6.75 ;
     RECT  91.098 6.615 93.042 6.75 ;
     RECT  93.204 6.615 93.636 6.75 ;
     RECT  93.852 6.615 96.336 6.75 ;
     RECT  96.39 6.615 96.984 6.75 ;
     RECT  97.2 6.615 98.928 6.75 ;
     RECT  98.982 6.615 100.062 6.75 ;
     RECT  100.764 6.615 102.114 6.75 ;
     RECT  102.33 6.615 104.058 6.75 ;
     RECT  104.436 6.615 104.76 6.75 ;
     RECT  105.894 6.615 107.136 6.75 ;
     RECT  107.784 6.615 107.946 6.75 ;
     RECT  110.916 6.615 112.158 6.75 ;
     RECT  112.266 6.615 112.428 6.75 ;
     RECT  112.698 6.615 113.022 6.75 ;
     RECT  113.4 6.615 113.67 6.75 ;
     RECT  114.372 6.615 115.938 6.75 ;
     RECT  117.558 6.615 118.746 6.75 ;
     RECT  126.9 6.615 127.008 6.75 ;
     RECT  2.16 6.615 2.268 6.885 ;
     RECT  12.852 6.75 13.122 6.885 ;
     RECT  13.77 6.75 14.094 6.885 ;
     RECT  14.202 6.75 16.524 6.885 ;
     RECT  16.686 6.75 17.766 6.885 ;
     RECT  17.874 6.75 18.198 6.885 ;
     RECT  18.576 6.75 19.386 6.885 ;
     RECT  22.788 6.75 24.03 6.885 ;
     RECT  25.542 6.75 26.73 6.885 ;
     RECT  26.838 6.75 27.27 6.885 ;
     RECT  27.324 6.75 27.81 6.885 ;
     RECT  27.864 6.75 28.836 6.885 ;
     RECT  28.944 6.75 29.268 6.885 ;
     RECT  29.484 6.75 31.428 6.885 ;
     RECT  31.59 6.75 32.022 6.885 ;
     RECT  32.616 6.75 33.102 6.885 ;
     RECT  33.264 6.75 33.696 6.885 ;
     RECT  34.02 6.75 34.344 6.885 ;
     RECT  34.452 6.75 35.694 6.885 ;
     RECT  36.396 6.75 37.206 6.885 ;
     RECT  37.26 6.75 37.854 6.885 ;
     RECT  37.908 6.75 38.448 6.885 ;
     RECT  38.556 6.75 38.934 6.885 ;
     RECT  38.988 6.75 39.366 6.885 ;
     RECT  40.068 6.75 40.5 6.885 ;
     RECT  40.986 6.75 42.066 6.885 ;
     RECT  42.12 6.75 42.552 6.885 ;
     RECT  42.768 6.75 43.848 6.885 ;
     RECT  43.956 6.75 44.82 6.885 ;
     RECT  44.874 6.75 48.384 6.885 ;
     RECT  48.762 6.75 50.814 6.885 ;
     RECT  50.976 6.75 51.408 6.885 ;
     RECT  52.056 6.75 52.164 6.885 ;
     RECT  52.704 6.75 53.136 6.885 ;
     RECT  54.27 6.75 54.648 6.885 ;
     RECT  55.296 6.75 57.294 6.885 ;
     RECT  57.564 6.75 58.104 6.885 ;
     RECT  58.158 6.75 58.86 6.885 ;
     RECT  58.914 6.75 59.346 6.885 ;
     RECT  59.4 6.75 59.562 6.885 ;
     RECT  59.616 6.75 60.966 6.885 ;
     RECT  61.02 6.75 62.424 6.885 ;
     RECT  63.234 6.75 63.936 6.885 ;
     RECT  64.098 6.75 64.422 6.885 ;
     RECT  64.476 6.75 64.962 6.885 ;
     RECT  68.58 6.75 68.904 6.885 ;
     RECT  69.174 6.75 69.444 6.885 ;
     RECT  70.416 6.75 71.064 6.885 ;
     RECT  71.118 6.75 71.28 6.885 ;
     RECT  71.604 6.75 72.414 6.885 ;
     RECT  72.684 6.75 73.386 6.885 ;
     RECT  73.44 6.75 80.73 6.885 ;
     RECT  80.784 6.75 83.106 6.885 ;
     RECT  83.16 6.75 83.862 6.885 ;
     RECT  83.97 6.75 84.834 6.885 ;
     RECT  84.996 6.75 85.698 6.885 ;
     RECT  85.914 6.75 86.076 6.885 ;
     RECT  86.13 6.75 87.102 6.885 ;
     RECT  87.264 6.75 87.804 6.885 ;
     RECT  87.966 6.75 88.776 6.885 ;
     RECT  89.37 6.75 89.694 6.885 ;
     RECT  89.964 6.75 90.288 6.885 ;
     RECT  90.936 6.75 92.34 6.885 ;
     RECT  92.448 6.75 94.824 6.885 ;
     RECT  94.932 6.75 95.472 6.885 ;
     RECT  95.526 6.75 96.606 6.885 ;
     RECT  96.66 6.75 97.092 6.885 ;
     RECT  97.308 6.75 98.604 6.885 ;
     RECT  98.82 6.75 99.252 6.885 ;
     RECT  99.36 6.75 99.792 6.885 ;
     RECT  100.332 6.75 100.764 6.885 ;
     RECT  101.25 6.75 101.682 6.885 ;
     RECT  101.952 6.75 102.06 6.885 ;
     RECT  102.114 6.75 102.438 6.885 ;
     RECT  102.654 6.75 102.978 6.885 ;
     RECT  103.194 6.75 103.356 6.885 ;
     RECT  103.518 6.75 103.68 6.885 ;
     RECT  106.704 6.75 106.974 6.885 ;
     RECT  107.298 6.75 107.622 6.885 ;
     RECT  111.402 6.75 113.13 6.885 ;
     RECT  113.4 6.75 113.724 6.885 ;
     RECT  119.88 6.75 120.96 6.885 ;
     RECT  121.716 6.75 122.04 6.885 ;
     RECT  122.418 6.75 123.822 6.885 ;
     RECT  127.332 6.615 127.44 6.885 ;
     RECT  13.338 7.155 13.662 7.29 ;
     RECT  13.932 7.155 15.174 7.29 ;
     RECT  15.498 7.155 15.822 7.29 ;
     RECT  16.47 7.155 16.632 7.29 ;
     RECT  17.388 7.155 17.874 7.29 ;
     RECT  19.116 7.155 20.196 7.29 ;
     RECT  20.844 7.155 21.168 7.29 ;
     RECT  22.356 7.155 23.976 7.29 ;
     RECT  25.272 7.155 26.352 7.29 ;
     RECT  27.108 7.155 30.348 7.29 ;
     RECT  30.564 7.155 31.428 7.29 ;
     RECT  31.914 7.155 32.886 7.29 ;
     RECT  33.048 7.155 33.426 7.29 ;
     RECT  33.642 7.155 34.884 7.29 ;
     RECT  35.208 7.155 35.586 7.29 ;
     RECT  35.964 7.155 36.774 7.29 ;
     RECT  36.936 7.155 37.746 7.29 ;
     RECT  37.8 7.155 38.664 7.29 ;
     RECT  38.718 7.155 39.042 7.29 ;
     RECT  39.096 7.155 40.014 7.29 ;
     RECT  40.392 7.155 41.04 7.29 ;
     RECT  41.202 7.155 41.85 7.29 ;
     RECT  41.958 7.155 42.12 7.29 ;
     RECT  42.606 7.155 43.254 7.29 ;
     RECT  43.362 7.155 43.956 7.29 ;
     RECT  44.064 7.155 44.82 7.29 ;
     RECT  44.874 7.155 45.252 7.29 ;
     RECT  45.36 7.155 45.792 7.29 ;
     RECT  45.846 7.155 46.224 7.29 ;
     RECT  46.602 7.155 47.142 7.29 ;
     RECT  47.196 7.155 47.52 7.29 ;
     RECT  47.682 7.155 48.114 7.29 ;
     RECT  48.168 7.155 48.492 7.29 ;
     RECT  48.546 7.155 49.41 7.29 ;
     RECT  49.464 7.155 50.652 7.29 ;
     RECT  50.814 7.155 51.192 7.29 ;
     RECT  51.246 7.155 51.624 7.29 ;
     RECT  51.678 7.155 52.002 7.29 ;
     RECT  52.11 7.155 52.488 7.29 ;
     RECT  53.838 7.155 54.162 7.29 ;
     RECT  54.486 7.155 55.35 7.29 ;
     RECT  55.404 7.155 56.268 7.29 ;
     RECT  56.322 7.155 56.7 7.29 ;
     RECT  56.754 7.155 57.078 7.29 ;
     RECT  57.132 7.155 58.266 7.29 ;
     RECT  58.32 7.155 59.778 7.29 ;
     RECT  59.832 7.155 60.21 7.29 ;
     RECT  60.264 7.155 60.642 7.29 ;
     RECT  60.696 7.155 60.858 7.29 ;
     RECT  60.912 7.155 61.992 7.29 ;
     RECT  62.046 7.155 63.126 7.29 ;
     RECT  63.18 7.155 63.504 7.29 ;
     RECT  63.828 7.155 64.908 7.29 ;
     RECT  68.58 7.155 68.904 7.29 ;
     RECT  69.498 7.155 69.984 7.29 ;
     RECT  70.2 7.155 71.712 7.29 ;
     RECT  71.766 7.155 72.846 7.29 ;
     RECT  72.9 7.155 75.978 7.29 ;
     RECT  76.032 7.155 78.192 7.29 ;
     RECT  78.246 7.155 79.65 7.29 ;
     RECT  79.704 7.155 82.998 7.29 ;
     RECT  83.052 7.155 84.402 7.29 ;
     RECT  84.51 7.155 86.562 7.29 ;
     RECT  86.67 7.155 86.994 7.29 ;
     RECT  87.048 7.155 88.128 7.29 ;
     RECT  88.182 7.155 89.262 7.29 ;
     RECT  89.37 7.155 91.26 7.29 ;
     RECT  91.476 7.155 92.124 7.29 ;
     RECT  92.34 7.155 93.312 7.29 ;
     RECT  93.42 7.155 94.392 7.29 ;
     RECT  94.608 7.155 95.364 7.29 ;
     RECT  95.688 7.155 97.146 7.29 ;
     RECT  97.2 7.155 98.01 7.29 ;
     RECT  98.064 7.155 98.712 7.29 ;
     RECT  98.928 7.155 99.306 7.29 ;
     RECT  99.36 7.155 99.792 7.29 ;
     RECT  100.17 7.155 100.98 7.29 ;
     RECT  101.196 7.155 101.628 7.29 ;
     RECT  101.736 7.155 102.06 7.29 ;
     RECT  102.276 7.155 102.6 7.29 ;
     RECT  107.19 7.155 108.432 7.29 ;
     RECT  108.972 7.155 110.052 7.29 ;
     RECT  112.59 7.155 114.156 7.29 ;
     RECT  119.718 7.155 120.366 7.29 ;
     RECT  120.852 7.155 121.014 7.29 ;
     RECT  122.31 7.155 122.796 7.29 ;
     RECT  126.9 7.155 127.008 7.29 ;
     RECT  2.16 7.155 2.268 7.425 ;
     RECT  12.69 7.29 13.014 7.425 ;
     RECT  13.122 7.29 13.446 7.425 ;
     RECT  13.716 7.29 15.174 7.425 ;
     RECT  15.66 7.29 17.712 7.425 ;
     RECT  17.766 7.29 17.928 7.425 ;
     RECT  18.954 7.29 19.278 7.425 ;
     RECT  19.332 7.29 21.114 7.425 ;
     RECT  21.546 7.29 23.706 7.425 ;
     RECT  23.976 7.29 24.3 7.425 ;
     RECT  24.462 7.29 24.786 7.425 ;
     RECT  25.704 7.29 26.028 7.425 ;
     RECT  26.19 7.29 26.352 7.425 ;
     RECT  26.568 7.29 28.836 7.425 ;
     RECT  28.89 7.29 29.7 7.425 ;
     RECT  29.754 7.29 30.294 7.425 ;
     RECT  30.402 7.29 30.834 7.425 ;
     RECT  31.104 7.29 31.428 7.425 ;
     RECT  31.482 7.29 31.914 7.425 ;
     RECT  32.184 7.29 33.264 7.425 ;
     RECT  33.318 7.29 33.642 7.425 ;
     RECT  34.776 7.29 36.018 7.425 ;
     RECT  36.126 7.29 37.638 7.425 ;
     RECT  37.692 7.29 38.124 7.425 ;
     RECT  38.232 7.29 38.556 7.425 ;
     RECT  38.664 7.29 38.988 7.425 ;
     RECT  39.15 7.29 40.014 7.425 ;
     RECT  40.23 7.29 41.472 7.425 ;
     RECT  41.958 7.29 43.902 7.425 ;
     RECT  44.01 7.29 44.874 7.425 ;
     RECT  45.09 7.29 47.682 7.425 ;
     RECT  47.79 7.29 48.222 7.425 ;
     RECT  48.276 7.29 48.708 7.425 ;
     RECT  48.762 7.29 49.086 7.425 ;
     RECT  49.194 7.29 50.058 7.425 ;
     RECT  50.112 7.29 50.436 7.425 ;
     RECT  50.49 7.29 51.03 7.425 ;
     RECT  51.084 7.29 51.462 7.425 ;
     RECT  51.516 7.29 52.164 7.425 ;
     RECT  52.218 7.29 53.838 7.425 ;
     RECT  54.378 7.29 55.62 7.425 ;
     RECT  55.728 7.29 58.32 7.425 ;
     RECT  58.428 7.29 59.346 7.425 ;
     RECT  59.508 7.29 61.02 7.425 ;
     RECT  61.074 7.29 61.506 7.425 ;
     RECT  61.56 7.29 62.424 7.425 ;
     RECT  62.478 7.29 64.044 7.425 ;
     RECT  64.152 7.29 64.638 7.425 ;
     RECT  68.31 7.29 69.39 7.425 ;
     RECT  69.498 7.29 69.822 7.425 ;
     RECT  70.74 7.29 71.172 7.425 ;
     RECT  71.604 7.29 72.036 7.425 ;
     RECT  72.09 7.29 75.168 7.425 ;
     RECT  75.276 7.29 75.708 7.425 ;
     RECT  75.816 7.29 76.356 7.425 ;
     RECT  76.41 7.29 77.814 7.425 ;
     RECT  77.922 7.29 81.432 7.425 ;
     RECT  81.486 7.29 82.566 7.425 ;
     RECT  82.62 7.29 83.052 7.425 ;
     RECT  83.16 7.29 84.024 7.425 ;
     RECT  84.078 7.29 84.618 7.425 ;
     RECT  84.726 7.29 86.4 7.425 ;
     RECT  86.454 7.29 86.886 7.425 ;
     RECT  87.21 7.29 88.074 7.425 ;
     RECT  88.452 7.29 88.614 7.425 ;
     RECT  89.37 7.29 90.45 7.425 ;
     RECT  90.828 7.29 91.152 7.425 ;
     RECT  91.476 7.29 93.096 7.425 ;
     RECT  93.204 7.29 96.768 7.425 ;
     RECT  96.822 7.29 97.74 7.425 ;
     RECT  97.848 7.29 98.172 7.425 ;
     RECT  98.442 7.29 102.384 7.425 ;
     RECT  102.87 7.29 104.76 7.425 ;
     RECT  105.3 7.29 105.624 7.425 ;
     RECT  106.704 7.29 108.108 7.425 ;
     RECT  108.324 7.29 108.648 7.425 ;
     RECT  109.242 7.29 110.052 7.425 ;
     RECT  110.646 7.29 110.97 7.425 ;
     RECT  112.806 7.29 114.372 7.425 ;
     RECT  115.83 7.29 116.478 7.425 ;
     RECT  121.878 7.29 123.12 7.425 ;
     RECT  127.332 7.155 127.44 7.425 ;
     RECT  12.042 7.695 13.284 7.83 ;
     RECT  13.824 7.695 14.148 7.83 ;
     RECT  14.256 7.695 14.58 7.83 ;
     RECT  14.634 7.695 14.958 7.83 ;
     RECT  15.066 7.695 15.228 7.83 ;
     RECT  16.632 7.695 17.118 7.83 ;
     RECT  19.008 7.695 20.412 7.83 ;
     RECT  20.682 7.695 21.168 7.83 ;
     RECT  21.33 7.695 22.41 7.83 ;
     RECT  22.68 7.695 23.058 7.83 ;
     RECT  23.22 7.695 24.3 7.83 ;
     RECT  24.408 7.695 24.57 7.83 ;
     RECT  24.624 7.695 24.948 7.83 ;
     RECT  25.002 7.695 25.326 7.83 ;
     RECT  25.812 7.695 26.946 7.83 ;
     RECT  27.108 7.695 27.54 7.83 ;
     RECT  27.648 7.695 29.16 7.83 ;
     RECT  29.268 7.695 29.7 7.83 ;
     RECT  29.754 7.695 31.266 7.83 ;
     RECT  31.374 7.695 32.832 7.83 ;
     RECT  32.994 7.695 33.696 7.83 ;
     RECT  34.398 7.695 35.1 7.83 ;
     RECT  35.316 7.695 35.64 7.83 ;
     RECT  36.396 7.695 36.828 7.83 ;
     RECT  36.882 7.695 37.314 7.83 ;
     RECT  37.422 7.695 37.962 7.83 ;
     RECT  38.016 7.695 38.61 7.83 ;
     RECT  39.636 7.695 40.5 7.83 ;
     RECT  42.282 7.695 42.66 7.83 ;
     RECT  42.768 7.695 43.956 7.83 ;
     RECT  44.118 7.695 44.55 7.83 ;
     RECT  44.874 7.695 45.63 7.83 ;
     RECT  45.846 7.695 46.278 7.83 ;
     RECT  46.332 7.695 46.71 7.83 ;
     RECT  46.764 7.695 47.52 7.83 ;
     RECT  47.682 7.695 48.546 7.83 ;
     RECT  48.6 7.695 50.382 7.83 ;
     RECT  50.436 7.695 50.76 7.83 ;
     RECT  50.814 7.695 51.138 7.83 ;
     RECT  51.192 7.695 51.624 7.83 ;
     RECT  51.678 7.695 52.218 7.83 ;
     RECT  53.568 7.695 54.054 7.83 ;
     RECT  54.216 7.695 56.268 7.83 ;
     RECT  56.376 7.695 56.808 7.83 ;
     RECT  56.916 7.695 59.238 7.83 ;
     RECT  59.346 7.695 59.778 7.83 ;
     RECT  59.994 7.695 60.75 7.83 ;
     RECT  61.074 7.695 62.964 7.83 ;
     RECT  63.558 7.695 63.882 7.83 ;
     RECT  66.798 7.695 68.202 7.83 ;
     RECT  68.526 7.695 70.308 7.83 ;
     RECT  70.74 7.695 72.9 7.83 ;
     RECT  73.008 7.695 74.25 7.83 ;
     RECT  74.304 7.695 75.654 7.83 ;
     RECT  75.816 7.695 76.896 7.83 ;
     RECT  77.004 7.695 77.544 7.83 ;
     RECT  77.706 7.695 78.678 7.83 ;
     RECT  78.732 7.695 79.11 7.83 ;
     RECT  79.164 7.695 81.108 7.83 ;
     RECT  81.378 7.695 82.134 7.83 ;
     RECT  82.242 7.695 83.538 7.83 ;
     RECT  83.646 7.695 84.51 7.83 ;
     RECT  84.618 7.695 85.158 7.83 ;
     RECT  85.212 7.695 87.156 7.83 ;
     RECT  87.21 7.695 87.642 7.83 ;
     RECT  87.966 7.695 88.344 7.83 ;
     RECT  88.722 7.695 89.154 7.83 ;
     RECT  90.504 7.695 92.448 7.83 ;
     RECT  92.61 7.695 93.15 7.83 ;
     RECT  93.204 7.695 93.582 7.83 ;
     RECT  93.636 7.695 94.014 7.83 ;
     RECT  94.23 7.695 94.662 7.83 ;
     RECT  94.716 7.695 95.094 7.83 ;
     RECT  95.31 7.695 96.39 7.83 ;
     RECT  96.444 7.695 96.876 7.83 ;
     RECT  96.93 7.695 98.334 7.83 ;
     RECT  98.604 7.695 100.494 7.83 ;
     RECT  100.656 7.695 101.088 7.83 ;
     RECT  101.358 7.695 103.032 7.83 ;
     RECT  103.14 7.695 103.464 7.83 ;
     RECT  103.518 7.695 104.166 7.83 ;
     RECT  104.436 7.695 105.516 7.83 ;
     RECT  105.57 7.695 106.65 7.83 ;
     RECT  107.19 7.695 107.838 7.83 ;
     RECT  108.27 7.695 109.35 7.83 ;
     RECT  110.376 7.695 111.996 7.83 ;
     RECT  115.776 7.695 117.018 7.83 ;
     RECT  121.014 7.695 122.256 7.83 ;
     RECT  122.472 7.695 122.796 7.83 ;
     RECT  126.9 7.695 127.008 7.83 ;
     RECT  2.16 7.695 2.268 7.965 ;
     RECT  14.58 7.83 14.742 7.965 ;
     RECT  16.794 7.83 17.874 7.965 ;
     RECT  18.036 7.83 19.278 7.965 ;
     RECT  19.872 7.83 20.196 7.965 ;
     RECT  20.25 7.83 20.412 7.965 ;
     RECT  22.626 7.83 22.95 7.965 ;
     RECT  23.814 7.83 24.3 7.965 ;
     RECT  24.786 7.83 25.272 7.965 ;
     RECT  25.542 7.83 28.836 7.965 ;
     RECT  28.89 7.83 29.268 7.965 ;
     RECT  29.322 7.83 30.078 7.965 ;
     RECT  30.186 7.83 30.51 7.965 ;
     RECT  30.564 7.83 31.104 7.965 ;
     RECT  31.266 7.83 32.454 7.965 ;
     RECT  32.562 7.83 32.886 7.965 ;
     RECT  32.94 7.83 33.264 7.965 ;
     RECT  33.426 7.83 33.858 7.965 ;
     RECT  34.83 7.83 34.992 7.965 ;
     RECT  35.262 7.83 36.288 7.965 ;
     RECT  36.396 7.83 37.368 7.965 ;
     RECT  37.584 7.83 40.392 7.965 ;
     RECT  41.58 7.83 44.118 7.965 ;
     RECT  44.28 7.83 44.712 7.965 ;
     RECT  44.766 7.83 45.576 7.965 ;
     RECT  45.63 7.83 46.44 7.965 ;
     RECT  46.548 7.83 50.004 7.965 ;
     RECT  50.058 7.83 50.76 7.965 ;
     RECT  50.814 7.83 51.894 7.965 ;
     RECT  52.056 7.83 52.164 7.965 ;
     RECT  52.326 7.83 52.65 7.965 ;
     RECT  52.758 7.83 53.136 7.965 ;
     RECT  54.918 7.83 55.728 7.965 ;
     RECT  55.782 7.83 56.322 7.965 ;
     RECT  56.376 7.83 57.618 7.965 ;
     RECT  57.726 7.83 58.86 7.965 ;
     RECT  58.968 7.83 59.508 7.965 ;
     RECT  59.616 7.83 60.048 7.965 ;
     RECT  60.102 7.83 61.452 7.965 ;
     RECT  61.56 7.83 61.992 7.965 ;
     RECT  62.1 7.83 63.342 7.965 ;
     RECT  64.206 7.695 64.53 7.965 ;
     RECT  67.77 7.83 68.094 7.965 ;
     RECT  68.526 7.83 68.85 7.965 ;
     RECT  69.93 7.83 71.226 7.965 ;
     RECT  71.28 7.83 71.442 7.965 ;
     RECT  71.496 7.83 71.874 7.965 ;
     RECT  71.928 7.83 72.306 7.965 ;
     RECT  72.36 7.83 72.792 7.965 ;
     RECT  72.846 7.83 74.034 7.965 ;
     RECT  74.142 7.83 74.682 7.965 ;
     RECT  74.844 7.83 75.978 7.965 ;
     RECT  76.032 7.83 77.382 7.965 ;
     RECT  77.49 7.83 77.814 7.965 ;
     RECT  77.868 7.83 78.624 7.965 ;
     RECT  78.732 7.83 79.164 7.965 ;
     RECT  79.272 7.83 80.082 7.965 ;
     RECT  80.298 7.83 80.73 7.965 ;
     RECT  80.784 7.83 82.89 7.965 ;
     RECT  83.16 7.83 85.158 7.965 ;
     RECT  85.266 7.83 86.184 7.965 ;
     RECT  86.238 7.83 87.48 7.965 ;
     RECT  87.642 7.83 87.966 7.965 ;
     RECT  88.128 7.83 88.668 7.965 ;
     RECT  90.558 7.83 92.232 7.965 ;
     RECT  92.394 7.83 95.31 7.965 ;
     RECT  95.418 7.83 96.282 7.965 ;
     RECT  96.498 7.83 98.874 7.965 ;
     RECT  99.036 7.83 100.008 7.965 ;
     RECT  100.116 7.83 100.98 7.965 ;
     RECT  101.088 7.83 101.52 7.965 ;
     RECT  101.952 7.83 102.06 7.965 ;
     RECT  102.222 7.83 103.302 7.965 ;
     RECT  103.572 7.83 103.896 7.965 ;
     RECT  104.598 7.83 104.922 7.965 ;
     RECT  105.192 7.83 105.516 7.965 ;
     RECT  106.65 7.83 107.892 7.965 ;
     RECT  110.052 7.83 111.132 7.965 ;
     RECT  120.798 7.83 121.446 7.965 ;
     RECT  127.332 7.695 127.44 7.965 ;
     RECT  12.528 8.235 14.688 8.37 ;
     RECT  16.524 8.235 17.172 8.37 ;
     RECT  17.874 8.235 19.278 8.37 ;
     RECT  21.654 8.235 22.896 8.37 ;
     RECT  23.058 8.235 23.382 8.37 ;
     RECT  24.084 8.235 25.164 8.37 ;
     RECT  26.028 8.235 27.216 8.37 ;
     RECT  27.378 8.235 28.998 8.37 ;
     RECT  29.052 8.235 29.376 8.37 ;
     RECT  29.484 8.235 30.348 8.37 ;
     RECT  30.402 8.235 30.942 8.37 ;
     RECT  31.05 8.235 31.806 8.37 ;
     RECT  31.86 8.235 32.4 8.37 ;
     RECT  32.454 8.235 33.696 8.37 ;
     RECT  33.966 8.235 34.29 8.37 ;
     RECT  34.614 8.235 35.856 8.37 ;
     RECT  36.126 8.235 37.53 8.37 ;
     RECT  37.584 8.235 38.556 8.37 ;
     RECT  38.772 8.235 40.986 8.37 ;
     RECT  41.58 8.235 43.416 8.37 ;
     RECT  43.47 8.235 44.55 8.37 ;
     RECT  44.604 8.235 45.036 8.37 ;
     RECT  45.09 8.235 45.846 8.37 ;
     RECT  45.9 8.235 46.71 8.37 ;
     RECT  46.764 8.235 47.52 8.37 ;
     RECT  47.574 8.235 52.164 8.37 ;
     RECT  52.218 8.235 53.19 8.37 ;
     RECT  54.81 8.235 56.106 8.37 ;
     RECT  56.538 8.235 56.862 8.37 ;
     RECT  56.916 8.235 57.294 8.37 ;
     RECT  57.564 8.235 58.104 8.37 ;
     RECT  58.212 8.235 59.94 8.37 ;
     RECT  60.048 8.235 60.588 8.37 ;
     RECT  60.696 8.235 61.074 8.37 ;
     RECT  61.236 8.235 61.668 8.37 ;
     RECT  61.722 8.235 62.154 8.37 ;
     RECT  62.316 8.235 62.748 8.37 ;
     RECT  63.018 8.235 64.692 8.37 ;
     RECT  67.446 8.235 68.85 8.37 ;
     RECT  69.066 8.235 70.308 8.37 ;
     RECT  70.416 8.235 70.74 8.37 ;
     RECT  70.956 8.235 71.388 8.37 ;
     RECT  71.442 8.235 72.684 8.37 ;
     RECT  72.792 8.235 73.548 8.37 ;
     RECT  73.71 8.235 75.114 8.37 ;
     RECT  75.384 8.235 77.112 8.37 ;
     RECT  77.22 8.235 77.922 8.37 ;
     RECT  78.192 8.235 79.002 8.37 ;
     RECT  79.056 8.235 79.488 8.37 ;
     RECT  79.542 8.235 79.974 8.37 ;
     RECT  80.028 8.235 81.702 8.37 ;
     RECT  81.918 8.235 83.052 8.37 ;
     RECT  83.106 8.235 83.646 8.37 ;
     RECT  83.808 8.235 84.888 8.37 ;
     RECT  85.05 8.235 86.13 8.37 ;
     RECT  86.292 8.235 87.642 8.37 ;
     RECT  87.696 8.235 88.452 8.37 ;
     RECT  88.506 8.235 89.046 8.37 ;
     RECT  89.91 8.235 93.312 8.37 ;
     RECT  93.366 8.235 94.176 8.37 ;
     RECT  94.23 8.235 94.662 8.37 ;
     RECT  94.716 8.235 95.958 8.37 ;
     RECT  96.012 8.235 97.2 8.37 ;
     RECT  97.416 8.235 98.82 8.37 ;
     RECT  98.928 8.235 100.224 8.37 ;
     RECT  100.332 8.235 101.088 8.37 ;
     RECT  101.304 8.235 102.168 8.37 ;
     RECT  103.68 8.235 106.002 8.37 ;
     RECT  106.272 8.235 106.434 8.37 ;
     RECT  108.54 8.235 108.864 8.37 ;
     RECT  110.808 8.235 111.132 8.37 ;
     RECT  111.402 8.235 111.564 8.37 ;
     RECT  112.428 8.235 112.752 8.37 ;
     RECT  113.292 8.235 114.912 8.37 ;
     RECT  122.526 8.235 123.174 8.37 ;
     RECT  123.282 8.235 124.524 8.37 ;
     RECT  126.9 8.235 127.008 8.37 ;
     RECT  2.16 8.235 2.268 8.505 ;
     RECT  13.23 8.37 13.554 8.505 ;
     RECT  13.608 8.37 14.094 8.505 ;
     RECT  16.47 8.37 16.632 8.505 ;
     RECT  17.712 8.37 18.792 8.505 ;
     RECT  18.954 8.37 19.116 8.505 ;
     RECT  19.44 8.37 19.764 8.505 ;
     RECT  20.25 8.37 21.87 8.505 ;
     RECT  23.22 8.37 24.3 8.505 ;
     RECT  24.786 8.37 25.866 8.505 ;
     RECT  25.974 8.37 26.352 8.505 ;
     RECT  26.406 8.37 26.838 8.505 ;
     RECT  26.892 8.37 30.834 8.505 ;
     RECT  30.888 8.37 31.32 8.505 ;
     RECT  31.428 8.37 32.238 8.505 ;
     RECT  32.292 8.37 32.616 8.505 ;
     RECT  32.67 8.37 33.642 8.505 ;
     RECT  33.858 8.37 34.938 8.505 ;
     RECT  35.424 8.37 36.396 8.505 ;
     RECT  36.666 8.37 38.394 8.505 ;
     RECT  38.556 8.37 38.988 8.505 ;
     RECT  39.042 8.37 39.744 8.505 ;
     RECT  39.906 8.37 40.338 8.505 ;
     RECT  41.742 8.37 42.498 8.505 ;
     RECT  42.552 8.37 43.848 8.505 ;
     RECT  43.956 8.37 46.764 8.505 ;
     RECT  46.818 8.37 47.196 8.505 ;
     RECT  47.25 8.37 48.384 8.505 ;
     RECT  48.438 8.37 48.87 8.505 ;
     RECT  48.924 8.37 49.302 8.505 ;
     RECT  49.356 8.37 49.788 8.505 ;
     RECT  49.842 8.37 51.192 8.505 ;
     RECT  51.246 8.37 51.786 8.505 ;
     RECT  52.056 8.37 52.488 8.505 ;
     RECT  52.542 8.37 53.514 8.505 ;
     RECT  54.108 8.37 54.54 8.505 ;
     RECT  54.756 8.37 55.89 8.505 ;
     RECT  55.998 8.37 56.916 8.505 ;
     RECT  57.024 8.37 58.59 8.505 ;
     RECT  59.076 8.37 59.508 8.505 ;
     RECT  59.67 8.37 60.75 8.505 ;
     RECT  60.804 8.37 61.128 8.505 ;
     RECT  61.182 8.37 61.992 8.505 ;
     RECT  63.45 8.37 64.206 8.505 ;
     RECT  64.422 8.37 64.584 8.505 ;
     RECT  67.77 8.37 67.932 8.505 ;
     RECT  68.58 8.37 68.742 8.505 ;
     RECT  70.47 8.37 71.712 8.505 ;
     RECT  71.766 8.37 73.008 8.505 ;
     RECT  73.116 8.37 73.548 8.505 ;
     RECT  73.602 8.37 74.358 8.505 ;
     RECT  74.412 8.37 75.87 8.505 ;
     RECT  76.032 8.37 76.788 8.505 ;
     RECT  76.842 8.37 77.706 8.505 ;
     RECT  77.868 8.37 78.84 8.505 ;
     RECT  78.894 8.37 79.65 8.505 ;
     RECT  79.758 8.37 80.19 8.505 ;
     RECT  80.298 8.37 81.054 8.505 ;
     RECT  81.108 8.37 82.782 8.505 ;
     RECT  82.89 8.37 83.322 8.505 ;
     RECT  83.376 8.37 84.186 8.505 ;
     RECT  84.24 8.37 87.102 8.505 ;
     RECT  87.156 8.37 88.344 8.505 ;
     RECT  88.83 8.37 89.37 8.505 ;
     RECT  90.828 8.37 92.502 8.505 ;
     RECT  92.718 8.37 95.418 8.505 ;
     RECT  95.472 8.37 96.606 8.505 ;
     RECT  96.66 8.37 98.172 8.505 ;
     RECT  98.28 8.37 99.144 8.505 ;
     RECT  99.252 8.37 100.71 8.505 ;
     RECT  100.872 8.37 102.06 8.505 ;
     RECT  102.546 8.37 102.87 8.505 ;
     RECT  102.978 8.37 104.058 8.505 ;
     RECT  104.382 8.37 104.706 8.505 ;
     RECT  107.298 8.37 109.62 8.505 ;
     RECT  109.998 8.37 110.322 8.505 ;
     RECT  110.592 8.37 111.672 8.505 ;
     RECT  111.888 8.37 113.292 8.505 ;
     RECT  113.508 8.37 114.912 8.505 ;
     RECT  115.992 8.37 116.316 8.505 ;
     RECT  117.072 8.37 117.342 8.505 ;
     RECT  127.332 8.235 127.44 8.505 ;
     RECT  16.578 8.775 17.658 8.91 ;
     RECT  17.766 8.775 18.09 8.91 ;
     RECT  18.198 8.775 18.522 8.91 ;
     RECT  18.684 8.775 18.846 8.91 ;
     RECT  19.224 8.775 19.548 8.91 ;
     RECT  19.656 8.775 20.304 8.91 ;
     RECT  20.628 8.775 20.79 8.91 ;
     RECT  21.87 8.775 22.518 8.91 ;
     RECT  22.68 8.775 23.328 8.91 ;
     RECT  23.544 8.775 23.706 8.91 ;
     RECT  23.76 8.775 24.408 8.91 ;
     RECT  24.57 8.775 25.218 8.91 ;
     RECT  25.272 8.775 26.73 8.91 ;
     RECT  27.108 8.775 27.54 8.91 ;
     RECT  27.648 8.775 29.808 8.91 ;
     RECT  29.97 8.775 30.402 8.91 ;
     RECT  30.564 8.775 31.644 8.91 ;
     RECT  31.806 8.775 32.184 8.91 ;
     RECT  32.454 8.775 33.696 8.91 ;
     RECT  34.452 8.775 34.884 8.91 ;
     RECT  35.1 8.775 35.478 8.91 ;
     RECT  35.964 8.775 36.774 8.91 ;
     RECT  36.828 8.775 37.152 8.91 ;
     RECT  37.26 8.775 38.34 8.91 ;
     RECT  38.448 8.775 40.176 8.91 ;
     RECT  41.58 8.775 42.39 8.91 ;
     RECT  42.444 8.775 43.254 8.91 ;
     RECT  43.362 8.775 44.442 8.91 ;
     RECT  44.766 8.775 46.386 8.91 ;
     RECT  46.656 8.775 47.898 8.91 ;
     RECT  48.006 8.775 48.384 8.91 ;
     RECT  48.438 8.775 48.816 8.91 ;
     RECT  48.87 8.775 49.68 8.91 ;
     RECT  49.734 8.775 50.166 8.91 ;
     RECT  50.274 8.775 50.706 8.91 ;
     RECT  50.922 8.775 52.272 8.91 ;
     RECT  52.326 8.775 52.758 8.91 ;
     RECT  52.812 8.775 53.19 8.91 ;
     RECT  54.432 8.775 55.242 8.91 ;
     RECT  55.458 8.775 55.782 8.91 ;
     RECT  55.89 8.775 56.268 8.91 ;
     RECT  56.322 8.775 56.754 8.91 ;
     RECT  56.862 8.775 57.186 8.91 ;
     RECT  57.24 8.775 58.05 8.91 ;
     RECT  58.32 8.775 58.752 8.91 ;
     RECT  59.076 8.775 62.424 8.91 ;
     RECT  62.532 8.775 62.964 8.91 ;
     RECT  63.234 8.775 64.746 8.91 ;
     RECT  70.254 8.775 72.198 8.91 ;
     RECT  72.306 8.775 73.44 8.91 ;
     RECT  73.656 8.775 74.52 8.91 ;
     RECT  74.682 8.775 76.41 8.91 ;
     RECT  76.572 8.775 77.112 8.91 ;
     RECT  77.22 8.775 78.408 8.91 ;
     RECT  78.57 8.775 79.326 8.91 ;
     RECT  79.38 8.775 80.622 8.91 ;
     RECT  80.838 8.775 81.378 8.91 ;
     RECT  81.486 8.775 82.188 8.91 ;
     RECT  82.458 8.775 83.916 8.91 ;
     RECT  83.97 8.775 86.886 8.91 ;
     RECT  86.94 8.775 88.182 8.91 ;
     RECT  88.236 8.775 88.776 8.91 ;
     RECT  88.884 8.775 89.316 8.91 ;
     RECT  90.072 8.775 90.612 8.91 ;
     RECT  90.774 8.775 92.34 8.91 ;
     RECT  92.448 8.775 94.986 8.91 ;
     RECT  95.04 8.775 95.58 8.91 ;
     RECT  95.634 8.775 95.958 8.91 ;
     RECT  96.012 8.775 97.578 8.91 ;
     RECT  97.794 8.775 98.604 8.91 ;
     RECT  98.712 8.775 99.414 8.91 ;
     RECT  99.522 8.775 99.684 8.91 ;
     RECT  99.792 8.775 100.116 8.91 ;
     RECT  100.224 8.775 102.87 8.91 ;
     RECT  103.356 8.775 104.76 8.91 ;
     RECT  105.192 8.775 106.164 8.91 ;
     RECT  107.028 8.775 107.352 8.91 ;
     RECT  108.324 8.775 108.648 8.91 ;
     RECT  109.08 8.775 109.242 8.91 ;
     RECT  111.564 8.775 112.968 8.91 ;
     RECT  113.778 8.775 114.102 8.91 ;
     RECT  115.884 8.775 116.964 8.91 ;
     RECT  126.9 8.775 127.008 8.91 ;
     RECT  2.16 8.775 2.268 9.045 ;
     RECT  12.744 8.91 14.148 9.045 ;
     RECT  15.174 8.91 16.902 9.045 ;
     RECT  17.658 8.91 17.982 9.045 ;
     RECT  18.306 8.91 19.548 9.045 ;
     RECT  20.25 8.91 20.682 9.045 ;
     RECT  22.734 8.91 23.058 9.045 ;
     RECT  24.03 8.91 24.192 9.045 ;
     RECT  24.84 8.91 26.46 9.045 ;
     RECT  26.568 8.91 27 9.045 ;
     RECT  27.162 8.91 28.404 9.045 ;
     RECT  28.728 8.91 29.43 9.045 ;
     RECT  29.484 8.91 30.294 9.045 ;
     RECT  30.564 8.91 31.968 9.045 ;
     RECT  32.022 8.91 33.102 9.045 ;
     RECT  33.21 8.91 33.642 9.045 ;
     RECT  35.694 8.91 36.126 9.045 ;
     RECT  36.18 8.91 36.828 9.045 ;
     RECT  37.098 8.91 37.476 9.045 ;
     RECT  37.584 8.91 38.124 9.045 ;
     RECT  38.178 8.91 38.556 9.045 ;
     RECT  38.61 8.91 40.014 9.045 ;
     RECT  40.068 8.91 40.608 9.045 ;
     RECT  41.364 8.91 42.228 9.045 ;
     RECT  42.606 8.91 44.658 9.045 ;
     RECT  44.874 8.91 45.738 9.045 ;
     RECT  46.008 8.91 46.764 9.045 ;
     RECT  46.98 8.91 47.952 9.045 ;
     RECT  48.006 8.91 48.33 9.045 ;
     RECT  48.384 8.91 51.138 9.045 ;
     RECT  51.246 8.91 51.57 9.045 ;
     RECT  51.624 8.91 52.164 9.045 ;
     RECT  52.272 8.91 52.596 9.045 ;
     RECT  52.704 8.91 53.136 9.045 ;
     RECT  54.81 8.91 56.052 9.045 ;
     RECT  56.16 8.91 56.484 9.045 ;
     RECT  56.538 8.91 56.97 9.045 ;
     RECT  57.186 8.91 57.618 9.045 ;
     RECT  57.78 8.91 58.212 9.045 ;
     RECT  58.266 8.91 59.508 9.045 ;
     RECT  59.616 8.91 61.668 9.045 ;
     RECT  61.776 8.91 62.208 9.045 ;
     RECT  62.856 8.91 63.288 9.045 ;
     RECT  63.558 8.91 63.99 9.045 ;
     RECT  69.606 8.91 69.93 9.045 ;
     RECT  70.794 8.91 71.118 9.045 ;
     RECT  71.226 8.91 72.36 9.045 ;
     RECT  72.414 8.91 73.17 9.045 ;
     RECT  73.278 8.91 74.358 9.045 ;
     RECT  74.412 8.91 75.654 9.045 ;
     RECT  75.762 8.91 77.004 9.045 ;
     RECT  77.058 8.91 77.49 9.045 ;
     RECT  77.598 8.91 78.732 9.045 ;
     RECT  78.786 8.91 80.136 9.045 ;
     RECT  80.19 8.91 82.998 9.045 ;
     RECT  83.106 8.91 83.538 9.045 ;
     RECT  83.646 8.91 86.022 9.045 ;
     RECT  86.184 8.91 86.616 9.045 ;
     RECT  86.94 8.91 87.48 9.045 ;
     RECT  87.588 8.91 88.02 9.045 ;
     RECT  88.182 8.91 89.046 9.045 ;
     RECT  89.802 8.91 90.558 9.045 ;
     RECT  90.774 8.91 91.314 9.045 ;
     RECT  91.476 8.91 96.876 9.045 ;
     RECT  96.93 8.91 97.902 9.045 ;
     RECT  98.064 8.91 99.36 9.045 ;
     RECT  99.414 8.91 99.792 9.045 ;
     RECT  99.846 8.91 100.224 9.045 ;
     RECT  100.278 8.91 100.656 9.045 ;
     RECT  100.71 8.91 101.574 9.045 ;
     RECT  101.628 8.91 102.06 9.045 ;
     RECT  103.14 8.91 103.464 9.045 ;
     RECT  104.436 8.91 104.76 9.045 ;
     RECT  104.814 8.91 108.216 9.045 ;
     RECT  108.756 8.91 109.08 9.045 ;
     RECT  109.566 8.91 109.89 9.045 ;
     RECT  111.78 8.91 112.104 9.045 ;
     RECT  113.076 8.91 113.238 9.045 ;
     RECT  113.562 8.91 115.128 9.045 ;
     RECT  115.992 8.91 116.316 9.045 ;
     RECT  116.532 8.91 116.694 9.045 ;
     RECT  116.802 8.91 117.126 9.045 ;
     RECT  118.638 8.91 118.962 9.045 ;
     RECT  127.332 8.775 127.44 9.045 ;
     RECT  13.068 9.315 13.392 9.45 ;
     RECT  13.662 9.315 13.824 9.45 ;
     RECT  13.986 9.315 14.31 9.45 ;
     RECT  14.472 9.315 15.552 9.45 ;
     RECT  15.606 9.315 15.768 9.45 ;
     RECT  16.416 9.315 17.658 9.45 ;
     RECT  17.712 9.315 18.036 9.45 ;
     RECT  20.412 9.315 21.492 9.45 ;
     RECT  21.654 9.315 23.976 9.45 ;
     RECT  24.57 9.315 25.326 9.45 ;
     RECT  25.434 9.315 25.866 9.45 ;
     RECT  26.244 9.315 27.216 9.45 ;
     RECT  27.27 9.315 27.648 9.45 ;
     RECT  27.702 9.315 29.43 9.45 ;
     RECT  29.484 9.315 30.402 9.45 ;
     RECT  30.456 9.315 31.86 9.45 ;
     RECT  31.914 9.315 32.778 9.45 ;
     RECT  32.832 9.315 33.372 9.45 ;
     RECT  33.426 9.315 33.858 9.45 ;
     RECT  36.612 9.315 37.8 9.45 ;
     RECT  37.908 9.315 38.88 9.45 ;
     RECT  39.042 9.315 39.474 9.45 ;
     RECT  39.528 9.315 40.284 9.45 ;
     RECT  40.338 9.315 40.878 9.45 ;
     RECT  41.364 9.315 41.796 9.45 ;
     RECT  42.282 9.315 43.632 9.45 ;
     RECT  43.686 9.315 44.118 9.45 ;
     RECT  44.172 9.315 44.712 9.45 ;
     RECT  44.766 9.315 45.63 9.45 ;
     RECT  45.738 9.315 47.628 9.45 ;
     RECT  47.682 9.315 48.222 9.45 ;
     RECT  48.33 9.315 48.87 9.45 ;
     RECT  48.924 9.315 49.356 9.45 ;
     RECT  49.41 9.315 49.842 9.45 ;
     RECT  49.896 9.315 50.274 9.45 ;
     RECT  50.328 9.315 50.868 9.45 ;
     RECT  50.922 9.315 51.246 9.45 ;
     RECT  51.354 9.315 51.786 9.45 ;
     RECT  51.894 9.315 52.866 9.45 ;
     RECT  54.756 9.315 55.188 9.45 ;
     RECT  55.512 9.315 59.67 9.45 ;
     RECT  59.724 9.315 61.884 9.45 ;
     RECT  61.992 9.315 62.316 9.45 ;
     RECT  62.37 9.315 63.666 9.45 ;
     RECT  69.066 9.315 70.47 9.45 ;
     RECT  70.74 9.315 72.09 9.45 ;
     RECT  72.198 9.315 76.032 9.45 ;
     RECT  76.14 9.315 77.976 9.45 ;
     RECT  78.246 9.315 83.376 9.45 ;
     RECT  83.538 9.315 83.97 9.45 ;
     RECT  84.078 9.315 85.32 9.45 ;
     RECT  85.752 9.315 86.4 9.45 ;
     RECT  86.508 9.315 86.886 9.45 ;
     RECT  86.94 9.315 88.344 9.45 ;
     RECT  88.398 9.315 88.83 9.45 ;
     RECT  90.612 9.315 90.936 9.45 ;
     RECT  90.99 9.315 91.422 9.45 ;
     RECT  91.476 9.315 92.556 9.45 ;
     RECT  92.61 9.315 93.042 9.45 ;
     RECT  93.096 9.315 94.824 9.45 ;
     RECT  94.878 9.315 95.202 9.45 ;
     RECT  95.364 9.315 96.12 9.45 ;
     RECT  96.174 9.315 96.552 9.45 ;
     RECT  96.66 9.315 96.984 9.45 ;
     RECT  97.092 9.315 98.334 9.45 ;
     RECT  98.388 9.315 98.82 9.45 ;
     RECT  99.09 9.315 99.954 9.45 ;
     RECT  100.008 9.315 100.44 9.45 ;
     RECT  100.494 9.315 102.114 9.45 ;
     RECT  103.518 9.315 103.842 9.45 ;
     RECT  104.058 9.315 104.706 9.45 ;
     RECT  104.976 9.315 105.138 9.45 ;
     RECT  105.246 9.315 106.488 9.45 ;
     RECT  106.704 9.315 107.028 9.45 ;
     RECT  107.46 9.315 107.946 9.45 ;
     RECT  108.972 9.315 110.214 9.45 ;
     RECT  110.484 9.315 110.646 9.45 ;
     RECT  112.158 9.315 112.32 9.45 ;
     RECT  112.428 9.315 112.752 9.45 ;
     RECT  114.156 9.315 114.318 9.45 ;
     RECT  114.372 9.315 114.858 9.45 ;
     RECT  114.912 9.315 115.074 9.45 ;
     RECT  115.452 9.315 115.776 9.45 ;
     RECT  116.802 9.315 118.854 9.45 ;
     RECT  122.85 9.315 123.174 9.45 ;
     RECT  126.9 9.315 127.008 9.45 ;
     RECT  2.16 9.315 2.268 9.585 ;
     RECT  13.608 9.45 14.094 9.585 ;
     RECT  15.12 9.45 15.444 9.585 ;
     RECT  16.794 9.45 16.956 9.585 ;
     RECT  19.818 9.45 20.142 9.585 ;
     RECT  21.006 9.45 21.33 9.585 ;
     RECT  22.734 9.45 22.896 9.585 ;
     RECT  25.542 9.45 27.54 9.585 ;
     RECT  27.594 9.45 27.972 9.585 ;
     RECT  28.08 9.45 28.458 9.585 ;
     RECT  28.512 9.45 29.322 9.585 ;
     RECT  29.376 9.45 30.618 9.585 ;
     RECT  30.78 9.45 31.104 9.585 ;
     RECT  31.158 9.45 31.914 9.585 ;
     RECT  31.968 9.45 33.642 9.585 ;
     RECT  35.532 9.45 40.284 9.585 ;
     RECT  40.338 9.45 41.526 9.585 ;
     RECT  41.904 9.45 44.712 9.585 ;
     RECT  44.766 9.45 46.71 9.585 ;
     RECT  46.818 9.45 47.682 9.585 ;
     RECT  47.952 9.45 48.384 9.585 ;
     RECT  48.492 9.45 51.138 9.585 ;
     RECT  51.192 9.45 52.974 9.585 ;
     RECT  54.432 9.45 56.214 9.585 ;
     RECT  56.268 9.45 56.592 9.585 ;
     RECT  56.646 9.45 58.482 9.585 ;
     RECT  58.59 9.45 59.022 9.585 ;
     RECT  59.13 9.45 61.182 9.585 ;
     RECT  61.344 9.45 61.722 9.585 ;
     RECT  61.776 9.45 62.1 9.585 ;
     RECT  62.154 9.45 62.694 9.585 ;
     RECT  62.748 9.45 64.422 9.585 ;
     RECT  68.526 9.45 68.85 9.585 ;
     RECT  68.904 9.45 69.768 9.585 ;
     RECT  69.876 9.45 70.74 9.585 ;
     RECT  70.794 9.45 71.226 9.585 ;
     RECT  71.334 9.45 72.306 9.585 ;
     RECT  72.468 9.45 73.332 9.585 ;
     RECT  73.656 9.45 74.52 9.585 ;
     RECT  74.574 9.45 75.006 9.585 ;
     RECT  75.06 9.45 76.194 9.585 ;
     RECT  76.41 9.45 76.842 9.585 ;
     RECT  76.95 9.45 78.732 9.585 ;
     RECT  78.84 9.45 80.46 9.585 ;
     RECT  80.676 9.45 81.108 9.585 ;
     RECT  81.162 9.45 81.918 9.585 ;
     RECT  82.026 9.45 83.214 9.585 ;
     RECT  83.268 9.45 83.7 9.585 ;
     RECT  83.808 9.45 85.914 9.585 ;
     RECT  85.968 9.45 86.832 9.585 ;
     RECT  87.048 9.45 87.48 9.585 ;
     RECT  87.588 9.45 87.912 9.585 ;
     RECT  87.966 9.45 88.506 9.585 ;
     RECT  90.072 9.45 90.396 9.585 ;
     RECT  90.612 9.45 92.556 9.585 ;
     RECT  92.664 9.45 94.284 9.585 ;
     RECT  94.392 9.45 96.552 9.585 ;
     RECT  96.66 9.45 97.902 9.585 ;
     RECT  97.956 9.45 98.388 9.585 ;
     RECT  98.442 9.45 99.198 9.585 ;
     RECT  99.252 9.45 100.116 9.585 ;
     RECT  100.656 9.45 102.06 9.585 ;
     RECT  102.654 9.45 102.816 9.585 ;
     RECT  103.572 9.45 103.734 9.585 ;
     RECT  103.788 9.45 104.868 9.585 ;
     RECT  105.246 9.45 105.732 9.585 ;
     RECT  105.786 9.45 106.11 9.585 ;
     RECT  106.218 9.45 106.542 9.585 ;
     RECT  106.65 9.45 106.974 9.585 ;
     RECT  107.082 9.45 108.162 9.585 ;
     RECT  108.972 9.45 109.296 9.585 ;
     RECT  109.512 9.45 111.996 9.585 ;
     RECT  112.104 9.45 113.508 9.585 ;
     RECT  113.67 9.45 113.994 9.585 ;
     RECT  114.102 9.45 115.182 9.585 ;
     RECT  115.506 9.45 116.748 9.585 ;
     RECT  116.856 9.45 118.098 9.585 ;
     RECT  118.692 9.45 119.934 9.585 ;
     RECT  119.988 9.45 121.068 9.585 ;
     RECT  121.932 9.45 122.256 9.585 ;
     RECT  122.58 9.45 123.822 9.585 ;
     RECT  127.332 9.315 127.44 9.585 ;
     RECT  13.824 9.855 14.148 9.99 ;
     RECT  15.066 9.855 16.794 9.99 ;
     RECT  16.848 9.855 17.496 9.99 ;
     RECT  17.55 9.855 17.874 9.99 ;
     RECT  18.09 9.855 18.414 9.99 ;
     RECT  19.656 9.855 20.736 9.99 ;
     RECT  21.276 9.855 21.816 9.99 ;
     RECT  23.22 9.855 23.868 9.99 ;
     RECT  23.976 9.855 24.516 9.99 ;
     RECT  24.894 9.855 26.514 9.99 ;
     RECT  26.568 9.855 27.216 9.99 ;
     RECT  27.27 9.855 27.594 9.99 ;
     RECT  27.756 9.855 28.566 9.99 ;
     RECT  28.674 9.855 29.106 9.99 ;
     RECT  29.16 9.855 29.484 9.99 ;
     RECT  29.646 9.855 30.024 9.99 ;
     RECT  30.078 9.855 31.59 9.99 ;
     RECT  31.644 9.855 33.48 9.99 ;
     RECT  33.588 9.855 34.02 9.99 ;
     RECT  35.154 9.855 35.964 9.99 ;
     RECT  36.018 9.855 36.774 9.99 ;
     RECT  36.828 9.855 37.692 9.99 ;
     RECT  37.8 9.855 38.124 9.99 ;
     RECT  38.232 9.855 39.042 9.99 ;
     RECT  39.15 9.855 40.392 9.99 ;
     RECT  40.608 9.855 41.04 9.99 ;
     RECT  41.958 9.855 42.822 9.99 ;
     RECT  42.876 9.855 43.686 9.99 ;
     RECT  43.74 9.855 44.55 9.99 ;
     RECT  44.658 9.855 45.954 9.99 ;
     RECT  46.17 9.855 46.548 9.99 ;
     RECT  46.71 9.855 52.542 9.99 ;
     RECT  52.596 9.855 53.028 9.99 ;
     RECT  54.486 9.855 54.81 9.99 ;
     RECT  55.134 9.855 55.944 9.99 ;
     RECT  55.998 9.855 61.344 9.99 ;
     RECT  61.398 9.855 62.64 9.99 ;
     RECT  62.964 9.855 63.342 9.99 ;
     RECT  63.396 9.855 63.774 9.99 ;
     RECT  64.044 9.855 64.368 9.99 ;
     RECT  68.04 9.855 68.58 9.99 ;
     RECT  68.688 9.855 69.336 9.99 ;
     RECT  69.498 9.855 70.146 9.99 ;
     RECT  70.2 9.855 70.524 9.99 ;
     RECT  70.578 9.855 71.388 9.99 ;
     RECT  71.442 9.855 74.79 9.99 ;
     RECT  75.006 9.855 75.384 9.99 ;
     RECT  75.438 9.855 76.194 9.99 ;
     RECT  76.464 9.855 80.352 9.99 ;
     RECT  80.46 9.855 81.324 9.99 ;
     RECT  81.378 9.855 82.188 9.99 ;
     RECT  82.296 9.855 82.728 9.99 ;
     RECT  82.944 9.855 84.348 9.99 ;
     RECT  84.456 9.855 85.698 9.99 ;
     RECT  85.806 9.855 88.722 9.99 ;
     RECT  88.938 9.855 89.316 9.99 ;
     RECT  90.018 9.855 90.396 9.99 ;
     RECT  90.828 9.855 93.204 9.99 ;
     RECT  93.366 9.855 93.798 9.99 ;
     RECT  93.852 9.855 95.904 9.99 ;
     RECT  96.12 9.855 100.548 9.99 ;
     RECT  100.656 9.855 101.358 9.99 ;
     RECT  101.52 9.855 101.898 9.99 ;
     RECT  102.546 9.855 102.87 9.99 ;
     RECT  104.868 9.855 105.948 9.99 ;
     RECT  106.272 9.855 106.596 9.99 ;
     RECT  107.136 9.855 107.676 9.99 ;
     RECT  107.784 9.855 108.108 9.99 ;
     RECT  108.216 9.855 108.54 9.99 ;
     RECT  108.648 9.855 108.81 9.99 ;
     RECT  108.918 9.855 109.242 9.99 ;
     RECT  110.592 9.855 111.24 9.99 ;
     RECT  111.672 9.855 111.996 9.99 ;
     RECT  112.32 9.855 112.644 9.99 ;
     RECT  113.292 9.855 113.562 9.99 ;
     RECT  113.994 9.855 116.046 9.99 ;
     RECT  117.018 9.855 117.666 9.99 ;
     RECT  119.34 9.855 120.582 9.99 ;
     RECT  120.852 9.855 121.176 9.99 ;
     RECT  121.716 9.855 122.958 9.99 ;
     RECT  123.012 9.855 123.174 9.99 ;
     RECT  126.9 9.855 127.008 9.99 ;
     RECT  2.16 9.855 2.268 10.125 ;
     RECT  12.96 9.99 14.202 10.125 ;
     RECT  14.31 9.99 15.39 10.125 ;
     RECT  16.038 9.99 16.362 10.125 ;
     RECT  16.47 9.99 16.632 10.125 ;
     RECT  16.794 9.99 17.874 10.125 ;
     RECT  18.036 9.99 18.198 10.125 ;
     RECT  18.738 9.99 19.062 10.125 ;
     RECT  19.98 9.99 20.304 10.125 ;
     RECT  20.682 9.99 21.33 10.125 ;
     RECT  21.384 9.99 21.708 10.125 ;
     RECT  21.816 9.99 22.356 10.125 ;
     RECT  22.842 9.99 23.166 10.125 ;
     RECT  23.22 9.99 23.76 10.125 ;
     RECT  23.922 9.99 25.11 10.125 ;
     RECT  25.164 9.99 25.704 10.125 ;
     RECT  25.974 9.99 27.756 10.125 ;
     RECT  27.81 9.99 29.916 10.125 ;
     RECT  30.078 9.99 30.456 10.125 ;
     RECT  30.51 9.99 31.32 10.125 ;
     RECT  31.374 9.99 31.806 10.125 ;
     RECT  31.86 9.99 32.238 10.125 ;
     RECT  32.292 9.99 32.616 10.125 ;
     RECT  32.724 9.99 33.966 10.125 ;
     RECT  34.938 9.99 35.37 10.125 ;
     RECT  35.424 9.99 36.18 10.125 ;
     RECT  36.288 9.99 38.34 10.125 ;
     RECT  38.448 9.99 39.69 10.125 ;
     RECT  39.798 9.99 40.122 10.125 ;
     RECT  40.23 9.99 40.662 10.125 ;
     RECT  40.824 9.99 41.148 10.125 ;
     RECT  41.202 9.99 43.848 10.125 ;
     RECT  43.956 9.99 45.144 10.125 ;
     RECT  45.522 9.99 45.846 10.125 ;
     RECT  46.17 9.99 47.304 10.125 ;
     RECT  47.358 9.99 49.68 10.125 ;
     RECT  49.734 9.99 50.49 10.125 ;
     RECT  50.544 9.99 50.976 10.125 ;
     RECT  51.084 9.99 51.84 10.125 ;
     RECT  52.056 9.99 53.352 10.125 ;
     RECT  54.54 9.99 54.972 10.125 ;
     RECT  55.296 9.99 56.592 10.125 ;
     RECT  56.646 9.99 57.456 10.125 ;
     RECT  57.51 9.99 57.834 10.125 ;
     RECT  57.942 9.99 58.32 10.125 ;
     RECT  58.374 9.99 58.806 10.125 ;
     RECT  58.968 9.99 59.292 10.125 ;
     RECT  59.346 9.99 59.724 10.125 ;
     RECT  59.778 9.99 60.534 10.125 ;
     RECT  60.75 9.99 61.29 10.125 ;
     RECT  61.398 9.99 62.586 10.125 ;
     RECT  62.64 9.99 64.044 10.125 ;
     RECT  64.26 9.99 64.8 10.125 ;
     RECT  68.094 9.99 71.01 10.125 ;
     RECT  71.118 9.99 71.55 10.125 ;
     RECT  71.658 9.99 72.414 10.125 ;
     RECT  72.468 9.99 73.278 10.125 ;
     RECT  73.332 9.99 73.764 10.125 ;
     RECT  73.926 9.99 75.87 10.125 ;
     RECT  76.086 9.99 77.976 10.125 ;
     RECT  78.03 9.99 80.892 10.125 ;
     RECT  81 9.99 82.134 10.125 ;
     RECT  82.188 9.99 82.62 10.125 ;
     RECT  82.674 9.99 84.51 10.125 ;
     RECT  84.726 9.99 85.104 10.125 ;
     RECT  85.212 9.99 85.59 10.125 ;
     RECT  85.698 9.99 87.642 10.125 ;
     RECT  87.75 9.99 89.37 10.125 ;
     RECT  90.504 9.99 95.148 10.125 ;
     RECT  95.202 9.99 96.822 10.125 ;
     RECT  96.876 9.99 97.308 10.125 ;
     RECT  97.362 9.99 98.118 10.125 ;
     RECT  98.172 9.99 99.306 10.125 ;
     RECT  99.36 9.99 99.684 10.125 ;
     RECT  99.738 9.99 100.872 10.125 ;
     RECT  100.926 9.99 101.358 10.125 ;
     RECT  101.52 9.99 102.06 10.125 ;
     RECT  102.33 9.99 102.654 10.125 ;
     RECT  102.978 9.99 103.302 10.125 ;
     RECT  103.356 9.99 104.004 10.125 ;
     RECT  105.138 9.99 105.462 10.125 ;
     RECT  106.65 9.99 106.974 10.125 ;
     RECT  107.73 9.99 108.216 10.125 ;
     RECT  108.702 9.99 109.026 10.125 ;
     RECT  110.862 9.99 111.186 10.125 ;
     RECT  111.348 9.99 111.51 10.125 ;
     RECT  112.05 9.99 112.374 10.125 ;
     RECT  113.076 9.99 113.4 10.125 ;
     RECT  113.994 9.99 114.318 10.125 ;
     RECT  115.56 9.99 115.884 10.125 ;
     RECT  116.478 9.99 116.64 10.125 ;
     RECT  117.558 9.99 117.72 10.125 ;
     RECT  118.746 9.99 119.07 10.125 ;
     RECT  119.394 9.99 120.042 10.125 ;
     RECT  120.096 9.99 120.42 10.125 ;
     RECT  120.528 9.99 120.69 10.125 ;
     RECT  120.96 9.99 121.446 10.125 ;
     RECT  121.824 9.99 122.148 10.125 ;
     RECT  122.364 9.99 124.092 10.125 ;
     RECT  127.332 9.855 127.44 10.125 ;
     RECT  12.744 10.395 14.148 10.53 ;
     RECT  15.282 10.395 15.444 10.53 ;
     RECT  19.062 10.395 20.466 10.53 ;
     RECT  22.194 10.395 22.518 10.53 ;
     RECT  23.004 10.395 23.328 10.53 ;
     RECT  23.598 10.395 24.462 10.53 ;
     RECT  24.57 10.395 24.894 10.53 ;
     RECT  25.002 10.395 25.434 10.53 ;
     RECT  25.596 10.395 25.974 10.53 ;
     RECT  26.136 10.395 26.946 10.53 ;
     RECT  27.108 10.395 28.512 10.53 ;
     RECT  28.62 10.395 30.078 10.53 ;
     RECT  30.132 10.395 32.886 10.53 ;
     RECT  32.94 10.395 33.264 10.53 ;
     RECT  33.372 10.395 34.236 10.53 ;
     RECT  34.992 10.395 35.802 10.53 ;
     RECT  36.18 10.395 37.422 10.53 ;
     RECT  37.476 10.395 38.502 10.53 ;
     RECT  38.88 10.395 40.014 10.53 ;
     RECT  40.122 10.395 40.5 10.53 ;
     RECT  41.31 10.395 42.876 10.53 ;
     RECT  42.93 10.395 45.306 10.53 ;
     RECT  45.36 10.395 45.738 10.53 ;
     RECT  45.954 10.395 47.52 10.53 ;
     RECT  47.898 10.395 48.276 10.53 ;
     RECT  48.33 10.395 48.654 10.53 ;
     RECT  48.816 10.395 49.572 10.53 ;
     RECT  49.626 10.395 51.3 10.53 ;
     RECT  51.354 10.395 51.786 10.53 ;
     RECT  51.84 10.395 52.542 10.53 ;
     RECT  52.596 10.395 53.352 10.53 ;
     RECT  54.216 10.395 54.648 10.53 ;
     RECT  55.08 10.395 55.944 10.53 ;
     RECT  56.106 10.395 56.538 10.53 ;
     RECT  56.862 10.395 57.186 10.53 ;
     RECT  57.24 10.395 58.374 10.53 ;
     RECT  58.59 10.395 60.21 10.53 ;
     RECT  60.318 10.395 60.75 10.53 ;
     RECT  60.858 10.395 61.236 10.53 ;
     RECT  61.344 10.395 62.424 10.53 ;
     RECT  62.586 10.395 62.91 10.53 ;
     RECT  63.288 10.395 64.584 10.53 ;
     RECT  64.692 10.395 65.556 10.53 ;
     RECT  67.932 10.395 69.012 10.53 ;
     RECT  69.12 10.395 69.984 10.53 ;
     RECT  70.038 10.395 70.362 10.53 ;
     RECT  70.47 10.395 71.334 10.53 ;
     RECT  71.388 10.395 72.144 10.53 ;
     RECT  72.198 10.395 72.738 10.53 ;
     RECT  72.9 10.395 73.44 10.53 ;
     RECT  73.494 10.395 75.114 10.53 ;
     RECT  75.384 10.395 75.762 10.53 ;
     RECT  75.816 10.395 77.436 10.53 ;
     RECT  77.544 10.395 78.948 10.53 ;
     RECT  79.002 10.395 80.19 10.53 ;
     RECT  80.298 10.395 82.566 10.53 ;
     RECT  82.674 10.395 83.97 10.53 ;
     RECT  84.024 10.395 85.158 10.53 ;
     RECT  85.212 10.395 85.968 10.53 ;
     RECT  86.022 10.395 86.67 10.53 ;
     RECT  86.832 10.395 88.614 10.53 ;
     RECT  89.262 10.395 89.694 10.53 ;
     RECT  90.504 10.395 90.882 10.53 ;
     RECT  90.99 10.395 92.178 10.53 ;
     RECT  92.34 10.395 93.798 10.53 ;
     RECT  93.852 10.395 95.85 10.53 ;
     RECT  96.012 10.395 96.768 10.53 ;
     RECT  96.876 10.395 97.2 10.53 ;
     RECT  97.308 10.395 98.118 10.53 ;
     RECT  98.28 10.395 98.712 10.53 ;
     RECT  98.766 10.395 99.198 10.53 ;
     RECT  99.252 10.395 102.06 10.53 ;
     RECT  102.114 10.395 103.734 10.53 ;
     RECT  103.95 10.395 104.49 10.53 ;
     RECT  106.596 10.395 106.758 10.53 ;
     RECT  106.974 10.395 107.298 10.53 ;
     RECT  107.784 10.395 108.108 10.53 ;
     RECT  108.756 10.395 109.08 10.53 ;
     RECT  109.134 10.395 110.214 10.53 ;
     RECT  110.592 10.395 110.754 10.53 ;
     RECT  111.24 10.395 111.564 10.53 ;
     RECT  111.726 10.395 112.806 10.53 ;
     RECT  114.264 10.395 114.588 10.53 ;
     RECT  115.506 10.395 116.586 10.53 ;
     RECT  118.044 10.395 118.692 10.53 ;
     RECT  119.502 10.395 119.826 10.53 ;
     RECT  120.852 10.395 121.932 10.53 ;
     RECT  122.742 10.395 123.066 10.53 ;
     RECT  2.16 10.395 2.268 10.665 ;
     RECT  19.494 10.53 20.574 10.665 ;
     RECT  20.736 10.53 21.276 10.665 ;
     RECT  21.384 10.53 21.924 10.665 ;
     RECT  22.302 10.53 22.842 10.665 ;
     RECT  23.058 10.53 24.138 10.665 ;
     RECT  24.192 10.53 24.732 10.665 ;
     RECT  24.84 10.53 25.38 10.665 ;
     RECT  25.65 10.53 26.19 10.665 ;
     RECT  26.46 10.53 27.918 10.665 ;
     RECT  27.972 10.53 29.052 10.665 ;
     RECT  29.106 10.53 29.916 10.665 ;
     RECT  30.024 10.53 30.402 10.665 ;
     RECT  30.51 10.53 32.022 10.665 ;
     RECT  32.076 10.53 32.832 10.665 ;
     RECT  33.102 10.53 33.642 10.665 ;
     RECT  36.018 10.53 36.99 10.665 ;
     RECT  37.098 10.53 37.476 10.665 ;
     RECT  37.692 10.53 38.07 10.665 ;
     RECT  38.178 10.53 38.988 10.665 ;
     RECT  39.096 10.53 39.528 10.665 ;
     RECT  39.636 10.53 40.014 10.665 ;
     RECT  40.176 10.53 40.986 10.665 ;
     RECT  41.148 10.53 42.174 10.665 ;
     RECT  42.282 10.53 42.822 10.665 ;
     RECT  42.876 10.53 43.578 10.665 ;
     RECT  43.848 10.53 44.28 10.665 ;
     RECT  44.442 10.53 44.82 10.665 ;
     RECT  45.09 10.53 47.412 10.665 ;
     RECT  47.628 10.53 48.06 10.665 ;
     RECT  48.168 10.53 48.546 10.665 ;
     RECT  48.654 10.53 49.032 10.665 ;
     RECT  49.14 10.53 50.274 10.665 ;
     RECT  50.544 10.53 50.922 10.665 ;
     RECT  51.192 10.53 51.57 10.665 ;
     RECT  51.732 10.53 52.704 10.665 ;
     RECT  52.758 10.53 53.298 10.665 ;
     RECT  55.026 10.53 56.376 10.665 ;
     RECT  56.592 10.53 57.402 10.665 ;
     RECT  57.51 10.53 57.888 10.665 ;
     RECT  58.374 10.53 58.698 10.665 ;
     RECT  58.914 10.53 59.292 10.665 ;
     RECT  59.346 10.53 60.642 10.665 ;
     RECT  60.804 10.53 61.56 10.665 ;
     RECT  61.938 10.53 63.018 10.665 ;
     RECT  63.072 10.53 63.396 10.665 ;
     RECT  63.45 10.53 64.854 10.665 ;
     RECT  68.202 10.53 68.742 10.665 ;
     RECT  69.228 10.53 71.658 10.665 ;
     RECT  71.712 10.53 73.17 10.665 ;
     RECT  73.224 10.53 74.034 10.665 ;
     RECT  74.142 10.53 74.466 10.665 ;
     RECT  74.52 10.53 75.708 10.665 ;
     RECT  75.762 10.53 76.896 10.665 ;
     RECT  77.004 10.53 78.516 10.665 ;
     RECT  78.678 10.53 81.54 10.665 ;
     RECT  81.81 10.53 82.242 10.665 ;
     RECT  82.404 10.53 84.24 10.665 ;
     RECT  84.402 10.53 85.212 10.665 ;
     RECT  85.374 10.53 86.13 10.665 ;
     RECT  86.886 10.53 87.588 10.665 ;
     RECT  87.642 10.53 88.02 10.665 ;
     RECT  88.614 10.53 88.992 10.665 ;
     RECT  90.234 10.53 91.098 10.665 ;
     RECT  91.152 10.53 92.88 10.665 ;
     RECT  92.988 10.53 93.744 10.665 ;
     RECT  93.906 10.53 95.904 10.665 ;
     RECT  96.066 10.53 97.362 10.665 ;
     RECT  97.524 10.53 97.956 10.665 ;
     RECT  98.01 10.53 98.442 10.665 ;
     RECT  98.55 10.53 98.982 10.665 ;
     RECT  99.09 10.53 100.008 10.665 ;
     RECT  100.224 10.53 100.764 10.665 ;
     RECT  101.088 10.53 103.68 10.665 ;
     RECT  104.004 10.53 104.868 10.665 ;
     RECT  105.03 10.53 105.894 10.665 ;
     RECT  106.326 10.53 107.19 10.665 ;
     RECT  107.946 10.53 109.026 10.665 ;
     RECT  109.188 10.53 110.052 10.665 ;
     RECT  110.322 10.53 111.186 10.665 ;
     RECT  111.456 10.53 111.996 10.665 ;
     RECT  112.266 10.53 113.67 10.665 ;
     RECT  118.206 10.53 118.368 10.665 ;
     RECT  118.53 10.53 119.61 10.665 ;
     RECT  126.9 10.395 127.008 10.665 ;
     RECT  127.332 10.395 127.44 10.665 ;
    LAYER M1 ;
     RECT  2.16 2.151 127.44 10.809 ;
    LAYER M2 ;
     RECT  2.16 2.151 127.44 10.809 ;
    LAYER M3 ;
     RECT  2.415 2.143 2.505 2.413 ;
     RECT  7.815 2.143 7.905 2.413 ;
     RECT  13.215 2.143 13.305 2.413 ;
     RECT  18.615 2.143 18.705 2.413 ;
     RECT  24.015 2.143 24.105 2.413 ;
     RECT  29.415 2.143 29.505 2.413 ;
     RECT  34.815 2.143 34.905 2.413 ;
     RECT  40.215 2.143 40.305 2.413 ;
     RECT  45.615 2.143 45.705 2.413 ;
     RECT  51.015 2.143 51.105 2.413 ;
     RECT  56.415 2.143 56.505 2.413 ;
     RECT  61.815 2.143 61.905 2.413 ;
     RECT  67.215 2.143 67.305 2.413 ;
     RECT  72.615 2.143 72.705 2.413 ;
     RECT  78.015 2.143 78.105 2.413 ;
     RECT  83.415 2.143 83.505 2.413 ;
     RECT  88.815 2.143 88.905 2.413 ;
     RECT  94.215 2.143 94.305 2.413 ;
     RECT  99.615 2.143 99.705 2.413 ;
     RECT  105.015 2.143 105.105 2.413 ;
     RECT  110.415 2.143 110.505 2.413 ;
     RECT  115.815 2.143 115.905 2.413 ;
     RECT  121.215 2.143 121.305 2.413 ;
     RECT  126.615 2.143 126.705 2.413 ;
     RECT  2.415 2.413 2.697 10.547 ;
     RECT  7.815 2.413 8.097 10.547 ;
     RECT  13.215 2.413 13.497 10.547 ;
     RECT  18.615 2.413 18.897 10.547 ;
     RECT  24.015 2.413 24.297 10.547 ;
     RECT  29.415 2.413 29.697 10.547 ;
     RECT  34.815 2.413 35.097 10.547 ;
     RECT  40.215 2.413 40.497 10.547 ;
     RECT  45.615 2.413 45.897 10.547 ;
     RECT  51.015 2.413 51.297 10.547 ;
     RECT  56.415 2.413 56.697 10.547 ;
     RECT  61.815 2.413 62.097 10.547 ;
     RECT  67.215 2.413 67.497 10.547 ;
     RECT  72.615 2.413 72.897 10.547 ;
     RECT  78.015 2.413 78.297 10.547 ;
     RECT  83.415 2.413 83.697 10.547 ;
     RECT  88.815 2.413 89.097 10.547 ;
     RECT  94.215 2.413 94.497 10.547 ;
     RECT  99.615 2.413 99.897 10.547 ;
     RECT  105.015 2.413 105.297 10.547 ;
     RECT  110.415 2.413 110.697 10.547 ;
     RECT  115.815 2.413 116.097 10.547 ;
     RECT  121.215 2.413 121.497 10.547 ;
     RECT  126.615 2.413 126.897 10.547 ;
     RECT  2.415 10.547 2.505 10.817 ;
     RECT  7.815 10.547 7.905 10.817 ;
     RECT  13.215 10.547 13.305 10.817 ;
     RECT  18.615 10.547 18.705 10.817 ;
     RECT  24.015 10.547 24.105 10.817 ;
     RECT  29.415 10.547 29.505 10.817 ;
     RECT  34.815 10.547 34.905 10.817 ;
     RECT  40.215 10.547 40.305 10.817 ;
     RECT  45.615 10.547 45.705 10.817 ;
     RECT  51.015 10.547 51.105 10.817 ;
     RECT  56.415 10.547 56.505 10.817 ;
     RECT  61.815 10.547 61.905 10.817 ;
     RECT  67.215 10.547 67.305 10.817 ;
     RECT  72.615 10.547 72.705 10.817 ;
     RECT  78.015 10.547 78.105 10.817 ;
     RECT  83.415 10.547 83.505 10.817 ;
     RECT  88.815 10.547 88.905 10.817 ;
     RECT  94.215 10.547 94.305 10.817 ;
     RECT  99.615 10.547 99.705 10.817 ;
     RECT  105.015 10.547 105.105 10.817 ;
     RECT  110.415 10.547 110.505 10.817 ;
     RECT  115.815 10.547 115.905 10.817 ;
     RECT  121.215 10.547 121.305 10.817 ;
     RECT  126.615 10.547 126.705 10.817 ;
    LAYER M4 ;
     RECT  2.408 2.148 2.512 10.812 ;
     RECT  2.512 2.418 2.704 10.542 ;
     RECT  7.808 2.148 7.912 10.812 ;
     RECT  7.912 2.418 8.104 10.542 ;
     RECT  13.208 2.148 13.312 10.812 ;
     RECT  13.312 2.418 13.504 10.542 ;
     RECT  18.608 2.148 18.712 10.812 ;
     RECT  18.712 2.418 18.904 10.542 ;
     RECT  24.008 2.148 24.112 10.812 ;
     RECT  24.112 2.418 24.304 10.542 ;
     RECT  29.408 2.148 29.512 10.812 ;
     RECT  29.512 2.418 29.704 10.542 ;
     RECT  34.808 2.148 34.912 10.812 ;
     RECT  34.912 2.418 35.104 10.542 ;
     RECT  40.208 2.148 40.312 10.812 ;
     RECT  40.312 2.418 40.504 10.542 ;
     RECT  45.608 2.148 45.712 10.812 ;
     RECT  45.712 2.418 45.904 10.542 ;
     RECT  51.008 2.148 51.112 10.812 ;
     RECT  51.112 2.418 51.304 10.542 ;
     RECT  56.408 2.148 56.512 10.812 ;
     RECT  56.512 2.418 56.704 10.542 ;
     RECT  61.808 2.148 61.912 10.812 ;
     RECT  61.912 2.418 62.104 10.542 ;
     RECT  67.208 2.148 67.312 10.812 ;
     RECT  67.312 2.418 67.504 10.542 ;
     RECT  72.608 2.148 72.712 10.812 ;
     RECT  72.712 2.418 72.904 10.542 ;
     RECT  78.008 2.148 78.112 10.812 ;
     RECT  78.112 2.418 78.304 10.542 ;
     RECT  83.408 2.148 83.512 10.812 ;
     RECT  83.512 2.418 83.704 10.542 ;
     RECT  88.808 2.148 88.912 10.812 ;
     RECT  88.912 2.418 89.104 10.542 ;
     RECT  94.208 2.148 94.312 10.812 ;
     RECT  94.312 2.418 94.504 10.542 ;
     RECT  99.608 2.148 99.712 10.812 ;
     RECT  99.712 2.418 99.904 10.542 ;
     RECT  105.008 2.148 105.112 10.812 ;
     RECT  105.112 2.418 105.304 10.542 ;
     RECT  110.408 2.148 110.512 10.812 ;
     RECT  110.512 2.418 110.704 10.542 ;
     RECT  115.808 2.148 115.912 10.812 ;
     RECT  115.912 2.418 116.104 10.542 ;
     RECT  121.208 2.148 121.312 10.812 ;
     RECT  121.312 2.418 121.504 10.542 ;
     RECT  126.608 2.148 126.712 10.812 ;
     RECT  126.712 2.418 126.904 10.542 ;
    LAYER M5 ;
     RECT  2.4 2.137 2.52 2.151 ;
     RECT  7.8 2.137 7.92 2.151 ;
     RECT  13.2 2.137 13.32 2.151 ;
     RECT  18.6 2.137 18.72 2.151 ;
     RECT  24 2.137 24.12 2.151 ;
     RECT  29.4 2.137 29.52 2.151 ;
     RECT  34.8 2.137 34.92 2.151 ;
     RECT  40.2 2.137 40.32 2.151 ;
     RECT  45.6 2.137 45.72 2.151 ;
     RECT  51 2.137 51.12 2.151 ;
     RECT  56.4 2.137 56.52 2.151 ;
     RECT  61.8 2.137 61.92 2.151 ;
     RECT  67.2 2.137 67.32 2.151 ;
     RECT  72.6 2.137 72.72 2.151 ;
     RECT  78 2.137 78.12 2.151 ;
     RECT  83.4 2.137 83.52 2.151 ;
     RECT  88.8 2.137 88.92 2.151 ;
     RECT  94.2 2.137 94.32 2.151 ;
     RECT  99.6 2.137 99.72 2.151 ;
     RECT  105 2.137 105.12 2.151 ;
     RECT  110.4 2.137 110.52 2.151 ;
     RECT  115.8 2.137 115.92 2.151 ;
     RECT  121.2 2.137 121.32 2.151 ;
     RECT  126.6 2.137 126.72 2.151 ;
     RECT  2.4 2.151 2.712 10.809 ;
     RECT  7.8 2.151 8.112 10.809 ;
     RECT  13.2 2.151 13.512 10.809 ;
     RECT  18.6 2.151 18.912 10.809 ;
     RECT  24 2.151 24.312 10.809 ;
     RECT  29.4 2.151 29.712 10.809 ;
     RECT  34.8 2.151 35.112 10.809 ;
     RECT  40.2 2.151 40.512 10.809 ;
     RECT  45.6 2.151 45.912 10.809 ;
     RECT  51 2.151 51.312 10.809 ;
     RECT  56.4 2.151 56.712 10.809 ;
     RECT  61.8 2.151 62.112 10.809 ;
     RECT  67.2 2.151 67.512 10.809 ;
     RECT  72.6 2.151 72.912 10.809 ;
     RECT  78 2.151 78.312 10.809 ;
     RECT  83.4 2.151 83.712 10.809 ;
     RECT  88.8 2.151 89.112 10.809 ;
     RECT  94.2 2.151 94.512 10.809 ;
     RECT  99.6 2.151 99.912 10.809 ;
     RECT  105 2.151 105.312 10.809 ;
     RECT  110.4 2.151 110.712 10.809 ;
     RECT  115.8 2.151 116.112 10.809 ;
     RECT  121.2 2.151 121.512 10.809 ;
     RECT  126.6 2.151 126.912 10.809 ;
     RECT  2.4 10.809 2.52 10.823 ;
     RECT  7.8 10.809 7.92 10.823 ;
     RECT  13.2 10.809 13.32 10.823 ;
     RECT  18.6 10.809 18.72 10.823 ;
     RECT  24 10.809 24.12 10.823 ;
     RECT  29.4 10.809 29.52 10.823 ;
     RECT  34.8 10.809 34.92 10.823 ;
     RECT  40.2 10.809 40.32 10.823 ;
     RECT  45.6 10.809 45.72 10.823 ;
     RECT  51 10.809 51.12 10.823 ;
     RECT  56.4 10.809 56.52 10.823 ;
     RECT  61.8 10.809 61.92 10.823 ;
     RECT  67.2 10.809 67.32 10.823 ;
     RECT  72.6 10.809 72.72 10.823 ;
     RECT  78 10.809 78.12 10.823 ;
     RECT  83.4 10.809 83.52 10.823 ;
     RECT  88.8 10.809 88.92 10.823 ;
     RECT  94.2 10.809 94.32 10.823 ;
     RECT  99.6 10.809 99.72 10.823 ;
     RECT  105 10.809 105.12 10.823 ;
     RECT  110.4 10.809 110.52 10.823 ;
     RECT  115.8 10.809 115.92 10.823 ;
     RECT  121.2 10.809 121.32 10.823 ;
     RECT  126.6 10.809 126.72 10.823 ;
  END
END ot_qfd_vm_face_sn_e1
END LIBRARY
